VERSION 5.8 ;
BUSBITCHARS "[]" ;
DIVIDERCHAR "/" ;
UNITS
    DATABASE MICRONS 1000 ;
END UNITS

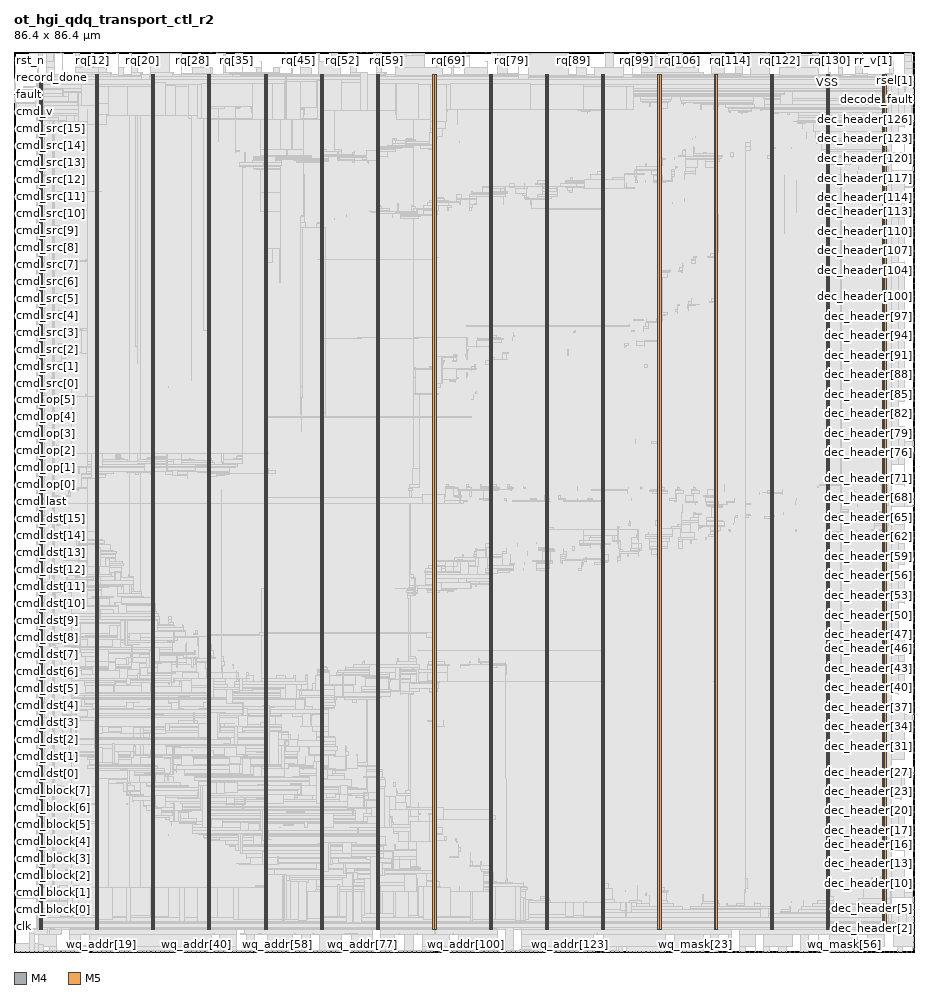
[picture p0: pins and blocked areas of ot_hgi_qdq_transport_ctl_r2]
MACRO ot_hgi_qdq_transport_ctl_r2
  FOREIGN ot_hgi_qdq_transport_ctl_r2 0 0 ;
  CLASS BLOCK ;
  SIZE 86.4 BY 86.4 ;
  PIN beat_done
    DIRECTION OUTPUT ;
    USE SIGNAL ;
    PORT
      LAYER M4 ;
        RECT  0 0.816 0.084 0.84 ;
    END
    PORT
      LAYER M4 ;
        RECT  0.06 0.816 0.181 0.84 ;
    END
  END beat_done
  PIN clk
    DIRECTION INPUT ;
    USE SIGNAL ;
    PORT
      LAYER M4 ;
        RECT  0 2.448 0.084 2.472 ;
    END
    PORT
      LAYER M4 ;
        RECT  0.06 2.448 0.227 2.472 ;
    END
  END clk
  PIN cmd_block[0]
    DIRECTION INPUT ;
    USE SIGNAL ;
    PORT
      LAYER M4 ;
        RECT  0 4.08 0.084 4.104 ;
    END
    PORT
      LAYER M4 ;
        RECT  0.06 4.08 0.097 4.104 ;
    END
  END cmd_block[0]
  PIN cmd_block[1]
    DIRECTION INPUT ;
    USE SIGNAL ;
    PORT
      LAYER M4 ;
        RECT  0 5.712 0.084 5.736 ;
    END
    PORT
      LAYER M4 ;
        RECT  0.06 5.712 0.277 5.736 ;
    END
  END cmd_block[1]
  PIN cmd_block[2]
    DIRECTION INPUT ;
    USE SIGNAL ;
    PORT
      LAYER M4 ;
        RECT  0 7.344 0.084 7.368 ;
    END
    PORT
      LAYER M4 ;
        RECT  0.06 7.344 2.408 7.368 ;
    END
  END cmd_block[2]
  PIN cmd_block[3]
    DIRECTION INPUT ;
    USE SIGNAL ;
    PORT
      LAYER M4 ;
        RECT  0 8.976 0.084 9 ;
    END
    PORT
      LAYER M4 ;
        RECT  0.06 8.976 2.408 9 ;
    END
  END cmd_block[3]
  PIN cmd_block[4]
    DIRECTION INPUT ;
    USE SIGNAL ;
    PORT
      LAYER M4 ;
        RECT  0 10.608 0.084 10.632 ;
    END
    PORT
      LAYER M4 ;
        RECT  0.06 10.608 2.408 10.632 ;
    END
  END cmd_block[4]
  PIN cmd_block[5]
    DIRECTION INPUT ;
    USE SIGNAL ;
    PORT
      LAYER M4 ;
        RECT  0 12.192 0.084 12.216 ;
    END
    PORT
      LAYER M4 ;
        RECT  0.06 12.192 2.408 12.216 ;
    END
  END cmd_block[5]
  PIN cmd_block[6]
    DIRECTION INPUT ;
    USE SIGNAL ;
    PORT
      LAYER M4 ;
        RECT  0 13.824 0.084 13.848 ;
    END
    PORT
      LAYER M4 ;
        RECT  0.06 13.824 2.408 13.848 ;
    END
  END cmd_block[6]
  PIN cmd_block[7]
    DIRECTION INPUT ;
    USE SIGNAL ;
    PORT
      LAYER M4 ;
        RECT  0 15.456 0.084 15.48 ;
    END
    PORT
      LAYER M4 ;
        RECT  0.06 15.456 2.408 15.48 ;
    END
  END cmd_block[7]
  PIN cmd_dst[0]
    DIRECTION INPUT ;
    USE SIGNAL ;
    PORT
      LAYER M4 ;
        RECT  0 17.088 0.084 17.112 ;
    END
    PORT
      LAYER M4 ;
        RECT  0.06 17.088 2.408 17.112 ;
    END
  END cmd_dst[0]
  PIN cmd_dst[10]
    DIRECTION INPUT ;
    USE SIGNAL ;
    PORT
      LAYER M4 ;
        RECT  0 33.408 0.084 33.432 ;
    END
    PORT
      LAYER M4 ;
        RECT  0.06 33.408 2.408 33.432 ;
    END
  END cmd_dst[10]
  PIN cmd_dst[11]
    DIRECTION INPUT ;
    USE SIGNAL ;
    PORT
      LAYER M4 ;
        RECT  0 35.04 0.084 35.064 ;
    END
    PORT
      LAYER M4 ;
        RECT  0.06 35.04 2.408 35.064 ;
    END
  END cmd_dst[11]
  PIN cmd_dst[12]
    DIRECTION INPUT ;
    USE SIGNAL ;
    PORT
      LAYER M4 ;
        RECT  0 36.672 0.084 36.696 ;
    END
    PORT
      LAYER M4 ;
        RECT  0.06 36.672 2.408 36.696 ;
    END
  END cmd_dst[12]
  PIN cmd_dst[13]
    DIRECTION INPUT ;
    USE SIGNAL ;
    PORT
      LAYER M4 ;
        RECT  0 38.304 0.084 38.328 ;
    END
    PORT
      LAYER M4 ;
        RECT  0.06 38.304 0.097 38.328 ;
    END
  END cmd_dst[13]
  PIN cmd_dst[14]
    DIRECTION INPUT ;
    USE SIGNAL ;
    PORT
      LAYER M4 ;
        RECT  0 39.936 0.084 39.96 ;
    END
    PORT
      LAYER M4 ;
        RECT  0.06 39.936 0.137 39.96 ;
    END
  END cmd_dst[14]
  PIN cmd_dst[15]
    DIRECTION INPUT ;
    USE SIGNAL ;
    PORT
      LAYER M4 ;
        RECT  0 41.568 0.084 41.592 ;
    END
    PORT
      LAYER M4 ;
        RECT  0.06 41.568 2.408 41.592 ;
    END
  END cmd_dst[15]
  PIN cmd_dst[1]
    DIRECTION INPUT ;
    USE SIGNAL ;
    PORT
      LAYER M4 ;
        RECT  0 18.72 0.084 18.744 ;
    END
    PORT
      LAYER M4 ;
        RECT  0.06 18.72 2.408 18.744 ;
    END
  END cmd_dst[1]
  PIN cmd_dst[2]
    DIRECTION INPUT ;
    USE SIGNAL ;
    PORT
      LAYER M4 ;
        RECT  0 20.352 0.084 20.376 ;
    END
    PORT
      LAYER M4 ;
        RECT  0.06 20.352 2.408 20.376 ;
    END
  END cmd_dst[2]
  PIN cmd_dst[3]
    DIRECTION INPUT ;
    USE SIGNAL ;
    PORT
      LAYER M4 ;
        RECT  0 21.984 0.084 22.008 ;
    END
    PORT
      LAYER M4 ;
        RECT  0.06 21.984 2.408 22.008 ;
    END
  END cmd_dst[3]
  PIN cmd_dst[4]
    DIRECTION INPUT ;
    USE SIGNAL ;
    PORT
      LAYER M4 ;
        RECT  0 23.616 0.084 23.64 ;
    END
    PORT
      LAYER M4 ;
        RECT  0.06 23.616 2.408 23.64 ;
    END
  END cmd_dst[4]
  PIN cmd_dst[5]
    DIRECTION INPUT ;
    USE SIGNAL ;
    PORT
      LAYER M4 ;
        RECT  0 25.248 0.084 25.272 ;
    END
    PORT
      LAYER M4 ;
        RECT  0.06 25.248 2.408 25.272 ;
    END
  END cmd_dst[5]
  PIN cmd_dst[6]
    DIRECTION INPUT ;
    USE SIGNAL ;
    PORT
      LAYER M4 ;
        RECT  0 26.88 0.084 26.904 ;
    END
    PORT
      LAYER M4 ;
        RECT  0.06 26.88 2.408 26.904 ;
    END
  END cmd_dst[6]
  PIN cmd_dst[7]
    DIRECTION INPUT ;
    USE SIGNAL ;
    PORT
      LAYER M4 ;
        RECT  0 28.512 0.084 28.536 ;
    END
    PORT
      LAYER M4 ;
        RECT  0.06 28.512 2.408 28.536 ;
    END
  END cmd_dst[7]
  PIN cmd_dst[8]
    DIRECTION INPUT ;
    USE SIGNAL ;
    PORT
      LAYER M4 ;
        RECT  0 30.144 0.084 30.168 ;
    END
    PORT
      LAYER M4 ;
        RECT  0.06 30.144 2.408 30.168 ;
    END
  END cmd_dst[8]
  PIN cmd_dst[9]
    DIRECTION INPUT ;
    USE SIGNAL ;
    PORT
      LAYER M4 ;
        RECT  0 31.776 0.084 31.8 ;
    END
    PORT
      LAYER M4 ;
        RECT  0.06 31.776 2.408 31.8 ;
    END
  END cmd_dst[9]
  PIN cmd_last
    DIRECTION INPUT ;
    USE SIGNAL ;
    PORT
      LAYER M4 ;
        RECT  0 43.2 0.084 43.224 ;
    END
    PORT
      LAYER M4 ;
        RECT  0.06 43.2 0.181 43.224 ;
    END
  END cmd_last
  PIN cmd_op[0]
    DIRECTION INPUT ;
    USE SIGNAL ;
    PORT
      LAYER M4 ;
        RECT  0 44.832 0.084 44.856 ;
    END
    PORT
      LAYER M4 ;
        RECT  0.06 44.832 2.408 44.856 ;
    END
  END cmd_op[0]
  PIN cmd_op[1]
    DIRECTION INPUT ;
    USE SIGNAL ;
    PORT
      LAYER M4 ;
        RECT  0 46.464 0.084 46.488 ;
    END
    PORT
      LAYER M4 ;
        RECT  0.06 46.464 2.408 46.488 ;
    END
  END cmd_op[1]
  PIN cmd_op[2]
    DIRECTION INPUT ;
    USE SIGNAL ;
    PORT
      LAYER M4 ;
        RECT  0 48.096 0.084 48.12 ;
    END
    PORT
      LAYER M4 ;
        RECT  0.06 48.096 2.408 48.12 ;
    END
  END cmd_op[2]
  PIN cmd_op[3]
    DIRECTION INPUT ;
    USE SIGNAL ;
    PORT
      LAYER M4 ;
        RECT  0 49.728 0.084 49.752 ;
    END
    PORT
      LAYER M4 ;
        RECT  0.06 49.728 2.408 49.752 ;
    END
  END cmd_op[3]
  PIN cmd_op[4]
    DIRECTION INPUT ;
    USE SIGNAL ;
    PORT
      LAYER M4 ;
        RECT  0 51.36 0.084 51.384 ;
    END
    PORT
      LAYER M4 ;
        RECT  0.06 51.36 2.408 51.384 ;
    END
  END cmd_op[4]
  PIN cmd_op[5]
    DIRECTION INPUT ;
    USE SIGNAL ;
    PORT
      LAYER M4 ;
        RECT  0 52.992 0.084 53.016 ;
    END
    PORT
      LAYER M4 ;
        RECT  0.06 52.992 2.408 53.016 ;
    END
  END cmd_op[5]
  PIN cmd_src[0]
    DIRECTION INPUT ;
    USE SIGNAL ;
    PORT
      LAYER M4 ;
        RECT  0 54.576 0.084 54.6 ;
    END
    PORT
      LAYER M4 ;
        RECT  0.06 54.576 2.408 54.6 ;
    END
  END cmd_src[0]
  PIN cmd_src[10]
    DIRECTION INPUT ;
    USE SIGNAL ;
    PORT
      LAYER M4 ;
        RECT  0 70.896 0.084 70.92 ;
    END
    PORT
      LAYER M4 ;
        RECT  0.06 70.896 2.408 70.92 ;
    END
  END cmd_src[10]
  PIN cmd_src[11]
    DIRECTION INPUT ;
    USE SIGNAL ;
    PORT
      LAYER M4 ;
        RECT  0 72.528 0.084 72.552 ;
    END
    PORT
      LAYER M4 ;
        RECT  0.06 72.528 2.408 72.552 ;
    END
  END cmd_src[11]
  PIN cmd_src[12]
    DIRECTION INPUT ;
    USE SIGNAL ;
    PORT
      LAYER M4 ;
        RECT  0 74.16 0.084 74.184 ;
    END
    PORT
      LAYER M4 ;
        RECT  0.06 74.16 2.408 74.184 ;
    END
  END cmd_src[12]
  PIN cmd_src[13]
    DIRECTION INPUT ;
    USE SIGNAL ;
    PORT
      LAYER M4 ;
        RECT  0 75.792 0.084 75.816 ;
    END
    PORT
      LAYER M4 ;
        RECT  0.06 75.792 2.408 75.816 ;
    END
  END cmd_src[13]
  PIN cmd_src[14]
    DIRECTION INPUT ;
    USE SIGNAL ;
    PORT
      LAYER M4 ;
        RECT  0 77.424 0.084 77.448 ;
    END
    PORT
      LAYER M4 ;
        RECT  0.06 77.424 2.408 77.448 ;
    END
  END cmd_src[14]
  PIN cmd_src[15]
    DIRECTION INPUT ;
    USE SIGNAL ;
    PORT
      LAYER M4 ;
        RECT  0 79.056 0.084 79.08 ;
    END
    PORT
      LAYER M4 ;
        RECT  0.06 79.056 2.408 79.08 ;
    END
  END cmd_src[15]
  PIN cmd_src[1]
    DIRECTION INPUT ;
    USE SIGNAL ;
    PORT
      LAYER M4 ;
        RECT  0 56.208 0.084 56.232 ;
    END
    PORT
      LAYER M4 ;
        RECT  0.06 56.208 2.408 56.232 ;
    END
  END cmd_src[1]
  PIN cmd_src[2]
    DIRECTION INPUT ;
    USE SIGNAL ;
    PORT
      LAYER M4 ;
        RECT  0 57.84 0.084 57.864 ;
    END
    PORT
      LAYER M4 ;
        RECT  0.06 57.84 2.408 57.864 ;
    END
  END cmd_src[2]
  PIN cmd_src[3]
    DIRECTION INPUT ;
    USE SIGNAL ;
    PORT
      LAYER M4 ;
        RECT  0 59.472 0.084 59.496 ;
    END
    PORT
      LAYER M4 ;
        RECT  0.06 59.472 2.408 59.496 ;
    END
  END cmd_src[3]
  PIN cmd_src[4]
    DIRECTION INPUT ;
    USE SIGNAL ;
    PORT
      LAYER M4 ;
        RECT  0 61.104 0.084 61.128 ;
    END
    PORT
      LAYER M4 ;
        RECT  0.06 61.104 2.408 61.128 ;
    END
  END cmd_src[4]
  PIN cmd_src[5]
    DIRECTION INPUT ;
    USE SIGNAL ;
    PORT
      LAYER M4 ;
        RECT  0 62.736 0.084 62.76 ;
    END
    PORT
      LAYER M4 ;
        RECT  0.06 62.736 2.408 62.76 ;
    END
  END cmd_src[5]
  PIN cmd_src[6]
    DIRECTION INPUT ;
    USE SIGNAL ;
    PORT
      LAYER M4 ;
        RECT  0 64.368 0.084 64.392 ;
    END
    PORT
      LAYER M4 ;
        RECT  0.06 64.368 2.408 64.392 ;
    END
  END cmd_src[6]
  PIN cmd_src[7]
    DIRECTION INPUT ;
    USE SIGNAL ;
    PORT
      LAYER M4 ;
        RECT  0 66 0.084 66.024 ;
    END
    PORT
      LAYER M4 ;
        RECT  0.06 66 2.408 66.024 ;
    END
  END cmd_src[7]
  PIN cmd_src[8]
    DIRECTION INPUT ;
    USE SIGNAL ;
    PORT
      LAYER M4 ;
        RECT  0 67.632 0.084 67.656 ;
    END
    PORT
      LAYER M4 ;
        RECT  0.06 67.632 2.408 67.656 ;
    END
  END cmd_src[8]
  PIN cmd_src[9]
    DIRECTION INPUT ;
    USE SIGNAL ;
    PORT
      LAYER M4 ;
        RECT  0 69.264 0.084 69.288 ;
    END
    PORT
      LAYER M4 ;
        RECT  0.06 69.264 2.408 69.288 ;
    END
  END cmd_src[9]
  PIN cmd_v
    DIRECTION INPUT ;
    USE SIGNAL ;
    PORT
      LAYER M4 ;
        RECT  0 80.688 0.084 80.712 ;
    END
    PORT
      LAYER M4 ;
        RECT  0.06 80.688 0.277 80.712 ;
    END
  END cmd_v
  PIN dec_header[0]
    DIRECTION OUTPUT ;
    USE SIGNAL ;
    PORT
      LAYER M4 ;
        RECT  86.316 0.288 86.4 0.312 ;
    END
  END dec_header[0]
  PIN dec_header[100]
    DIRECTION OUTPUT ;
    USE SIGNAL ;
    PORT
      LAYER M4 ;
        RECT  86.316 62.928 86.4 62.952 ;
    END
  END dec_header[100]
  PIN dec_header[101]
    DIRECTION OUTPUT ;
    USE SIGNAL ;
    PORT
      LAYER M4 ;
        RECT  86.316 63.552 86.4 63.576 ;
    END
  END dec_header[101]
  PIN dec_header[102]
    DIRECTION OUTPUT ;
    USE SIGNAL ;
    PORT
      LAYER M4 ;
        RECT  86.316 64.176 86.4 64.2 ;
    END
  END dec_header[102]
  PIN dec_header[103]
    DIRECTION OUTPUT ;
    USE SIGNAL ;
    PORT
      LAYER M4 ;
        RECT  86.316 64.8 86.4 64.824 ;
    END
  END dec_header[103]
  PIN dec_header[104]
    DIRECTION OUTPUT ;
    USE SIGNAL ;
    PORT
      LAYER M4 ;
        RECT  86.316 65.424 86.4 65.448 ;
    END
  END dec_header[104]
  PIN dec_header[105]
    DIRECTION OUTPUT ;
    USE SIGNAL ;
    PORT
      LAYER M4 ;
        RECT  86.316 66.048 86.4 66.072 ;
    END
  END dec_header[105]
  PIN dec_header[106]
    DIRECTION OUTPUT ;
    USE SIGNAL ;
    PORT
      LAYER M4 ;
        RECT  86.316 66.672 86.4 66.696 ;
    END
  END dec_header[106]
  PIN dec_header[107]
    DIRECTION OUTPUT ;
    USE SIGNAL ;
    PORT
      LAYER M4 ;
        RECT  86.316 67.296 86.4 67.32 ;
    END
  END dec_header[107]
  PIN dec_header[108]
    DIRECTION OUTPUT ;
    USE SIGNAL ;
    PORT
      LAYER M4 ;
        RECT  86.316 67.92 86.4 67.944 ;
    END
  END dec_header[108]
  PIN dec_header[109]
    DIRECTION OUTPUT ;
    USE SIGNAL ;
    PORT
      LAYER M4 ;
        RECT  86.316 68.544 86.4 68.568 ;
    END
  END dec_header[109]
  PIN dec_header[10]
    DIRECTION OUTPUT ;
    USE SIGNAL ;
    PORT
      LAYER M4 ;
        RECT  86.316 6.576 86.4 6.6 ;
    END
  END dec_header[10]
  PIN dec_header[110]
    DIRECTION OUTPUT ;
    USE SIGNAL ;
    PORT
      LAYER M4 ;
        RECT  86.316 69.168 86.4 69.192 ;
    END
  END dec_header[110]
  PIN dec_header[111]
    DIRECTION OUTPUT ;
    USE SIGNAL ;
    PORT
      LAYER M4 ;
        RECT  86.316 69.792 86.4 69.816 ;
    END
  END dec_header[111]
  PIN dec_header[112]
    DIRECTION OUTPUT ;
    USE SIGNAL ;
    PORT
      LAYER M4 ;
        RECT  86.316 70.416 86.4 70.44 ;
    END
  END dec_header[112]
  PIN dec_header[113]
    DIRECTION OUTPUT ;
    USE SIGNAL ;
    PORT
      LAYER M4 ;
        RECT  86.316 71.04 86.4 71.064 ;
    END
  END dec_header[113]
  PIN dec_header[114]
    DIRECTION OUTPUT ;
    USE SIGNAL ;
    PORT
      LAYER M4 ;
        RECT  86.316 71.664 86.4 71.688 ;
    END
  END dec_header[114]
  PIN dec_header[115]
    DIRECTION OUTPUT ;
    USE SIGNAL ;
    PORT
      LAYER M4 ;
        RECT  86.316 72.288 86.4 72.312 ;
    END
  END dec_header[115]
  PIN dec_header[116]
    DIRECTION OUTPUT ;
    USE SIGNAL ;
    PORT
      LAYER M4 ;
        RECT  86.316 72.912 86.4 72.936 ;
    END
  END dec_header[116]
  PIN dec_header[117]
    DIRECTION OUTPUT ;
    USE SIGNAL ;
    PORT
      LAYER M4 ;
        RECT  86.316 73.536 86.4 73.56 ;
    END
  END dec_header[117]
  PIN dec_header[118]
    DIRECTION OUTPUT ;
    USE SIGNAL ;
    PORT
      LAYER M4 ;
        RECT  86.316 74.16 86.4 74.184 ;
    END
  END dec_header[118]
  PIN dec_header[119]
    DIRECTION OUTPUT ;
    USE SIGNAL ;
    PORT
      LAYER M4 ;
        RECT  86.316 74.784 86.4 74.808 ;
    END
  END dec_header[119]
  PIN dec_header[11]
    DIRECTION OUTPUT ;
    USE SIGNAL ;
    PORT
      LAYER M4 ;
        RECT  86.316 7.2 86.4 7.224 ;
    END
  END dec_header[11]
  PIN dec_header[120]
    DIRECTION OUTPUT ;
    USE SIGNAL ;
    PORT
      LAYER M4 ;
        RECT  86.316 75.408 86.4 75.432 ;
    END
  END dec_header[120]
  PIN dec_header[121]
    DIRECTION OUTPUT ;
    USE SIGNAL ;
    PORT
      LAYER M4 ;
        RECT  86.316 76.08 86.4 76.104 ;
    END
  END dec_header[121]
  PIN dec_header[122]
    DIRECTION OUTPUT ;
    USE SIGNAL ;
    PORT
      LAYER M4 ;
        RECT  86.316 76.704 86.4 76.728 ;
    END
  END dec_header[122]
  PIN dec_header[123]
    DIRECTION OUTPUT ;
    USE SIGNAL ;
    PORT
      LAYER M4 ;
        RECT  86.316 77.328 86.4 77.352 ;
    END
  END dec_header[123]
  PIN dec_header[124]
    DIRECTION OUTPUT ;
    USE SIGNAL ;
    PORT
      LAYER M4 ;
        RECT  86.316 77.952 86.4 77.976 ;
    END
  END dec_header[124]
  PIN dec_header[125]
    DIRECTION OUTPUT ;
    USE SIGNAL ;
    PORT
      LAYER M4 ;
        RECT  86.316 78.576 86.4 78.6 ;
    END
  END dec_header[125]
  PIN dec_header[126]
    DIRECTION OUTPUT ;
    USE SIGNAL ;
    PORT
      LAYER M4 ;
        RECT  86.316 79.2 86.4 79.224 ;
    END
  END dec_header[126]
  PIN dec_header[127]
    DIRECTION OUTPUT ;
    USE SIGNAL ;
    PORT
      LAYER M4 ;
        RECT  86.316 79.824 86.4 79.848 ;
    END
  END dec_header[127]
  PIN dec_header[12]
    DIRECTION OUTPUT ;
    USE SIGNAL ;
    PORT
      LAYER M4 ;
        RECT  86.316 7.824 86.4 7.848 ;
    END
  END dec_header[12]
  PIN dec_header[13]
    DIRECTION OUTPUT ;
    USE SIGNAL ;
    PORT
      LAYER M4 ;
        RECT  86.316 8.448 86.4 8.472 ;
    END
  END dec_header[13]
  PIN dec_header[14]
    DIRECTION OUTPUT ;
    USE SIGNAL ;
    PORT
      LAYER M4 ;
        RECT  86.316 9.072 86.4 9.096 ;
    END
  END dec_header[14]
  PIN dec_header[15]
    DIRECTION OUTPUT ;
    USE SIGNAL ;
    PORT
      LAYER M4 ;
        RECT  86.316 9.696 86.4 9.72 ;
    END
  END dec_header[15]
  PIN dec_header[16]
    DIRECTION OUTPUT ;
    USE SIGNAL ;
    PORT
      LAYER M4 ;
        RECT  86.316 10.32 86.4 10.344 ;
    END
  END dec_header[16]
  PIN dec_header[17]
    DIRECTION OUTPUT ;
    USE SIGNAL ;
    PORT
      LAYER M4 ;
        RECT  86.316 10.944 86.4 10.968 ;
    END
  END dec_header[17]
  PIN dec_header[18]
    DIRECTION OUTPUT ;
    USE SIGNAL ;
    PORT
      LAYER M4 ;
        RECT  86.316 11.568 86.4 11.592 ;
    END
  END dec_header[18]
  PIN dec_header[19]
    DIRECTION OUTPUT ;
    USE SIGNAL ;
    PORT
      LAYER M4 ;
        RECT  86.316 12.192 86.4 12.216 ;
    END
  END dec_header[19]
  PIN dec_header[1]
    DIRECTION OUTPUT ;
    USE SIGNAL ;
    PORT
      LAYER M4 ;
        RECT  86.316 0.912 86.4 0.936 ;
    END
  END dec_header[1]
  PIN dec_header[20]
    DIRECTION OUTPUT ;
    USE SIGNAL ;
    PORT
      LAYER M4 ;
        RECT  86.316 12.816 86.4 12.84 ;
    END
  END dec_header[20]
  PIN dec_header[21]
    DIRECTION OUTPUT ;
    USE SIGNAL ;
    PORT
      LAYER M4 ;
        RECT  86.316 13.44 86.4 13.464 ;
    END
  END dec_header[21]
  PIN dec_header[22]
    DIRECTION OUTPUT ;
    USE SIGNAL ;
    PORT
      LAYER M4 ;
        RECT  86.316 14.064 86.4 14.088 ;
    END
  END dec_header[22]
  PIN dec_header[23]
    DIRECTION OUTPUT ;
    USE SIGNAL ;
    PORT
      LAYER M4 ;
        RECT  86.316 14.688 86.4 14.712 ;
    END
  END dec_header[23]
  PIN dec_header[24]
    DIRECTION OUTPUT ;
    USE SIGNAL ;
    PORT
      LAYER M4 ;
        RECT  86.316 15.312 86.4 15.336 ;
    END
  END dec_header[24]
  PIN dec_header[25]
    DIRECTION OUTPUT ;
    USE SIGNAL ;
    PORT
      LAYER M4 ;
        RECT  86.316 15.936 86.4 15.96 ;
    END
  END dec_header[25]
  PIN dec_header[26]
    DIRECTION OUTPUT ;
    USE SIGNAL ;
    PORT
      LAYER M4 ;
        RECT  86.316 16.56 86.4 16.584 ;
    END
  END dec_header[26]
  PIN dec_header[27]
    DIRECTION OUTPUT ;
    USE SIGNAL ;
    PORT
      LAYER M4 ;
        RECT  86.316 17.184 86.4 17.208 ;
    END
  END dec_header[27]
  PIN dec_header[28]
    DIRECTION OUTPUT ;
    USE SIGNAL ;
    PORT
      LAYER M4 ;
        RECT  86.316 17.808 86.4 17.832 ;
    END
  END dec_header[28]
  PIN dec_header[29]
    DIRECTION OUTPUT ;
    USE SIGNAL ;
    PORT
      LAYER M4 ;
        RECT  86.316 18.48 86.4 18.504 ;
    END
  END dec_header[29]
  PIN dec_header[2]
    DIRECTION OUTPUT ;
    USE SIGNAL ;
    PORT
      LAYER M4 ;
        RECT  86.316 1.536 86.4 1.56 ;
    END
  END dec_header[2]
  PIN dec_header[30]
    DIRECTION OUTPUT ;
    USE SIGNAL ;
    PORT
      LAYER M4 ;
        RECT  86.316 19.104 86.4 19.128 ;
    END
  END dec_header[30]
  PIN dec_header[31]
    DIRECTION OUTPUT ;
    USE SIGNAL ;
    PORT
      LAYER M4 ;
        RECT  86.316 19.728 86.4 19.752 ;
    END
  END dec_header[31]
  PIN dec_header[32]
    DIRECTION OUTPUT ;
    USE SIGNAL ;
    PORT
      LAYER M4 ;
        RECT  86.316 20.352 86.4 20.376 ;
    END
  END dec_header[32]
  PIN dec_header[33]
    DIRECTION OUTPUT ;
    USE SIGNAL ;
    PORT
      LAYER M4 ;
        RECT  86.316 20.976 86.4 21 ;
    END
  END dec_header[33]
  PIN dec_header[34]
    DIRECTION OUTPUT ;
    USE SIGNAL ;
    PORT
      LAYER M4 ;
        RECT  86.316 21.6 86.4 21.624 ;
    END
  END dec_header[34]
  PIN dec_header[35]
    DIRECTION OUTPUT ;
    USE SIGNAL ;
    PORT
      LAYER M4 ;
        RECT  86.316 22.224 86.4 22.248 ;
    END
  END dec_header[35]
  PIN dec_header[36]
    DIRECTION OUTPUT ;
    USE SIGNAL ;
    PORT
      LAYER M4 ;
        RECT  86.316 22.848 86.4 22.872 ;
    END
  END dec_header[36]
  PIN dec_header[37]
    DIRECTION OUTPUT ;
    USE SIGNAL ;
    PORT
      LAYER M4 ;
        RECT  86.316 23.472 86.4 23.496 ;
    END
  END dec_header[37]
  PIN dec_header[38]
    DIRECTION OUTPUT ;
    USE SIGNAL ;
    PORT
      LAYER M4 ;
        RECT  86.316 24.096 86.4 24.12 ;
    END
  END dec_header[38]
  PIN dec_header[39]
    DIRECTION OUTPUT ;
    USE SIGNAL ;
    PORT
      LAYER M4 ;
        RECT  86.316 24.72 86.4 24.744 ;
    END
  END dec_header[39]
  PIN dec_header[3]
    DIRECTION OUTPUT ;
    USE SIGNAL ;
    PORT
      LAYER M4 ;
        RECT  86.316 2.16 86.4 2.184 ;
    END
  END dec_header[3]
  PIN dec_header[40]
    DIRECTION OUTPUT ;
    USE SIGNAL ;
    PORT
      LAYER M4 ;
        RECT  86.316 25.344 86.4 25.368 ;
    END
  END dec_header[40]
  PIN dec_header[41]
    DIRECTION OUTPUT ;
    USE SIGNAL ;
    PORT
      LAYER M4 ;
        RECT  86.316 25.968 86.4 25.992 ;
    END
  END dec_header[41]
  PIN dec_header[42]
    DIRECTION OUTPUT ;
    USE SIGNAL ;
    PORT
      LAYER M4 ;
        RECT  86.316 26.592 86.4 26.616 ;
    END
  END dec_header[42]
  PIN dec_header[43]
    DIRECTION OUTPUT ;
    USE SIGNAL ;
    PORT
      LAYER M4 ;
        RECT  86.316 27.216 86.4 27.24 ;
    END
  END dec_header[43]
  PIN dec_header[44]
    DIRECTION OUTPUT ;
    USE SIGNAL ;
    PORT
      LAYER M4 ;
        RECT  86.316 27.84 86.4 27.864 ;
    END
  END dec_header[44]
  PIN dec_header[45]
    DIRECTION OUTPUT ;
    USE SIGNAL ;
    PORT
      LAYER M4 ;
        RECT  86.316 28.464 86.4 28.488 ;
    END
  END dec_header[45]
  PIN dec_header[46]
    DIRECTION OUTPUT ;
    USE SIGNAL ;
    PORT
      LAYER M4 ;
        RECT  86.316 29.088 86.4 29.112 ;
    END
  END dec_header[46]
  PIN dec_header[47]
    DIRECTION OUTPUT ;
    USE SIGNAL ;
    PORT
      LAYER M4 ;
        RECT  86.316 29.712 86.4 29.736 ;
    END
  END dec_header[47]
  PIN dec_header[48]
    DIRECTION OUTPUT ;
    USE SIGNAL ;
    PORT
      LAYER M4 ;
        RECT  86.316 30.336 86.4 30.36 ;
    END
  END dec_header[48]
  PIN dec_header[49]
    DIRECTION OUTPUT ;
    USE SIGNAL ;
    PORT
      LAYER M4 ;
        RECT  86.316 30.96 86.4 30.984 ;
    END
  END dec_header[49]
  PIN dec_header[4]
    DIRECTION OUTPUT ;
    USE SIGNAL ;
    PORT
      LAYER M4 ;
        RECT  86.316 2.784 86.4 2.808 ;
    END
  END dec_header[4]
  PIN dec_header[50]
    DIRECTION OUTPUT ;
    USE SIGNAL ;
    PORT
      LAYER M4 ;
        RECT  86.316 31.584 86.4 31.608 ;
    END
  END dec_header[50]
  PIN dec_header[51]
    DIRECTION OUTPUT ;
    USE SIGNAL ;
    PORT
      LAYER M4 ;
        RECT  86.316 32.208 86.4 32.232 ;
    END
  END dec_header[51]
  PIN dec_header[52]
    DIRECTION OUTPUT ;
    USE SIGNAL ;
    PORT
      LAYER M4 ;
        RECT  86.316 32.88 86.4 32.904 ;
    END
  END dec_header[52]
  PIN dec_header[53]
    DIRECTION OUTPUT ;
    USE SIGNAL ;
    PORT
      LAYER M4 ;
        RECT  86.316 33.504 86.4 33.528 ;
    END
  END dec_header[53]
  PIN dec_header[54]
    DIRECTION OUTPUT ;
    USE SIGNAL ;
    PORT
      LAYER M4 ;
        RECT  86.316 34.128 86.4 34.152 ;
    END
  END dec_header[54]
  PIN dec_header[55]
    DIRECTION OUTPUT ;
    USE SIGNAL ;
    PORT
      LAYER M4 ;
        RECT  86.316 34.752 86.4 34.776 ;
    END
  END dec_header[55]
  PIN dec_header[56]
    DIRECTION OUTPUT ;
    USE SIGNAL ;
    PORT
      LAYER M4 ;
        RECT  86.316 35.376 86.4 35.4 ;
    END
  END dec_header[56]
  PIN dec_header[57]
    DIRECTION OUTPUT ;
    USE SIGNAL ;
    PORT
      LAYER M4 ;
        RECT  86.316 36 86.4 36.024 ;
    END
  END dec_header[57]
  PIN dec_header[58]
    DIRECTION OUTPUT ;
    USE SIGNAL ;
    PORT
      LAYER M4 ;
        RECT  86.316 36.624 86.4 36.648 ;
    END
  END dec_header[58]
  PIN dec_header[59]
    DIRECTION OUTPUT ;
    USE SIGNAL ;
    PORT
      LAYER M4 ;
        RECT  86.316 37.248 86.4 37.272 ;
    END
  END dec_header[59]
  PIN dec_header[5]
    DIRECTION OUTPUT ;
    USE SIGNAL ;
    PORT
      LAYER M4 ;
        RECT  86.316 3.408 86.4 3.432 ;
    END
  END dec_header[5]
  PIN dec_header[60]
    DIRECTION OUTPUT ;
    USE SIGNAL ;
    PORT
      LAYER M4 ;
        RECT  86.316 37.872 86.4 37.896 ;
    END
  END dec_header[60]
  PIN dec_header[61]
    DIRECTION OUTPUT ;
    USE SIGNAL ;
    PORT
      LAYER M4 ;
        RECT  86.316 38.496 86.4 38.52 ;
    END
  END dec_header[61]
  PIN dec_header[62]
    DIRECTION OUTPUT ;
    USE SIGNAL ;
    PORT
      LAYER M4 ;
        RECT  86.316 39.12 86.4 39.144 ;
    END
  END dec_header[62]
  PIN dec_header[63]
    DIRECTION OUTPUT ;
    USE SIGNAL ;
    PORT
      LAYER M4 ;
        RECT  86.316 39.744 86.4 39.768 ;
    END
  END dec_header[63]
  PIN dec_header[64]
    DIRECTION OUTPUT ;
    USE SIGNAL ;
    PORT
      LAYER M4 ;
        RECT  86.316 40.368 86.4 40.392 ;
    END
  END dec_header[64]
  PIN dec_header[65]
    DIRECTION OUTPUT ;
    USE SIGNAL ;
    PORT
      LAYER M4 ;
        RECT  86.316 40.992 86.4 41.016 ;
    END
  END dec_header[65]
  PIN dec_header[66]
    DIRECTION OUTPUT ;
    USE SIGNAL ;
    PORT
      LAYER M4 ;
        RECT  86.316 41.616 86.4 41.64 ;
    END
  END dec_header[66]
  PIN dec_header[67]
    DIRECTION OUTPUT ;
    USE SIGNAL ;
    PORT
      LAYER M4 ;
        RECT  86.316 42.24 86.4 42.264 ;
    END
  END dec_header[67]
  PIN dec_header[68]
    DIRECTION OUTPUT ;
    USE SIGNAL ;
    PORT
      LAYER M4 ;
        RECT  86.316 42.864 86.4 42.888 ;
    END
  END dec_header[68]
  PIN dec_header[69]
    DIRECTION OUTPUT ;
    USE SIGNAL ;
    PORT
      LAYER M4 ;
        RECT  86.316 43.488 86.4 43.512 ;
    END
  END dec_header[69]
  PIN dec_header[6]
    DIRECTION OUTPUT ;
    USE SIGNAL ;
    PORT
      LAYER M4 ;
        RECT  86.316 4.08 86.4 4.104 ;
    END
  END dec_header[6]
  PIN dec_header[70]
    DIRECTION OUTPUT ;
    USE SIGNAL ;
    PORT
      LAYER M4 ;
        RECT  86.316 44.112 86.4 44.136 ;
    END
  END dec_header[70]
  PIN dec_header[71]
    DIRECTION OUTPUT ;
    USE SIGNAL ;
    PORT
      LAYER M4 ;
        RECT  86.316 44.736 86.4 44.76 ;
    END
  END dec_header[71]
  PIN dec_header[72]
    DIRECTION OUTPUT ;
    USE SIGNAL ;
    PORT
      LAYER M4 ;
        RECT  86.316 45.36 86.4 45.384 ;
    END
  END dec_header[72]
  PIN dec_header[73]
    DIRECTION OUTPUT ;
    USE SIGNAL ;
    PORT
      LAYER M4 ;
        RECT  86.316 45.984 86.4 46.008 ;
    END
  END dec_header[73]
  PIN dec_header[74]
    DIRECTION OUTPUT ;
    USE SIGNAL ;
    PORT
      LAYER M4 ;
        RECT  86.316 46.608 86.4 46.632 ;
    END
  END dec_header[74]
  PIN dec_header[75]
    DIRECTION OUTPUT ;
    USE SIGNAL ;
    PORT
      LAYER M4 ;
        RECT  86.316 47.28 86.4 47.304 ;
    END
  END dec_header[75]
  PIN dec_header[76]
    DIRECTION OUTPUT ;
    USE SIGNAL ;
    PORT
      LAYER M4 ;
        RECT  86.316 47.904 86.4 47.928 ;
    END
  END dec_header[76]
  PIN dec_header[77]
    DIRECTION OUTPUT ;
    USE SIGNAL ;
    PORT
      LAYER M4 ;
        RECT  86.316 48.528 86.4 48.552 ;
    END
  END dec_header[77]
  PIN dec_header[78]
    DIRECTION OUTPUT ;
    USE SIGNAL ;
    PORT
      LAYER M4 ;
        RECT  86.316 49.152 86.4 49.176 ;
    END
  END dec_header[78]
  PIN dec_header[79]
    DIRECTION OUTPUT ;
    USE SIGNAL ;
    PORT
      LAYER M4 ;
        RECT  86.316 49.776 86.4 49.8 ;
    END
  END dec_header[79]
  PIN dec_header[7]
    DIRECTION OUTPUT ;
    USE SIGNAL ;
    PORT
      LAYER M4 ;
        RECT  86.316 4.704 86.4 4.728 ;
    END
  END dec_header[7]
  PIN dec_header[80]
    DIRECTION OUTPUT ;
    USE SIGNAL ;
    PORT
      LAYER M4 ;
        RECT  86.316 50.4 86.4 50.424 ;
    END
  END dec_header[80]
  PIN dec_header[81]
    DIRECTION OUTPUT ;
    USE SIGNAL ;
    PORT
      LAYER M4 ;
        RECT  86.316 51.024 86.4 51.048 ;
    END
  END dec_header[81]
  PIN dec_header[82]
    DIRECTION OUTPUT ;
    USE SIGNAL ;
    PORT
      LAYER M4 ;
        RECT  86.316 51.648 86.4 51.672 ;
    END
  END dec_header[82]
  PIN dec_header[83]
    DIRECTION OUTPUT ;
    USE SIGNAL ;
    PORT
      LAYER M4 ;
        RECT  86.316 52.272 86.4 52.296 ;
    END
  END dec_header[83]
  PIN dec_header[84]
    DIRECTION OUTPUT ;
    USE SIGNAL ;
    PORT
      LAYER M4 ;
        RECT  86.316 52.896 86.4 52.92 ;
    END
  END dec_header[84]
  PIN dec_header[85]
    DIRECTION OUTPUT ;
    USE SIGNAL ;
    PORT
      LAYER M4 ;
        RECT  86.316 53.52 86.4 53.544 ;
    END
  END dec_header[85]
  PIN dec_header[86]
    DIRECTION OUTPUT ;
    USE SIGNAL ;
    PORT
      LAYER M4 ;
        RECT  86.316 54.144 86.4 54.168 ;
    END
  END dec_header[86]
  PIN dec_header[87]
    DIRECTION OUTPUT ;
    USE SIGNAL ;
    PORT
      LAYER M4 ;
        RECT  86.316 54.768 86.4 54.792 ;
    END
  END dec_header[87]
  PIN dec_header[88]
    DIRECTION OUTPUT ;
    USE SIGNAL ;
    PORT
      LAYER M4 ;
        RECT  86.316 55.392 86.4 55.416 ;
    END
  END dec_header[88]
  PIN dec_header[89]
    DIRECTION OUTPUT ;
    USE SIGNAL ;
    PORT
      LAYER M4 ;
        RECT  86.316 56.016 86.4 56.04 ;
    END
  END dec_header[89]
  PIN dec_header[8]
    DIRECTION OUTPUT ;
    USE SIGNAL ;
    PORT
      LAYER M4 ;
        RECT  86.316 5.328 86.4 5.352 ;
    END
  END dec_header[8]
  PIN dec_header[90]
    DIRECTION OUTPUT ;
    USE SIGNAL ;
    PORT
      LAYER M4 ;
        RECT  86.316 56.64 86.4 56.664 ;
    END
  END dec_header[90]
  PIN dec_header[91]
    DIRECTION OUTPUT ;
    USE SIGNAL ;
    PORT
      LAYER M4 ;
        RECT  86.316 57.264 86.4 57.288 ;
    END
  END dec_header[91]
  PIN dec_header[92]
    DIRECTION OUTPUT ;
    USE SIGNAL ;
    PORT
      LAYER M4 ;
        RECT  86.316 57.888 86.4 57.912 ;
    END
  END dec_header[92]
  PIN dec_header[93]
    DIRECTION OUTPUT ;
    USE SIGNAL ;
    PORT
      LAYER M4 ;
        RECT  86.316 58.512 86.4 58.536 ;
    END
  END dec_header[93]
  PIN dec_header[94]
    DIRECTION OUTPUT ;
    USE SIGNAL ;
    PORT
      LAYER M4 ;
        RECT  86.316 59.136 86.4 59.16 ;
    END
  END dec_header[94]
  PIN dec_header[95]
    DIRECTION OUTPUT ;
    USE SIGNAL ;
    PORT
      LAYER M4 ;
        RECT  86.316 59.76 86.4 59.784 ;
    END
  END dec_header[95]
  PIN dec_header[96]
    DIRECTION OUTPUT ;
    USE SIGNAL ;
    PORT
      LAYER M4 ;
        RECT  86.316 60.384 86.4 60.408 ;
    END
  END dec_header[96]
  PIN dec_header[97]
    DIRECTION OUTPUT ;
    USE SIGNAL ;
    PORT
      LAYER M4 ;
        RECT  86.316 61.008 86.4 61.032 ;
    END
  END dec_header[97]
  PIN dec_header[98]
    DIRECTION OUTPUT ;
    USE SIGNAL ;
    PORT
      LAYER M4 ;
        RECT  86.316 61.68 86.4 61.704 ;
    END
  END dec_header[98]
  PIN dec_header[99]
    DIRECTION OUTPUT ;
    USE SIGNAL ;
    PORT
      LAYER M4 ;
        RECT  86.316 62.304 86.4 62.328 ;
    END
  END dec_header[99]
  PIN dec_header[9]
    DIRECTION OUTPUT ;
    USE SIGNAL ;
    PORT
      LAYER M4 ;
        RECT  86.316 5.952 86.4 5.976 ;
    END
  END dec_header[9]
  PIN dec_v
    DIRECTION OUTPUT ;
    USE SIGNAL ;
    PORT
      LAYER M4 ;
        RECT  86.316 80.448 86.4 80.472 ;
    END
  END dec_v
  PIN decode_fault
    DIRECTION INPUT ;
    USE SIGNAL ;
    PORT
      LAYER M4 ;
        RECT  86.316 81.072 86.4 81.096 ;
    END
  END decode_fault
  PIN fault
    DIRECTION OUTPUT ;
    USE SIGNAL ;
    PORT
      LAYER M4 ;
        RECT  0 82.32 0.084 82.344 ;
    END
    PORT
      LAYER M4 ;
        RECT  0.06 82.32 0.137 82.344 ;
    END
  END fault
  PIN qfault
    DIRECTION INPUT ;
    USE SIGNAL ;
    PORT
      LAYER M4 ;
        RECT  86.316 81.696 86.4 81.72 ;
    END
  END qfault
  PIN record_done
    DIRECTION OUTPUT ;
    USE SIGNAL ;
    PORT
      LAYER M4 ;
        RECT  0 83.952 0.084 83.976 ;
    END
    PORT
      LAYER M4 ;
        RECT  0.06 83.952 0.061 83.976 ;
    END
    PORT
      LAYER M4 ;
        RECT  0.061 83.856 0.173 83.976 ;
    END
  END record_done
  PIN rq[0]
    DIRECTION OUTPUT ;
    USE SIGNAL ;
    PORT
      LAYER M5 ;
        RECT  0.288 86.316 0.312 86.4 ;
    END
  END rq[0]
  PIN rq[100]
    DIRECTION OUTPUT ;
    USE SIGNAL ;
    PORT
      LAYER M5 ;
        RECT  60.288 86.316 60.312 86.4 ;
    END
  END rq[100]
  PIN rq[101]
    DIRECTION OUTPUT ;
    USE SIGNAL ;
    PORT
      LAYER M5 ;
        RECT  60.912 86.316 60.936 86.4 ;
    END
  END rq[101]
  PIN rq[102]
    DIRECTION OUTPUT ;
    USE SIGNAL ;
    PORT
      LAYER M5 ;
        RECT  61.488 86.316 61.512 86.4 ;
    END
  END rq[102]
  PIN rq[103]
    DIRECTION OUTPUT ;
    USE SIGNAL ;
    PORT
      LAYER M5 ;
        RECT  62.112 86.316 62.136 86.4 ;
    END
  END rq[103]
  PIN rq[104]
    DIRECTION OUTPUT ;
    USE SIGNAL ;
    PORT
      LAYER M5 ;
        RECT  62.688 86.316 62.712 86.4 ;
    END
  END rq[104]
  PIN rq[105]
    DIRECTION OUTPUT ;
    USE SIGNAL ;
    PORT
      LAYER M5 ;
        RECT  63.312 86.316 63.336 86.4 ;
    END
  END rq[105]
  PIN rq[106]
    DIRECTION OUTPUT ;
    USE SIGNAL ;
    PORT
      LAYER M5 ;
        RECT  63.888 86.316 63.912 86.4 ;
    END
  END rq[106]
  PIN rq[107]
    DIRECTION OUTPUT ;
    USE SIGNAL ;
    PORT
      LAYER M5 ;
        RECT  64.512 86.316 64.536 86.4 ;
    END
  END rq[107]
  PIN rq[108]
    DIRECTION OUTPUT ;
    USE SIGNAL ;
    PORT
      LAYER M5 ;
        RECT  65.088 86.316 65.112 86.4 ;
    END
  END rq[108]
  PIN rq[109]
    DIRECTION OUTPUT ;
    USE SIGNAL ;
    PORT
      LAYER M5 ;
        RECT  65.712 86.316 65.736 86.4 ;
    END
  END rq[109]
  PIN rq[10]
    DIRECTION OUTPUT ;
    USE SIGNAL ;
    PORT
      LAYER M5 ;
        RECT  6.288 86.316 6.312 86.4 ;
    END
  END rq[10]
  PIN rq[110]
    DIRECTION OUTPUT ;
    USE SIGNAL ;
    PORT
      LAYER M5 ;
        RECT  66.288 86.316 66.312 86.4 ;
    END
  END rq[110]
  PIN rq[111]
    DIRECTION OUTPUT ;
    USE SIGNAL ;
    PORT
      LAYER M5 ;
        RECT  66.912 86.316 66.936 86.4 ;
    END
  END rq[111]
  PIN rq[112]
    DIRECTION OUTPUT ;
    USE SIGNAL ;
    PORT
      LAYER M5 ;
        RECT  67.488 86.316 67.512 86.4 ;
    END
  END rq[112]
  PIN rq[113]
    DIRECTION OUTPUT ;
    USE SIGNAL ;
    PORT
      LAYER M5 ;
        RECT  68.112 86.316 68.136 86.4 ;
    END
  END rq[113]
  PIN rq[114]
    DIRECTION OUTPUT ;
    USE SIGNAL ;
    PORT
      LAYER M5 ;
        RECT  68.688 86.316 68.712 86.4 ;
    END
  END rq[114]
  PIN rq[115]
    DIRECTION OUTPUT ;
    USE SIGNAL ;
    PORT
      LAYER M5 ;
        RECT  69.312 86.316 69.336 86.4 ;
    END
  END rq[115]
  PIN rq[116]
    DIRECTION OUTPUT ;
    USE SIGNAL ;
    PORT
      LAYER M5 ;
        RECT  69.888 86.316 69.912 86.4 ;
    END
  END rq[116]
  PIN rq[117]
    DIRECTION OUTPUT ;
    USE SIGNAL ;
    PORT
      LAYER M5 ;
        RECT  70.512 86.316 70.536 86.4 ;
    END
  END rq[117]
  PIN rq[118]
    DIRECTION OUTPUT ;
    USE SIGNAL ;
    PORT
      LAYER M5 ;
        RECT  71.088 86.316 71.112 86.4 ;
    END
  END rq[118]
  PIN rq[119]
    DIRECTION OUTPUT ;
    USE SIGNAL ;
    PORT
      LAYER M5 ;
        RECT  71.712 86.316 71.736 86.4 ;
    END
  END rq[119]
  PIN rq[11]
    DIRECTION OUTPUT ;
    USE SIGNAL ;
    PORT
      LAYER M5 ;
        RECT  6.912 86.316 6.936 86.4 ;
    END
  END rq[11]
  PIN rq[120]
    DIRECTION OUTPUT ;
    USE SIGNAL ;
    PORT
      LAYER M5 ;
        RECT  72.288 86.316 72.312 86.4 ;
    END
  END rq[120]
  PIN rq[121]
    DIRECTION OUTPUT ;
    USE SIGNAL ;
    PORT
      LAYER M5 ;
        RECT  72.912 86.316 72.936 86.4 ;
    END
  END rq[121]
  PIN rq[122]
    DIRECTION OUTPUT ;
    USE SIGNAL ;
    PORT
      LAYER M5 ;
        RECT  73.488 86.316 73.512 86.4 ;
    END
  END rq[122]
  PIN rq[123]
    DIRECTION OUTPUT ;
    USE SIGNAL ;
    PORT
      LAYER M5 ;
        RECT  74.112 86.316 74.136 86.4 ;
    END
  END rq[123]
  PIN rq[124]
    DIRECTION OUTPUT ;
    USE SIGNAL ;
    PORT
      LAYER M5 ;
        RECT  74.688 86.316 74.712 86.4 ;
    END
  END rq[124]
  PIN rq[125]
    DIRECTION OUTPUT ;
    USE SIGNAL ;
    PORT
      LAYER M5 ;
        RECT  75.312 86.316 75.336 86.4 ;
    END
  END rq[125]
  PIN rq[126]
    DIRECTION OUTPUT ;
    USE SIGNAL ;
    PORT
      LAYER M5 ;
        RECT  75.888 86.316 75.912 86.4 ;
    END
  END rq[126]
  PIN rq[127]
    DIRECTION OUTPUT ;
    USE SIGNAL ;
    PORT
      LAYER M5 ;
        RECT  76.512 86.316 76.536 86.4 ;
    END
  END rq[127]
  PIN rq[128]
    DIRECTION OUTPUT ;
    USE SIGNAL ;
    PORT
      LAYER M5 ;
        RECT  77.088 86.316 77.112 86.4 ;
    END
  END rq[128]
  PIN rq[129]
    DIRECTION OUTPUT ;
    USE SIGNAL ;
    PORT
      LAYER M5 ;
        RECT  77.712 86.316 77.736 86.4 ;
    END
  END rq[129]
  PIN rq[12]
    DIRECTION OUTPUT ;
    USE SIGNAL ;
    PORT
      LAYER M5 ;
        RECT  7.488 86.316 7.512 86.4 ;
    END
  END rq[12]
  PIN rq[130]
    DIRECTION OUTPUT ;
    USE SIGNAL ;
    PORT
      LAYER M5 ;
        RECT  78.288 86.316 78.312 86.4 ;
    END
  END rq[130]
  PIN rq[131]
    DIRECTION OUTPUT ;
    USE SIGNAL ;
    PORT
      LAYER M5 ;
        RECT  78.912 86.316 78.936 86.4 ;
    END
  END rq[131]
  PIN rq[132]
    DIRECTION OUTPUT ;
    USE SIGNAL ;
    PORT
      LAYER M5 ;
        RECT  79.488 86.316 79.512 86.4 ;
    END
  END rq[132]
  PIN rq[133]
    DIRECTION OUTPUT ;
    USE SIGNAL ;
    PORT
      LAYER M5 ;
        RECT  80.112 86.316 80.136 86.4 ;
    END
  END rq[133]
  PIN rq[134]
    DIRECTION OUTPUT ;
    USE SIGNAL ;
    PORT
      LAYER M5 ;
        RECT  80.688 86.316 80.712 86.4 ;
    END
  END rq[134]
  PIN rq[135]
    DIRECTION OUTPUT ;
    USE SIGNAL ;
    PORT
      LAYER M5 ;
        RECT  81.312 86.316 81.336 86.4 ;
    END
  END rq[135]
  PIN rq[13]
    DIRECTION OUTPUT ;
    USE SIGNAL ;
    PORT
      LAYER M5 ;
        RECT  8.112 86.316 8.136 86.4 ;
    END
  END rq[13]
  PIN rq[14]
    DIRECTION OUTPUT ;
    USE SIGNAL ;
    PORT
      LAYER M5 ;
        RECT  8.688 86.316 8.712 86.4 ;
    END
  END rq[14]
  PIN rq[15]
    DIRECTION OUTPUT ;
    USE SIGNAL ;
    PORT
      LAYER M5 ;
        RECT  9.312 86.316 9.336 86.4 ;
    END
  END rq[15]
  PIN rq[16]
    DIRECTION OUTPUT ;
    USE SIGNAL ;
    PORT
      LAYER M5 ;
        RECT  9.888 86.316 9.912 86.4 ;
    END
  END rq[16]
  PIN rq[17]
    DIRECTION OUTPUT ;
    USE SIGNAL ;
    PORT
      LAYER M5 ;
        RECT  10.512 86.316 10.536 86.4 ;
    END
  END rq[17]
  PIN rq[18]
    DIRECTION OUTPUT ;
    USE SIGNAL ;
    PORT
      LAYER M5 ;
        RECT  11.088 86.316 11.112 86.4 ;
    END
  END rq[18]
  PIN rq[19]
    DIRECTION OUTPUT ;
    USE SIGNAL ;
    PORT
      LAYER M5 ;
        RECT  11.712 86.316 11.736 86.4 ;
    END
  END rq[19]
  PIN rq[1]
    DIRECTION OUTPUT ;
    USE SIGNAL ;
    PORT
      LAYER M5 ;
        RECT  0.912 86.316 0.936 86.4 ;
    END
  END rq[1]
  PIN rq[20]
    DIRECTION OUTPUT ;
    USE SIGNAL ;
    PORT
      LAYER M5 ;
        RECT  12.288 86.316 12.312 86.4 ;
    END
  END rq[20]
  PIN rq[21]
    DIRECTION OUTPUT ;
    USE SIGNAL ;
    PORT
      LAYER M5 ;
        RECT  12.912 86.316 12.936 86.4 ;
    END
  END rq[21]
  PIN rq[22]
    DIRECTION OUTPUT ;
    USE SIGNAL ;
    PORT
      LAYER M5 ;
        RECT  13.488 86.316 13.512 86.4 ;
    END
  END rq[22]
  PIN rq[23]
    DIRECTION OUTPUT ;
    USE SIGNAL ;
    PORT
      LAYER M5 ;
        RECT  14.112 86.316 14.136 86.4 ;
    END
  END rq[23]
  PIN rq[24]
    DIRECTION OUTPUT ;
    USE SIGNAL ;
    PORT
      LAYER M5 ;
        RECT  14.688 86.316 14.712 86.4 ;
    END
  END rq[24]
  PIN rq[25]
    DIRECTION OUTPUT ;
    USE SIGNAL ;
    PORT
      LAYER M5 ;
        RECT  15.312 86.316 15.336 86.4 ;
    END
  END rq[25]
  PIN rq[26]
    DIRECTION OUTPUT ;
    USE SIGNAL ;
    PORT
      LAYER M5 ;
        RECT  15.888 86.316 15.912 86.4 ;
    END
  END rq[26]
  PIN rq[27]
    DIRECTION OUTPUT ;
    USE SIGNAL ;
    PORT
      LAYER M5 ;
        RECT  16.512 86.316 16.536 86.4 ;
    END
  END rq[27]
  PIN rq[28]
    DIRECTION OUTPUT ;
    USE SIGNAL ;
    PORT
      LAYER M5 ;
        RECT  17.088 86.316 17.112 86.4 ;
    END
  END rq[28]
  PIN rq[29]
    DIRECTION OUTPUT ;
    USE SIGNAL ;
    PORT
      LAYER M5 ;
        RECT  17.712 86.316 17.736 86.4 ;
    END
  END rq[29]
  PIN rq[2]
    DIRECTION OUTPUT ;
    USE SIGNAL ;
    PORT
      LAYER M5 ;
        RECT  1.488 86.316 1.512 86.4 ;
    END
  END rq[2]
  PIN rq[30]
    DIRECTION OUTPUT ;
    USE SIGNAL ;
    PORT
      LAYER M5 ;
        RECT  18.288 86.316 18.312 86.4 ;
    END
  END rq[30]
  PIN rq[31]
    DIRECTION OUTPUT ;
    USE SIGNAL ;
    PORT
      LAYER M5 ;
        RECT  18.912 86.316 18.936 86.4 ;
    END
  END rq[31]
  PIN rq[32]
    DIRECTION OUTPUT ;
    USE SIGNAL ;
    PORT
      LAYER M5 ;
        RECT  19.488 86.316 19.512 86.4 ;
    END
  END rq[32]
  PIN rq[33]
    DIRECTION OUTPUT ;
    USE SIGNAL ;
    PORT
      LAYER M5 ;
        RECT  20.112 86.316 20.136 86.4 ;
    END
  END rq[33]
  PIN rq[34]
    DIRECTION OUTPUT ;
    USE SIGNAL ;
    PORT
      LAYER M5 ;
        RECT  20.688 86.316 20.712 86.4 ;
    END
  END rq[34]
  PIN rq[35]
    DIRECTION OUTPUT ;
    USE SIGNAL ;
    PORT
      LAYER M5 ;
        RECT  21.312 86.316 21.336 86.4 ;
    END
  END rq[35]
  PIN rq[36]
    DIRECTION OUTPUT ;
    USE SIGNAL ;
    PORT
      LAYER M5 ;
        RECT  21.888 86.316 21.912 86.4 ;
    END
  END rq[36]
  PIN rq[37]
    DIRECTION OUTPUT ;
    USE SIGNAL ;
    PORT
      LAYER M5 ;
        RECT  22.512 86.316 22.536 86.4 ;
    END
  END rq[37]
  PIN rq[38]
    DIRECTION OUTPUT ;
    USE SIGNAL ;
    PORT
      LAYER M5 ;
        RECT  23.088 86.316 23.112 86.4 ;
    END
  END rq[38]
  PIN rq[39]
    DIRECTION OUTPUT ;
    USE SIGNAL ;
    PORT
      LAYER M5 ;
        RECT  23.712 86.316 23.736 86.4 ;
    END
  END rq[39]
  PIN rq[3]
    DIRECTION OUTPUT ;
    USE SIGNAL ;
    PORT
      LAYER M5 ;
        RECT  2.112 86.316 2.136 86.4 ;
    END
  END rq[3]
  PIN rq[40]
    DIRECTION OUTPUT ;
    USE SIGNAL ;
    PORT
      LAYER M5 ;
        RECT  24.288 86.316 24.312 86.4 ;
    END
  END rq[40]
  PIN rq[41]
    DIRECTION OUTPUT ;
    USE SIGNAL ;
    PORT
      LAYER M5 ;
        RECT  24.912 86.316 24.936 86.4 ;
    END
  END rq[41]
  PIN rq[42]
    DIRECTION OUTPUT ;
    USE SIGNAL ;
    PORT
      LAYER M5 ;
        RECT  25.488 86.316 25.512 86.4 ;
    END
  END rq[42]
  PIN rq[43]
    DIRECTION OUTPUT ;
    USE SIGNAL ;
    PORT
      LAYER M5 ;
        RECT  26.112 86.316 26.136 86.4 ;
    END
  END rq[43]
  PIN rq[44]
    DIRECTION OUTPUT ;
    USE SIGNAL ;
    PORT
      LAYER M5 ;
        RECT  26.688 86.316 26.712 86.4 ;
    END
  END rq[44]
  PIN rq[45]
    DIRECTION OUTPUT ;
    USE SIGNAL ;
    PORT
      LAYER M5 ;
        RECT  27.312 86.316 27.336 86.4 ;
    END
  END rq[45]
  PIN rq[46]
    DIRECTION OUTPUT ;
    USE SIGNAL ;
    PORT
      LAYER M5 ;
        RECT  27.888 86.316 27.912 86.4 ;
    END
  END rq[46]
  PIN rq[47]
    DIRECTION OUTPUT ;
    USE SIGNAL ;
    PORT
      LAYER M5 ;
        RECT  28.512 86.316 28.536 86.4 ;
    END
  END rq[47]
  PIN rq[48]
    DIRECTION OUTPUT ;
    USE SIGNAL ;
    PORT
      LAYER M5 ;
        RECT  29.088 86.316 29.112 86.4 ;
    END
  END rq[48]
  PIN rq[49]
    DIRECTION OUTPUT ;
    USE SIGNAL ;
    PORT
      LAYER M5 ;
        RECT  29.712 86.316 29.736 86.4 ;
    END
  END rq[49]
  PIN rq[4]
    DIRECTION OUTPUT ;
    USE SIGNAL ;
    PORT
      LAYER M5 ;
        RECT  2.688 86.316 2.712 86.4 ;
    END
  END rq[4]
  PIN rq[50]
    DIRECTION OUTPUT ;
    USE SIGNAL ;
    PORT
      LAYER M5 ;
        RECT  30.288 86.316 30.312 86.4 ;
    END
  END rq[50]
  PIN rq[51]
    DIRECTION OUTPUT ;
    USE SIGNAL ;
    PORT
      LAYER M5 ;
        RECT  30.912 86.316 30.936 86.4 ;
    END
  END rq[51]
  PIN rq[52]
    DIRECTION OUTPUT ;
    USE SIGNAL ;
    PORT
      LAYER M5 ;
        RECT  31.488 86.316 31.512 86.4 ;
    END
  END rq[52]
  PIN rq[53]
    DIRECTION OUTPUT ;
    USE SIGNAL ;
    PORT
      LAYER M5 ;
        RECT  32.112 86.316 32.136 86.4 ;
    END
  END rq[53]
  PIN rq[54]
    DIRECTION OUTPUT ;
    USE SIGNAL ;
    PORT
      LAYER M5 ;
        RECT  32.688 86.316 32.712 86.4 ;
    END
  END rq[54]
  PIN rq[55]
    DIRECTION OUTPUT ;
    USE SIGNAL ;
    PORT
      LAYER M5 ;
        RECT  33.312 86.316 33.336 86.4 ;
    END
  END rq[55]
  PIN rq[56]
    DIRECTION OUTPUT ;
    USE SIGNAL ;
    PORT
      LAYER M5 ;
        RECT  33.888 86.316 33.912 86.4 ;
    END
  END rq[56]
  PIN rq[57]
    DIRECTION OUTPUT ;
    USE SIGNAL ;
    PORT
      LAYER M5 ;
        RECT  34.512 86.316 34.536 86.4 ;
    END
  END rq[57]
  PIN rq[58]
    DIRECTION OUTPUT ;
    USE SIGNAL ;
    PORT
      LAYER M5 ;
        RECT  35.088 86.316 35.112 86.4 ;
    END
  END rq[58]
  PIN rq[59]
    DIRECTION OUTPUT ;
    USE SIGNAL ;
    PORT
      LAYER M5 ;
        RECT  35.712 86.316 35.736 86.4 ;
    END
  END rq[59]
  PIN rq[5]
    DIRECTION OUTPUT ;
    USE SIGNAL ;
    PORT
      LAYER M5 ;
        RECT  3.312 86.316 3.336 86.4 ;
    END
  END rq[5]
  PIN rq[60]
    DIRECTION OUTPUT ;
    USE SIGNAL ;
    PORT
      LAYER M5 ;
        RECT  36.288 86.316 36.312 86.4 ;
    END
  END rq[60]
  PIN rq[61]
    DIRECTION OUTPUT ;
    USE SIGNAL ;
    PORT
      LAYER M5 ;
        RECT  36.912 86.316 36.936 86.4 ;
    END
  END rq[61]
  PIN rq[62]
    DIRECTION OUTPUT ;
    USE SIGNAL ;
    PORT
      LAYER M5 ;
        RECT  37.488 86.316 37.512 86.4 ;
    END
  END rq[62]
  PIN rq[63]
    DIRECTION OUTPUT ;
    USE SIGNAL ;
    PORT
      LAYER M5 ;
        RECT  38.112 86.316 38.136 86.4 ;
    END
  END rq[63]
  PIN rq[64]
    DIRECTION OUTPUT ;
    USE SIGNAL ;
    PORT
      LAYER M5 ;
        RECT  38.688 86.316 38.712 86.4 ;
    END
  END rq[64]
  PIN rq[65]
    DIRECTION OUTPUT ;
    USE SIGNAL ;
    PORT
      LAYER M5 ;
        RECT  39.312 86.316 39.336 86.4 ;
    END
  END rq[65]
  PIN rq[66]
    DIRECTION OUTPUT ;
    USE SIGNAL ;
    PORT
      LAYER M5 ;
        RECT  39.888 86.316 39.912 86.4 ;
    END
  END rq[66]
  PIN rq[67]
    DIRECTION OUTPUT ;
    USE SIGNAL ;
    PORT
      LAYER M5 ;
        RECT  40.512 86.316 40.536 86.4 ;
    END
  END rq[67]
  PIN rq[68]
    DIRECTION OUTPUT ;
    USE SIGNAL ;
    PORT
      LAYER M5 ;
        RECT  41.088 86.316 41.112 86.4 ;
    END
  END rq[68]
  PIN rq[69]
    DIRECTION OUTPUT ;
    USE SIGNAL ;
    PORT
      LAYER M5 ;
        RECT  41.712 86.316 41.736 86.4 ;
    END
  END rq[69]
  PIN rq[6]
    DIRECTION OUTPUT ;
    USE SIGNAL ;
    PORT
      LAYER M5 ;
        RECT  3.888 86.316 3.912 86.4 ;
    END
  END rq[6]
  PIN rq[70]
    DIRECTION OUTPUT ;
    USE SIGNAL ;
    PORT
      LAYER M5 ;
        RECT  42.288 86.316 42.312 86.4 ;
    END
  END rq[70]
  PIN rq[71]
    DIRECTION OUTPUT ;
    USE SIGNAL ;
    PORT
      LAYER M5 ;
        RECT  42.912 86.316 42.936 86.4 ;
    END
  END rq[71]
  PIN rq[72]
    DIRECTION OUTPUT ;
    USE SIGNAL ;
    PORT
      LAYER M5 ;
        RECT  43.488 86.316 43.512 86.4 ;
    END
  END rq[72]
  PIN rq[73]
    DIRECTION OUTPUT ;
    USE SIGNAL ;
    PORT
      LAYER M5 ;
        RECT  44.112 86.316 44.136 86.4 ;
    END
  END rq[73]
  PIN rq[74]
    DIRECTION OUTPUT ;
    USE SIGNAL ;
    PORT
      LAYER M5 ;
        RECT  44.688 86.316 44.712 86.4 ;
    END
  END rq[74]
  PIN rq[75]
    DIRECTION OUTPUT ;
    USE SIGNAL ;
    PORT
      LAYER M5 ;
        RECT  45.312 86.316 45.336 86.4 ;
    END
  END rq[75]
  PIN rq[76]
    DIRECTION OUTPUT ;
    USE SIGNAL ;
    PORT
      LAYER M5 ;
        RECT  45.888 86.316 45.912 86.4 ;
    END
  END rq[76]
  PIN rq[77]
    DIRECTION OUTPUT ;
    USE SIGNAL ;
    PORT
      LAYER M5 ;
        RECT  46.512 86.316 46.536 86.4 ;
    END
  END rq[77]
  PIN rq[78]
    DIRECTION OUTPUT ;
    USE SIGNAL ;
    PORT
      LAYER M5 ;
        RECT  47.088 86.316 47.112 86.4 ;
    END
  END rq[78]
  PIN rq[79]
    DIRECTION OUTPUT ;
    USE SIGNAL ;
    PORT
      LAYER M5 ;
        RECT  47.712 86.316 47.736 86.4 ;
    END
  END rq[79]
  PIN rq[7]
    DIRECTION OUTPUT ;
    USE SIGNAL ;
    PORT
      LAYER M5 ;
        RECT  4.512 86.316 4.536 86.4 ;
    END
  END rq[7]
  PIN rq[80]
    DIRECTION OUTPUT ;
    USE SIGNAL ;
    PORT
      LAYER M5 ;
        RECT  48.288 86.316 48.312 86.4 ;
    END
  END rq[80]
  PIN rq[81]
    DIRECTION OUTPUT ;
    USE SIGNAL ;
    PORT
      LAYER M5 ;
        RECT  48.912 86.316 48.936 86.4 ;
    END
  END rq[81]
  PIN rq[82]
    DIRECTION OUTPUT ;
    USE SIGNAL ;
    PORT
      LAYER M5 ;
        RECT  49.488 86.316 49.512 86.4 ;
    END
  END rq[82]
  PIN rq[83]
    DIRECTION OUTPUT ;
    USE SIGNAL ;
    PORT
      LAYER M5 ;
        RECT  50.112 86.316 50.136 86.4 ;
    END
  END rq[83]
  PIN rq[84]
    DIRECTION OUTPUT ;
    USE SIGNAL ;
    PORT
      LAYER M5 ;
        RECT  50.688 86.316 50.712 86.4 ;
    END
  END rq[84]
  PIN rq[85]
    DIRECTION OUTPUT ;
    USE SIGNAL ;
    PORT
      LAYER M5 ;
        RECT  51.312 86.316 51.336 86.4 ;
    END
  END rq[85]
  PIN rq[86]
    DIRECTION OUTPUT ;
    USE SIGNAL ;
    PORT
      LAYER M5 ;
        RECT  51.888 86.316 51.912 86.4 ;
    END
  END rq[86]
  PIN rq[87]
    DIRECTION OUTPUT ;
    USE SIGNAL ;
    PORT
      LAYER M5 ;
        RECT  52.512 86.316 52.536 86.4 ;
    END
  END rq[87]
  PIN rq[88]
    DIRECTION OUTPUT ;
    USE SIGNAL ;
    PORT
      LAYER M5 ;
        RECT  53.088 86.316 53.112 86.4 ;
    END
  END rq[88]
  PIN rq[89]
    DIRECTION OUTPUT ;
    USE SIGNAL ;
    PORT
      LAYER M5 ;
        RECT  53.712 86.316 53.736 86.4 ;
    END
  END rq[89]
  PIN rq[8]
    DIRECTION OUTPUT ;
    USE SIGNAL ;
    PORT
      LAYER M5 ;
        RECT  5.088 86.316 5.112 86.4 ;
    END
  END rq[8]
  PIN rq[90]
    DIRECTION OUTPUT ;
    USE SIGNAL ;
    PORT
      LAYER M5 ;
        RECT  54.288 86.316 54.312 86.4 ;
    END
  END rq[90]
  PIN rq[91]
    DIRECTION OUTPUT ;
    USE SIGNAL ;
    PORT
      LAYER M5 ;
        RECT  54.912 86.316 54.936 86.4 ;
    END
  END rq[91]
  PIN rq[92]
    DIRECTION OUTPUT ;
    USE SIGNAL ;
    PORT
      LAYER M5 ;
        RECT  55.488 86.316 55.512 86.4 ;
    END
  END rq[92]
  PIN rq[93]
    DIRECTION OUTPUT ;
    USE SIGNAL ;
    PORT
      LAYER M5 ;
        RECT  56.112 86.316 56.136 86.4 ;
    END
  END rq[93]
  PIN rq[94]
    DIRECTION OUTPUT ;
    USE SIGNAL ;
    PORT
      LAYER M5 ;
        RECT  56.688 86.316 56.712 86.4 ;
    END
  END rq[94]
  PIN rq[95]
    DIRECTION OUTPUT ;
    USE SIGNAL ;
    PORT
      LAYER M5 ;
        RECT  57.312 86.316 57.336 86.4 ;
    END
  END rq[95]
  PIN rq[96]
    DIRECTION OUTPUT ;
    USE SIGNAL ;
    PORT
      LAYER M5 ;
        RECT  57.888 86.316 57.912 86.4 ;
    END
  END rq[96]
  PIN rq[97]
    DIRECTION OUTPUT ;
    USE SIGNAL ;
    PORT
      LAYER M5 ;
        RECT  58.512 86.316 58.536 86.4 ;
    END
  END rq[97]
  PIN rq[98]
    DIRECTION OUTPUT ;
    USE SIGNAL ;
    PORT
      LAYER M5 ;
        RECT  59.088 86.316 59.112 86.4 ;
    END
  END rq[98]
  PIN rq[99]
    DIRECTION OUTPUT ;
    USE SIGNAL ;
    PORT
      LAYER M5 ;
        RECT  59.712 86.316 59.736 86.4 ;
    END
  END rq[99]
  PIN rq[9]
    DIRECTION OUTPUT ;
    USE SIGNAL ;
    PORT
      LAYER M5 ;
        RECT  5.712 86.316 5.736 86.4 ;
    END
  END rq[9]
  PIN rr_v[0]
    DIRECTION INPUT ;
    USE SIGNAL ;
    PORT
      LAYER M5 ;
        RECT  81.888 86.316 81.912 86.4 ;
    END
  END rr_v[0]
  PIN rr_v[1]
    DIRECTION INPUT ;
    USE SIGNAL ;
    PORT
      LAYER M5 ;
        RECT  82.512 86.316 82.536 86.4 ;
    END
  END rr_v[1]
  PIN rr_v[2]
    DIRECTION INPUT ;
    USE SIGNAL ;
    PORT
      LAYER M5 ;
        RECT  83.088 86.316 83.112 86.4 ;
    END
  END rr_v[2]
  PIN rr_v[3]
    DIRECTION INPUT ;
    USE SIGNAL ;
    PORT
      LAYER M5 ;
        RECT  83.712 86.316 83.736 86.4 ;
    END
  END rr_v[3]
  PIN rr_v[4]
    DIRECTION INPUT ;
    USE SIGNAL ;
    PORT
      LAYER M5 ;
        RECT  84.288 86.316 84.312 86.4 ;
    END
  END rr_v[4]
  PIN rr_v[5]
    DIRECTION INPUT ;
    USE SIGNAL ;
    PORT
      LAYER M5 ;
        RECT  84.912 86.316 84.936 86.4 ;
    END
  END rr_v[5]
  PIN rr_v[6]
    DIRECTION INPUT ;
    USE SIGNAL ;
    PORT
      LAYER M5 ;
        RECT  85.488 86.316 85.512 86.4 ;
    END
  END rr_v[6]
  PIN rr_v[7]
    DIRECTION INPUT ;
    USE SIGNAL ;
    PORT
      LAYER M5 ;
        RECT  86.112 86.316 86.136 86.4 ;
    END
  END rr_v[7]
  PIN rsel[0]
    DIRECTION OUTPUT ;
    USE SIGNAL ;
    PORT
      LAYER M4 ;
        RECT  86.316 82.32 86.4 82.344 ;
    END
  END rsel[0]
  PIN rsel[1]
    DIRECTION OUTPUT ;
    USE SIGNAL ;
    PORT
      LAYER M4 ;
        RECT  86.316 82.944 86.4 82.968 ;
    END
  END rsel[1]
  PIN rsel[2]
    DIRECTION OUTPUT ;
    USE SIGNAL ;
    PORT
      LAYER M4 ;
        RECT  86.316 83.568 86.4 83.592 ;
    END
  END rsel[2]
  PIN rst_n
    DIRECTION INPUT ;
    USE SIGNAL ;
    PORT
      LAYER M4 ;
        RECT  0 85.584 0.084 85.608 ;
    END
    PORT
      LAYER M4 ;
        RECT  0.06 85.584 0.137 85.608 ;
    END
  END rst_n
  PIN vo
    DIRECTION INPUT ;
    USE SIGNAL ;
    PORT
      LAYER M4 ;
        RECT  86.316 84.192 86.4 84.216 ;
    END
  END vo
  PIN wq_addr[0]
    DIRECTION OUTPUT ;
    USE SIGNAL ;
    PORT
      LAYER M5 ;
        RECT  0.192 0 0.216 0.084 ;
    END
  END wq_addr[0]
  PIN wq_addr[100]
    DIRECTION OUTPUT ;
    USE SIGNAL ;
    PORT
      LAYER M5 ;
        RECT  43.392 0 43.416 0.084 ;
    END
  END wq_addr[100]
  PIN wq_addr[101]
    DIRECTION OUTPUT ;
    USE SIGNAL ;
    PORT
      LAYER M5 ;
        RECT  43.824 0 43.848 0.084 ;
    END
  END wq_addr[101]
  PIN wq_addr[102]
    DIRECTION OUTPUT ;
    USE SIGNAL ;
    PORT
      LAYER M5 ;
        RECT  44.256 0 44.28 0.084 ;
    END
  END wq_addr[102]
  PIN wq_addr[103]
    DIRECTION OUTPUT ;
    USE SIGNAL ;
    PORT
      LAYER M5 ;
        RECT  44.688 0 44.712 0.084 ;
    END
  END wq_addr[103]
  PIN wq_addr[104]
    DIRECTION OUTPUT ;
    USE SIGNAL ;
    PORT
      LAYER M5 ;
        RECT  45.12 0 45.144 0.084 ;
    END
  END wq_addr[104]
  PIN wq_addr[105]
    DIRECTION OUTPUT ;
    USE SIGNAL ;
    PORT
      LAYER M5 ;
        RECT  45.552 0 45.576 0.084 ;
    END
  END wq_addr[105]
  PIN wq_addr[106]
    DIRECTION OUTPUT ;
    USE SIGNAL ;
    PORT
      LAYER M5 ;
        RECT  45.984 0 46.008 0.084 ;
    END
  END wq_addr[106]
  PIN wq_addr[107]
    DIRECTION OUTPUT ;
    USE SIGNAL ;
    PORT
      LAYER M5 ;
        RECT  46.416 0 46.44 0.084 ;
    END
  END wq_addr[107]
  PIN wq_addr[108]
    DIRECTION OUTPUT ;
    USE SIGNAL ;
    PORT
      LAYER M5 ;
        RECT  46.848 0 46.872 0.084 ;
    END
  END wq_addr[108]
  PIN wq_addr[109]
    DIRECTION OUTPUT ;
    USE SIGNAL ;
    PORT
      LAYER M5 ;
        RECT  47.28 0 47.304 0.084 ;
    END
  END wq_addr[109]
  PIN wq_addr[10]
    DIRECTION OUTPUT ;
    USE SIGNAL ;
    PORT
      LAYER M5 ;
        RECT  4.512 0 4.536 0.084 ;
    END
  END wq_addr[10]
  PIN wq_addr[110]
    DIRECTION OUTPUT ;
    USE SIGNAL ;
    PORT
      LAYER M5 ;
        RECT  47.712 0 47.736 0.084 ;
    END
  END wq_addr[110]
  PIN wq_addr[111]
    DIRECTION OUTPUT ;
    USE SIGNAL ;
    PORT
      LAYER M5 ;
        RECT  48.144 0 48.168 0.084 ;
    END
  END wq_addr[111]
  PIN wq_addr[112]
    DIRECTION OUTPUT ;
    USE SIGNAL ;
    PORT
      LAYER M5 ;
        RECT  48.576 0 48.6 0.084 ;
    END
  END wq_addr[112]
  PIN wq_addr[113]
    DIRECTION OUTPUT ;
    USE SIGNAL ;
    PORT
      LAYER M5 ;
        RECT  49.008 0 49.032 0.084 ;
    END
  END wq_addr[113]
  PIN wq_addr[114]
    DIRECTION OUTPUT ;
    USE SIGNAL ;
    PORT
      LAYER M5 ;
        RECT  49.44 0 49.464 0.084 ;
    END
  END wq_addr[114]
  PIN wq_addr[115]
    DIRECTION OUTPUT ;
    USE SIGNAL ;
    PORT
      LAYER M5 ;
        RECT  49.872 0 49.896 0.084 ;
    END
  END wq_addr[115]
  PIN wq_addr[116]
    DIRECTION OUTPUT ;
    USE SIGNAL ;
    PORT
      LAYER M5 ;
        RECT  50.304 0 50.328 0.084 ;
    END
  END wq_addr[116]
  PIN wq_addr[117]
    DIRECTION OUTPUT ;
    USE SIGNAL ;
    PORT
      LAYER M5 ;
        RECT  50.736 0 50.76 0.084 ;
    END
  END wq_addr[117]
  PIN wq_addr[118]
    DIRECTION OUTPUT ;
    USE SIGNAL ;
    PORT
      LAYER M5 ;
        RECT  51.168 0 51.192 0.084 ;
    END
  END wq_addr[118]
  PIN wq_addr[119]
    DIRECTION OUTPUT ;
    USE SIGNAL ;
    PORT
      LAYER M5 ;
        RECT  51.6 0 51.624 0.084 ;
    END
  END wq_addr[119]
  PIN wq_addr[11]
    DIRECTION OUTPUT ;
    USE SIGNAL ;
    PORT
      LAYER M5 ;
        RECT  4.944 0 4.968 0.084 ;
    END
  END wq_addr[11]
  PIN wq_addr[120]
    DIRECTION OUTPUT ;
    USE SIGNAL ;
    PORT
      LAYER M5 ;
        RECT  52.032 0 52.056 0.084 ;
    END
  END wq_addr[120]
  PIN wq_addr[121]
    DIRECTION OUTPUT ;
    USE SIGNAL ;
    PORT
      LAYER M5 ;
        RECT  52.464 0 52.488 0.084 ;
    END
  END wq_addr[121]
  PIN wq_addr[122]
    DIRECTION OUTPUT ;
    USE SIGNAL ;
    PORT
      LAYER M5 ;
        RECT  52.896 0 52.92 0.084 ;
    END
  END wq_addr[122]
  PIN wq_addr[123]
    DIRECTION OUTPUT ;
    USE SIGNAL ;
    PORT
      LAYER M5 ;
        RECT  53.328 0 53.352 0.084 ;
    END
  END wq_addr[123]
  PIN wq_addr[124]
    DIRECTION OUTPUT ;
    USE SIGNAL ;
    PORT
      LAYER M5 ;
        RECT  53.76 0 53.784 0.084 ;
    END
  END wq_addr[124]
  PIN wq_addr[125]
    DIRECTION OUTPUT ;
    USE SIGNAL ;
    PORT
      LAYER M5 ;
        RECT  54.192 0 54.216 0.084 ;
    END
  END wq_addr[125]
  PIN wq_addr[126]
    DIRECTION OUTPUT ;
    USE SIGNAL ;
    PORT
      LAYER M5 ;
        RECT  54.624 0 54.648 0.084 ;
    END
  END wq_addr[126]
  PIN wq_addr[127]
    DIRECTION OUTPUT ;
    USE SIGNAL ;
    PORT
      LAYER M5 ;
        RECT  55.056 0 55.08 0.084 ;
    END
  END wq_addr[127]
  PIN wq_addr[12]
    DIRECTION OUTPUT ;
    USE SIGNAL ;
    PORT
      LAYER M5 ;
        RECT  5.376 0 5.4 0.084 ;
    END
  END wq_addr[12]
  PIN wq_addr[13]
    DIRECTION OUTPUT ;
    USE SIGNAL ;
    PORT
      LAYER M5 ;
        RECT  5.808 0 5.832 0.084 ;
    END
  END wq_addr[13]
  PIN wq_addr[14]
    DIRECTION OUTPUT ;
    USE SIGNAL ;
    PORT
      LAYER M5 ;
        RECT  6.24 0 6.264 0.084 ;
    END
  END wq_addr[14]
  PIN wq_addr[15]
    DIRECTION OUTPUT ;
    USE SIGNAL ;
    PORT
      LAYER M5 ;
        RECT  6.672 0 6.696 0.084 ;
    END
  END wq_addr[15]
  PIN wq_addr[16]
    DIRECTION OUTPUT ;
    USE SIGNAL ;
    PORT
      LAYER M5 ;
        RECT  7.104 0 7.128 0.084 ;
    END
  END wq_addr[16]
  PIN wq_addr[17]
    DIRECTION OUTPUT ;
    USE SIGNAL ;
    PORT
      LAYER M5 ;
        RECT  7.536 0 7.56 0.084 ;
    END
  END wq_addr[17]
  PIN wq_addr[18]
    DIRECTION OUTPUT ;
    USE SIGNAL ;
    PORT
      LAYER M5 ;
        RECT  7.968 0 7.992 0.084 ;
    END
  END wq_addr[18]
  PIN wq_addr[19]
    DIRECTION OUTPUT ;
    USE SIGNAL ;
    PORT
      LAYER M5 ;
        RECT  8.4 0 8.424 0.084 ;
    END
  END wq_addr[19]
  PIN wq_addr[1]
    DIRECTION OUTPUT ;
    USE SIGNAL ;
    PORT
      LAYER M5 ;
        RECT  0.624 0 0.648 0.084 ;
    END
  END wq_addr[1]
  PIN wq_addr[20]
    DIRECTION OUTPUT ;
    USE SIGNAL ;
    PORT
      LAYER M5 ;
        RECT  8.832 0 8.856 0.084 ;
    END
  END wq_addr[20]
  PIN wq_addr[21]
    DIRECTION OUTPUT ;
    USE SIGNAL ;
    PORT
      LAYER M5 ;
        RECT  9.264 0 9.288 0.084 ;
    END
  END wq_addr[21]
  PIN wq_addr[22]
    DIRECTION OUTPUT ;
    USE SIGNAL ;
    PORT
      LAYER M5 ;
        RECT  9.696 0 9.72 0.084 ;
    END
  END wq_addr[22]
  PIN wq_addr[23]
    DIRECTION OUTPUT ;
    USE SIGNAL ;
    PORT
      LAYER M5 ;
        RECT  10.128 0 10.152 0.084 ;
    END
  END wq_addr[23]
  PIN wq_addr[24]
    DIRECTION OUTPUT ;
    USE SIGNAL ;
    PORT
      LAYER M5 ;
        RECT  10.56 0 10.584 0.084 ;
    END
  END wq_addr[24]
  PIN wq_addr[25]
    DIRECTION OUTPUT ;
    USE SIGNAL ;
    PORT
      LAYER M5 ;
        RECT  10.992 0 11.016 0.084 ;
    END
  END wq_addr[25]
  PIN wq_addr[26]
    DIRECTION OUTPUT ;
    USE SIGNAL ;
    PORT
      LAYER M5 ;
        RECT  11.424 0 11.448 0.084 ;
    END
  END wq_addr[26]
  PIN wq_addr[27]
    DIRECTION OUTPUT ;
    USE SIGNAL ;
    PORT
      LAYER M5 ;
        RECT  11.856 0 11.88 0.084 ;
    END
  END wq_addr[27]
  PIN wq_addr[28]
    DIRECTION OUTPUT ;
    USE SIGNAL ;
    PORT
      LAYER M5 ;
        RECT  12.288 0 12.312 0.084 ;
    END
  END wq_addr[28]
  PIN wq_addr[29]
    DIRECTION OUTPUT ;
    USE SIGNAL ;
    PORT
      LAYER M5 ;
        RECT  12.72 0 12.744 0.084 ;
    END
  END wq_addr[29]
  PIN wq_addr[2]
    DIRECTION OUTPUT ;
    USE SIGNAL ;
    PORT
      LAYER M5 ;
        RECT  1.056 0 1.08 0.084 ;
    END
  END wq_addr[2]
  PIN wq_addr[30]
    DIRECTION OUTPUT ;
    USE SIGNAL ;
    PORT
      LAYER M5 ;
        RECT  13.152 0 13.176 0.084 ;
    END
  END wq_addr[30]
  PIN wq_addr[31]
    DIRECTION OUTPUT ;
    USE SIGNAL ;
    PORT
      LAYER M5 ;
        RECT  13.584 0 13.608 0.084 ;
    END
  END wq_addr[31]
  PIN wq_addr[32]
    DIRECTION OUTPUT ;
    USE SIGNAL ;
    PORT
      LAYER M5 ;
        RECT  14.016 0 14.04 0.084 ;
    END
  END wq_addr[32]
  PIN wq_addr[33]
    DIRECTION OUTPUT ;
    USE SIGNAL ;
    PORT
      LAYER M5 ;
        RECT  14.448 0 14.472 0.084 ;
    END
  END wq_addr[33]
  PIN wq_addr[34]
    DIRECTION OUTPUT ;
    USE SIGNAL ;
    PORT
      LAYER M5 ;
        RECT  14.88 0 14.904 0.084 ;
    END
  END wq_addr[34]
  PIN wq_addr[35]
    DIRECTION OUTPUT ;
    USE SIGNAL ;
    PORT
      LAYER M5 ;
        RECT  15.312 0 15.336 0.084 ;
    END
  END wq_addr[35]
  PIN wq_addr[36]
    DIRECTION OUTPUT ;
    USE SIGNAL ;
    PORT
      LAYER M5 ;
        RECT  15.744 0 15.768 0.084 ;
    END
  END wq_addr[36]
  PIN wq_addr[37]
    DIRECTION OUTPUT ;
    USE SIGNAL ;
    PORT
      LAYER M5 ;
        RECT  16.176 0 16.2 0.084 ;
    END
  END wq_addr[37]
  PIN wq_addr[38]
    DIRECTION OUTPUT ;
    USE SIGNAL ;
    PORT
      LAYER M5 ;
        RECT  16.608 0 16.632 0.084 ;
    END
  END wq_addr[38]
  PIN wq_addr[39]
    DIRECTION OUTPUT ;
    USE SIGNAL ;
    PORT
      LAYER M5 ;
        RECT  17.04 0 17.064 0.084 ;
    END
  END wq_addr[39]
  PIN wq_addr[3]
    DIRECTION OUTPUT ;
    USE SIGNAL ;
    PORT
      LAYER M5 ;
        RECT  1.488 0 1.512 0.084 ;
    END
  END wq_addr[3]
  PIN wq_addr[40]
    DIRECTION OUTPUT ;
    USE SIGNAL ;
    PORT
      LAYER M5 ;
        RECT  17.472 0 17.496 0.084 ;
    END
  END wq_addr[40]
  PIN wq_addr[41]
    DIRECTION OUTPUT ;
    USE SIGNAL ;
    PORT
      LAYER M5 ;
        RECT  17.904 0 17.928 0.084 ;
    END
  END wq_addr[41]
  PIN wq_addr[42]
    DIRECTION OUTPUT ;
    USE SIGNAL ;
    PORT
      LAYER M5 ;
        RECT  18.336 0 18.36 0.084 ;
    END
  END wq_addr[42]
  PIN wq_addr[43]
    DIRECTION OUTPUT ;
    USE SIGNAL ;
    PORT
      LAYER M5 ;
        RECT  18.768 0 18.792 0.084 ;
    END
  END wq_addr[43]
  PIN wq_addr[44]
    DIRECTION OUTPUT ;
    USE SIGNAL ;
    PORT
      LAYER M5 ;
        RECT  19.2 0 19.224 0.084 ;
    END
  END wq_addr[44]
  PIN wq_addr[45]
    DIRECTION OUTPUT ;
    USE SIGNAL ;
    PORT
      LAYER M5 ;
        RECT  19.632 0 19.656 0.084 ;
    END
  END wq_addr[45]
  PIN wq_addr[46]
    DIRECTION OUTPUT ;
    USE SIGNAL ;
    PORT
      LAYER M5 ;
        RECT  20.064 0 20.088 0.084 ;
    END
  END wq_addr[46]
  PIN wq_addr[47]
    DIRECTION OUTPUT ;
    USE SIGNAL ;
    PORT
      LAYER M5 ;
        RECT  20.496 0 20.52 0.084 ;
    END
  END wq_addr[47]
  PIN wq_addr[48]
    DIRECTION OUTPUT ;
    USE SIGNAL ;
    PORT
      LAYER M5 ;
        RECT  20.928 0 20.952 0.084 ;
    END
  END wq_addr[48]
  PIN wq_addr[49]
    DIRECTION OUTPUT ;
    USE SIGNAL ;
    PORT
      LAYER M5 ;
        RECT  21.36 0 21.384 0.084 ;
    END
  END wq_addr[49]
  PIN wq_addr[4]
    DIRECTION OUTPUT ;
    USE SIGNAL ;
    PORT
      LAYER M5 ;
        RECT  1.92 0 1.944 0.084 ;
    END
  END wq_addr[4]
  PIN wq_addr[50]
    DIRECTION OUTPUT ;
    USE SIGNAL ;
    PORT
      LAYER M5 ;
        RECT  21.792 0 21.816 0.084 ;
    END
  END wq_addr[50]
  PIN wq_addr[51]
    DIRECTION OUTPUT ;
    USE SIGNAL ;
    PORT
      LAYER M5 ;
        RECT  22.224 0 22.248 0.084 ;
    END
  END wq_addr[51]
  PIN wq_addr[52]
    DIRECTION OUTPUT ;
    USE SIGNAL ;
    PORT
      LAYER M5 ;
        RECT  22.656 0 22.68 0.084 ;
    END
  END wq_addr[52]
  PIN wq_addr[53]
    DIRECTION OUTPUT ;
    USE SIGNAL ;
    PORT
      LAYER M5 ;
        RECT  23.088 0 23.112 0.084 ;
    END
  END wq_addr[53]
  PIN wq_addr[54]
    DIRECTION OUTPUT ;
    USE SIGNAL ;
    PORT
      LAYER M5 ;
        RECT  23.52 0 23.544 0.084 ;
    END
  END wq_addr[54]
  PIN wq_addr[55]
    DIRECTION OUTPUT ;
    USE SIGNAL ;
    PORT
      LAYER M5 ;
        RECT  23.952 0 23.976 0.084 ;
    END
  END wq_addr[55]
  PIN wq_addr[56]
    DIRECTION OUTPUT ;
    USE SIGNAL ;
    PORT
      LAYER M5 ;
        RECT  24.384 0 24.408 0.084 ;
    END
  END wq_addr[56]
  PIN wq_addr[57]
    DIRECTION OUTPUT ;
    USE SIGNAL ;
    PORT
      LAYER M5 ;
        RECT  24.816 0 24.84 0.084 ;
    END
  END wq_addr[57]
  PIN wq_addr[58]
    DIRECTION OUTPUT ;
    USE SIGNAL ;
    PORT
      LAYER M5 ;
        RECT  25.248 0 25.272 0.084 ;
    END
  END wq_addr[58]
  PIN wq_addr[59]
    DIRECTION OUTPUT ;
    USE SIGNAL ;
    PORT
      LAYER M5 ;
        RECT  25.68 0 25.704 0.084 ;
    END
  END wq_addr[59]
  PIN wq_addr[5]
    DIRECTION OUTPUT ;
    USE SIGNAL ;
    PORT
      LAYER M5 ;
        RECT  2.352 0 2.376 0.084 ;
    END
  END wq_addr[5]
  PIN wq_addr[60]
    DIRECTION OUTPUT ;
    USE SIGNAL ;
    PORT
      LAYER M5 ;
        RECT  26.112 0 26.136 0.084 ;
    END
  END wq_addr[60]
  PIN wq_addr[61]
    DIRECTION OUTPUT ;
    USE SIGNAL ;
    PORT
      LAYER M5 ;
        RECT  26.544 0 26.568 0.084 ;
    END
  END wq_addr[61]
  PIN wq_addr[62]
    DIRECTION OUTPUT ;
    USE SIGNAL ;
    PORT
      LAYER M5 ;
        RECT  26.976 0 27 0.084 ;
    END
  END wq_addr[62]
  PIN wq_addr[63]
    DIRECTION OUTPUT ;
    USE SIGNAL ;
    PORT
      LAYER M5 ;
        RECT  27.408 0 27.432 0.084 ;
    END
  END wq_addr[63]
  PIN wq_addr[64]
    DIRECTION OUTPUT ;
    USE SIGNAL ;
    PORT
      LAYER M5 ;
        RECT  27.84 0 27.864 0.084 ;
    END
  END wq_addr[64]
  PIN wq_addr[65]
    DIRECTION OUTPUT ;
    USE SIGNAL ;
    PORT
      LAYER M5 ;
        RECT  28.272 0 28.296 0.084 ;
    END
  END wq_addr[65]
  PIN wq_addr[66]
    DIRECTION OUTPUT ;
    USE SIGNAL ;
    PORT
      LAYER M5 ;
        RECT  28.704 0 28.728 0.084 ;
    END
  END wq_addr[66]
  PIN wq_addr[67]
    DIRECTION OUTPUT ;
    USE SIGNAL ;
    PORT
      LAYER M5 ;
        RECT  29.136 0 29.16 0.084 ;
    END
  END wq_addr[67]
  PIN wq_addr[68]
    DIRECTION OUTPUT ;
    USE SIGNAL ;
    PORT
      LAYER M5 ;
        RECT  29.568 0 29.592 0.084 ;
    END
  END wq_addr[68]
  PIN wq_addr[69]
    DIRECTION OUTPUT ;
    USE SIGNAL ;
    PORT
      LAYER M5 ;
        RECT  30 0 30.024 0.084 ;
    END
  END wq_addr[69]
  PIN wq_addr[6]
    DIRECTION OUTPUT ;
    USE SIGNAL ;
    PORT
      LAYER M5 ;
        RECT  2.784 0 2.808 0.084 ;
    END
  END wq_addr[6]
  PIN wq_addr[70]
    DIRECTION OUTPUT ;
    USE SIGNAL ;
    PORT
      LAYER M5 ;
        RECT  30.432 0 30.456 0.084 ;
    END
  END wq_addr[70]
  PIN wq_addr[71]
    DIRECTION OUTPUT ;
    USE SIGNAL ;
    PORT
      LAYER M5 ;
        RECT  30.864 0 30.888 0.084 ;
    END
  END wq_addr[71]
  PIN wq_addr[72]
    DIRECTION OUTPUT ;
    USE SIGNAL ;
    PORT
      LAYER M5 ;
        RECT  31.296 0 31.32 0.084 ;
    END
  END wq_addr[72]
  PIN wq_addr[73]
    DIRECTION OUTPUT ;
    USE SIGNAL ;
    PORT
      LAYER M5 ;
        RECT  31.728 0 31.752 0.084 ;
    END
  END wq_addr[73]
  PIN wq_addr[74]
    DIRECTION OUTPUT ;
    USE SIGNAL ;
    PORT
      LAYER M5 ;
        RECT  32.16 0 32.184 0.084 ;
    END
  END wq_addr[74]
  PIN wq_addr[75]
    DIRECTION OUTPUT ;
    USE SIGNAL ;
    PORT
      LAYER M5 ;
        RECT  32.592 0 32.616 0.084 ;
    END
  END wq_addr[75]
  PIN wq_addr[76]
    DIRECTION OUTPUT ;
    USE SIGNAL ;
    PORT
      LAYER M5 ;
        RECT  33.024 0 33.048 0.084 ;
    END
  END wq_addr[76]
  PIN wq_addr[77]
    DIRECTION OUTPUT ;
    USE SIGNAL ;
    PORT
      LAYER M5 ;
        RECT  33.456 0 33.48 0.084 ;
    END
  END wq_addr[77]
  PIN wq_addr[78]
    DIRECTION OUTPUT ;
    USE SIGNAL ;
    PORT
      LAYER M5 ;
        RECT  33.888 0 33.912 0.084 ;
    END
  END wq_addr[78]
  PIN wq_addr[79]
    DIRECTION OUTPUT ;
    USE SIGNAL ;
    PORT
      LAYER M5 ;
        RECT  34.32 0 34.344 0.084 ;
    END
  END wq_addr[79]
  PIN wq_addr[7]
    DIRECTION OUTPUT ;
    USE SIGNAL ;
    PORT
      LAYER M5 ;
        RECT  3.216 0 3.24 0.084 ;
    END
  END wq_addr[7]
  PIN wq_addr[80]
    DIRECTION OUTPUT ;
    USE SIGNAL ;
    PORT
      LAYER M5 ;
        RECT  34.752 0 34.776 0.084 ;
    END
  END wq_addr[80]
  PIN wq_addr[81]
    DIRECTION OUTPUT ;
    USE SIGNAL ;
    PORT
      LAYER M5 ;
        RECT  35.184 0 35.208 0.084 ;
    END
  END wq_addr[81]
  PIN wq_addr[82]
    DIRECTION OUTPUT ;
    USE SIGNAL ;
    PORT
      LAYER M5 ;
        RECT  35.616 0 35.64 0.084 ;
    END
  END wq_addr[82]
  PIN wq_addr[83]
    DIRECTION OUTPUT ;
    USE SIGNAL ;
    PORT
      LAYER M5 ;
        RECT  36.048 0 36.072 0.084 ;
    END
  END wq_addr[83]
  PIN wq_addr[84]
    DIRECTION OUTPUT ;
    USE SIGNAL ;
    PORT
      LAYER M5 ;
        RECT  36.48 0 36.504 0.084 ;
    END
  END wq_addr[84]
  PIN wq_addr[85]
    DIRECTION OUTPUT ;
    USE SIGNAL ;
    PORT
      LAYER M5 ;
        RECT  36.912 0 36.936 0.084 ;
    END
  END wq_addr[85]
  PIN wq_addr[86]
    DIRECTION OUTPUT ;
    USE SIGNAL ;
    PORT
      LAYER M5 ;
        RECT  37.344 0 37.368 0.084 ;
    END
  END wq_addr[86]
  PIN wq_addr[87]
    DIRECTION OUTPUT ;
    USE SIGNAL ;
    PORT
      LAYER M5 ;
        RECT  37.776 0 37.8 0.084 ;
    END
  END wq_addr[87]
  PIN wq_addr[88]
    DIRECTION OUTPUT ;
    USE SIGNAL ;
    PORT
      LAYER M5 ;
        RECT  38.208 0 38.232 0.084 ;
    END
  END wq_addr[88]
  PIN wq_addr[89]
    DIRECTION OUTPUT ;
    USE SIGNAL ;
    PORT
      LAYER M5 ;
        RECT  38.64 0 38.664 0.084 ;
    END
  END wq_addr[89]
  PIN wq_addr[8]
    DIRECTION OUTPUT ;
    USE SIGNAL ;
    PORT
      LAYER M5 ;
        RECT  3.648 0 3.672 0.084 ;
    END
  END wq_addr[8]
  PIN wq_addr[90]
    DIRECTION OUTPUT ;
    USE SIGNAL ;
    PORT
      LAYER M5 ;
        RECT  39.072 0 39.096 0.084 ;
    END
  END wq_addr[90]
  PIN wq_addr[91]
    DIRECTION OUTPUT ;
    USE SIGNAL ;
    PORT
      LAYER M5 ;
        RECT  39.504 0 39.528 0.084 ;
    END
  END wq_addr[91]
  PIN wq_addr[92]
    DIRECTION OUTPUT ;
    USE SIGNAL ;
    PORT
      LAYER M5 ;
        RECT  39.936 0 39.96 0.084 ;
    END
  END wq_addr[92]
  PIN wq_addr[93]
    DIRECTION OUTPUT ;
    USE SIGNAL ;
    PORT
      LAYER M5 ;
        RECT  40.368 0 40.392 0.084 ;
    END
  END wq_addr[93]
  PIN wq_addr[94]
    DIRECTION OUTPUT ;
    USE SIGNAL ;
    PORT
      LAYER M5 ;
        RECT  40.8 0 40.824 0.084 ;
    END
  END wq_addr[94]
  PIN wq_addr[95]
    DIRECTION OUTPUT ;
    USE SIGNAL ;
    PORT
      LAYER M5 ;
        RECT  41.232 0 41.256 0.084 ;
    END
  END wq_addr[95]
  PIN wq_addr[96]
    DIRECTION OUTPUT ;
    USE SIGNAL ;
    PORT
      LAYER M5 ;
        RECT  41.664 0 41.688 0.084 ;
    END
  END wq_addr[96]
  PIN wq_addr[97]
    DIRECTION OUTPUT ;
    USE SIGNAL ;
    PORT
      LAYER M5 ;
        RECT  42.096 0 42.12 0.084 ;
    END
  END wq_addr[97]
  PIN wq_addr[98]
    DIRECTION OUTPUT ;
    USE SIGNAL ;
    PORT
      LAYER M5 ;
        RECT  42.528 0 42.552 0.084 ;
    END
  END wq_addr[98]
  PIN wq_addr[99]
    DIRECTION OUTPUT ;
    USE SIGNAL ;
    PORT
      LAYER M5 ;
        RECT  42.96 0 42.984 0.084 ;
    END
  END wq_addr[99]
  PIN wq_addr[9]
    DIRECTION OUTPUT ;
    USE SIGNAL ;
    PORT
      LAYER M5 ;
        RECT  4.08 0 4.104 0.084 ;
    END
  END wq_addr[9]
  PIN wq_mask[0]
    DIRECTION OUTPUT ;
    USE SIGNAL ;
    PORT
      LAYER M5 ;
        RECT  55.488 0 55.512 0.084 ;
    END
  END wq_mask[0]
  PIN wq_mask[10]
    DIRECTION OUTPUT ;
    USE SIGNAL ;
    PORT
      LAYER M5 ;
        RECT  59.808 0 59.832 0.084 ;
    END
  END wq_mask[10]
  PIN wq_mask[11]
    DIRECTION OUTPUT ;
    USE SIGNAL ;
    PORT
      LAYER M5 ;
        RECT  60.24 0 60.264 0.084 ;
    END
  END wq_mask[11]
  PIN wq_mask[12]
    DIRECTION OUTPUT ;
    USE SIGNAL ;
    PORT
      LAYER M5 ;
        RECT  60.672 0 60.696 0.084 ;
    END
  END wq_mask[12]
  PIN wq_mask[13]
    DIRECTION OUTPUT ;
    USE SIGNAL ;
    PORT
      LAYER M5 ;
        RECT  61.104 0 61.128 0.084 ;
    END
  END wq_mask[13]
  PIN wq_mask[14]
    DIRECTION OUTPUT ;
    USE SIGNAL ;
    PORT
      LAYER M5 ;
        RECT  61.536 0 61.56 0.084 ;
    END
  END wq_mask[14]
  PIN wq_mask[15]
    DIRECTION OUTPUT ;
    USE SIGNAL ;
    PORT
      LAYER M5 ;
        RECT  61.968 0 61.992 0.084 ;
    END
  END wq_mask[15]
  PIN wq_mask[16]
    DIRECTION OUTPUT ;
    USE SIGNAL ;
    PORT
      LAYER M5 ;
        RECT  62.4 0 62.424 0.084 ;
    END
  END wq_mask[16]
  PIN wq_mask[17]
    DIRECTION OUTPUT ;
    USE SIGNAL ;
    PORT
      LAYER M5 ;
        RECT  62.832 0 62.856 0.084 ;
    END
  END wq_mask[17]
  PIN wq_mask[18]
    DIRECTION OUTPUT ;
    USE SIGNAL ;
    PORT
      LAYER M5 ;
        RECT  63.264 0 63.288 0.084 ;
    END
  END wq_mask[18]
  PIN wq_mask[19]
    DIRECTION OUTPUT ;
    USE SIGNAL ;
    PORT
      LAYER M5 ;
        RECT  63.696 0 63.72 0.084 ;
    END
  END wq_mask[19]
  PIN wq_mask[1]
    DIRECTION OUTPUT ;
    USE SIGNAL ;
    PORT
      LAYER M5 ;
        RECT  55.92 0 55.944 0.084 ;
    END
  END wq_mask[1]
  PIN wq_mask[20]
    DIRECTION OUTPUT ;
    USE SIGNAL ;
    PORT
      LAYER M5 ;
        RECT  64.128 0 64.152 0.084 ;
    END
  END wq_mask[20]
  PIN wq_mask[21]
    DIRECTION OUTPUT ;
    USE SIGNAL ;
    PORT
      LAYER M5 ;
        RECT  64.56 0 64.584 0.084 ;
    END
  END wq_mask[21]
  PIN wq_mask[22]
    DIRECTION OUTPUT ;
    USE SIGNAL ;
    PORT
      LAYER M5 ;
        RECT  64.992 0 65.016 0.084 ;
    END
  END wq_mask[22]
  PIN wq_mask[23]
    DIRECTION OUTPUT ;
    USE SIGNAL ;
    PORT
      LAYER M5 ;
        RECT  65.424 0 65.448 0.084 ;
    END
  END wq_mask[23]
  PIN wq_mask[24]
    DIRECTION OUTPUT ;
    USE SIGNAL ;
    PORT
      LAYER M5 ;
        RECT  65.856 0 65.88 0.084 ;
    END
  END wq_mask[24]
  PIN wq_mask[25]
    DIRECTION OUTPUT ;
    USE SIGNAL ;
    PORT
      LAYER M5 ;
        RECT  66.288 0 66.312 0.084 ;
    END
  END wq_mask[25]
  PIN wq_mask[26]
    DIRECTION OUTPUT ;
    USE SIGNAL ;
    PORT
      LAYER M5 ;
        RECT  66.72 0 66.744 0.084 ;
    END
  END wq_mask[26]
  PIN wq_mask[27]
    DIRECTION OUTPUT ;
    USE SIGNAL ;
    PORT
      LAYER M5 ;
        RECT  67.152 0 67.176 0.084 ;
    END
  END wq_mask[27]
  PIN wq_mask[28]
    DIRECTION OUTPUT ;
    USE SIGNAL ;
    PORT
      LAYER M5 ;
        RECT  67.584 0 67.608 0.084 ;
    END
  END wq_mask[28]
  PIN wq_mask[29]
    DIRECTION OUTPUT ;
    USE SIGNAL ;
    PORT
      LAYER M5 ;
        RECT  68.016 0 68.04 0.084 ;
    END
  END wq_mask[29]
  PIN wq_mask[2]
    DIRECTION OUTPUT ;
    USE SIGNAL ;
    PORT
      LAYER M5 ;
        RECT  56.352 0 56.376 0.084 ;
    END
  END wq_mask[2]
  PIN wq_mask[30]
    DIRECTION OUTPUT ;
    USE SIGNAL ;
    PORT
      LAYER M5 ;
        RECT  68.448 0 68.472 0.084 ;
    END
  END wq_mask[30]
  PIN wq_mask[31]
    DIRECTION OUTPUT ;
    USE SIGNAL ;
    PORT
      LAYER M5 ;
        RECT  68.88 0 68.904 0.084 ;
    END
  END wq_mask[31]
  PIN wq_mask[32]
    DIRECTION OUTPUT ;
    USE SIGNAL ;
    PORT
      LAYER M5 ;
        RECT  69.312 0 69.336 0.084 ;
    END
  END wq_mask[32]
  PIN wq_mask[33]
    DIRECTION OUTPUT ;
    USE SIGNAL ;
    PORT
      LAYER M5 ;
        RECT  69.744 0 69.768 0.084 ;
    END
  END wq_mask[33]
  PIN wq_mask[34]
    DIRECTION OUTPUT ;
    USE SIGNAL ;
    PORT
      LAYER M5 ;
        RECT  70.176 0 70.2 0.084 ;
    END
  END wq_mask[34]
  PIN wq_mask[35]
    DIRECTION OUTPUT ;
    USE SIGNAL ;
    PORT
      LAYER M5 ;
        RECT  70.608 0 70.632 0.084 ;
    END
  END wq_mask[35]
  PIN wq_mask[36]
    DIRECTION OUTPUT ;
    USE SIGNAL ;
    PORT
      LAYER M5 ;
        RECT  71.04 0 71.064 0.084 ;
    END
  END wq_mask[36]
  PIN wq_mask[37]
    DIRECTION OUTPUT ;
    USE SIGNAL ;
    PORT
      LAYER M5 ;
        RECT  71.472 0 71.496 0.084 ;
    END
  END wq_mask[37]
  PIN wq_mask[38]
    DIRECTION OUTPUT ;
    USE SIGNAL ;
    PORT
      LAYER M5 ;
        RECT  71.904 0 71.928 0.084 ;
    END
  END wq_mask[38]
  PIN wq_mask[39]
    DIRECTION OUTPUT ;
    USE SIGNAL ;
    PORT
      LAYER M5 ;
        RECT  72.336 0 72.36 0.084 ;
    END
  END wq_mask[39]
  PIN wq_mask[3]
    DIRECTION OUTPUT ;
    USE SIGNAL ;
    PORT
      LAYER M5 ;
        RECT  56.784 0 56.808 0.084 ;
    END
  END wq_mask[3]
  PIN wq_mask[40]
    DIRECTION OUTPUT ;
    USE SIGNAL ;
    PORT
      LAYER M5 ;
        RECT  72.768 0 72.792 0.084 ;
    END
  END wq_mask[40]
  PIN wq_mask[41]
    DIRECTION OUTPUT ;
    USE SIGNAL ;
    PORT
      LAYER M5 ;
        RECT  73.2 0 73.224 0.084 ;
    END
  END wq_mask[41]
  PIN wq_mask[42]
    DIRECTION OUTPUT ;
    USE SIGNAL ;
    PORT
      LAYER M5 ;
        RECT  73.632 0 73.656 0.084 ;
    END
  END wq_mask[42]
  PIN wq_mask[43]
    DIRECTION OUTPUT ;
    USE SIGNAL ;
    PORT
      LAYER M5 ;
        RECT  74.064 0 74.088 0.084 ;
    END
  END wq_mask[43]
  PIN wq_mask[44]
    DIRECTION OUTPUT ;
    USE SIGNAL ;
    PORT
      LAYER M5 ;
        RECT  74.496 0 74.52 0.084 ;
    END
  END wq_mask[44]
  PIN wq_mask[45]
    DIRECTION OUTPUT ;
    USE SIGNAL ;
    PORT
      LAYER M5 ;
        RECT  74.928 0 74.952 0.084 ;
    END
  END wq_mask[45]
  PIN wq_mask[46]
    DIRECTION OUTPUT ;
    USE SIGNAL ;
    PORT
      LAYER M5 ;
        RECT  75.36 0 75.384 0.084 ;
    END
  END wq_mask[46]
  PIN wq_mask[47]
    DIRECTION OUTPUT ;
    USE SIGNAL ;
    PORT
      LAYER M5 ;
        RECT  75.792 0 75.816 0.084 ;
    END
  END wq_mask[47]
  PIN wq_mask[48]
    DIRECTION OUTPUT ;
    USE SIGNAL ;
    PORT
      LAYER M5 ;
        RECT  76.224 0 76.248 0.084 ;
    END
  END wq_mask[48]
  PIN wq_mask[49]
    DIRECTION OUTPUT ;
    USE SIGNAL ;
    PORT
      LAYER M5 ;
        RECT  76.656 0 76.68 0.084 ;
    END
  END wq_mask[49]
  PIN wq_mask[4]
    DIRECTION OUTPUT ;
    USE SIGNAL ;
    PORT
      LAYER M5 ;
        RECT  57.216 0 57.24 0.084 ;
    END
  END wq_mask[4]
  PIN wq_mask[50]
    DIRECTION OUTPUT ;
    USE SIGNAL ;
    PORT
      LAYER M5 ;
        RECT  77.088 0 77.112 0.084 ;
    END
  END wq_mask[50]
  PIN wq_mask[51]
    DIRECTION OUTPUT ;
    USE SIGNAL ;
    PORT
      LAYER M5 ;
        RECT  77.52 0 77.544 0.084 ;
    END
  END wq_mask[51]
  PIN wq_mask[52]
    DIRECTION OUTPUT ;
    USE SIGNAL ;
    PORT
      LAYER M5 ;
        RECT  77.952 0 77.976 0.084 ;
    END
  END wq_mask[52]
  PIN wq_mask[53]
    DIRECTION OUTPUT ;
    USE SIGNAL ;
    PORT
      LAYER M5 ;
        RECT  78.384 0 78.408 0.084 ;
    END
  END wq_mask[53]
  PIN wq_mask[54]
    DIRECTION OUTPUT ;
    USE SIGNAL ;
    PORT
      LAYER M5 ;
        RECT  78.816 0 78.84 0.084 ;
    END
  END wq_mask[54]
  PIN wq_mask[55]
    DIRECTION OUTPUT ;
    USE SIGNAL ;
    PORT
      LAYER M5 ;
        RECT  79.248 0 79.272 0.084 ;
    END
  END wq_mask[55]
  PIN wq_mask[56]
    DIRECTION OUTPUT ;
    USE SIGNAL ;
    PORT
      LAYER M5 ;
        RECT  79.68 0 79.704 0.084 ;
    END
  END wq_mask[56]
  PIN wq_mask[57]
    DIRECTION OUTPUT ;
    USE SIGNAL ;
    PORT
      LAYER M5 ;
        RECT  80.112 0 80.136 0.084 ;
    END
  END wq_mask[57]
  PIN wq_mask[58]
    DIRECTION OUTPUT ;
    USE SIGNAL ;
    PORT
      LAYER M5 ;
        RECT  80.544 0 80.568 0.084 ;
    END
  END wq_mask[58]
  PIN wq_mask[59]
    DIRECTION OUTPUT ;
    USE SIGNAL ;
    PORT
      LAYER M5 ;
        RECT  80.976 0 81 0.084 ;
    END
  END wq_mask[59]
  PIN wq_mask[5]
    DIRECTION OUTPUT ;
    USE SIGNAL ;
    PORT
      LAYER M5 ;
        RECT  57.648 0 57.672 0.084 ;
    END
  END wq_mask[5]
  PIN wq_mask[60]
    DIRECTION OUTPUT ;
    USE SIGNAL ;
    PORT
      LAYER M5 ;
        RECT  81.408 0 81.432 0.084 ;
    END
  END wq_mask[60]
  PIN wq_mask[61]
    DIRECTION OUTPUT ;
    USE SIGNAL ;
    PORT
      LAYER M5 ;
        RECT  81.84 0 81.864 0.084 ;
    END
  END wq_mask[61]
  PIN wq_mask[62]
    DIRECTION OUTPUT ;
    USE SIGNAL ;
    PORT
      LAYER M5 ;
        RECT  82.272 0 82.296 0.084 ;
    END
  END wq_mask[62]
  PIN wq_mask[63]
    DIRECTION OUTPUT ;
    USE SIGNAL ;
    PORT
      LAYER M5 ;
        RECT  82.704 0 82.728 0.084 ;
    END
  END wq_mask[63]
  PIN wq_mask[6]
    DIRECTION OUTPUT ;
    USE SIGNAL ;
    PORT
      LAYER M5 ;
        RECT  58.08 0 58.104 0.084 ;
    END
  END wq_mask[6]
  PIN wq_mask[7]
    DIRECTION OUTPUT ;
    USE SIGNAL ;
    PORT
      LAYER M5 ;
        RECT  58.512 0 58.536 0.084 ;
    END
  END wq_mask[7]
  PIN wq_mask[8]
    DIRECTION OUTPUT ;
    USE SIGNAL ;
    PORT
      LAYER M5 ;
        RECT  58.944 0 58.968 0.084 ;
    END
  END wq_mask[8]
  PIN wq_mask[9]
    DIRECTION OUTPUT ;
    USE SIGNAL ;
    PORT
      LAYER M5 ;
        RECT  59.376 0 59.4 0.084 ;
    END
  END wq_mask[9]
  PIN wq_v[0]
    DIRECTION OUTPUT ;
    USE SIGNAL ;
    PORT
      LAYER M5 ;
        RECT  83.136 0 83.16 0.084 ;
    END
  END wq_v[0]
  PIN wq_v[1]
    DIRECTION OUTPUT ;
    USE SIGNAL ;
    PORT
      LAYER M5 ;
        RECT  83.568 0 83.592 0.084 ;
    END
  END wq_v[1]
  PIN wq_v[2]
    DIRECTION OUTPUT ;
    USE SIGNAL ;
    PORT
      LAYER M5 ;
        RECT  84 0 84.024 0.084 ;
    END
  END wq_v[2]
  PIN wq_v[3]
    DIRECTION OUTPUT ;
    USE SIGNAL ;
    PORT
      LAYER M5 ;
        RECT  84.432 0 84.456 0.084 ;
    END
  END wq_v[3]
  PIN wq_v[4]
    DIRECTION OUTPUT ;
    USE SIGNAL ;
    PORT
      LAYER M5 ;
        RECT  84.864 0 84.888 0.084 ;
    END
  END wq_v[4]
  PIN wq_v[5]
    DIRECTION OUTPUT ;
    USE SIGNAL ;
    PORT
      LAYER M5 ;
        RECT  85.296 0 85.32 0.084 ;
    END
  END wq_v[5]
  PIN wq_v[6]
    DIRECTION OUTPUT ;
    USE SIGNAL ;
    PORT
      LAYER M5 ;
        RECT  85.728 0 85.752 0.084 ;
    END
  END wq_v[6]
  PIN wq_v[7]
    DIRECTION OUTPUT ;
    USE SIGNAL ;
    PORT
      LAYER M5 ;
        RECT  86.16 0 86.184 0.084 ;
    END
  END wq_v[7]
  PIN wsel[0]
    DIRECTION OUTPUT ;
    USE SIGNAL ;
    PORT
      LAYER M4 ;
        RECT  86.316 84.816 86.4 84.84 ;
    END
  END wsel[0]
  PIN wsel[1]
    DIRECTION OUTPUT ;
    USE SIGNAL ;
    PORT
      LAYER M4 ;
        RECT  86.316 85.44 86.4 85.464 ;
    END
  END wsel[1]
  PIN wsel[2]
    DIRECTION OUTPUT ;
    USE SIGNAL ;
    PORT
      LAYER M4 ;
        RECT  86.316 86.064 86.4 86.088 ;
    END
  END wsel[2]
  PIN VDD
    DIRECTION INOUT ;
    USE POWER ;
    PORT
      LAYER M5 ;
        RECT  83.592 2.151 83.712 84.249 ;
        RECT  78.192 2.151 78.312 84.249 ;
        RECT  72.792 2.151 72.912 84.249 ;
        RECT  67.392 2.151 67.512 84.249 ;
        RECT  61.992 2.151 62.112 84.249 ;
        RECT  56.592 2.151 56.712 84.249 ;
        RECT  51.192 2.151 51.312 84.249 ;
        RECT  45.792 2.151 45.912 84.249 ;
        RECT  40.392 2.151 40.512 84.249 ;
        RECT  34.992 2.151 35.112 84.249 ;
        RECT  29.592 2.151 29.712 84.249 ;
        RECT  24.192 2.151 24.312 84.249 ;
        RECT  18.792 2.151 18.912 84.249 ;
        RECT  13.392 2.151 13.512 84.249 ;
        RECT  7.992 2.151 8.112 84.249 ;
        RECT  2.592 2.151 2.712 84.249 ;
    END
  END VDD
  PIN VSS
    DIRECTION INOUT ;
    USE GROUND ;
    PORT
      LAYER M5 ;
        RECT  83.4 2.137 83.52 84.263 ;
        RECT  78 2.137 78.12 84.263 ;
        RECT  72.6 2.137 72.72 84.263 ;
        RECT  67.2 2.137 67.32 84.263 ;
        RECT  61.8 2.137 61.92 84.263 ;
        RECT  56.4 2.137 56.52 84.263 ;
        RECT  51 2.137 51.12 84.263 ;
        RECT  45.6 2.137 45.72 84.263 ;
        RECT  40.2 2.137 40.32 84.263 ;
        RECT  34.8 2.137 34.92 84.263 ;
        RECT  29.4 2.137 29.52 84.263 ;
        RECT  24 2.137 24.12 84.263 ;
        RECT  18.6 2.137 18.72 84.263 ;
        RECT  13.2 2.137 13.32 84.263 ;
        RECT  7.8 2.137 7.92 84.263 ;
        RECT  2.4 2.137 2.52 84.263 ;
    END
  END VSS
  # OT_OBS_CLOSED layer=M5 d_um=1.536 added=234
  OBS
    LAYER RVTN ;
     RECT  2.16 2.16 84.24 2.295 ;
     RECT  2.16 2.565 84.24 2.835 ;
     RECT  2.16 3.105 84.24 3.375 ;
     RECT  2.16 3.645 84.24 3.915 ;
     RECT  2.16 4.185 84.24 4.455 ;
     RECT  2.16 4.725 84.24 4.995 ;
     RECT  2.16 5.265 84.24 5.535 ;
     RECT  2.16 5.805 84.24 6.075 ;
     RECT  2.16 6.345 84.24 6.615 ;
     RECT  2.16 6.885 84.24 7.155 ;
     RECT  2.16 7.425 84.24 7.695 ;
     RECT  2.16 7.965 84.24 8.235 ;
     RECT  2.16 8.505 84.24 8.775 ;
     RECT  2.16 9.045 84.24 9.315 ;
     RECT  2.16 9.585 84.24 9.855 ;
     RECT  2.16 10.125 84.24 10.395 ;
     RECT  2.16 10.665 84.24 10.935 ;
     RECT  2.16 11.205 84.24 11.475 ;
     RECT  2.16 11.745 84.24 12.015 ;
     RECT  2.16 12.285 84.24 12.555 ;
     RECT  2.16 12.825 84.24 13.095 ;
     RECT  2.16 13.365 84.24 13.635 ;
     RECT  2.16 13.905 84.24 14.175 ;
     RECT  2.16 14.445 84.24 14.715 ;
     RECT  2.16 14.985 84.24 15.255 ;
     RECT  2.16 15.525 84.24 15.795 ;
     RECT  2.16 16.065 84.24 16.335 ;
     RECT  2.16 16.605 84.24 16.875 ;
     RECT  2.16 17.145 84.24 17.415 ;
     RECT  2.16 17.685 84.24 17.955 ;
     RECT  2.16 18.225 84.24 18.495 ;
     RECT  2.16 18.765 84.24 19.035 ;
     RECT  2.16 19.305 84.24 19.575 ;
     RECT  2.16 19.845 84.24 20.115 ;
     RECT  2.16 20.385 84.24 20.655 ;
     RECT  2.16 20.925 84.24 21.195 ;
     RECT  2.16 21.465 84.24 21.735 ;
     RECT  2.16 22.005 84.24 22.275 ;
     RECT  2.16 22.545 84.24 22.815 ;
     RECT  2.16 23.085 84.24 23.355 ;
     RECT  2.16 23.625 84.24 23.895 ;
     RECT  2.16 24.165 84.24 24.435 ;
     RECT  2.16 24.705 84.24 24.975 ;
     RECT  2.16 25.245 84.24 25.515 ;
     RECT  2.16 25.785 84.24 26.055 ;
     RECT  2.16 26.325 84.24 26.595 ;
     RECT  2.16 26.865 84.24 27.135 ;
     RECT  2.16 27.405 84.24 27.675 ;
     RECT  2.16 27.945 84.24 28.215 ;
     RECT  2.16 28.485 84.24 28.755 ;
     RECT  2.16 29.025 84.24 29.295 ;
     RECT  2.16 29.565 84.24 29.835 ;
     RECT  2.16 30.105 84.24 30.375 ;
     RECT  2.16 30.645 84.24 30.915 ;
     RECT  2.16 31.185 84.24 31.455 ;
     RECT  2.16 31.725 84.24 31.995 ;
     RECT  2.16 32.265 84.24 32.535 ;
     RECT  2.16 32.805 84.24 33.075 ;
     RECT  2.16 33.345 84.24 33.615 ;
     RECT  2.16 33.885 84.24 34.155 ;
     RECT  2.16 34.425 84.24 34.695 ;
     RECT  2.16 34.965 84.24 35.235 ;
     RECT  2.16 35.505 84.24 35.775 ;
     RECT  2.16 36.045 84.24 36.315 ;
     RECT  2.16 36.585 84.24 36.855 ;
     RECT  2.16 37.125 84.24 37.395 ;
     RECT  2.16 37.665 84.24 37.935 ;
     RECT  2.16 38.205 84.24 38.475 ;
     RECT  2.16 38.745 84.24 39.015 ;
     RECT  2.16 39.285 84.24 39.555 ;
     RECT  2.16 39.825 84.24 40.095 ;
     RECT  2.16 40.365 84.24 40.635 ;
     RECT  2.16 40.905 84.24 41.175 ;
     RECT  2.16 41.445 84.24 41.715 ;
     RECT  2.16 41.985 84.24 42.255 ;
     RECT  2.16 42.525 84.24 42.795 ;
     RECT  2.16 43.065 84.24 43.335 ;
     RECT  2.16 43.605 84.24 43.875 ;
     RECT  2.16 44.145 84.24 44.415 ;
     RECT  2.16 44.685 84.24 44.955 ;
     RECT  2.16 45.225 84.24 45.495 ;
     RECT  2.16 45.765 84.24 46.035 ;
     RECT  2.16 46.305 84.24 46.575 ;
     RECT  2.16 46.845 84.24 47.115 ;
     RECT  2.16 47.385 84.24 47.655 ;
     RECT  2.16 47.925 84.24 48.195 ;
     RECT  2.16 48.465 84.24 48.735 ;
     RECT  2.16 49.005 84.24 49.275 ;
     RECT  2.16 49.545 84.24 49.815 ;
     RECT  2.16 50.085 84.24 50.355 ;
     RECT  2.16 50.625 84.24 50.895 ;
     RECT  2.16 51.165 84.24 51.435 ;
     RECT  2.16 51.705 84.24 51.975 ;
     RECT  2.16 52.245 84.24 52.515 ;
     RECT  2.16 52.785 84.24 53.055 ;
     RECT  2.16 53.325 84.24 53.595 ;
     RECT  2.16 53.865 84.24 54.135 ;
     RECT  2.16 54.405 84.24 54.675 ;
     RECT  2.16 54.945 84.24 55.215 ;
     RECT  2.16 55.485 84.24 55.755 ;
     RECT  2.16 56.025 84.24 56.295 ;
     RECT  2.16 56.565 84.24 56.835 ;
     RECT  2.16 57.105 84.24 57.375 ;
     RECT  2.16 57.645 84.24 57.915 ;
     RECT  2.16 58.185 84.24 58.455 ;
     RECT  2.16 58.725 84.24 58.995 ;
     RECT  2.16 59.265 84.24 59.535 ;
     RECT  2.16 59.805 84.24 60.075 ;
     RECT  2.16 60.345 84.24 60.615 ;
     RECT  2.16 60.885 84.24 61.155 ;
     RECT  2.16 61.425 84.24 61.695 ;
     RECT  2.16 61.965 84.24 62.235 ;
     RECT  2.16 62.505 84.24 62.775 ;
     RECT  2.16 63.045 84.24 63.315 ;
     RECT  2.16 63.585 84.24 63.855 ;
     RECT  2.16 64.125 84.24 64.395 ;
     RECT  2.16 64.665 84.24 64.935 ;
     RECT  2.16 65.205 84.24 65.475 ;
     RECT  2.16 65.745 84.24 66.015 ;
     RECT  2.16 66.285 84.24 66.555 ;
     RECT  2.16 66.825 84.24 67.095 ;
     RECT  2.16 67.365 84.24 67.635 ;
     RECT  2.16 67.905 84.24 68.175 ;
     RECT  2.16 68.445 84.24 68.715 ;
     RECT  2.16 68.985 84.24 69.255 ;
     RECT  2.16 69.525 84.24 69.795 ;
     RECT  2.16 70.065 84.24 70.335 ;
     RECT  2.16 70.605 84.24 70.875 ;
     RECT  2.16 71.145 84.24 71.415 ;
     RECT  2.16 71.685 84.24 71.955 ;
     RECT  2.16 72.225 84.24 72.495 ;
     RECT  2.16 72.765 84.24 73.035 ;
     RECT  2.16 73.305 84.24 73.575 ;
     RECT  2.16 73.845 84.24 74.115 ;
     RECT  2.16 74.385 84.24 74.655 ;
     RECT  2.16 74.925 84.24 75.195 ;
     RECT  2.16 75.465 84.24 75.735 ;
     RECT  2.16 76.005 84.24 76.275 ;
     RECT  2.16 76.545 84.24 76.815 ;
     RECT  2.16 77.085 84.24 77.355 ;
     RECT  2.16 77.625 84.24 77.895 ;
     RECT  2.16 78.165 84.24 78.435 ;
     RECT  2.16 78.705 84.24 78.975 ;
     RECT  2.16 79.245 84.24 79.515 ;
     RECT  2.16 79.785 84.24 80.055 ;
     RECT  2.16 80.325 84.24 80.595 ;
     RECT  2.16 80.865 84.24 81.135 ;
     RECT  2.16 81.405 84.24 81.675 ;
     RECT  2.16 81.945 84.24 82.215 ;
     RECT  2.16 82.485 84.24 82.755 ;
     RECT  2.16 83.025 84.24 83.295 ;
     RECT  2.16 83.565 84.24 83.835 ;
     RECT  2.16 84.105 84.24 84.24 ;
    LAYER RVTP ;
     RECT  2.16 2.295 84.24 2.565 ;
     RECT  2.16 2.835 84.24 3.105 ;
     RECT  2.16 3.375 84.24 3.645 ;
     RECT  2.16 3.915 84.24 4.185 ;
     RECT  2.16 4.455 84.24 4.725 ;
     RECT  2.16 4.995 84.24 5.265 ;
     RECT  2.16 5.535 84.24 5.805 ;
     RECT  2.16 6.075 84.24 6.345 ;
     RECT  2.16 6.615 84.24 6.885 ;
     RECT  2.16 7.155 84.24 7.425 ;
     RECT  2.16 7.695 84.24 7.965 ;
     RECT  2.16 8.235 84.24 8.505 ;
     RECT  2.16 8.775 84.24 9.045 ;
     RECT  2.16 9.315 84.24 9.585 ;
     RECT  2.16 9.855 84.24 10.125 ;
     RECT  2.16 10.395 84.24 10.665 ;
     RECT  2.16 10.935 84.24 11.205 ;
     RECT  2.16 11.475 84.24 11.745 ;
     RECT  2.16 12.015 84.24 12.285 ;
     RECT  2.16 12.555 84.24 12.825 ;
     RECT  2.16 13.095 84.24 13.365 ;
     RECT  2.16 13.635 84.24 13.905 ;
     RECT  2.16 14.175 84.24 14.445 ;
     RECT  2.16 14.715 84.24 14.985 ;
     RECT  2.16 15.255 84.24 15.525 ;
     RECT  2.16 15.795 84.24 16.065 ;
     RECT  2.16 16.335 84.24 16.605 ;
     RECT  2.16 16.875 84.24 17.145 ;
     RECT  2.16 17.415 84.24 17.685 ;
     RECT  2.16 17.955 84.24 18.225 ;
     RECT  2.16 18.495 84.24 18.765 ;
     RECT  2.16 19.035 84.24 19.305 ;
     RECT  2.16 19.575 84.24 19.845 ;
     RECT  2.16 20.115 84.24 20.385 ;
     RECT  2.16 20.655 84.24 20.925 ;
     RECT  2.16 21.195 84.24 21.465 ;
     RECT  2.16 21.735 84.24 22.005 ;
     RECT  2.16 22.275 84.24 22.545 ;
     RECT  2.16 22.815 84.24 23.085 ;
     RECT  2.16 23.355 84.24 23.625 ;
     RECT  2.16 23.895 84.24 24.165 ;
     RECT  2.16 24.435 84.24 24.705 ;
     RECT  2.16 24.975 84.24 25.245 ;
     RECT  2.16 25.515 84.24 25.785 ;
     RECT  2.16 26.055 84.24 26.325 ;
     RECT  2.16 26.595 84.24 26.865 ;
     RECT  2.16 27.135 84.24 27.405 ;
     RECT  2.16 27.675 84.24 27.945 ;
     RECT  2.16 28.215 84.24 28.485 ;
     RECT  2.16 28.755 84.24 29.025 ;
     RECT  2.16 29.295 84.24 29.565 ;
     RECT  2.16 29.835 84.24 30.105 ;
     RECT  2.16 30.375 84.24 30.645 ;
     RECT  2.16 30.915 84.24 31.185 ;
     RECT  2.16 31.455 84.24 31.725 ;
     RECT  2.16 31.995 84.24 32.265 ;
     RECT  2.16 32.535 84.24 32.805 ;
     RECT  2.16 33.075 84.24 33.345 ;
     RECT  2.16 33.615 84.24 33.885 ;
     RECT  2.16 34.155 84.24 34.425 ;
     RECT  2.16 34.695 84.24 34.965 ;
     RECT  2.16 35.235 84.24 35.505 ;
     RECT  2.16 35.775 84.24 36.045 ;
     RECT  2.16 36.315 84.24 36.585 ;
     RECT  2.16 36.855 84.24 37.125 ;
     RECT  2.16 37.395 84.24 37.665 ;
     RECT  2.16 37.935 84.24 38.205 ;
     RECT  2.16 38.475 84.24 38.745 ;
     RECT  2.16 39.015 84.24 39.285 ;
     RECT  2.16 39.555 84.24 39.825 ;
     RECT  2.16 40.095 84.24 40.365 ;
     RECT  2.16 40.635 84.24 40.905 ;
     RECT  2.16 41.175 84.24 41.445 ;
     RECT  2.16 41.715 84.24 41.985 ;
     RECT  2.16 42.255 84.24 42.525 ;
     RECT  2.16 42.795 84.24 43.065 ;
     RECT  2.16 43.335 84.24 43.605 ;
     RECT  2.16 43.875 84.24 44.145 ;
     RECT  2.16 44.415 84.24 44.685 ;
     RECT  2.16 44.955 84.24 45.225 ;
     RECT  2.16 45.495 84.24 45.765 ;
     RECT  2.16 46.035 84.24 46.305 ;
     RECT  2.16 46.575 84.24 46.845 ;
     RECT  2.16 47.115 84.24 47.385 ;
     RECT  2.16 47.655 84.24 47.925 ;
     RECT  2.16 48.195 84.24 48.465 ;
     RECT  2.16 48.735 84.24 49.005 ;
     RECT  2.16 49.275 84.24 49.545 ;
     RECT  2.16 49.815 84.24 50.085 ;
     RECT  2.16 50.355 84.24 50.625 ;
     RECT  2.16 50.895 84.24 51.165 ;
     RECT  2.16 51.435 84.24 51.705 ;
     RECT  2.16 51.975 84.24 52.245 ;
     RECT  2.16 52.515 84.24 52.785 ;
     RECT  2.16 53.055 84.24 53.325 ;
     RECT  2.16 53.595 84.24 53.865 ;
     RECT  2.16 54.135 84.24 54.405 ;
     RECT  2.16 54.675 84.24 54.945 ;
     RECT  2.16 55.215 84.24 55.485 ;
     RECT  2.16 55.755 84.24 56.025 ;
     RECT  2.16 56.295 84.24 56.565 ;
     RECT  2.16 56.835 84.24 57.105 ;
     RECT  2.16 57.375 84.24 57.645 ;
     RECT  2.16 57.915 84.24 58.185 ;
     RECT  2.16 58.455 84.24 58.725 ;
     RECT  2.16 58.995 84.24 59.265 ;
     RECT  2.16 59.535 84.24 59.805 ;
     RECT  2.16 60.075 84.24 60.345 ;
     RECT  2.16 60.615 84.24 60.885 ;
     RECT  2.16 61.155 84.24 61.425 ;
     RECT  2.16 61.695 84.24 61.965 ;
     RECT  2.16 62.235 84.24 62.505 ;
     RECT  2.16 62.775 84.24 63.045 ;
     RECT  2.16 63.315 84.24 63.585 ;
     RECT  2.16 63.855 84.24 64.125 ;
     RECT  2.16 64.395 84.24 64.665 ;
     RECT  2.16 64.935 84.24 65.205 ;
     RECT  2.16 65.475 84.24 65.745 ;
     RECT  2.16 66.015 84.24 66.285 ;
     RECT  2.16 66.555 84.24 66.825 ;
     RECT  2.16 67.095 84.24 67.365 ;
     RECT  2.16 67.635 84.24 67.905 ;
     RECT  2.16 68.175 84.24 68.445 ;
     RECT  2.16 68.715 84.24 68.985 ;
     RECT  2.16 69.255 84.24 69.525 ;
     RECT  2.16 69.795 84.24 70.065 ;
     RECT  2.16 70.335 84.24 70.605 ;
     RECT  2.16 70.875 84.24 71.145 ;
     RECT  2.16 71.415 84.24 71.685 ;
     RECT  2.16 71.955 84.24 72.225 ;
     RECT  2.16 72.495 84.24 72.765 ;
     RECT  2.16 73.035 84.24 73.305 ;
     RECT  2.16 73.575 84.24 73.845 ;
     RECT  2.16 74.115 84.24 74.385 ;
     RECT  2.16 74.655 84.24 74.925 ;
     RECT  2.16 75.195 84.24 75.465 ;
     RECT  2.16 75.735 84.24 76.005 ;
     RECT  2.16 76.275 84.24 76.545 ;
     RECT  2.16 76.815 84.24 77.085 ;
     RECT  2.16 77.355 84.24 77.625 ;
     RECT  2.16 77.895 84.24 78.165 ;
     RECT  2.16 78.435 84.24 78.705 ;
     RECT  2.16 78.975 84.24 79.245 ;
     RECT  2.16 79.515 84.24 79.785 ;
     RECT  2.16 80.055 84.24 80.325 ;
     RECT  2.16 80.595 84.24 80.865 ;
     RECT  2.16 81.135 84.24 81.405 ;
     RECT  2.16 81.675 84.24 81.945 ;
     RECT  2.16 82.215 84.24 82.485 ;
     RECT  2.16 82.755 84.24 83.025 ;
     RECT  2.16 83.295 84.24 83.565 ;
     RECT  2.16 83.835 84.24 84.105 ;
    LAYER M1 ;
     RECT  2.16 2.151 84.24 84.249 ;
    LAYER M2 ;
     RECT  0.067 81.576 0.103 81.594 ;
     RECT  1.507 2.196 1.939 2.214 ;
     RECT  1.939 2.106 2.16 2.214 ;
     RECT  0.103 39.87 2.16 39.888 ;
     RECT  0.103 80.874 2.16 81.594 ;
     RECT  0.103 82.8 2.16 82.818 ;
     RECT  2.16 2.106 2.299 84.249 ;
     RECT  2.299 2.106 2.399 84.906 ;
     RECT  2.399 2.106 2.975 84.249 ;
     RECT  2.975 2.151 3.739 84.249 ;
     RECT  3.739 2.151 3.811 84.834 ;
     RECT  3.811 2.151 3.911 84.906 ;
     RECT  3.911 2.151 11.047 84.249 ;
     RECT  11.047 2.106 12.155 84.249 ;
     RECT  22.855 1.152 22.955 1.17 ;
     RECT  24.619 1.152 24.719 1.17 ;
     RECT  58.747 1.152 58.847 1.17 ;
     RECT  12.155 2.151 84.24 84.249 ;
     RECT  84.24 2.304 84.875 3.834 ;
     RECT  84.24 24.786 84.911 28.44 ;
     RECT  84.24 36.666 84.911 37.62 ;
     RECT  84.24 46.782 84.911 65.394 ;
     RECT  84.24 12.222 84.947 14.004 ;
     RECT  84.911 25.326 84.947 28.44 ;
     RECT  84.24 29.196 84.947 35.838 ;
     RECT  84.24 38.484 84.947 39.618 ;
     RECT  84.911 46.782 84.947 51.66 ;
     RECT  84.24 66.222 84.947 70.56 ;
     RECT  84.24 77.796 84.947 83.79 ;
     RECT  84.24 14.76 85.163 17.676 ;
     RECT  84.24 5.202 85.487 9 ;
     RECT  84.24 9.756 85.487 11.394 ;
     RECT  84.947 12.222 85.487 13.464 ;
     RECT  85.163 15.462 85.487 17.676 ;
     RECT  84.24 18.468 85.487 23.814 ;
     RECT  84.947 25.326 85.487 26.658 ;
     RECT  84.947 27.882 85.487 28.44 ;
     RECT  84.947 29.196 85.487 30.978 ;
     RECT  84.947 32.202 85.487 32.22 ;
     RECT  84.947 33.516 85.487 35.838 ;
     RECT  84.911 37.206 85.487 37.62 ;
     RECT  84.947 38.484 85.487 39.24 ;
     RECT  84.24 40.374 85.487 41.004 ;
     RECT  84.24 41.796 85.487 41.904 ;
     RECT  84.24 42.732 85.487 43.524 ;
     RECT  84.24 44.856 85.487 45.954 ;
     RECT  84.947 46.782 85.487 50.418 ;
     RECT  84.947 51.642 85.487 51.66 ;
     RECT  84.911 52.866 85.487 65.394 ;
     RECT  84.947 66.222 85.487 66.24 ;
     RECT  84.947 67.302 85.487 70.56 ;
     RECT  84.24 71.316 85.487 74.034 ;
     RECT  84.24 76.086 85.487 76.734 ;
     RECT  84.947 77.796 85.487 78.12 ;
     RECT  84.947 79.218 85.487 83.79 ;
     RECT  85.487 11.376 85.523 11.394 ;
     RECT  85.487 22.212 85.523 23.814 ;
     RECT  85.487 35.82 85.523 35.838 ;
     RECT  85.487 41.796 85.523 41.814 ;
     RECT  85.487 54.108 85.523 54.702 ;
     RECT  85.487 73.386 85.523 74.034 ;
     RECT  84.875 2.502 85.739 3.834 ;
     RECT  85.487 79.722 86.135 83.79 ;
     RECT  86.135 79.722 86.207 83.664 ;
     RECT  85.739 2.502 86.243 3.6 ;
     RECT  86.243 2.502 86.279 2.52 ;
     RECT  85.487 5.202 86.279 5.76 ;
     RECT  85.523 73.386 86.279 73.53 ;
     RECT  86.207 79.722 86.279 83.214 ;
     RECT  86.243 3.582 86.315 3.6 ;
     RECT  86.279 5.202 86.315 5.22 ;
     RECT  85.487 17.082 86.315 17.676 ;
     RECT  85.523 22.212 86.315 22.806 ;
     RECT  85.487 29.61 86.315 29.628 ;
     RECT  85.487 37.602 86.315 37.62 ;
     RECT  85.487 42.732 86.315 43.326 ;
     RECT  85.487 47.862 86.315 48.996 ;
     RECT  85.523 54.108 86.315 54.126 ;
     RECT  85.487 60.966 86.315 60.984 ;
     RECT  86.279 73.386 86.315 73.404 ;
     RECT  84.24 75.006 86.315 75.024 ;
     RECT  86.279 79.722 86.315 80.352 ;
     RECT  86.279 81.612 86.315 82.476 ;
    LAYER M3 ;
     RECT  5.328 0.091 5.346 0.139 ;
     RECT  6.336 0.091 6.354 0.139 ;
     RECT  42.696 0.091 45.954 0.139 ;
     RECT  47.232 0.091 47.754 0.139 ;
     RECT  48.744 0.091 49.374 0.139 ;
     RECT  50.256 0.091 50.274 0.139 ;
     RECT  51.156 0.091 51.174 0.139 ;
     RECT  51.912 0.091 51.93 0.139 ;
     RECT  52.668 0.091 54.594 0.139 ;
     RECT  55.368 0.091 55.674 0.139 ;
     RECT  48.744 0.139 50.274 0.235 ;
     RECT  51.156 0.139 51.93 0.235 ;
     RECT  8.424 0.091 17.514 0.523 ;
     RECT  18.504 0.091 18.954 0.523 ;
     RECT  19.692 0.091 20.142 0.523 ;
     RECT  20.952 0.091 21.366 0.523 ;
     RECT  22.32 0.091 22.878 0.523 ;
     RECT  35.244 0.091 36.522 0.523 ;
     RECT  39.24 0.091 40.122 0.523 ;
     RECT  41.4 0.091 41.85 0.523 ;
     RECT  42.696 0.139 46.17 0.523 ;
     RECT  48.744 0.235 51.93 0.523 ;
     RECT  52.668 0.139 55.674 0.523 ;
     RECT  56.844 0.091 57.834 0.523 ;
     RECT  58.752 0.091 62.586 0.523 ;
     RECT  69.66 0.091 70.218 0.523 ;
     RECT  71.208 0.091 71.226 0.523 ;
     RECT  71.964 0.091 72.522 0.523 ;
     RECT  73.368 0.091 74.142 0.523 ;
     RECT  78.444 0.091 81.018 0.523 ;
     RECT  81.9 0.091 81.918 0.523 ;
     RECT  82.8 0.091 83.322 0.523 ;
     RECT  84.852 0.091 85.302 0.523 ;
     RECT  86.292 0.283 86.31 0.523 ;
     RECT  2.376 0.139 2.394 0.571 ;
     RECT  3.384 0.091 4.122 0.571 ;
     RECT  7.56 0.091 7.578 0.571 ;
     RECT  8.424 0.523 18.954 0.571 ;
     RECT  2.376 0.571 4.122 1.723 ;
     RECT  5.328 0.139 6.354 1.723 ;
     RECT  7.272 0.571 18.954 1.723 ;
     RECT  19.692 0.523 21.366 1.723 ;
     RECT  22.32 0.523 23.058 1.723 ;
     RECT  24.336 0.091 26.73 1.723 ;
     RECT  27.576 0.091 28.422 1.723 ;
     RECT  29.304 0.091 31.482 1.723 ;
     RECT  32.436 0.091 34.434 1.723 ;
     RECT  35.172 0.523 36.522 1.723 ;
     RECT  37.512 0.091 38.358 1.723 ;
     RECT  39.24 0.523 41.85 1.723 ;
     RECT  42.696 0.523 46.422 1.723 ;
     RECT  48.744 0.523 55.674 1.723 ;
     RECT  56.556 0.523 62.586 1.723 ;
     RECT  63.432 0.091 66.15 1.723 ;
     RECT  66.888 0.091 67.662 1.723 ;
     RECT  68.616 0.091 68.922 1.723 ;
     RECT  69.66 0.523 71.226 1.723 ;
     RECT  71.964 0.523 74.718 1.723 ;
     RECT  75.456 0.091 76.302 1.723 ;
     RECT  77.22 0.091 77.238 1.723 ;
     RECT  78.336 0.523 81.018 1.723 ;
     RECT  81.9 0.523 83.574 1.723 ;
     RECT  1.512 1.723 4.554 2.129 ;
     RECT  22.176 1.723 34.434 2.143 ;
     RECT  35.172 1.723 46.422 2.143 ;
     RECT  5.328 1.723 21.366 2.191 ;
     RECT  48.744 1.723 68.922 2.191 ;
     RECT  69.66 1.723 83.574 2.191 ;
     RECT  84.42 0.523 86.31 2.191 ;
     RECT  1.512 2.129 1.53 2.219 ;
     RECT  5.328 2.191 21.438 2.227 ;
     RECT  22.176 2.143 46.422 2.227 ;
     RECT  2.304 2.129 4.554 2.371 ;
     RECT  5.328 2.227 46.422 2.371 ;
     RECT  47.232 0.139 47.934 2.371 ;
     RECT  48.744 2.191 86.31 2.371 ;
     RECT  2.304 2.371 86.31 2.759 ;
     RECT  2.304 2.759 84.942 2.813 ;
     RECT  2.304 2.813 84.438 2.939 ;
     RECT  2.304 2.939 83.97 3.299 ;
     RECT  72.396 3.299 83.97 3.713 ;
     RECT  2.304 3.299 71.658 3.839 ;
     RECT  73.62 3.713 83.97 3.839 ;
     RECT  85.716 2.759 86.31 3.839 ;
     RECT  73.62 3.839 74.574 3.875 ;
     RECT  6.552 3.839 6.966 4.109 ;
     RECT  9.792 3.839 71.658 4.109 ;
     RECT  73.656 3.875 74.574 4.109 ;
     RECT  75.312 3.839 83.97 4.109 ;
     RECT  64.98 4.109 71.658 4.202 ;
     RECT  72.396 3.713 72.897 4.202 ;
     RECT  0.108 4.075 0.126 4.205 ;
     RECT  9.792 4.109 53.334 4.253 ;
     RECT  79.704 4.109 83.97 4.261 ;
     RECT  2.34 3.839 5.778 4.289 ;
     RECT  9.792 4.253 51.93 4.301 ;
     RECT  7.704 3.839 8.658 4.379 ;
     RECT  9.792 4.301 15.138 4.379 ;
     RECT  15.912 4.301 51.93 4.379 ;
     RECT  54.072 4.109 64.206 4.379 ;
     RECT  64.98 4.202 72.897 4.379 ;
     RECT  58.608 4.379 63.27 4.397 ;
     RECT  64.044 4.379 64.062 4.397 ;
     RECT  65.196 4.379 65.214 4.402 ;
     RECT  15.912 4.379 51.714 4.415 ;
     RECT  52.956 4.253 53.334 4.415 ;
     RECT  54.072 4.379 55.278 4.415 ;
     RECT  74.448 4.109 74.574 4.415 ;
     RECT  75.564 4.109 78.894 4.415 ;
     RECT  2.34 4.289 5.634 4.451 ;
     RECT  15.912 4.415 51.642 4.451 ;
     RECT  6.732 4.109 6.93 4.487 ;
     RECT  52.956 4.415 53.226 4.487 ;
     RECT  54.9 4.415 55.278 4.493 ;
     RECT  68.436 4.379 70.146 4.493 ;
     RECT  6.804 4.487 6.93 4.523 ;
     RECT  15.912 4.451 20.178 4.523 ;
     RECT  7.704 4.379 8.097 4.541 ;
     RECT  9.792 4.379 15.03 4.541 ;
     RECT  54.072 4.415 54.09 4.559 ;
     RECT  79.704 4.261 84.114 4.559 ;
     RECT  9.972 4.541 15.03 4.649 ;
     RECT  21.096 4.451 51.642 4.649 ;
     RECT  56.415 4.379 57.834 4.649 ;
     RECT  58.608 4.397 61.002 4.649 ;
     RECT  61.815 4.397 63.27 4.649 ;
     RECT  65.988 4.379 67.698 4.649 ;
     RECT  68.436 4.493 68.454 4.649 ;
     RECT  69.372 4.493 70.146 4.649 ;
     RECT  76.644 4.415 78.894 4.649 ;
     RECT  80.352 4.559 84.114 4.649 ;
     RECT  9.972 4.649 14.094 4.685 ;
     RECT  15.912 4.523 20.07 4.685 ;
     RECT  21.096 4.649 51.498 4.685 ;
     RECT  52.956 4.487 53.19 4.685 ;
     RECT  54.9 4.493 55.026 4.685 ;
     RECT  59.04 4.649 61.002 4.685 ;
     RECT  69.372 4.649 69.39 4.685 ;
     RECT  71.1 4.379 71.694 4.685 ;
     RECT  77.184 4.649 78.822 4.685 ;
     RECT  86.292 3.839 86.31 4.699 ;
     RECT  15.912 4.685 19.278 4.721 ;
     RECT  18.036 4.721 19.278 4.757 ;
     RECT  71.1 4.685 71.118 4.757 ;
     RECT  2.34 4.451 5.562 4.801 ;
     RECT  52.956 4.685 52.974 4.829 ;
     RECT  54.9 4.685 54.918 4.829 ;
     RECT  66.132 4.649 67.626 4.829 ;
     RECT  74.664 4.729 74.682 4.829 ;
     RECT  75.744 4.415 75.834 4.877 ;
     RECT  9.972 4.685 13.497 4.919 ;
     RECT  15.912 4.721 17.226 4.919 ;
     RECT  21.096 4.685 51.462 4.919 ;
     RECT  59.04 4.685 60.21 4.919 ;
     RECT  61.815 4.649 62.73 4.919 ;
     RECT  67.215 4.829 67.626 4.919 ;
     RECT  77.184 4.685 78.678 4.919 ;
     RECT  9.972 4.919 11.07 4.955 ;
     RECT  16.704 4.919 16.902 4.955 ;
     RECT  21.096 4.919 44.226 4.955 ;
     RECT  59.04 4.919 59.058 4.955 ;
     RECT  77.184 4.919 77.202 4.955 ;
     RECT  14.868 4.649 14.994 4.991 ;
     RECT  18.036 4.757 18.897 4.991 ;
     RECT  21.096 4.955 42.786 4.991 ;
     RECT  45 4.919 51.426 4.991 ;
     RECT  59.832 4.919 60.21 4.991 ;
     RECT  75.816 4.877 75.834 4.991 ;
     RECT  6.804 4.523 6.822 5.027 ;
     RECT  14.868 4.991 14.922 5.027 ;
     RECT  56.415 4.649 57.69 5.027 ;
     RECT  16.704 4.955 16.722 5.063 ;
     RECT  21.816 4.991 42.786 5.063 ;
     RECT  45 4.991 49.734 5.063 ;
     RECT  45 5.063 49.374 5.069 ;
     RECT  14.904 5.027 14.922 5.099 ;
     RECT  18.144 4.991 18.897 5.099 ;
     RECT  50.508 4.991 51.426 5.099 ;
     RECT  81.108 4.649 84.114 5.099 ;
     RECT  2.304 4.801 5.562 5.189 ;
     RECT  10.8 4.955 11.07 5.189 ;
     RECT  11.844 4.919 13.497 5.189 ;
     RECT  43.74 4.955 44.154 5.213 ;
     RECT  22.212 5.063 42.786 5.225 ;
     RECT  86.256 4.699 86.31 5.225 ;
     RECT  12.564 5.189 13.497 5.261 ;
     RECT  9.972 4.955 10.026 5.333 ;
     RECT  15.912 4.919 15.93 5.369 ;
     RECT  50.508 5.099 51.297 5.369 ;
     RECT  78.015 4.919 78.678 5.369 ;
     RECT  22.212 5.225 40.878 5.459 ;
     RECT  60.984 4.685 61.002 5.459 ;
     RECT  66.132 4.829 66.15 5.495 ;
     RECT  10.836 5.189 11.07 5.531 ;
     RECT  41.688 5.225 42.786 5.531 ;
     RECT  22.212 5.459 38.682 5.603 ;
     RECT  60.66 5.467 60.75 5.603 ;
     RECT  20.052 4.685 20.07 5.639 ;
     RECT  27.864 5.603 38.682 5.639 ;
     RECT  7.815 4.541 8.097 5.707 ;
     RECT  27.864 5.639 34.074 5.729 ;
     RECT  34.815 5.639 38.682 5.729 ;
     RECT  60.732 5.603 60.75 5.729 ;
     RECT  61.815 4.919 62.622 5.737 ;
     RECT  70.128 4.649 70.146 5.737 ;
     RECT  22.212 5.603 26.838 5.765 ;
     RECT  86.256 5.225 86.274 5.765 ;
     RECT  45 5.069 49.086 5.789 ;
     RECT  10.008 5.333 10.026 5.801 ;
     RECT  61.815 5.737 62.73 5.809 ;
     RECT  2.304 5.189 4.626 5.873 ;
     RECT  10.836 5.531 10.854 5.909 ;
     RECT  22.716 5.765 26.838 5.909 ;
     RECT  43.74 5.213 43.758 5.909 ;
     RECT  58.716 5.809 58.734 5.909 ;
     RECT  61.815 5.809 62.802 5.909 ;
     RECT  7.128 5.707 8.097 5.999 ;
     RECT  28.908 5.729 34.074 5.999 ;
     RECT  41.688 5.531 41.706 5.999 ;
     RECT  70.128 5.737 70.218 5.999 ;
     RECT  2.34 5.873 4.626 6.035 ;
     RECT  39.564 5.459 40.878 6.043 ;
     RECT  45.108 5.789 49.086 6.043 ;
     RECT  70.2 5.999 70.218 6.079 ;
     RECT  81.576 5.099 84.114 6.139 ;
     RECT  56.415 5.027 57.438 6.143 ;
     RECT  2.376 6.035 4.626 6.151 ;
     RECT  78.015 5.369 78.39 6.173 ;
     RECT  23.184 5.909 26.838 6.179 ;
     RECT  45.108 6.043 49.302 6.179 ;
     RECT  61.815 5.909 62.478 6.179 ;
     RECT  2.376 6.151 4.734 6.269 ;
     RECT  23.184 6.179 25.686 6.269 ;
     RECT  39.564 6.043 40.986 6.269 ;
     RECT  42.768 5.531 42.786 6.269 ;
     RECT  45.108 6.179 49.23 6.269 ;
     RECT  81.144 6.139 84.114 6.269 ;
     RECT  4.212 6.269 4.41 6.305 ;
     RECT  29.016 5.999 34.074 6.305 ;
     RECT  39.564 6.269 40.878 6.305 ;
     RECT  82.368 6.269 83.79 6.305 ;
     RECT  23.184 6.269 25.506 6.341 ;
     RECT  59.832 4.991 59.85 6.341 ;
     RECT  4.392 6.305 4.41 6.365 ;
     RECT  23.292 6.341 25.182 6.413 ;
     RECT  32.544 6.305 34.074 6.421 ;
     RECT  34.815 5.729 37.53 6.421 ;
     RECT  26.496 6.179 26.838 6.523 ;
     RECT  27.864 5.729 28.098 6.523 ;
     RECT  56.415 6.143 57.042 6.539 ;
     RECT  24.015 6.413 25.182 6.575 ;
     RECT  45.108 6.269 48.906 6.575 ;
     RECT  45.108 6.575 47.862 6.647 ;
     RECT  48.888 6.575 48.906 6.647 ;
     RECT  82.368 6.305 83.754 6.647 ;
     RECT  32.544 6.421 37.53 6.653 ;
     RECT  83.124 6.647 83.754 6.683 ;
     RECT  26.496 6.523 28.098 6.691 ;
     RECT  39.564 6.305 40.842 6.809 ;
     RECT  45.108 6.647 46.35 6.809 ;
     RECT  39.564 6.809 40.698 6.845 ;
     RECT  47.16 6.647 47.358 6.845 ;
     RECT  26.496 6.691 28.242 6.961 ;
     RECT  29.016 6.305 31.518 6.961 ;
     RECT  38.664 5.729 38.682 7.003 ;
     RECT  47.268 6.845 47.358 7.079 ;
     RECT  70.2 6.079 70.398 7.079 ;
     RECT  83.196 6.683 83.754 7.079 ;
     RECT  82.368 6.647 82.386 7.151 ;
     RECT  26.496 6.961 31.518 7.159 ;
     RECT  83.196 7.079 83.697 7.223 ;
     RECT  47.268 7.079 47.322 7.259 ;
     RECT  25.02 6.575 25.074 7.321 ;
     RECT  26.496 7.159 31.914 7.321 ;
     RECT  45.108 6.809 46.026 7.321 ;
     RECT  32.688 6.653 37.53 7.465 ;
     RECT  38.628 7.003 38.682 7.465 ;
     RECT  32.688 7.465 38.682 7.501 ;
     RECT  39.564 6.845 40.497 7.501 ;
     RECT  45.072 7.321 46.026 7.501 ;
     RECT  5.544 5.189 5.562 7.579 ;
     RECT  45.036 7.501 46.026 7.619 ;
     RECT  5.544 7.579 6.21 7.655 ;
     RECT  45.036 7.619 45.954 7.655 ;
     RECT  45.036 7.655 45.897 7.771 ;
     RECT  32.652 7.501 40.497 7.799 ;
     RECT  5.544 7.655 5.562 7.861 ;
     RECT  6.336 7.771 6.354 7.889 ;
     RECT  32.652 7.799 39.006 7.889 ;
     RECT  3.564 7.771 3.582 7.925 ;
     RECT  24.015 6.575 24.297 7.933 ;
     RECT  25.02 7.321 31.914 7.933 ;
     RECT  44.856 7.771 45.897 7.933 ;
     RECT  4.932 7.861 5.562 7.961 ;
     RECT  32.652 7.889 36.45 7.997 ;
     RECT  37.764 7.889 39.006 7.997 ;
     RECT  24.015 7.933 31.914 8.041 ;
     RECT  32.652 7.997 36.234 8.041 ;
     RECT  44.784 7.933 45.897 8.069 ;
     RECT  38.052 7.997 39.006 8.159 ;
     RECT  38.052 8.159 38.79 8.195 ;
     RECT  43.704 8.251 43.722 8.303 ;
     RECT  44.784 8.069 44.874 8.311 ;
     RECT  21.78 8.395 21.798 8.443 ;
     RECT  21.636 8.443 21.798 8.491 ;
     RECT  24.015 8.041 36.234 8.509 ;
     RECT  21.456 8.491 21.798 8.537 ;
     RECT  23.868 8.509 36.234 8.581 ;
     RECT  43.776 8.311 43.974 8.699 ;
     RECT  44.748 8.311 44.874 8.699 ;
     RECT  44.748 8.699 44.766 8.735 ;
     RECT  36.972 8.815 36.99 8.851 ;
     RECT  38.052 8.195 38.682 8.851 ;
     RECT  23.724 8.581 36.234 8.941 ;
     RECT  2.415 6.269 2.697 8.968 ;
     RECT  2.304 8.968 2.697 9.005 ;
     RECT  23.112 8.941 36.234 9.005 ;
     RECT  22.284 8.941 22.302 9.067 ;
     RECT  23.112 9.005 35.478 9.067 ;
     RECT  2.415 9.005 2.697 9.121 ;
     RECT  36.972 8.851 38.682 9.163 ;
     RECT  2.415 9.121 3.222 9.239 ;
     RECT  4.428 9.163 4.446 9.391 ;
     RECT  3.564 9.391 3.582 9.481 ;
     RECT  4.428 9.391 4.59 9.481 ;
     RECT  22.284 9.067 35.478 9.499 ;
     RECT  3.564 9.481 4.59 9.509 ;
     RECT  43.776 8.699 43.794 9.509 ;
     RECT  3.564 9.509 4.086 9.545 ;
     RECT  4.068 9.545 4.086 9.581 ;
     RECT  42.624 9.115 42.642 9.661 ;
     RECT  36.396 9.163 38.682 9.725 ;
     RECT  21.888 9.499 35.478 9.739 ;
     RECT  36.54 9.725 38.682 9.815 ;
     RECT  42.624 9.661 42.894 10.049 ;
     RECT  21.276 9.739 35.478 10.165 ;
     RECT  20.7 10.165 35.478 10.201 ;
     RECT  20.7 10.201 35.802 10.315 ;
     RECT  20.34 10.315 35.802 10.319 ;
     RECT  42.624 10.049 42.642 10.319 ;
     RECT  20.34 10.319 35.694 10.355 ;
     RECT  36.54 9.815 36.666 10.355 ;
     RECT  5.544 7.961 5.562 10.555 ;
     RECT  37.908 9.815 38.682 10.589 ;
     RECT  42.516 10.471 42.534 10.589 ;
     RECT  2.415 9.239 2.697 10.597 ;
     RECT  37.908 10.589 38.07 10.597 ;
     RECT  2.34 10.597 2.697 10.637 ;
     RECT  37.728 10.597 38.07 10.637 ;
     RECT  20.34 10.355 23.022 10.705 ;
     RECT  5.472 10.555 5.562 10.741 ;
     RECT  41.328 10.696 41.346 10.741 ;
     RECT  42.48 10.669 42.498 10.741 ;
     RECT  3.708 10.741 3.726 10.831 ;
     RECT  5.112 10.741 5.562 10.859 ;
     RECT  42.372 10.741 42.498 10.859 ;
     RECT  18.615 5.099 18.897 10.867 ;
     RECT  3.708 10.831 3.906 10.895 ;
     RECT  42.372 10.859 42.39 10.895 ;
     RECT  3.888 10.895 3.906 10.931 ;
     RECT  18.252 10.867 18.897 10.975 ;
     RECT  19.728 10.705 23.022 10.975 ;
     RECT  85.464 5.323 85.482 10.976 ;
     RECT  18.252 10.975 23.022 11.011 ;
     RECT  6.984 10.741 7.002 11.129 ;
     RECT  23.796 10.355 35.694 11.129 ;
     RECT  41.328 10.741 41.49 11.129 ;
     RECT  18.18 11.011 23.022 11.173 ;
     RECT  23.796 11.129 35.097 11.173 ;
     RECT  18.18 11.173 35.097 11.245 ;
     RECT  40.215 7.799 40.497 11.281 ;
     RECT  14.832 11.209 14.85 11.309 ;
     RECT  36.936 10.603 36.954 11.371 ;
     RECT  17.748 11.245 35.097 11.407 ;
     RECT  40.215 11.281 41.094 11.419 ;
     RECT  36.468 11.371 36.954 11.551 ;
     RECT  37.872 10.637 38.07 11.551 ;
     RECT  85.5 11.371 85.518 11.597 ;
     RECT  17.136 11.407 35.097 11.705 ;
     RECT  17.136 11.705 21.726 11.939 ;
     RECT  39.924 11.419 41.094 11.939 ;
     RECT  36.468 11.551 38.07 11.941 ;
     RECT  39.924 11.939 40.986 11.975 ;
     RECT  17.136 11.939 19.062 11.981 ;
     RECT  36 11.941 38.07 11.981 ;
     RECT  5.544 10.859 5.562 11.995 ;
     RECT  2.415 10.637 2.697 12.187 ;
     RECT  17.136 11.981 18.954 12.209 ;
     RECT  36.288 11.981 38.07 12.209 ;
     RECT  2.304 12.187 2.697 12.245 ;
     RECT  36.288 12.209 37.098 12.245 ;
     RECT  18.288 12.209 18.954 12.281 ;
     RECT  22.5 11.705 35.097 12.317 ;
     RECT  2.415 12.245 2.697 12.361 ;
     RECT  7.815 5.999 8.097 12.361 ;
     RECT  15.084 12.181 15.102 12.361 ;
     RECT  15.876 12.325 16.362 12.361 ;
     RECT  17.136 12.209 17.55 12.361 ;
     RECT  7.092 12.361 8.097 12.413 ;
     RECT  5.544 11.995 5.67 12.427 ;
     RECT  19.98 11.939 21.726 12.451 ;
     RECT  22.5 12.317 33.894 12.451 ;
     RECT  2.415 12.361 2.898 12.479 ;
     RECT  15.876 12.361 17.55 12.479 ;
     RECT  36.288 12.245 36.414 12.479 ;
     RECT  15.084 12.361 15.138 12.487 ;
     RECT  19.98 12.451 33.894 12.515 ;
     RECT  37.908 12.209 38.07 12.523 ;
     RECT  39.924 11.975 40.497 12.523 ;
     RECT  5.292 12.427 5.67 12.557 ;
     RECT  14.94 12.487 15.138 12.631 ;
     RECT  14.94 12.631 15.246 12.721 ;
     RECT  18.615 12.281 18.954 12.721 ;
     RECT  19.98 12.515 32.814 12.721 ;
     RECT  5.292 12.557 5.562 12.749 ;
     RECT  45.615 8.069 45.897 12.757 ;
     RECT  3.96 12.631 3.978 12.785 ;
     RECT  15.984 12.479 17.55 12.785 ;
     RECT  18.615 12.721 32.814 12.785 ;
     RECT  34.815 12.317 35.097 12.859 ;
     RECT  13.215 5.261 13.497 12.865 ;
     RECT  14.508 12.721 15.246 12.865 ;
     RECT  34.815 12.859 35.154 12.901 ;
     RECT  36.288 12.479 36.342 12.901 ;
     RECT  34.815 12.901 36.342 13.019 ;
     RECT  37.908 12.523 38.79 13.019 ;
     RECT  33.552 12.515 33.894 13.051 ;
     RECT  34.815 13.019 36.09 13.051 ;
     RECT  33.552 13.051 36.09 13.055 ;
     RECT  18.615 12.785 32.778 13.063 ;
     RECT  45.615 12.757 46.206 13.091 ;
     RECT  39.888 12.523 40.497 13.171 ;
     RECT  18.144 13.063 32.778 13.289 ;
     RECT  33.552 13.055 35.946 13.289 ;
     RECT  38.808 13.171 39.006 13.289 ;
     RECT  39.78 13.171 40.497 13.325 ;
     RECT  13.215 12.865 15.246 13.405 ;
     RECT  15.984 12.785 16.758 13.405 ;
     RECT  13.215 13.405 16.758 13.469 ;
     RECT  85.464 12.187 85.482 13.469 ;
     RECT  16.128 13.469 16.758 13.531 ;
     RECT  18.144 13.289 32.742 13.559 ;
     RECT  13.215 13.469 15.282 13.567 ;
     RECT  16.128 13.531 17.082 13.567 ;
     RECT  18.144 13.559 32.67 13.595 ;
     RECT  16.128 13.567 17.226 13.711 ;
     RECT  18.144 13.595 32.418 13.711 ;
     RECT  2.415 12.479 2.697 13.819 ;
     RECT  16.128 13.711 32.418 13.829 ;
     RECT  33.876 13.289 35.946 13.829 ;
     RECT  2.34 13.819 2.697 13.865 ;
     RECT  12.888 13.567 15.282 13.865 ;
     RECT  16.128 13.829 32.058 13.865 ;
     RECT  33.876 13.829 35.406 13.865 ;
     RECT  12.888 13.865 13.77 13.937 ;
     RECT  16.128 13.865 31.986 13.973 ;
     RECT  12.888 13.937 13.59 13.981 ;
     RECT  37.908 13.019 38.07 13.981 ;
     RECT  84.924 13.981 84.942 14.093 ;
     RECT  3.564 13.981 3.582 14.135 ;
     RECT  7.815 12.413 8.097 14.203 ;
     RECT  16.128 13.973 20.43 14.215 ;
     RECT  7.272 14.203 8.097 14.243 ;
     RECT  10.836 14.143 10.854 14.243 ;
     RECT  38.808 13.289 38.826 14.369 ;
     RECT  21.204 13.973 31.986 14.405 ;
     RECT  14.508 13.865 15.282 14.449 ;
     RECT  16.02 14.215 20.43 14.449 ;
     RECT  11.412 14.485 11.43 14.521 ;
     RECT  12.42 13.981 13.59 14.521 ;
     RECT  33.876 13.865 35.097 14.521 ;
     RECT  31.968 14.405 31.986 14.639 ;
     RECT  21.204 14.405 31.23 14.675 ;
     RECT  33.588 14.521 35.097 14.675 ;
     RECT  85.14 14.683 85.158 14.783 ;
     RECT  14.508 14.449 20.43 14.791 ;
     RECT  21.204 14.675 27.234 14.791 ;
     RECT  11.412 14.521 13.59 14.945 ;
     RECT  36.576 14.875 36.594 14.945 ;
     RECT  11.412 14.945 12.474 15.025 ;
     RECT  13.215 14.945 13.59 15.025 ;
     RECT  14.508 14.791 27.234 15.025 ;
     RECT  32.04 14.755 32.058 15.061 ;
     RECT  32.832 14.827 32.85 15.061 ;
     RECT  33.588 14.675 34.038 15.061 ;
     RECT  37.62 13.981 38.07 15.061 ;
     RECT  11.16 15.025 12.474 15.089 ;
     RECT  28.656 14.675 31.23 15.179 ;
     RECT  32.04 15.061 34.038 15.179 ;
     RECT  36.684 15.061 38.07 15.215 ;
     RECT  11.16 15.089 12.114 15.403 ;
     RECT  36.684 15.215 36.846 15.449 ;
     RECT  2.415 13.865 2.697 15.451 ;
     RECT  10.512 15.403 12.114 15.485 ;
     RECT  13.215 15.025 27.234 15.485 ;
     RECT  37.62 15.215 38.07 15.485 ;
     RECT  32.04 15.179 33.894 15.565 ;
     RECT  18.576 15.485 27.234 15.601 ;
     RECT  28.656 15.179 31.122 15.601 ;
     RECT  34.815 14.675 35.097 15.601 ;
     RECT  34.776 15.601 35.097 15.643 ;
     RECT  32.004 15.565 33.894 15.719 ;
     RECT  36.684 15.449 36.702 15.719 ;
     RECT  2.304 15.451 2.697 15.755 ;
     RECT  13.215 15.485 17.73 15.755 ;
     RECT  28.548 15.601 31.122 15.755 ;
     RECT  32.004 15.719 32.958 15.755 ;
     RECT  6.84 15.763 6.858 15.863 ;
     RECT  13.215 15.755 16.758 15.871 ;
     RECT  34.776 15.643 35.55 15.871 ;
     RECT  34.776 15.871 35.694 15.899 ;
     RECT  29.088 15.755 31.122 15.931 ;
     RECT  32.004 15.755 32.418 15.931 ;
     RECT  18.576 15.601 27.81 15.979 ;
     RECT  3.924 15.871 4.59 15.989 ;
     RECT  3.924 15.989 4.194 16.025 ;
     RECT  10.512 15.485 11.61 16.025 ;
     RECT  12.744 15.871 16.758 16.025 ;
     RECT  4.176 16.025 4.194 16.061 ;
     RECT  9.072 6.151 9.09 16.141 ;
     RECT  10.512 16.025 11.214 16.141 ;
     RECT  9.072 16.141 11.214 16.169 ;
     RECT  12.744 16.025 16.002 16.259 ;
     RECT  36.468 15.871 36.63 16.259 ;
     RECT  12.744 16.259 13.698 16.261 ;
     RECT  12.024 16.261 13.698 16.295 ;
     RECT  14.472 16.259 16.002 16.295 ;
     RECT  36.468 16.259 36.486 16.295 ;
     RECT  17.712 15.755 17.73 16.411 ;
     RECT  18.576 15.979 28.35 16.411 ;
     RECT  17.712 16.411 28.35 16.501 ;
     RECT  29.088 15.931 32.418 16.529 ;
     RECT  34.815 15.899 35.694 16.529 ;
     RECT  47.268 7.259 47.286 16.529 ;
     RECT  29.088 16.529 32.274 16.565 ;
     RECT  9.072 16.169 10.926 16.601 ;
     RECT  85.464 15.307 85.482 16.601 ;
     RECT  7.815 14.243 8.097 16.645 ;
     RECT  9.072 16.601 10.854 16.645 ;
     RECT  33.876 15.719 33.894 16.795 ;
     RECT  34.815 16.529 35.586 16.795 ;
     RECT  17.28 16.501 28.35 16.799 ;
     RECT  33.876 16.795 35.586 16.799 ;
     RECT  14.472 16.295 15.282 16.835 ;
     RECT  17.28 16.799 25.974 16.835 ;
     RECT  26.748 16.799 28.35 16.835 ;
     RECT  17.28 16.835 23.022 16.915 ;
     RECT  12.024 16.295 13.554 16.951 ;
     RECT  27.432 16.835 28.35 16.951 ;
     RECT  29.088 16.565 31.698 16.951 ;
     RECT  11.592 16.951 13.554 17.041 ;
     RECT  16.38 16.915 23.022 17.069 ;
     RECT  2.415 15.755 2.697 17.077 ;
     RECT  16.38 17.069 21.906 17.105 ;
     RECT  27.432 16.951 31.698 17.105 ;
     RECT  2.415 17.077 2.97 17.117 ;
     RECT  14.472 16.835 14.526 17.117 ;
     RECT  11.592 17.041 13.734 17.221 ;
     RECT  14.472 17.117 14.49 17.221 ;
     RECT  33.876 16.799 35.406 17.339 ;
     RECT  4.176 17.077 4.194 17.375 ;
     RECT  7.815 16.645 10.854 17.455 ;
     RECT  11.592 17.221 14.49 17.455 ;
     RECT  33.876 17.339 35.37 17.483 ;
     RECT  5.544 12.749 5.562 17.491 ;
     RECT  15.588 17.185 15.606 17.491 ;
     RECT  16.38 17.105 20.682 17.491 ;
     RECT  7.815 17.455 14.49 17.581 ;
     RECT  27.432 17.105 30.834 17.609 ;
     RECT  23.796 16.835 25.974 17.611 ;
     RECT  4.572 17.455 4.59 17.645 ;
     RECT  7.488 17.581 14.49 17.645 ;
     RECT  27.432 17.609 30.582 17.645 ;
     RECT  27.432 17.645 30.15 17.725 ;
     RECT  22.68 17.069 23.022 17.761 ;
     RECT  23.796 17.611 26.334 17.761 ;
     RECT  27.36 17.725 30.15 17.761 ;
     RECT  32.976 17.608 32.994 17.761 ;
     RECT  33.876 17.483 35.097 17.761 ;
     RECT  86.292 17.077 86.31 17.837 ;
     RECT  7.488 17.645 13.734 17.851 ;
     RECT  7.272 17.851 13.734 17.879 ;
     RECT  22.68 17.761 30.15 17.879 ;
     RECT  7.272 17.879 13.59 17.915 ;
     RECT  15.588 17.491 20.682 17.915 ;
     RECT  32.976 17.761 35.097 17.951 ;
     RECT  7.272 17.915 13.497 17.987 ;
     RECT  22.68 17.879 28.026 17.987 ;
     RECT  21.672 17.105 21.906 17.995 ;
     RECT  15.588 17.915 16.074 18.031 ;
     RECT  17.208 17.915 20.682 18.031 ;
     RECT  21.636 17.995 21.906 18.031 ;
     RECT  32.976 17.951 33.894 18.149 ;
     RECT  5.508 17.491 5.562 18.427 ;
     RECT  7.272 17.987 11.25 18.463 ;
     RECT  15.012 18.031 16.074 18.535 ;
     RECT  17.208 18.031 21.906 18.571 ;
     RECT  22.68 17.987 27.234 18.571 ;
     RECT  7.056 18.463 11.25 18.661 ;
     RECT  12.168 17.987 13.497 18.697 ;
     RECT  14.436 18.535 16.074 18.697 ;
     RECT  17.208 18.571 27.234 18.697 ;
     RECT  2.415 17.117 2.697 18.715 ;
     RECT  17.136 18.697 27.234 18.725 ;
     RECT  28.008 17.987 28.026 18.725 ;
     RECT  5.508 18.427 6.102 18.769 ;
     RECT  7.02 18.661 11.25 18.769 ;
     RECT  21.204 18.725 27.234 18.797 ;
     RECT  5.508 18.769 11.25 18.811 ;
     RECT  5.292 18.811 11.25 18.841 ;
     RECT  12.168 18.697 16.074 18.841 ;
     RECT  17.136 18.725 20.25 18.841 ;
     RECT  28.8 17.879 30.15 18.841 ;
     RECT  31.86 17.467 31.878 18.841 ;
     RECT  32.976 18.149 32.994 18.841 ;
     RECT  28.296 18.841 30.15 18.859 ;
     RECT  5.292 18.841 20.25 18.959 ;
     RECT  21.312 18.797 27.234 18.959 ;
     RECT  28.296 18.859 30.834 18.959 ;
     RECT  32.868 18.841 32.994 18.959 ;
     RECT  2.415 18.715 2.754 18.995 ;
     RECT  5.292 18.959 14.634 18.995 ;
     RECT  22.14 18.959 27.234 18.995 ;
     RECT  29.088 18.959 30.834 18.995 ;
     RECT  32.868 18.959 32.886 18.995 ;
     RECT  5.292 18.995 11.682 19.111 ;
     RECT  22.248 18.995 27.234 19.201 ;
     RECT  22.248 19.201 27.414 19.229 ;
     RECT  31.86 18.841 32.13 19.229 ;
     RECT  4.572 19.111 11.682 19.265 ;
     RECT  22.248 19.229 26.118 19.265 ;
     RECT  26.928 19.229 27.414 19.265 ;
     RECT  29.415 18.995 30.834 19.381 ;
     RECT  31.86 19.229 31.914 19.381 ;
     RECT  22.248 19.265 26.082 19.499 ;
     RECT  28.296 18.959 28.35 19.615 ;
     RECT  15.372 18.959 20.25 19.651 ;
     RECT  21.312 18.959 21.33 19.651 ;
     RECT  29.415 19.381 31.05 19.769 ;
     RECT  31.788 19.381 31.914 19.769 ;
     RECT  22.248 19.499 25.11 19.805 ;
     RECT  31.788 19.769 31.806 19.805 ;
     RECT  15.372 19.651 21.33 19.849 ;
     RECT  22.248 19.805 24.318 19.849 ;
     RECT  27.36 19.265 27.414 19.885 ;
     RECT  5.292 19.265 11.682 19.921 ;
     RECT  12.456 18.995 14.634 19.921 ;
     RECT  15.372 19.849 24.318 19.921 ;
     RECT  28.188 19.615 28.35 19.963 ;
     RECT  29.415 19.769 30.906 19.963 ;
     RECT  27.36 19.885 27.45 20.039 ;
     RECT  27.36 20.039 27.414 20.155 ;
     RECT  25.956 19.499 26.082 20.191 ;
     RECT  28.188 19.963 30.906 20.237 ;
     RECT  27.288 20.155 27.414 20.279 ;
     RECT  25.956 20.191 26.514 20.281 ;
     RECT  27.252 20.279 27.414 20.281 ;
     RECT  25.092 19.805 25.11 20.309 ;
     RECT  25.956 20.281 27.414 20.309 ;
     RECT  28.188 20.237 28.206 20.309 ;
     RECT  25.956 20.309 27.306 20.381 ;
     RECT  25.956 20.381 26.514 20.389 ;
     RECT  5.292 19.921 24.318 20.425 ;
     RECT  25.344 20.389 26.514 20.429 ;
     RECT  4.896 20.425 24.318 20.461 ;
     RECT  4.536 20.461 24.318 20.579 ;
     RECT  4.536 20.579 11.502 20.615 ;
     RECT  29.052 20.237 30.906 20.615 ;
     RECT  29.052 20.615 30.762 20.687 ;
     RECT  25.632 20.429 26.514 20.849 ;
     RECT  27.288 20.381 27.306 20.849 ;
     RECT  12.384 20.579 24.318 21.115 ;
     RECT  29.052 20.687 30.15 21.127 ;
     RECT  25.632 20.849 26.37 21.149 ;
     RECT  12.384 21.115 24.57 21.235 ;
     RECT  12.384 21.235 24.822 21.271 ;
     RECT  25.632 21.149 25.722 21.271 ;
     RECT  3.78 21.271 3.87 21.505 ;
     RECT  3.636 21.505 3.87 21.541 ;
     RECT  4.644 20.615 11.502 21.541 ;
     RECT  12.384 21.271 25.722 21.541 ;
     RECT  2.415 18.995 2.697 21.631 ;
     RECT  3.636 21.541 25.722 21.631 ;
     RECT  28.656 21.127 30.15 21.631 ;
     RECT  27.684 21.631 27.702 21.643 ;
     RECT  2.415 21.631 25.722 21.659 ;
     RECT  28.512 21.631 30.15 21.659 ;
     RECT  85.464 18.463 85.482 21.659 ;
     RECT  5.508 21.659 25.722 21.677 ;
     RECT  28.512 21.659 28.674 21.677 ;
     RECT  6.336 21.677 25.722 21.682 ;
     RECT  2.415 21.659 4.77 21.695 ;
     RECT  27.468 21.643 27.702 21.695 ;
     RECT  22.392 21.682 25.722 21.803 ;
     RECT  28.512 21.677 28.53 21.811 ;
     RECT  4.608 21.695 4.77 21.929 ;
     RECT  2.415 21.695 3.798 21.937 ;
     RECT  4.608 21.929 4.626 21.965 ;
     RECT  2.304 21.937 3.798 22.013 ;
     RECT  40.215 13.325 40.497 22.171 ;
     RECT  2.415 22.013 3.798 22.199 ;
     RECT  41.22 21.643 41.238 22.199 ;
     RECT  39.672 22.171 40.497 22.208 ;
     RECT  2.415 22.199 3.726 22.235 ;
     RECT  2.415 22.235 3.078 22.469 ;
     RECT  2.415 22.469 2.97 22.505 ;
     RECT  6.336 21.682 21.582 22.505 ;
     RECT  27.648 21.695 27.702 22.585 ;
     RECT  5.508 21.677 5.562 22.621 ;
     RECT  6.336 22.505 7.074 22.621 ;
     RECT  22.392 21.803 25.11 22.621 ;
     RECT  26.712 22.585 26.73 22.621 ;
     RECT  27.576 22.585 27.702 22.621 ;
     RECT  28.44 21.811 28.53 22.711 ;
     RECT  7.815 22.505 21.582 22.747 ;
     RECT  22.392 22.621 25.686 22.747 ;
     RECT  26.712 22.621 27.702 22.855 ;
     RECT  86.292 22.207 86.31 22.877 ;
     RECT  7.815 22.747 25.686 22.891 ;
     RECT  26.568 22.855 27.702 22.891 ;
     RECT  28.44 22.711 28.674 22.891 ;
     RECT  29.415 21.659 30.15 22.891 ;
     RECT  4.68 22.747 4.698 23.161 ;
     RECT  5.508 22.621 7.074 23.161 ;
     RECT  7.815 22.891 30.15 23.279 ;
     RECT  7.815 23.279 28.674 23.315 ;
     RECT  4.68 23.161 7.074 23.323 ;
     RECT  7.815 23.315 27.018 23.323 ;
     RECT  29.415 23.279 30.15 23.395 ;
     RECT  29.415 23.395 30.726 23.431 ;
     RECT  4.68 23.323 27.018 23.549 ;
     RECT  27.864 23.315 28.674 23.549 ;
     RECT  5.544 23.549 27.018 23.585 ;
     RECT  27.864 23.549 28.602 23.585 ;
     RECT  2.415 22.505 2.697 23.701 ;
     RECT  4.68 23.549 4.734 23.701 ;
     RECT  29.415 23.431 30.798 23.701 ;
     RECT  2.415 23.701 3.618 23.819 ;
     RECT  2.415 23.819 3.474 23.855 ;
     RECT  3.456 23.855 3.474 23.933 ;
     RECT  32.832 23.935 32.85 23.971 ;
     RECT  4.392 23.701 4.734 24.125 ;
     RECT  85.5 23.323 85.518 24.125 ;
     RECT  32.544 23.971 32.85 24.205 ;
     RECT  33.876 18.149 33.894 24.205 ;
     RECT  34.815 17.951 35.097 24.205 ;
     RECT  6.48 23.585 27.018 24.241 ;
     RECT  27.864 23.585 27.954 24.241 ;
     RECT  29.415 23.701 30.87 24.241 ;
     RECT  31.896 24.205 32.85 24.241 ;
     RECT  33.876 24.205 35.097 24.241 ;
     RECT  5.544 23.585 5.706 24.367 ;
     RECT  6.48 24.241 27.954 24.367 ;
     RECT  29.415 24.241 30.942 24.395 ;
     RECT  29.415 24.395 30.798 24.403 ;
     RECT  5.544 24.367 27.954 24.475 ;
     RECT  28.692 24.403 30.798 24.475 ;
     RECT  31.716 24.241 35.097 24.475 ;
     RECT  31.536 24.475 35.262 24.511 ;
     RECT  5.544 24.475 30.798 24.629 ;
     RECT  37.908 15.485 38.07 24.709 ;
     RECT  5.544 24.629 26.766 24.773 ;
     RECT  37.116 24.745 37.134 24.781 ;
     RECT  37.908 24.709 38.322 24.781 ;
     RECT  84.888 24.715 84.906 24.809 ;
     RECT  40.215 22.208 40.497 24.871 ;
     RECT  6.876 24.773 26.766 24.935 ;
     RECT  31.536 24.511 36.162 24.935 ;
     RECT  33.336 24.935 36.162 25.051 ;
     RECT  37.116 24.781 38.322 25.051 ;
     RECT  39.888 24.871 40.497 25.051 ;
     RECT  5.544 24.773 6.102 25.169 ;
     RECT  33.336 25.051 36.27 25.169 ;
     RECT  4.716 24.125 4.734 25.205 ;
     RECT  27.576 24.629 30.798 25.205 ;
     RECT  33.336 25.169 36.054 25.205 ;
     RECT  2.415 23.855 2.697 25.24 ;
     RECT  2.304 25.24 2.697 25.277 ;
     RECT  39.852 25.051 40.626 25.285 ;
     RECT  5.544 25.169 5.85 25.321 ;
     RECT  37.044 25.051 38.934 25.321 ;
     RECT  39.744 25.285 40.626 25.321 ;
     RECT  17.064 24.935 26.766 25.349 ;
     RECT  4.896 25.321 5.85 25.439 ;
     RECT  3.996 25.321 4.014 25.475 ;
     RECT  13.068 24.935 16.11 25.475 ;
     RECT  33.336 25.205 35.097 25.475 ;
     RECT  6.876 24.935 12.222 25.579 ;
     RECT  28.98 25.205 30.798 25.591 ;
     RECT  31.536 24.935 32.562 25.591 ;
     RECT  21.204 25.349 26.766 25.675 ;
     RECT  27.576 25.205 28.17 25.675 ;
     RECT  17.064 25.349 20.466 25.709 ;
     RECT  28.98 25.591 32.562 25.709 ;
     RECT  30.528 25.709 32.562 25.717 ;
     RECT  28.98 25.709 29.79 25.745 ;
     RECT  30.528 25.717 32.814 25.745 ;
     RECT  37.044 25.321 40.77 25.745 ;
     RECT  30.564 25.745 32.814 25.757 ;
     RECT  6.804 25.579 12.222 25.825 ;
     RECT  6.804 25.825 12.294 25.861 ;
     RECT  13.068 25.475 15.102 25.861 ;
     RECT  38.808 25.745 40.77 25.861 ;
     RECT  38.808 25.861 40.842 25.901 ;
     RECT  38.844 25.901 40.842 25.951 ;
     RECT  45.615 13.091 45.897 25.951 ;
     RECT  56.415 6.539 56.697 25.951 ;
     RECT  67.215 4.919 67.497 25.951 ;
     RECT  78.015 6.173 78.297 25.951 ;
     RECT  15.84 25.475 16.11 25.979 ;
     RECT  21.204 25.675 28.17 25.979 ;
     RECT  38.844 25.951 41.022 25.979 ;
     RECT  35.928 25.205 36.054 25.987 ;
     RECT  39.708 25.979 41.022 25.997 ;
     RECT  45.504 25.951 45.897 25.997 ;
     RECT  56.304 25.951 56.697 25.997 ;
     RECT  67.104 25.951 67.497 25.997 ;
     RECT  77.904 25.951 78.297 25.997 ;
     RECT  80.1 25.951 80.118 25.997 ;
     RECT  17.064 25.709 20.322 26.015 ;
     RECT  21.204 25.979 22.95 26.015 ;
     RECT  38.844 25.979 38.862 26.015 ;
     RECT  5.544 25.439 5.85 26.023 ;
     RECT  6.804 25.861 15.102 26.023 ;
     RECT  39.708 25.997 40.842 26.051 ;
     RECT  16.128 26.095 16.146 26.131 ;
     RECT  17.064 26.015 17.694 26.131 ;
     RECT  35.928 25.987 36.126 26.131 ;
     RECT  37.044 25.745 38.07 26.131 ;
     RECT  16.128 26.131 17.694 26.141 ;
     RECT  33.732 25.475 35.097 26.221 ;
     RECT  35.928 26.131 38.07 26.221 ;
     RECT  80.316 26.131 80.334 26.237 ;
     RECT  18.504 26.015 20.322 26.249 ;
     RECT  23.796 25.979 27.018 26.249 ;
     RECT  27.936 25.979 28.17 26.249 ;
     RECT  33.732 26.221 38.07 26.249 ;
     RECT  5.544 26.023 15.102 26.251 ;
     RECT  5.22 26.251 15.102 26.285 ;
     RECT  18.504 26.249 20.178 26.285 ;
     RECT  27.936 26.249 28.134 26.285 ;
     RECT  5.22 26.285 10.17 26.291 ;
     RECT  33.732 26.249 36.018 26.365 ;
     RECT  33.624 26.365 36.018 26.401 ;
     RECT  22.32 26.015 22.95 26.519 ;
     RECT  25.164 26.249 26.082 26.519 ;
     RECT  26.856 26.249 27.018 26.519 ;
     RECT  28.008 26.285 28.134 26.519 ;
     RECT  10.908 26.285 15.102 26.555 ;
     RECT  22.32 26.519 22.878 26.555 ;
     RECT  25.164 26.519 25.182 26.555 ;
     RECT  25.92 26.519 25.938 26.555 ;
     RECT  26.856 26.519 26.874 26.555 ;
     RECT  28.98 25.745 29.697 26.555 ;
     RECT  30.564 25.757 32.634 26.573 ;
     RECT  29.088 26.555 29.697 26.599 ;
     RECT  36.756 26.249 38.07 26.635 ;
     RECT  28.116 26.519 28.134 26.663 ;
     RECT  85.464 25.321 85.482 26.663 ;
     RECT  30.996 26.573 32.634 26.671 ;
     RECT  33.372 26.401 36.018 26.671 ;
     RECT  47.16 16.645 47.178 26.671 ;
     RECT  47.16 26.671 47.322 26.699 ;
     RECT  12.816 26.555 15.102 26.761 ;
     RECT  36.756 26.635 38.79 26.761 ;
     RECT  12.816 26.761 15.462 26.789 ;
     RECT  16.2 26.141 17.694 26.789 ;
     RECT  21.348 26.015 21.546 26.789 ;
     RECT  22.32 26.555 22.482 26.789 ;
     RECT  29.088 26.599 30.258 26.789 ;
     RECT  30.996 26.671 36.018 26.789 ;
     RECT  47.196 26.699 47.322 26.789 ;
     RECT  21.348 26.789 21.366 26.813 ;
     RECT  16.2 26.789 17.622 26.825 ;
     RECT  18.504 26.285 19.998 26.825 ;
     RECT  22.32 26.789 22.338 26.825 ;
     RECT  2.415 25.277 2.697 26.875 ;
     RECT  15.156 26.789 15.462 26.905 ;
     RECT  16.2 26.825 17.514 26.905 ;
     RECT  36.756 26.761 38.934 26.905 ;
     RECT  39.708 26.051 40.497 26.905 ;
     RECT  29.124 26.789 30.258 26.933 ;
     RECT  5.508 26.291 10.17 27.031 ;
     RECT  21.312 26.905 21.33 27.059 ;
     RECT  29.16 26.933 30.258 27.059 ;
     RECT  31.032 26.789 36.018 27.059 ;
     RECT  36.756 26.905 40.497 27.059 ;
     RECT  31.716 27.059 36.018 27.067 ;
     RECT  36.756 27.059 38.934 27.067 ;
     RECT  2.304 26.875 2.697 27.095 ;
     RECT  10.908 26.555 12.078 27.095 ;
     RECT  29.16 27.059 30.078 27.095 ;
     RECT  31.716 27.067 38.934 27.095 ;
     RECT  11.988 27.095 12.078 27.131 ;
     RECT  18.504 26.825 18.897 27.175 ;
     RECT  5.256 27.031 10.17 27.211 ;
     RECT  10.908 27.095 11.25 27.211 ;
     RECT  84.924 27.175 84.942 27.245 ;
     RECT  12.024 27.131 12.078 27.301 ;
     RECT  12.816 26.789 13.734 27.301 ;
     RECT  45.615 25.997 45.897 27.301 ;
     RECT  29.415 27.095 30.078 27.329 ;
     RECT  31.788 27.095 38.934 27.329 ;
     RECT  5.256 27.211 11.25 27.355 ;
     RECT  4.572 27.355 11.25 27.365 ;
     RECT  29.415 27.329 29.97 27.365 ;
     RECT  31.788 27.329 31.806 27.365 ;
     RECT  19.872 26.825 19.998 27.481 ;
     RECT  21.096 27.211 21.114 27.481 ;
     RECT  39.708 27.059 40.497 27.481 ;
     RECT  41.616 26.827 41.634 27.481 ;
     RECT  42.84 27.301 42.858 27.481 ;
     RECT  45.615 27.301 46.35 27.481 ;
     RECT  47.196 26.789 47.25 27.481 ;
     RECT  44.748 27.571 44.766 27.595 ;
     RECT  20.988 27.481 21.114 27.599 ;
     RECT  32.58 27.329 38.934 27.599 ;
     RECT  39.708 27.481 41.778 27.599 ;
     RECT  42.84 27.481 43.722 27.599 ;
     RECT  33.048 27.599 35.694 27.629 ;
     RECT  43.632 27.599 43.722 27.629 ;
     RECT  15.156 26.905 17.514 27.635 ;
     RECT  20.988 27.599 21.006 27.635 ;
     RECT  33.48 27.629 35.694 27.635 ;
     RECT  39.708 27.599 41.562 27.635 ;
     RECT  42.84 27.599 42.858 27.635 ;
     RECT  45.615 27.481 47.25 27.635 ;
     RECT  45.615 27.635 47.214 27.671 ;
     RECT  12.024 27.301 13.734 27.715 ;
     RECT  12.024 27.715 14.202 27.751 ;
     RECT  15.156 27.635 16.578 27.751 ;
     RECT  17.424 27.635 17.514 27.751 ;
     RECT  18.36 27.175 18.897 27.751 ;
     RECT  43.704 27.629 43.722 27.751 ;
     RECT  44.748 27.595 44.874 27.751 ;
     RECT  45.615 27.671 45.897 27.751 ;
     RECT  47.196 27.671 47.214 27.779 ;
     RECT  6.84 27.365 11.25 27.869 ;
     RECT  19.872 27.481 20.25 27.869 ;
     RECT  33.48 27.635 33.678 27.869 ;
     RECT  39.78 27.635 41.31 27.869 ;
     RECT  43.704 27.751 43.794 27.869 ;
     RECT  44.568 27.751 45.897 27.869 ;
     RECT  6.84 27.869 11.142 27.905 ;
     RECT  17.424 27.751 18.897 27.905 ;
     RECT  36.684 27.599 38.682 27.905 ;
     RECT  39.78 27.869 41.202 27.905 ;
     RECT  43.704 27.869 43.722 27.905 ;
     RECT  44.568 27.869 44.766 27.905 ;
     RECT  33.66 27.869 33.678 27.941 ;
     RECT  17.424 27.905 17.55 28.139 ;
     RECT  36.864 27.905 36.954 28.139 ;
     RECT  37.908 27.905 38.682 28.139 ;
     RECT  44.568 27.905 44.73 28.139 ;
     RECT  36.864 28.139 36.882 28.175 ;
     RECT  44.568 28.139 44.586 28.175 ;
     RECT  4.572 27.365 5.562 28.255 ;
     RECT  18.615 27.905 18.897 28.255 ;
     RECT  18.615 28.255 18.954 28.291 ;
     RECT  6.84 27.905 8.097 28.381 ;
     RECT  17.424 28.139 17.442 28.409 ;
     RECT  19.872 27.869 20.106 28.409 ;
     RECT  37.908 28.139 38.574 28.409 ;
     RECT  3.924 28.255 5.562 28.445 ;
     RECT  19.872 28.409 19.962 28.445 ;
     RECT  2.415 27.095 2.697 28.507 ;
     RECT  12.024 27.751 16.578 28.561 ;
     RECT  9.072 27.905 11.142 28.651 ;
     RECT  12.024 28.561 17.406 28.651 ;
     RECT  2.304 28.507 2.697 28.715 ;
     RECT  9.072 28.651 17.406 28.715 ;
     RECT  2.415 28.715 2.697 28.789 ;
     RECT  3.924 28.445 4.806 28.789 ;
     RECT  6.516 28.381 8.097 28.789 ;
     RECT  16.452 28.715 16.578 28.949 ;
     RECT  17.316 28.715 17.406 28.949 ;
     RECT  18.615 28.291 19.134 28.949 ;
     RECT  2.415 28.789 4.806 28.985 ;
     RECT  17.388 28.949 17.406 28.985 ;
     RECT  74.124 28.939 74.142 28.985 ;
     RECT  5.544 28.445 5.562 29.029 ;
     RECT  6.3 28.789 8.097 29.029 ;
     RECT  9.072 28.715 15.174 29.029 ;
     RECT  74.916 29.029 74.934 29.069 ;
     RECT  5.544 29.029 15.174 29.219 ;
     RECT  18.615 28.949 18.99 29.219 ;
     RECT  85.464 27.835 85.482 29.219 ;
     RECT  3.492 28.985 4.158 29.255 ;
     RECT  10.188 29.219 15.174 29.255 ;
     RECT  5.544 29.219 9.45 29.363 ;
     RECT  5.544 29.363 7.074 29.371 ;
     RECT  3.492 29.255 3.978 29.399 ;
     RECT  16.452 28.949 16.542 29.489 ;
     RECT  18.615 29.219 18.954 29.489 ;
     RECT  17.712 29.419 17.73 29.641 ;
     RECT  18.615 29.489 18.897 29.641 ;
     RECT  86.292 29.605 86.31 29.741 ;
     RECT  10.224 29.255 15.174 29.755 ;
     RECT  16.524 29.489 16.542 29.759 ;
     RECT  10.224 29.755 15.39 29.911 ;
     RECT  10.224 29.911 15.714 29.939 ;
     RECT  7.815 29.363 9.45 29.992 ;
     RECT  10.224 29.939 11.07 29.992 ;
     RECT  4.896 29.371 7.074 30.029 ;
     RECT  17.712 29.641 18.897 30.029 ;
     RECT  2.415 28.985 2.697 30.136 ;
     RECT  2.34 30.136 2.697 30.173 ;
     RECT  3.492 29.399 3.51 30.181 ;
     RECT  5.544 30.029 7.074 30.181 ;
     RECT  7.815 29.992 11.07 30.181 ;
     RECT  12.168 29.939 15.714 30.235 ;
     RECT  3.42 30.181 3.654 30.299 ;
     RECT  17.712 30.029 17.73 30.299 ;
     RECT  5.544 30.181 11.07 30.317 ;
     RECT  3.42 30.299 3.438 30.335 ;
     RECT  4.5 30.181 4.734 30.335 ;
     RECT  23.796 26.249 24.297 30.541 ;
     RECT  4.644 30.335 4.734 30.569 ;
     RECT  4.644 30.569 4.662 30.605 ;
     RECT  17.244 30.451 17.622 30.605 ;
     RECT  6.372 30.317 11.07 30.611 ;
     RECT  23.58 30.541 24.297 30.653 ;
     RECT  12.168 30.235 16.47 30.721 ;
     RECT  11.376 30.721 16.47 30.839 ;
     RECT  17.424 30.605 17.622 30.839 ;
     RECT  17.424 30.839 17.442 30.875 ;
     RECT  85.464 30.271 85.482 30.992 ;
     RECT  11.376 30.839 16.254 31.145 ;
     RECT  11.376 31.145 15.39 31.379 ;
     RECT  16.128 31.145 16.254 31.379 ;
     RECT  11.376 31.379 15.282 31.415 ;
     RECT  16.128 31.379 16.146 31.415 ;
     RECT  5.544 30.317 5.562 31.495 ;
     RECT  6.372 30.611 10.53 31.495 ;
     RECT  5.544 31.495 10.53 31.531 ;
     RECT  11.376 31.415 13.986 31.531 ;
     RECT  84.924 31.495 84.942 31.613 ;
     RECT  4.86 31.531 13.986 31.649 ;
     RECT  14.832 31.415 15.282 31.649 ;
     RECT  5.004 31.649 13.986 31.919 ;
     RECT  4.248 31.801 4.266 31.955 ;
     RECT  14.832 31.649 15.102 31.955 ;
     RECT  5.544 31.919 13.986 32.189 ;
     RECT  14.868 31.955 15.102 32.189 ;
     RECT  14.868 32.189 14.886 32.225 ;
     RECT  85.464 32.197 85.482 32.237 ;
     RECT  5.544 32.189 13.878 32.459 ;
     RECT  5.544 32.459 13.698 32.495 ;
     RECT  10.836 32.495 13.698 32.729 ;
     RECT  84.924 32.875 84.942 32.915 ;
     RECT  5.544 32.495 9.99 33.151 ;
     RECT  5.076 33.151 9.99 33.269 ;
     RECT  5.076 33.269 6.21 33.305 ;
     RECT  10.836 32.729 13.626 33.305 ;
     RECT  2.415 30.173 2.697 33.385 ;
     RECT  10.836 33.305 13.59 33.385 ;
     RECT  2.304 33.385 2.697 33.421 ;
     RECT  2.304 33.421 3.402 33.437 ;
     RECT  10.296 33.385 13.59 33.449 ;
     RECT  2.415 33.437 3.402 33.575 ;
     RECT  5.076 33.305 6.102 33.595 ;
     RECT  4.536 33.595 6.102 33.781 ;
     RECT  3.996 33.781 6.102 33.809 ;
     RECT  3.996 33.809 5.994 33.845 ;
     RECT  37.908 28.409 38.07 33.889 ;
     RECT  7.056 33.269 9.198 33.917 ;
     RECT  10.296 33.449 13.497 34.079 ;
     RECT  9.54 34.075 9.558 34.115 ;
     RECT  10.296 34.079 12.474 34.115 ;
     RECT  10.296 34.115 12.258 34.123 ;
     RECT  37.8 33.889 38.07 34.219 ;
     RECT  9.9 34.123 12.258 34.385 ;
     RECT  37.8 34.219 38.502 34.429 ;
     RECT  40.215 27.905 40.497 34.465 ;
     RECT  37.8 34.429 38.718 34.501 ;
     RECT  39.672 34.465 40.662 34.501 ;
     RECT  3.996 33.845 5.562 34.529 ;
     RECT  41.58 34.501 41.598 34.591 ;
     RECT  11.304 34.385 12.258 34.619 ;
     RECT  11.304 34.619 12.15 34.655 ;
     RECT  37.692 34.501 38.718 34.691 ;
     RECT  7.056 33.917 8.442 34.699 ;
     RECT  39.672 34.501 40.806 34.735 ;
     RECT  41.58 34.591 42.21 34.735 ;
     RECT  37.8 34.691 38.718 34.763 ;
     RECT  7.02 34.699 8.442 34.771 ;
     RECT  39.672 34.735 42.21 34.771 ;
     RECT  2.415 33.575 2.697 34.795 ;
     RECT  3.996 34.529 5.022 34.795 ;
     RECT  11.304 34.655 11.502 34.889 ;
     RECT  37.836 34.763 38.718 34.889 ;
     RECT  2.415 34.795 5.022 34.925 ;
     RECT  23.796 30.653 24.297 34.925 ;
     RECT  6.876 34.771 8.442 35.005 ;
     RECT  37.836 34.889 38.646 35.033 ;
     RECT  2.415 34.925 4.59 35.035 ;
     RECT  6.624 35.005 9.054 35.041 ;
     RECT  9.9 34.385 10.53 35.041 ;
     RECT  2.304 35.035 4.59 35.069 ;
     RECT  38.016 35.033 38.646 35.159 ;
     RECT  2.304 35.069 4.122 35.195 ;
     RECT  6.624 35.041 10.53 35.195 ;
     RECT  7.815 35.195 10.53 35.311 ;
     RECT  11.304 34.889 11.466 35.311 ;
     RECT  39.564 34.771 42.462 35.311 ;
     RECT  44.352 35.131 44.37 35.311 ;
     RECT  6.624 35.195 7.074 35.323 ;
     RECT  44.352 35.311 44.658 35.419 ;
     RECT  2.415 35.195 4.122 35.429 ;
     RECT  2.415 35.429 4.05 35.465 ;
     RECT  85.464 33.499 85.482 35.465 ;
     RECT  43.776 35.419 44.658 35.545 ;
     RECT  43.776 35.545 44.874 35.581 ;
     RECT  45.615 27.869 45.897 35.581 ;
     RECT  7.815 35.311 11.466 35.699 ;
     RECT  39.492 35.311 42.714 35.851 ;
     RECT  43.488 35.581 45.897 35.851 ;
     RECT  38.016 35.159 38.502 35.933 ;
     RECT  10.188 35.699 11.43 35.969 ;
     RECT  5.904 35.323 7.074 35.977 ;
     RECT  7.815 35.699 9.342 35.977 ;
     RECT  11.016 35.969 11.43 36.005 ;
     RECT  85.5 35.815 85.518 36.029 ;
     RECT  5.904 35.977 9.342 36.077 ;
     RECT  11.016 36.005 11.394 36.077 ;
     RECT  5.112 35.947 5.13 36.121 ;
     RECT  5.904 36.077 6.282 36.121 ;
     RECT  11.016 36.077 11.034 36.239 ;
     RECT  38.016 35.933 38.322 36.239 ;
     RECT  39.456 35.851 45.897 36.239 ;
     RECT  5.112 36.121 6.282 36.275 ;
     RECT  7.056 36.077 9.342 36.275 ;
     RECT  38.016 36.239 38.178 36.275 ;
     RECT  39.456 36.239 44.478 36.275 ;
     RECT  45.216 36.239 45.897 36.275 ;
     RECT  45.252 36.275 45.897 36.331 ;
     RECT  39.456 36.275 42.858 36.391 ;
     RECT  45.252 36.331 46.314 36.391 ;
     RECT  9.144 36.275 9.342 36.472 ;
     RECT  10.188 35.969 10.278 36.472 ;
     RECT  5.112 36.275 5.418 36.509 ;
     RECT  6.156 36.275 6.282 36.509 ;
     RECT  39.384 36.391 42.858 36.545 ;
     RECT  2.415 35.465 3.402 36.625 ;
     RECT  45.252 36.391 47.574 36.625 ;
     RECT  6.192 36.509 6.282 36.653 ;
     RECT  2.304 36.625 3.402 36.661 ;
     RECT  5.112 36.509 5.13 36.661 ;
     RECT  50.148 36.625 50.166 36.661 ;
     RECT  51.015 5.369 51.297 36.661 ;
     RECT  84.888 36.619 84.906 36.689 ;
     RECT  2.304 36.661 3.654 36.701 ;
     RECT  2.415 36.701 3.654 36.779 ;
     RECT  39.492 36.545 41.418 36.779 ;
     RECT  54.144 36.661 54.486 36.779 ;
     RECT  2.415 36.779 3.258 36.815 ;
     RECT  4.428 36.661 5.13 36.815 ;
     RECT  45.252 36.625 47.934 36.815 ;
     RECT  48.888 36.661 48.906 36.815 ;
     RECT  50.148 36.661 51.297 36.823 ;
     RECT  9.144 36.472 10.278 36.931 ;
     RECT  54.468 36.779 54.486 37.003 ;
     RECT  4.788 36.815 5.13 37.049 ;
     RECT  7.056 36.275 8.19 37.051 ;
     RECT  43.632 36.275 44.478 37.051 ;
     RECT  9.144 36.931 10.35 37.057 ;
     RECT  4.788 37.049 4.806 37.085 ;
     RECT  39.816 36.779 41.418 37.085 ;
     RECT  45.504 36.815 47.934 37.085 ;
     RECT  43.632 37.051 44.55 37.091 ;
     RECT  6.948 37.051 8.19 37.201 ;
     RECT  47.592 37.085 47.934 37.201 ;
     RECT  54.468 37.003 54.558 37.201 ;
     RECT  56.415 25.997 56.697 37.201 ;
     RECT  85.464 37.201 85.482 37.277 ;
     RECT  50.148 36.823 51.39 37.291 ;
     RECT  9.144 37.057 10.494 37.319 ;
     RECT  47.592 37.201 48.006 37.319 ;
     RECT  48.996 37.201 49.014 37.355 ;
     RECT  54.468 37.201 54.666 37.355 ;
     RECT  55.764 37.201 56.697 37.355 ;
     RECT  56.016 37.355 56.697 37.391 ;
     RECT  52.524 37.291 52.614 37.435 ;
     RECT  56.415 37.391 56.697 37.435 ;
     RECT  6.192 36.653 6.21 37.471 ;
     RECT  6.948 37.201 8.334 37.471 ;
     RECT  40.215 37.085 41.418 37.471 ;
     RECT  42.156 36.545 42.858 37.471 ;
     RECT  43.632 37.091 44.334 37.471 ;
     RECT  50.148 37.291 51.678 37.471 ;
     RECT  56.415 37.435 56.97 37.471 ;
     RECT  9.144 37.319 10.422 37.499 ;
     RECT  40.215 37.471 44.334 37.589 ;
     RECT  49.752 37.471 51.678 37.589 ;
     RECT  56.415 37.471 57.114 37.589 ;
     RECT  57.96 37.471 57.978 37.597 ;
     RECT  40.215 37.589 41.418 37.625 ;
     RECT  42.228 37.589 44.334 37.625 ;
     RECT  49.752 37.589 49.77 37.625 ;
     RECT  52.488 37.435 52.614 37.627 ;
     RECT  52.488 37.627 52.938 37.741 ;
     RECT  54.72 37.471 54.918 37.757 ;
     RECT  6.192 37.471 8.334 37.819 ;
     RECT  9.144 37.499 9.738 37.819 ;
     RECT  57.96 37.597 58.194 37.831 ;
     RECT  6.192 37.819 9.738 37.859 ;
     RECT  42.264 37.625 44.334 37.895 ;
     RECT  54.9 37.757 54.918 37.895 ;
     RECT  86.292 37.597 86.31 37.901 ;
     RECT  57.888 37.831 58.194 37.967 ;
     RECT  44.1 37.895 44.334 38.011 ;
     RECT  45.504 37.085 46.854 38.011 ;
     RECT  52.452 37.741 52.938 38.011 ;
     RECT  4.752 37.579 4.77 38.101 ;
     RECT  6.192 37.859 6.246 38.129 ;
     RECT  43.02 37.895 43.182 38.129 ;
     RECT  56.415 37.589 57.042 38.129 ;
     RECT  43.02 38.129 43.038 38.165 ;
     RECT  44.1 38.011 44.442 38.165 ;
     RECT  45.216 38.011 46.854 38.165 ;
     RECT  47.628 37.319 47.646 38.165 ;
     RECT  52.452 38.011 53.082 38.165 ;
     RECT  56.415 38.129 56.862 38.165 ;
     RECT  2.415 36.815 2.697 38.173 ;
     RECT  61.815 6.179 62.097 38.173 ;
     RECT  7.02 37.859 9.738 38.189 ;
     RECT  2.415 38.173 3.006 38.237 ;
     RECT  58.14 37.967 58.194 38.245 ;
     RECT  58.932 37.975 58.95 38.245 ;
     RECT  4.284 38.101 4.77 38.281 ;
     RECT  7.056 38.189 9.738 38.281 ;
     RECT  58.14 38.245 58.95 38.281 ;
     RECT  59.904 38.011 59.922 38.281 ;
     RECT  0.108 38.203 0.126 38.333 ;
     RECT  4.284 38.281 4.914 38.399 ;
     RECT  50.724 37.589 51.498 38.407 ;
     RECT  4.284 38.399 4.302 38.435 ;
     RECT  5.796 38.137 6.066 38.435 ;
     RECT  7.056 38.281 9.846 38.435 ;
     RECT  44.208 38.165 44.442 38.435 ;
     RECT  46.908 38.281 47.322 38.435 ;
     RECT  49.32 38.101 49.338 38.435 ;
     RECT  52.704 38.165 53.082 38.435 ;
     RECT  58.14 38.281 59.922 38.443 ;
     RECT  58.14 38.443 59.994 38.477 ;
     RECT  44.352 38.435 44.442 38.551 ;
     RECT  45.216 38.165 45.897 38.551 ;
     RECT  50.724 38.407 51.93 38.551 ;
     RECT  59.184 38.477 59.994 38.551 ;
     RECT  7.056 38.435 9.558 38.579 ;
     RECT  61.2 38.173 62.097 38.641 ;
     RECT  44.352 38.551 45.897 38.669 ;
     RECT  50.328 38.551 51.93 38.669 ;
     RECT  58.14 38.477 58.41 38.669 ;
     RECT  5.94 38.435 6.066 38.705 ;
     RECT  44.352 38.669 44.37 38.705 ;
     RECT  47.304 38.435 47.322 38.705 ;
     RECT  52.704 38.435 52.722 38.705 ;
     RECT  59.184 38.551 60.21 38.705 ;
     RECT  60.984 38.641 62.097 38.731 ;
     RECT  58.14 38.669 58.23 38.749 ;
     RECT  50.328 38.669 51.822 38.765 ;
     RECT  58.032 38.749 58.23 38.777 ;
     RECT  56.415 38.165 56.697 38.779 ;
     RECT  50.328 38.765 51.297 38.849 ;
     RECT  53.604 38.551 53.802 38.975 ;
     RECT  60.984 38.731 62.73 38.975 ;
     RECT  55.296 38.821 55.314 39.055 ;
     RECT  54.684 39.055 55.314 39.067 ;
     RECT  7.056 38.579 9.306 39.083 ;
     RECT  6.048 38.705 6.066 39.091 ;
     RECT  7.056 39.083 8.694 39.091 ;
     RECT  54.252 39.067 55.314 39.091 ;
     RECT  56.304 38.779 56.697 39.091 ;
     RECT  59.292 38.705 60.21 39.209 ;
     RECT  6.048 39.091 8.694 39.245 ;
     RECT  45.216 38.669 45.897 39.245 ;
     RECT  48.312 38.911 48.33 39.245 ;
     RECT  54.252 39.091 57.258 39.245 ;
     RECT  85.464 38.479 85.482 39.245 ;
     RECT  50.184 39.181 50.202 39.281 ;
     RECT  58.032 38.777 58.194 39.361 ;
     RECT  61.056 38.975 62.73 39.361 ;
     RECT  63.828 38.713 64.134 39.361 ;
     RECT  6.048 39.245 6.318 39.479 ;
     RECT  57.42 39.361 58.194 39.479 ;
     RECT  7.056 39.245 8.694 39.515 ;
     RECT  54.252 39.245 56.697 39.515 ;
     RECT  57.42 39.479 57.978 39.515 ;
     RECT  7.056 39.515 8.478 39.587 ;
     RECT  63.756 39.361 64.134 39.589 ;
     RECT  64.98 39.181 64.998 39.595 ;
     RECT  63.756 39.589 64.206 39.631 ;
     RECT  64.98 39.595 65.502 39.631 ;
     RECT  63.756 39.631 65.502 39.632 ;
     RECT  6.048 39.479 6.21 39.721 ;
     RECT  61.056 39.361 62.91 39.721 ;
     RECT  84.924 39.595 84.942 39.773 ;
     RECT  55.224 39.515 56.697 39.785 ;
     RECT  59.292 39.209 59.922 39.785 ;
     RECT  63.756 39.632 65.358 39.785 ;
     RECT  66.42 39.631 66.438 39.785 ;
     RECT  5.688 39.721 6.21 39.865 ;
     RECT  67.215 25.997 67.497 39.865 ;
     RECT  60.66 39.721 62.91 39.883 ;
     RECT  4.536 39.865 6.21 39.917 ;
     RECT  0.108 39.865 0.126 39.965 ;
     RECT  55.296 39.785 56.697 40.019 ;
     RECT  4.536 39.917 4.554 40.055 ;
     RECT  59.76 39.785 59.922 40.055 ;
     RECT  60.66 39.883 63.234 40.055 ;
     RECT  66.708 39.865 67.497 40.055 ;
     RECT  60.876 40.055 63.234 40.061 ;
     RECT  5.292 39.917 6.174 40.127 ;
     RECT  83.415 7.223 83.697 40.135 ;
     RECT  55.368 40.019 56.697 40.171 ;
     RECT  57.42 39.515 57.618 40.171 ;
     RECT  83.34 40.135 83.697 40.171 ;
     RECT  78.015 25.997 78.297 40.261 ;
     RECT  79.38 27.643 79.398 40.261 ;
     RECT  6.084 40.127 6.174 40.289 ;
     RECT  60.876 40.061 60.894 40.289 ;
     RECT  64.008 39.785 65.358 40.289 ;
     RECT  6.084 40.289 6.102 40.325 ;
     RECT  7.056 39.587 8.097 40.325 ;
     RECT  55.368 40.171 57.618 40.325 ;
     RECT  59.94 40.171 59.958 40.361 ;
     RECT  78.015 40.261 79.398 40.397 ;
     RECT  66.888 40.055 67.497 40.405 ;
     RECT  66.888 40.405 67.662 40.441 ;
     RECT  68.724 40.369 68.742 40.441 ;
     RECT  83.34 40.171 83.898 40.441 ;
     RECT  80.892 40.411 80.91 40.469 ;
     RECT  56.415 40.325 57.618 40.559 ;
     RECT  75.06 40.369 75.078 40.559 ;
     RECT  56.415 40.559 56.79 40.595 ;
     RECT  57.6 40.559 57.618 40.595 ;
     RECT  68.616 40.441 68.814 40.595 ;
     RECT  82.368 40.441 83.898 40.595 ;
     RECT  61.815 40.061 63.234 40.675 ;
     RECT  64.008 40.289 64.098 40.675 ;
     RECT  65.7 40.441 65.718 40.675 ;
     RECT  61.815 40.675 64.098 40.703 ;
     RECT  51.015 38.849 51.297 40.711 ;
     RECT  65.7 40.675 65.934 40.711 ;
     RECT  51.015 40.711 51.498 40.781 ;
     RECT  66.888 40.441 67.806 40.801 ;
     RECT  5.292 40.127 5.31 40.829 ;
     RECT  57.996 40.711 58.158 40.829 ;
     RECT  57.996 40.829 58.014 40.835 ;
     RECT  65.7 40.711 66.078 40.843 ;
     RECT  66.888 40.801 68.238 40.843 ;
     RECT  63.072 40.703 64.098 40.865 ;
     RECT  82.584 40.595 83.898 40.945 ;
     RECT  65.7 40.843 68.238 40.973 ;
     RECT  4.14 40.945 4.158 40.981 ;
     RECT  61.815 40.703 62.097 40.981 ;
     RECT  4.14 40.981 4.482 41.021 ;
     RECT  63.648 40.865 64.098 41.035 ;
     RECT  64.908 40.289 64.926 41.035 ;
     RECT  63.648 41.035 64.926 41.069 ;
     RECT  4.356 41.021 4.482 41.099 ;
     RECT  82.584 40.945 83.934 41.099 ;
     RECT  59.004 40.981 59.202 41.135 ;
     RECT  69.048 41.071 69.066 41.171 ;
     RECT  64.08 41.069 64.926 41.251 ;
     RECT  65.7 40.973 65.718 41.251 ;
     RECT  81.612 41.215 81.63 41.261 ;
     RECT  59.112 41.135 59.202 41.369 ;
     RECT  66.456 40.973 68.238 41.369 ;
     RECT  82.584 41.099 83.697 41.369 ;
     RECT  59.112 41.369 59.13 41.405 ;
     RECT  61.56 40.981 62.097 41.405 ;
     RECT  66.456 41.369 67.986 41.405 ;
     RECT  82.584 41.369 82.602 41.405 ;
     RECT  64.08 41.251 65.718 41.411 ;
     RECT  2.415 38.237 2.697 41.485 ;
     RECT  2.304 41.485 2.697 41.521 ;
     RECT  2.304 41.521 3.15 41.597 ;
     RECT  2.415 41.597 3.15 41.611 ;
     RECT  72.615 4.379 72.897 41.611 ;
     RECT  78.015 40.397 78.297 41.611 ;
     RECT  4.356 41.099 4.374 41.639 ;
     RECT  69.156 41.251 69.174 41.675 ;
     RECT  70.2 7.079 70.218 41.707 ;
     RECT  64.98 41.411 65.718 41.741 ;
     RECT  66.456 41.405 67.554 41.747 ;
     RECT  72.036 41.611 72.897 41.789 ;
     RECT  2.415 41.611 3.294 41.791 ;
     RECT  72.615 41.789 72.897 41.791 ;
     RECT  77.904 41.611 78.297 41.791 ;
     RECT  79.38 40.397 79.398 41.791 ;
     RECT  85.464 40.36 85.482 41.791 ;
     RECT  70.2 41.707 70.506 41.881 ;
     RECT  2.415 41.791 3.438 41.909 ;
     RECT  4.248 41.755 4.266 41.909 ;
     RECT  69.264 41.719 69.426 41.909 ;
     RECT  72.615 41.791 73.026 41.909 ;
     RECT  85.464 41.791 85.518 41.909 ;
     RECT  2.415 41.909 3.294 41.945 ;
     RECT  69.408 41.909 69.426 41.945 ;
     RECT  70.2 41.881 70.722 42.017 ;
     RECT  65.268 41.741 65.718 42.025 ;
     RECT  77.904 41.791 79.398 42.029 ;
     RECT  65.268 42.025 66.042 42.077 ;
     RECT  78.015 42.029 79.398 42.089 ;
     RECT  64.08 41.411 64.098 42.151 ;
     RECT  79.38 42.089 79.398 42.151 ;
     RECT  80.28 42.061 80.514 42.151 ;
     RECT  83.415 41.369 83.697 42.151 ;
     RECT  65.268 42.077 65.394 42.179 ;
     RECT  64.08 42.151 64.17 42.215 ;
     RECT  65.268 42.179 65.286 42.215 ;
     RECT  73.836 41.989 73.854 42.215 ;
     RECT  83.016 42.151 83.697 42.251 ;
     RECT  85.5 41.909 85.518 42.269 ;
     RECT  79.38 42.151 80.586 42.287 ;
     RECT  79.38 42.287 80.118 42.449 ;
     RECT  79.38 42.449 79.65 42.485 ;
     RECT  66.996 41.747 67.554 42.691 ;
     RECT  66.996 42.691 67.986 42.799 ;
     RECT  83.415 42.251 83.697 42.835 ;
     RECT  66.528 42.799 67.986 42.871 ;
     RECT  66.456 42.871 67.986 42.961 ;
     RECT  64.152 42.215 64.17 42.989 ;
     RECT  66.456 42.961 68.454 42.989 ;
     RECT  81 42.763 81.018 42.989 ;
     RECT  70.2 42.017 70.218 42.997 ;
     RECT  70.2 42.997 70.686 43.097 ;
     RECT  65.448 42.961 65.466 43.141 ;
     RECT  66.456 42.989 67.626 43.141 ;
     RECT  68.436 42.989 68.454 43.141 ;
     RECT  78.015 42.089 78.297 43.141 ;
     RECT  79.38 42.485 79.398 43.141 ;
     RECT  2.415 41.945 2.697 43.195 ;
     RECT  43.164 43.051 43.182 43.231 ;
     RECT  81.936 43.141 82.242 43.231 ;
     RECT  64.44 43.141 65.61 43.259 ;
     RECT  68.436 43.141 69.21 43.259 ;
     RECT  78.015 43.141 79.398 43.259 ;
     RECT  81.504 43.231 82.242 43.259 ;
     RECT  55.404 43.231 55.494 43.267 ;
     RECT  49.536 43.231 49.554 43.291 ;
     RECT  2.304 43.195 2.697 43.295 ;
     RECT  66.384 43.141 67.626 43.295 ;
     RECT  68.76 43.259 69.21 43.295 ;
     RECT  75.024 42.997 75.042 43.295 ;
     RECT  45.615 39.245 45.897 43.303 ;
     RECT  47.304 43.231 47.322 43.303 ;
     RECT  63.432 43.267 63.594 43.303 ;
     RECT  43.164 43.231 43.506 43.325 ;
     RECT  2.415 43.295 2.697 43.411 ;
     RECT  45.036 43.303 45.897 43.411 ;
     RECT  49.536 43.291 49.986 43.411 ;
     RECT  51.015 40.781 51.297 43.411 ;
     RECT  52.776 43.291 52.794 43.411 ;
     RECT  55.332 43.267 55.494 43.411 ;
     RECT  61.815 41.405 62.097 43.411 ;
     RECT  2.415 43.411 3.186 43.529 ;
     RECT  44.64 43.411 45.897 43.529 ;
     RECT  47.124 43.303 47.322 43.529 ;
     RECT  49.536 43.411 50.166 43.529 ;
     RECT  50.94 43.411 51.39 43.529 ;
     RECT  52.236 43.411 52.938 43.529 ;
     RECT  55.044 43.411 55.53 43.529 ;
     RECT  75.132 43.303 75.15 43.529 ;
     RECT  85.464 43.483 85.482 43.529 ;
     RECT  47.124 43.529 47.142 43.565 ;
     RECT  49.536 43.529 49.554 43.565 ;
     RECT  52.236 43.529 52.758 43.565 ;
     RECT  54.072 43.411 54.09 43.565 ;
     RECT  55.332 43.529 55.35 43.565 ;
     RECT  59.256 43.303 59.274 43.565 ;
     RECT  62.928 43.303 63.594 43.565 ;
     RECT  69.192 43.295 69.21 43.565 ;
     RECT  81.504 43.259 82.206 43.565 ;
     RECT  38.016 36.275 38.07 43.645 ;
     RECT  42.408 43.609 42.426 43.645 ;
     RECT  66.384 43.295 67.497 43.645 ;
     RECT  40.215 37.625 40.497 43.681 ;
     RECT  41.292 43.645 41.31 43.681 ;
     RECT  42.408 43.645 42.966 43.681 ;
     RECT  66.348 43.645 67.497 43.681 ;
     RECT  83.415 42.835 83.934 43.681 ;
     RECT  3.852 43.681 4.266 43.799 ;
     RECT  42.228 43.681 42.966 43.799 ;
     RECT  52.308 43.565 52.434 43.799 ;
     RECT  3.852 43.799 3.87 43.835 ;
     RECT  5.04 43.681 5.382 43.835 ;
     RECT  40.176 43.681 40.554 43.835 ;
     RECT  50.94 43.529 51.297 43.835 ;
     RECT  52.308 43.799 52.326 43.835 ;
     RECT  64.44 43.259 65.25 43.835 ;
     RECT  66.168 43.681 67.497 43.835 ;
     RECT  39.24 43.537 39.258 43.901 ;
     RECT  41.292 43.681 41.454 43.901 ;
     RECT  83.34 43.681 83.934 43.951 ;
     RECT  61.815 43.411 62.19 44.041 ;
     RECT  65.016 43.835 65.25 44.041 ;
     RECT  61.815 44.041 62.73 44.059 ;
     RECT  63.504 43.565 63.594 44.059 ;
     RECT  72.615 41.909 72.897 44.059 ;
     RECT  73.8 43.951 73.818 44.059 ;
     RECT  40.215 43.835 40.554 44.069 ;
     RECT  71.532 43.915 71.55 44.069 ;
     RECT  82.188 43.565 82.206 44.069 ;
     RECT  83.268 43.951 83.934 44.069 ;
     RECT  72.36 44.059 73.818 44.104 ;
     RECT  5.184 43.835 5.382 44.105 ;
     RECT  71.82 44.104 73.818 44.105 ;
     RECT  80.532 43.267 80.55 44.105 ;
     RECT  71.82 44.105 72.897 44.141 ;
     RECT  86.292 42.727 86.31 44.141 ;
     RECT  5.256 44.105 5.382 44.221 ;
     RECT  61.272 44.059 62.73 44.221 ;
     RECT  38.016 43.645 38.178 44.311 ;
     RECT  43.74 43.681 43.938 44.311 ;
     RECT  5.256 44.221 5.526 44.339 ;
     RECT  60.984 44.221 62.73 44.339 ;
     RECT  63.504 44.059 64.242 44.339 ;
     RECT  65.016 44.041 65.826 44.339 ;
     RECT  72.36 44.141 72.897 44.339 ;
     RECT  80.712 44.221 80.73 44.339 ;
     RECT  45.036 43.529 45.897 44.341 ;
     RECT  38.016 44.311 38.25 44.347 ;
     RECT  45.036 44.341 46.422 44.347 ;
     RECT  47.7 44.311 47.718 44.347 ;
     RECT  19.872 28.445 19.89 44.375 ;
     RECT  61.092 44.339 62.478 44.375 ;
     RECT  63.504 44.339 63.954 44.375 ;
     RECT  65.016 44.339 65.538 44.375 ;
     RECT  66.6 43.835 67.497 44.375 ;
     RECT  73.8 44.105 73.818 44.375 ;
     RECT  58.86 44.059 58.878 44.381 ;
     RECT  45.036 44.347 46.53 44.419 ;
     RECT  60.12 44.383 60.138 44.455 ;
     RECT  5.256 44.339 5.274 44.477 ;
     RECT  37.908 44.347 38.25 44.483 ;
     RECT  6.048 44.347 6.174 44.491 ;
     RECT  7.056 40.325 7.074 44.491 ;
     RECT  41.436 43.901 41.454 44.491 ;
     RECT  42.228 43.799 42.714 44.491 ;
     RECT  44.856 44.419 46.53 44.491 ;
     RECT  47.7 44.347 47.79 44.491 ;
     RECT  37.944 44.483 38.25 44.581 ;
     RECT  6.048 44.491 7.074 44.609 ;
     RECT  41.436 44.491 42.714 44.609 ;
     RECT  43.488 44.311 43.938 44.609 ;
     RECT  44.748 44.491 46.602 44.609 ;
     RECT  47.376 44.491 47.934 44.609 ;
     RECT  48.888 44.491 49.086 44.609 ;
     RECT  59.004 44.491 59.022 44.609 ;
     RECT  60.12 44.455 60.354 44.609 ;
     RECT  61.815 44.375 62.442 44.609 ;
     RECT  63.684 44.375 63.882 44.609 ;
     RECT  65.196 44.375 65.43 44.609 ;
     RECT  41.436 44.609 42.282 44.645 ;
     RECT  43.488 44.609 43.686 44.645 ;
     RECT  44.748 44.609 46.422 44.645 ;
     RECT  47.376 44.609 47.718 44.645 ;
     RECT  48.888 44.609 48.906 44.645 ;
     RECT  54.072 44.311 54.09 44.645 ;
     RECT  60.12 44.609 60.138 44.645 ;
     RECT  61.815 44.609 62.298 44.645 ;
     RECT  63.684 44.609 63.702 44.645 ;
     RECT  65.196 44.609 65.214 44.645 ;
     RECT  77.184 44.587 77.202 44.645 ;
     RECT  78.015 43.259 78.297 44.761 ;
     RECT  79.38 43.259 79.398 44.761 ;
     RECT  83.268 44.069 83.826 44.761 ;
     RECT  2.415 43.529 2.697 44.827 ;
     RECT  37.944 44.581 38.97 44.879 ;
     RECT  41.508 44.645 41.706 44.879 ;
     RECT  43.488 44.645 43.65 44.879 ;
     RECT  44.748 44.645 44.874 44.879 ;
     RECT  45.615 44.645 46.278 44.879 ;
     RECT  47.376 44.645 47.538 44.879 ;
     RECT  68.22 44.221 68.238 44.879 ;
     RECT  77.364 44.761 79.398 44.879 ;
     RECT  2.304 44.827 2.697 44.915 ;
     RECT  38.196 44.879 38.97 44.915 ;
     RECT  41.508 44.879 41.526 44.915 ;
     RECT  43.488 44.879 43.506 44.915 ;
     RECT  44.748 44.879 44.766 44.915 ;
     RECT  45.615 44.879 46.17 44.915 ;
     RECT  47.376 44.879 47.394 44.915 ;
     RECT  83.196 44.761 83.826 44.915 ;
     RECT  4.716 44.923 4.734 44.971 ;
     RECT  4.572 44.971 4.734 44.995 ;
     RECT  4.176 44.995 4.734 45.149 ;
     RECT  4.176 45.149 4.194 45.185 ;
     RECT  7.815 40.325 8.097 45.391 ;
     RECT  6.516 44.609 7.074 45.451 ;
     RECT  7.815 45.391 8.154 45.451 ;
     RECT  6.516 45.451 8.154 45.499 ;
     RECT  6.516 45.499 8.19 45.535 ;
     RECT  6.516 45.535 8.406 45.571 ;
     RECT  16.668 45.499 16.686 45.571 ;
     RECT  18.615 30.029 18.897 45.691 ;
     RECT  16.632 45.571 16.686 45.697 ;
     RECT  18.615 45.691 19.422 45.697 ;
     RECT  16.128 45.697 16.686 45.733 ;
     RECT  15.624 45.733 16.686 45.739 ;
     RECT  6.516 45.571 8.802 45.841 ;
     RECT  11.7 45.805 11.718 45.841 ;
     RECT  13.215 34.079 13.497 45.841 ;
     RECT  15.228 45.739 16.686 45.841 ;
     RECT  18.615 45.697 20.214 45.841 ;
     RECT  24.015 34.925 24.297 45.931 ;
     RECT  6.516 45.841 8.91 45.959 ;
     RECT  6.984 45.959 8.91 45.967 ;
     RECT  23.904 45.931 24.297 45.968 ;
     RECT  10.908 45.931 10.926 46.039 ;
     RECT  10.8 46.039 10.926 46.075 ;
     RECT  11.7 45.841 11.97 46.075 ;
     RECT  13.104 45.841 13.497 46.075 ;
     RECT  18.615 45.841 20.682 46.075 ;
     RECT  6.984 45.967 9.558 46.111 ;
     RECT  10.8 46.075 13.497 46.111 ;
     RECT  14.508 45.841 16.686 46.111 ;
     RECT  17.604 46.075 20.682 46.111 ;
     RECT  25.056 46.171 25.074 46.229 ;
     RECT  38.268 44.915 38.97 46.409 ;
     RECT  2.415 44.915 2.697 46.459 ;
     RECT  6.984 46.111 20.682 46.471 ;
     RECT  6.984 46.471 21.294 46.499 ;
     RECT  2.304 46.459 2.697 46.535 ;
     RECT  6.228 45.979 6.246 46.594 ;
     RECT  7.02 46.499 21.294 46.607 ;
     RECT  7.056 46.607 21.294 46.651 ;
     RECT  7.056 46.651 21.474 46.769 ;
     RECT  7.056 46.769 19.278 46.805 ;
     RECT  20.052 46.769 21.474 46.921 ;
     RECT  16.092 46.805 19.278 47.039 ;
     RECT  7.056 46.805 15.282 47.075 ;
     RECT  16.092 47.039 19.026 47.183 ;
     RECT  7.815 47.075 10.89 47.309 ;
     RECT  11.844 47.075 15.282 47.309 ;
     RECT  16.092 47.183 17.37 47.309 ;
     RECT  20.052 46.921 21.942 47.309 ;
     RECT  9.468 47.309 10.53 47.345 ;
     RECT  12.744 47.309 14.526 47.345 ;
     RECT  16.884 47.309 16.974 47.345 ;
     RECT  85.464 44.731 85.482 47.345 ;
     RECT  16.884 47.345 16.902 47.381 ;
     RECT  18.615 47.183 18.99 47.381 ;
     RECT  21.024 47.309 21.942 47.381 ;
     RECT  15.264 47.309 15.282 47.453 ;
     RECT  9.468 47.345 10.314 47.489 ;
     RECT  12.816 47.345 14.526 47.489 ;
     RECT  9.468 47.489 10.242 47.579 ;
     RECT  13.215 47.489 14.526 47.579 ;
     RECT  21.384 47.381 21.942 47.579 ;
     RECT  21.42 47.579 21.942 47.651 ;
     RECT  7.815 47.309 8.586 47.687 ;
     RECT  9.504 47.579 10.206 47.687 ;
     RECT  9.648 47.687 10.206 47.723 ;
     RECT  11.844 47.309 11.862 47.849 ;
     RECT  10.188 47.723 10.206 47.885 ;
     RECT  2.415 46.535 2.697 48.091 ;
     RECT  2.304 48.091 2.697 48.155 ;
     RECT  4.536 48.331 4.554 48.433 ;
     RECT  4.032 48.433 4.554 48.541 ;
     RECT  4.032 48.541 4.698 48.659 ;
     RECT  4.032 48.659 4.05 48.695 ;
     RECT  61.815 44.645 62.097 48.859 ;
     RECT  61.2 48.859 62.097 49.037 ;
     RECT  86.292 47.857 86.31 49.181 ;
     RECT  59.652 48.859 59.67 49.199 ;
     RECT  2.415 48.155 2.697 49.723 ;
     RECT  2.304 49.723 2.697 49.775 ;
     RECT  4.068 49.891 4.086 50.011 ;
     RECT  5.472 48.361 5.49 50.011 ;
     RECT  4.068 50.011 5.49 50.045 ;
     RECT  4.788 50.045 5.49 50.051 ;
     RECT  85.464 49.711 85.482 50.432 ;
     RECT  84.924 50.935 84.942 51.053 ;
     RECT  29.415 27.365 29.697 51.331 ;
     RECT  27.612 49.981 27.63 51.601 ;
     RECT  3.924 51.511 3.942 51.665 ;
     RECT  85.464 51.637 85.482 51.677 ;
     RECT  29.415 51.331 29.862 51.781 ;
     RECT  4.464 51.745 4.482 51.821 ;
     RECT  84.888 52.267 84.906 52.349 ;
     RECT  2.415 49.775 2.697 52.987 ;
     RECT  2.34 52.987 3.114 53.024 ;
     RECT  27.54 51.601 27.63 53.221 ;
     RECT  7.056 47.075 7.074 53.32 ;
     RECT  2.415 53.024 3.114 53.401 ;
     RECT  6.876 53.32 7.074 53.401 ;
     RECT  5.472 50.051 5.49 53.419 ;
     RECT  2.415 53.401 3.402 53.453 ;
     RECT  6.84 53.401 7.074 53.519 ;
     RECT  44.1 53.035 44.118 53.519 ;
     RECT  5.256 53.419 5.49 53.555 ;
     RECT  85.464 52.861 85.482 53.555 ;
     RECT  38.304 46.409 38.97 53.563 ;
     RECT  38.304 53.563 39.186 53.6 ;
     RECT  44.388 53.659 44.406 53.789 ;
     RECT  86.292 54.103 86.31 54.173 ;
     RECT  40.215 44.069 40.497 54.211 ;
     RECT  5.472 53.555 5.49 54.239 ;
     RECT  27.54 53.221 27.702 54.301 ;
     RECT  14.832 54.211 14.85 54.329 ;
     RECT  2.415 53.453 2.697 54.571 ;
     RECT  40.215 54.211 40.95 54.571 ;
     RECT  42.372 54.679 42.39 54.751 ;
     RECT  85.5 54.679 85.518 54.797 ;
     RECT  40.215 54.571 41.094 54.869 ;
     RECT  2.304 54.571 2.697 54.905 ;
     RECT  40.215 54.869 40.95 54.905 ;
     RECT  41.832 54.751 42.39 54.905 ;
     RECT  41.94 54.905 42.39 54.985 ;
     RECT  41.94 54.985 42.498 55.021 ;
     RECT  4.644 55.021 4.806 55.085 ;
     RECT  38.304 53.6 38.502 55.111 ;
     RECT  4.788 55.085 4.806 55.139 ;
     RECT  41.94 55.021 42.642 55.139 ;
     RECT  3.564 55.021 3.582 55.175 ;
     RECT  41.94 55.139 42.39 55.175 ;
     RECT  43.452 55.021 43.47 55.255 ;
     RECT  43.452 55.255 43.578 55.445 ;
     RECT  43.488 55.445 43.578 55.679 ;
     RECT  38.304 55.111 38.574 55.957 ;
     RECT  43.92 55.831 43.938 55.963 ;
     RECT  38.304 55.957 38.934 55.997 ;
     RECT  38.304 55.997 38.574 56.093 ;
     RECT  40.215 54.905 40.497 56.101 ;
     RECT  2.415 54.905 2.697 56.203 ;
     RECT  2.304 56.203 2.697 56.255 ;
     RECT  39.852 56.101 40.497 56.255 ;
     RECT  43.92 55.963 44.298 56.255 ;
     RECT  2.415 56.255 2.697 56.371 ;
     RECT  45.615 44.915 45.897 56.371 ;
     RECT  60.516 56.101 60.822 56.399 ;
     RECT  44.28 56.255 44.298 56.429 ;
     RECT  60.516 56.399 60.534 56.429 ;
     RECT  2.415 56.371 2.862 56.489 ;
     RECT  40.215 56.255 40.497 56.605 ;
     RECT  41.22 56.371 41.238 56.605 ;
     RECT  40.215 56.605 41.238 56.641 ;
     RECT  4.14 56.605 4.158 56.669 ;
     RECT  40.215 56.641 41.31 56.669 ;
     RECT  41.22 56.669 41.31 56.759 ;
     RECT  41.22 56.759 41.238 56.795 ;
     RECT  42.084 56.641 42.498 56.795 ;
     RECT  45.288 56.371 45.897 56.795 ;
     RECT  45.615 56.795 45.897 56.875 ;
     RECT  43.524 56.875 43.542 56.911 ;
     RECT  45.615 56.875 45.954 56.911 ;
     RECT  47.304 56.875 47.322 56.911 ;
     RECT  45.615 56.911 46.098 57.029 ;
     RECT  42.192 56.795 42.498 57.181 ;
     RECT  43.452 56.911 43.542 57.181 ;
     RECT  4.896 57.019 4.914 57.299 ;
     RECT  42.192 57.181 42.606 57.299 ;
     RECT  42.192 57.299 42.498 57.335 ;
     RECT  43.38 57.181 43.578 57.335 ;
     RECT  7.056 53.519 7.074 57.451 ;
     RECT  46.908 56.911 47.322 57.451 ;
     RECT  46.908 57.451 47.466 57.569 ;
     RECT  43.452 57.335 43.578 57.721 ;
     RECT  2.415 56.489 2.697 57.835 ;
     RECT  43.452 57.721 43.614 57.839 ;
     RECT  53.172 57.271 53.19 57.875 ;
     RECT  4.752 57.547 4.77 58.081 ;
     RECT  11.808 56.461 11.826 58.081 ;
     RECT  44.424 57.991 44.442 58.081 ;
     RECT  58.572 57.991 58.59 58.117 ;
     RECT  44.424 58.081 44.514 58.123 ;
     RECT  45.615 57.029 45.897 58.123 ;
     RECT  2.304 57.835 2.697 58.145 ;
     RECT  43.452 57.839 43.47 58.157 ;
     RECT  60.552 58.117 60.57 58.189 ;
     RECT  4.284 58.081 4.77 58.261 ;
     RECT  58.572 58.117 58.806 58.261 ;
     RECT  59.868 58.189 60.57 58.261 ;
     RECT  4.284 58.261 4.914 58.379 ;
     RECT  58.572 58.261 58.95 58.379 ;
     RECT  4.284 58.379 4.302 58.415 ;
     RECT  58.572 58.379 58.59 58.415 ;
     RECT  59.76 58.261 60.57 58.649 ;
     RECT  60.552 58.649 60.57 58.651 ;
     RECT  61.815 49.037 62.097 58.651 ;
     RECT  60.552 58.651 62.097 58.657 ;
     RECT  44.424 58.123 45.897 58.685 ;
     RECT  59.76 58.649 59.778 58.685 ;
     RECT  60.552 58.657 62.154 58.685 ;
     RECT  61.092 58.685 62.154 58.691 ;
     RECT  44.496 58.685 45.897 58.801 ;
     RECT  46.764 58.507 46.782 58.801 ;
     RECT  38.304 56.093 38.322 58.891 ;
     RECT  44.496 58.801 47.034 58.919 ;
     RECT  33.336 58.891 33.354 58.928 ;
     RECT  44.496 58.919 44.514 58.955 ;
     RECT  45.615 58.919 46.746 58.955 ;
     RECT  47.88 58.657 47.898 58.955 ;
     RECT  38.304 58.891 38.79 59.021 ;
     RECT  33.012 58.987 33.03 59.027 ;
     RECT  45.615 58.955 46.35 59.189 ;
     RECT  45.615 59.189 46.17 59.225 ;
     RECT  47.916 59.071 48.006 59.225 ;
     RECT  47.916 59.225 47.934 59.459 ;
     RECT  53.712 59.431 53.73 59.467 ;
     RECT  53.712 59.467 53.91 59.603 ;
     RECT  53.892 59.603 53.91 59.639 ;
     RECT  59.292 59.605 59.31 59.645 ;
     RECT  6.444 57.451 7.074 59.701 ;
     RECT  18.615 47.381 18.897 59.701 ;
     RECT  3.6 59.611 3.618 59.729 ;
     RECT  6.228 59.701 7.074 59.843 ;
     RECT  60.408 59.611 60.426 59.845 ;
     RECT  60.408 59.845 60.534 59.881 ;
     RECT  3.96 59.809 3.978 59.885 ;
     RECT  6.228 59.843 6.246 59.999 ;
     RECT  5.328 59.851 5.346 60.035 ;
     RECT  60.408 59.881 60.894 60.035 ;
     RECT  59.04 60.091 59.058 60.269 ;
     RECT  60.588 60.035 60.894 60.385 ;
     RECT  61.815 58.691 62.154 60.385 ;
     RECT  85.464 55.387 85.482 60.413 ;
     RECT  60.588 60.385 62.154 60.449 ;
     RECT  60.732 60.449 62.154 60.511 ;
     RECT  60.732 60.511 62.298 60.539 ;
     RECT  60.732 60.539 60.75 60.701 ;
     RECT  61.668 60.539 62.298 60.845 ;
     RECT  86.292 60.961 86.31 61.037 ;
     RECT  2.415 58.145 2.697 61.087 ;
     RECT  61.74 60.845 62.298 61.099 ;
     RECT  61.74 61.099 62.514 61.115 ;
     RECT  2.415 61.087 2.826 61.133 ;
     RECT  61.815 61.115 62.514 61.231 ;
     RECT  61.815 61.231 62.694 61.349 ;
     RECT  61.815 61.349 62.514 61.385 ;
     RECT  4.248 61.231 4.266 61.465 ;
     RECT  4.248 61.465 4.374 61.501 ;
     RECT  63.684 61.321 63.702 61.501 ;
     RECT  4.248 61.501 4.446 61.619 ;
     RECT  4.248 61.619 4.266 61.655 ;
     RECT  21.924 47.651 21.942 61.655 ;
     RECT  63.468 61.501 63.702 61.655 ;
     RECT  64.728 61.627 64.746 61.771 ;
     RECT  63.648 61.655 63.702 62.041 ;
     RECT  64.656 61.771 64.746 62.041 ;
     RECT  64.62 62.041 65.394 62.155 ;
     RECT  63.648 62.041 63.882 62.159 ;
     RECT  63.648 62.159 63.702 62.189 ;
     RECT  63.684 62.189 63.702 62.195 ;
     RECT  64.62 62.155 65.826 62.195 ;
     RECT  67.215 44.375 67.497 62.311 ;
     RECT  66.744 62.311 67.497 62.465 ;
     RECT  64.728 62.195 65.034 62.477 ;
     RECT  65.016 62.477 65.034 62.699 ;
     RECT  66.996 62.465 67.497 62.735 ;
     RECT  3.636 62.671 3.654 63.005 ;
     RECT  4.104 63.121 4.122 63.197 ;
     RECT  5.04 63.121 5.058 63.211 ;
     RECT  5.04 63.211 5.274 63.239 ;
     RECT  5.256 63.239 5.274 63.248 ;
     RECT  2.415 61.133 2.697 64.363 ;
     RECT  5.004 64.327 5.022 64.363 ;
     RECT  5.004 64.363 5.13 64.397 ;
     RECT  2.34 64.363 2.697 64.4 ;
     RECT  5.112 64.397 5.13 64.589 ;
     RECT  3.96 64.363 3.978 64.625 ;
     RECT  61.815 61.385 62.226 64.741 ;
     RECT  61.815 64.741 62.694 65.245 ;
     RECT  61.815 65.245 62.91 65.281 ;
     RECT  64.116 65.209 64.134 65.281 ;
     RECT  61.815 65.281 63.054 65.399 ;
     RECT  61.815 65.399 62.91 65.435 ;
     RECT  63.828 65.281 64.134 65.435 ;
     RECT  62.892 65.435 62.91 65.549 ;
     RECT  63.864 65.435 64.134 65.705 ;
     RECT  64.152 65.821 64.314 65.939 ;
     RECT  2.415 64.4 2.697 65.947 ;
     RECT  2.415 65.947 2.826 66.091 ;
     RECT  64.152 65.939 64.17 66.128 ;
     RECT  24.015 45.968 24.297 66.181 ;
     RECT  2.415 66.091 3.33 66.209 ;
     RECT  85.464 61.663 85.482 66.245 ;
     RECT  7.056 59.843 7.074 66.325 ;
     RECT  65.088 66.091 65.394 66.361 ;
     RECT  6.732 66.325 7.074 66.365 ;
     RECT  6.876 66.365 7.074 66.479 ;
     RECT  3.672 66.361 3.69 66.515 ;
     RECT  65.052 66.361 65.394 66.515 ;
     RECT  40.215 56.669 40.497 66.631 ;
     RECT  65.232 66.515 65.394 66.631 ;
     RECT  67.215 62.735 67.497 66.631 ;
     RECT  40.215 66.631 40.734 66.701 ;
     RECT  84.924 66.595 84.942 66.701 ;
     RECT  65.232 66.631 65.538 66.749 ;
     RECT  65.232 66.749 65.25 66.785 ;
     RECT  66.6 66.631 67.497 66.785 ;
     RECT  66.816 66.785 67.497 67.055 ;
     RECT  67.215 67.055 67.497 67.171 ;
     RECT  24.015 66.181 24.786 67.531 ;
     RECT  25.524 64.291 25.542 67.531 ;
     RECT  2.415 66.209 2.697 67.627 ;
     RECT  2.304 67.627 2.697 67.703 ;
     RECT  4.608 67.669 4.626 67.711 ;
     RECT  4.248 67.711 4.806 67.829 ;
     RECT  4.248 67.829 4.266 67.865 ;
     RECT  27.504 54.301 27.702 69.547 ;
     RECT  29.415 51.781 29.898 69.581 ;
     RECT  4.32 68.971 4.338 69.601 ;
     RECT  3.996 69.601 4.41 69.719 ;
     RECT  3.996 69.719 4.014 69.755 ;
     RECT  5.328 69.601 5.346 69.755 ;
     RECT  29.415 69.581 29.697 69.931 ;
     RECT  27.504 69.547 28.026 69.989 ;
     RECT  29.124 69.931 29.697 69.989 ;
     RECT  38.304 59.021 38.322 70.375 ;
     RECT  30.744 70.303 30.762 70.403 ;
     RECT  37.764 70.375 38.322 70.411 ;
     RECT  27.504 69.989 27.918 70.565 ;
     RECT  27.54 70.565 27.918 70.601 ;
     RECT  27.54 70.601 27.846 70.637 ;
     RECT  37.116 70.411 38.862 70.645 ;
     RECT  37.116 70.645 39.042 70.681 ;
     RECT  40.215 66.701 40.497 70.681 ;
     RECT  27.612 70.637 27.846 70.709 ;
     RECT  37.116 70.681 40.497 70.795 ;
     RECT  31.896 70.609 31.914 70.799 ;
     RECT  37.116 70.795 40.662 70.835 ;
     RECT  67.215 67.171 67.59 70.835 ;
     RECT  36.324 70.501 36.342 70.915 ;
     RECT  37.116 70.835 38.502 70.915 ;
     RECT  36.324 70.915 38.502 70.939 ;
     RECT  34.815 27.635 35.097 70.951 ;
     RECT  35.892 70.939 38.502 70.973 ;
     RECT  24.015 67.531 25.542 71.041 ;
     RECT  34.308 70.951 35.097 71.077 ;
     RECT  36.864 70.973 38.502 71.105 ;
     RECT  34.164 71.077 35.097 71.117 ;
     RECT  37.62 71.105 38.502 71.117 ;
     RECT  34.815 71.117 35.097 71.149 ;
     RECT  35.892 70.973 36.054 71.149 ;
     RECT  7.056 66.479 7.074 71.221 ;
     RECT  39.276 70.835 40.662 71.221 ;
     RECT  43.74 71.185 43.758 71.221 ;
     RECT  6.264 71.221 7.074 71.261 ;
     RECT  56.415 40.595 56.697 71.311 ;
     RECT  6.336 71.261 7.074 71.339 ;
     RECT  34.815 71.149 36.054 71.339 ;
     RECT  56.304 71.311 56.697 71.357 ;
     RECT  5.148 71.221 5.166 71.375 ;
     RECT  34.815 71.339 35.694 71.375 ;
     RECT  41.652 71.221 41.67 71.491 ;
     RECT  43.74 71.221 43.902 71.491 ;
     RECT  49.644 71.419 49.662 71.491 ;
     RECT  34.815 71.375 35.262 71.609 ;
     RECT  38.196 71.117 38.502 71.609 ;
     RECT  34.815 71.609 35.154 71.645 ;
     RECT  38.196 71.609 38.322 71.645 ;
     RECT  39.276 71.221 40.734 71.645 ;
     RECT  41.652 71.491 42.03 71.645 ;
     RECT  39.672 71.645 40.734 71.689 ;
     RECT  41.652 71.645 41.67 71.689 ;
     RECT  49.644 71.491 49.986 71.725 ;
     RECT  43.74 71.491 43.974 71.761 ;
     RECT  36.864 71.105 36.882 71.879 ;
     RECT  39.672 71.689 41.67 71.915 ;
     RECT  63.216 71.851 63.234 71.933 ;
     RECT  42.804 71.725 42.822 72.031 ;
     RECT  49.572 71.725 49.986 72.121 ;
     RECT  51.015 43.835 51.297 72.121 ;
     RECT  39.852 71.915 41.67 72.149 ;
     RECT  40.215 72.149 41.454 72.185 ;
     RECT  42.444 72.031 42.822 72.221 ;
     RECT  42.48 72.221 42.822 72.229 ;
     RECT  43.74 71.761 44.37 72.229 ;
     RECT  49.572 72.121 51.297 72.265 ;
     RECT  40.215 72.185 41.346 72.293 ;
     RECT  49.14 72.265 51.297 72.293 ;
     RECT  49.14 72.293 49.374 72.301 ;
     RECT  50.292 72.293 51.297 72.301 ;
     RECT  42.48 72.229 44.37 72.329 ;
     RECT  64.332 72.031 64.35 72.365 ;
     RECT  40.215 72.293 41.202 72.419 ;
     RECT  49.032 72.301 49.374 72.419 ;
     RECT  40.215 72.419 41.094 72.455 ;
     RECT  2.415 67.703 2.697 72.523 ;
     RECT  45.615 59.225 45.897 72.535 ;
     RECT  43.74 72.329 44.37 72.571 ;
     RECT  45.504 72.535 45.897 72.571 ;
     RECT  47.016 71.761 47.034 72.571 ;
     RECT  50.292 72.301 51.606 72.571 ;
     RECT  49.032 72.419 49.158 72.661 ;
     RECT  42.48 72.329 42.966 72.689 ;
     RECT  43.74 72.571 47.142 72.689 ;
     RECT  2.304 72.523 2.697 72.725 ;
     RECT  42.48 72.689 42.822 72.725 ;
     RECT  50.292 72.571 52.182 72.725 ;
     RECT  43.956 72.689 47.142 72.805 ;
     RECT  43.956 72.805 47.178 72.841 ;
     RECT  48.78 72.661 49.158 72.841 ;
     RECT  23.616 71.041 25.542 72.931 ;
     RECT  43.956 72.841 47.358 72.959 ;
     RECT  85.464 67.288 85.482 72.959 ;
     RECT  7.815 47.687 8.097 72.967 ;
     RECT  5.148 72.841 5.166 72.995 ;
     RECT  43.956 72.959 43.974 72.995 ;
     RECT  44.964 72.959 47.358 72.995 ;
     RECT  50.724 72.725 52.182 72.995 ;
     RECT  7.815 72.967 8.37 73.037 ;
     RECT  53.28 72.931 53.658 73.111 ;
     RECT  48.132 72.841 49.158 73.265 ;
     RECT  48.996 73.265 49.158 73.309 ;
     RECT  53.1 73.111 53.658 73.345 ;
     RECT  44.964 72.995 46.746 73.379 ;
     RECT  53.1 73.345 53.838 73.381 ;
     RECT  54.72 73.339 54.738 73.381 ;
     RECT  54.72 73.381 54.774 73.387 ;
     RECT  52.092 72.995 52.182 73.483 ;
     RECT  52.992 73.381 53.982 73.483 ;
     RECT  45 73.379 46.746 73.499 ;
     RECT  48.996 73.309 49.302 73.499 ;
     RECT  86.292 73.381 86.31 73.507 ;
     RECT  45 73.499 46.602 73.517 ;
     RECT  48.996 73.499 49.158 73.517 ;
     RECT  52.092 73.483 53.982 73.517 ;
     RECT  45 73.517 46.566 73.535 ;
     RECT  86.256 73.507 86.31 73.565 ;
     RECT  83.415 44.915 83.697 73.615 ;
     RECT  50.724 72.995 51.297 73.651 ;
     RECT  56.415 71.357 56.697 73.651 ;
     RECT  47.592 73.345 48.042 73.769 ;
     RECT  83.415 73.615 83.934 73.769 ;
     RECT  47.592 73.769 47.826 73.805 ;
     RECT  48.996 73.517 49.014 73.805 ;
     RECT  50.076 73.651 51.297 73.805 ;
     RECT  52.452 73.517 53.982 73.805 ;
     RECT  58.824 73.507 58.842 73.805 ;
     RECT  52.992 73.805 53.982 73.813 ;
     RECT  54.72 73.387 54.81 73.813 ;
     RECT  52.992 73.813 54.81 73.849 ;
     RECT  61.815 65.435 62.097 73.885 ;
     RECT  52.992 73.849 55.314 73.921 ;
     RECT  56.415 73.651 57.186 73.921 ;
     RECT  61.38 73.885 62.586 73.921 ;
     RECT  52.992 73.921 57.186 74.039 ;
     RECT  61.38 73.921 63.234 74.039 ;
     RECT  75.132 70.951 75.15 74.039 ;
     RECT  50.22 73.805 51.297 74.075 ;
     RECT  52.992 74.039 56.697 74.075 ;
     RECT  59.688 73.885 59.814 74.075 ;
     RECT  60.624 73.885 60.642 74.075 ;
     RECT  61.38 74.039 62.334 74.075 ;
     RECT  82.116 74.047 82.134 74.093 ;
     RECT  58.032 74.011 58.05 74.107 ;
     RECT  83.415 73.769 83.79 74.119 ;
     RECT  54.792 74.075 56.697 74.141 ;
     RECT  2.415 72.725 2.697 74.155 ;
     RECT  86.256 73.565 86.274 74.189 ;
     RECT  58.032 74.107 58.626 74.191 ;
     RECT  59.688 74.075 59.778 74.191 ;
     RECT  83.196 74.119 83.79 74.191 ;
     RECT  53.46 74.075 53.622 74.309 ;
     RECT  57.456 74.191 58.626 74.309 ;
     RECT  2.412 74.155 2.697 74.345 ;
     RECT  53.46 74.309 53.478 74.345 ;
     RECT  58.032 74.309 58.626 74.345 ;
     RECT  2.415 74.345 2.697 74.443 ;
     RECT  2.415 74.443 3.258 74.461 ;
     RECT  59.652 74.191 59.778 74.461 ;
     RECT  63.072 74.039 63.234 74.461 ;
     RECT  83.088 74.191 83.79 74.551 ;
     RECT  2.415 74.461 3.402 74.579 ;
     RECT  4.176 74.461 4.194 74.579 ;
     RECT  61.38 74.075 62.298 74.579 ;
     RECT  73.944 68.953 73.962 74.579 ;
     RECT  79.38 44.879 79.398 74.587 ;
     RECT  2.415 74.579 3.042 74.615 ;
     RECT  55.296 74.141 56.697 74.615 ;
     RECT  63.072 74.461 63.414 74.615 ;
     RECT  83.052 74.551 83.79 74.615 ;
     RECT  27.828 70.709 27.846 74.623 ;
     RECT  64.332 74.191 64.35 74.623 ;
     RECT  78.015 44.879 78.297 74.635 ;
     RECT  79.38 74.587 79.974 74.635 ;
     RECT  27.756 74.623 27.846 74.651 ;
     RECT  78.015 74.635 79.974 74.669 ;
     RECT  61.38 74.579 62.154 74.683 ;
     RECT  78.015 74.669 79.398 74.687 ;
     RECT  64.332 74.623 64.458 74.695 ;
     RECT  58.608 74.345 58.626 74.717 ;
     RECT  64.332 74.695 64.53 74.731 ;
     RECT  65.376 74.683 65.394 74.731 ;
     RECT  85.5 74.011 85.518 74.813 ;
     RECT  82.152 74.623 82.17 74.849 ;
     RECT  63.108 74.615 63.414 74.885 ;
     RECT  64.332 74.731 65.394 74.885 ;
     RECT  80.964 74.551 80.982 74.885 ;
     RECT  55.98 74.615 56.697 74.921 ;
     RECT  83.415 74.615 83.79 74.965 ;
     RECT  59.58 74.461 59.778 75.001 ;
     RECT  61.164 74.683 62.154 75.001 ;
     RECT  63.144 74.885 63.414 75.119 ;
     RECT  23.616 72.931 25.578 75.127 ;
     RECT  59.58 75.001 62.154 75.155 ;
     RECT  23.076 75.127 25.578 75.199 ;
     RECT  21.96 61.771 21.978 75.271 ;
     RECT  63.468 75.199 63.486 75.271 ;
     RECT  64.44 74.885 65.394 75.271 ;
     RECT  67.215 70.835 67.497 75.271 ;
     RECT  59.76 75.155 62.154 75.389 ;
     RECT  63.468 75.271 63.702 75.389 ;
     RECT  83.415 74.965 83.934 75.389 ;
     RECT  21.96 75.271 22.194 75.397 ;
     RECT  23.04 75.199 25.578 75.397 ;
     RECT  21.96 75.397 25.578 75.403 ;
     RECT  59.76 75.389 59.778 75.425 ;
     RECT  63.468 75.389 63.486 75.425 ;
     RECT  81.072 75.163 81.09 75.425 ;
     RECT  86.292 75.001 86.31 75.437 ;
     RECT  83.415 75.389 83.898 75.505 ;
     RECT  21.636 75.403 25.578 75.541 ;
     RECT  61.815 75.389 62.154 75.541 ;
     RECT  29.415 69.989 29.697 75.631 ;
     RECT  78.015 74.687 79.326 75.631 ;
     RECT  60.624 75.389 60.75 75.659 ;
     RECT  60.624 75.659 60.642 75.695 ;
     RECT  27.756 74.651 27.774 75.775 ;
     RECT  29.415 75.631 29.754 75.775 ;
     RECT  33.984 75.703 34.002 75.775 ;
     RECT  2.415 74.615 2.697 75.787 ;
     RECT  27.648 75.775 27.774 75.787 ;
     RECT  21.636 75.541 25.65 75.803 ;
     RECT  27.108 75.787 27.774 75.811 ;
     RECT  28.548 75.775 28.566 75.811 ;
     RECT  29.376 75.775 29.754 75.811 ;
     RECT  27.108 75.811 29.754 75.901 ;
     RECT  66.384 75.271 67.497 75.901 ;
     RECT  78.015 75.631 80.334 75.901 ;
     RECT  32.508 75.775 32.67 75.937 ;
     RECT  33.948 75.775 34.002 75.937 ;
     RECT  34.815 71.645 35.097 75.937 ;
     RECT  2.304 75.787 2.697 75.965 ;
     RECT  22.932 75.803 25.65 75.965 ;
     RECT  27.108 75.901 30.222 75.973 ;
     RECT  33.84 75.937 35.097 75.973 ;
     RECT  82.62 75.541 82.638 76.009 ;
     RECT  83.376 75.505 83.898 76.009 ;
     RECT  23.004 75.965 25.65 76.045 ;
     RECT  26.784 75.973 30.222 76.045 ;
     RECT  64.44 75.271 65.61 76.045 ;
     RECT  66.384 75.901 67.698 76.045 ;
     RECT  7.056 71.339 7.074 76.081 ;
     RECT  31.248 75.937 31.266 76.081 ;
     RECT  32.148 75.937 32.67 76.081 ;
     RECT  33.48 75.973 35.097 76.081 ;
     RECT  61.815 75.541 62.262 76.081 ;
     RECT  81.468 75.883 81.558 76.081 ;
     RECT  82.62 76.009 83.898 76.081 ;
     RECT  6.444 76.081 7.074 76.199 ;
     RECT  23.004 76.045 30.222 76.199 ;
     RECT  61.815 76.081 62.586 76.199 ;
     RECT  64.44 76.045 67.698 76.207 ;
     RECT  72.615 44.339 72.897 76.207 ;
     RECT  4.68 76.081 4.698 76.235 ;
     RECT  5.472 76.171 5.49 76.235 ;
     RECT  23.004 76.199 28.602 76.235 ;
     RECT  33.48 76.081 35.118 76.235 ;
     RECT  61.815 76.199 62.226 76.235 ;
     RECT  63.36 76.081 63.378 76.235 ;
     RECT  31.248 76.081 32.67 76.315 ;
     RECT  33.48 76.235 33.966 76.315 ;
     RECT  77.544 75.901 80.334 76.315 ;
     RECT  23.004 76.235 28.53 76.343 ;
     RECT  29.415 76.199 30.222 76.351 ;
     RECT  31.248 76.315 33.966 76.351 ;
     RECT  34.776 76.235 35.118 76.351 ;
     RECT  35.856 76.279 35.874 76.351 ;
     RECT  64.44 76.207 67.878 76.351 ;
     RECT  68.94 76.279 68.958 76.351 ;
     RECT  77.544 76.315 80.586 76.351 ;
     RECT  81.468 76.081 83.898 76.351 ;
     RECT  63.756 76.351 68.022 76.397 ;
     RECT  23.616 76.343 28.53 76.469 ;
     RECT  29.415 76.351 33.966 76.469 ;
     RECT  65.196 76.397 68.022 76.469 ;
     RECT  72.324 76.207 72.897 76.469 ;
     RECT  23.616 76.469 28.386 76.505 ;
     RECT  63.756 76.397 64.422 76.505 ;
     RECT  65.196 76.469 67.698 76.505 ;
     RECT  77.436 76.351 83.898 76.505 ;
     RECT  29.415 76.469 32.67 76.577 ;
     RECT  65.196 76.505 67.497 76.613 ;
     RECT  65.196 76.613 66.438 76.649 ;
     RECT  22.176 75.803 22.194 76.739 ;
     RECT  32.544 76.577 32.67 76.739 ;
     RECT  33.84 76.469 33.966 76.739 ;
     RECT  66.24 76.649 66.438 76.739 ;
     RECT  33.84 76.739 33.858 76.775 ;
     RECT  66.24 76.739 66.258 76.775 ;
     RECT  68.832 76.351 69.03 76.775 ;
     RECT  21.24 76.711 21.258 76.855 ;
     RECT  34.776 76.351 35.874 76.855 ;
     RECT  77.544 76.505 83.898 76.855 ;
     RECT  29.415 76.577 31.41 76.883 ;
     RECT  32.652 76.739 32.67 76.883 ;
     RECT  34.776 76.855 36.414 76.891 ;
     RECT  21.24 76.855 21.546 76.925 ;
     RECT  64.152 76.505 64.422 76.925 ;
     RECT  70.2 43.097 70.218 76.981 ;
     RECT  23.616 76.505 27.774 77.009 ;
     RECT  29.415 76.883 29.97 77.009 ;
     RECT  64.296 76.925 64.422 77.009 ;
     RECT  77.544 76.855 83.934 77.009 ;
     RECT  40.215 72.455 40.497 77.017 ;
     RECT  26.676 77.009 27.774 77.045 ;
     RECT  29.415 77.009 29.898 77.045 ;
     RECT  34.776 76.891 36.594 77.045 ;
     RECT  64.296 77.009 64.314 77.045 ;
     RECT  26.676 77.045 26.802 77.081 ;
     RECT  30.78 76.883 31.41 77.081 ;
     RECT  34.815 77.045 36.594 77.089 ;
     RECT  34.815 77.089 36.63 77.125 ;
     RECT  39.06 77.089 39.078 77.161 ;
     RECT  39.816 77.017 40.497 77.161 ;
     RECT  72.615 76.469 72.897 77.161 ;
     RECT  74.664 77.089 74.682 77.189 ;
     RECT  34.815 77.125 37.242 77.251 ;
     RECT  38.304 71.645 38.322 77.251 ;
     RECT  65.196 76.649 65.322 77.279 ;
     RECT  72.615 77.161 73.098 77.279 ;
     RECT  34.815 77.251 38.322 77.315 ;
     RECT  65.196 77.279 65.214 77.315 ;
     RECT  70.2 76.981 70.722 77.315 ;
     RECT  35.856 77.315 38.322 77.387 ;
     RECT  2.415 75.965 2.697 77.395 ;
     RECT  4.536 77.227 4.554 77.431 ;
     RECT  7.056 76.199 7.074 77.431 ;
     RECT  36.324 77.387 38.322 77.431 ;
     RECT  39.06 77.161 40.497 77.431 ;
     RECT  2.412 77.395 2.697 77.453 ;
     RECT  4.068 77.431 4.698 77.549 ;
     RECT  4.068 77.549 4.086 77.585 ;
     RECT  77.544 77.009 83.697 77.593 ;
     RECT  36.324 77.431 40.497 77.621 ;
     RECT  37.62 77.621 40.497 77.629 ;
     RECT  70.2 77.315 70.686 77.729 ;
     RECT  77.004 77.593 83.697 77.791 ;
     RECT  37.62 77.629 40.554 77.819 ;
     RECT  42.768 77.701 42.786 77.819 ;
     RECT  6.84 77.431 7.074 77.855 ;
     RECT  39.816 77.819 40.554 77.855 ;
     RECT  70.668 77.729 70.686 77.891 ;
     RECT  77.004 77.791 83.898 77.891 ;
     RECT  37.62 77.819 38.574 77.927 ;
     RECT  36.324 77.621 36.594 77.963 ;
     RECT  37.62 77.927 38.538 77.963 ;
     RECT  36.324 77.963 36.342 78.077 ;
     RECT  39.852 77.855 40.554 78.089 ;
     RECT  65.16 78.043 65.178 78.089 ;
     RECT  39.996 78.089 40.554 78.097 ;
     RECT  77.004 77.891 83.697 78.097 ;
     RECT  37.656 77.963 38.322 78.125 ;
     RECT  85.464 76.072 85.482 78.125 ;
     RECT  39.996 78.097 40.662 78.241 ;
     RECT  65.448 78.235 65.466 78.275 ;
     RECT  84.924 78.475 84.942 78.605 ;
     RECT  76.104 78.097 76.122 78.665 ;
     RECT  76.932 78.097 83.697 78.781 ;
     RECT  2.415 77.453 2.697 79.051 ;
     RECT  39.996 78.241 41.13 79.051 ;
     RECT  2.304 79.051 2.697 79.205 ;
     RECT  85.464 79.195 85.482 79.241 ;
     RECT  2.415 79.205 2.697 79.321 ;
     RECT  75.708 79.015 75.726 79.519 ;
     RECT  75.708 79.519 75.762 79.555 ;
     RECT  5.796 79.447 5.814 79.591 ;
     RECT  7.056 77.855 7.074 79.591 ;
     RECT  75.204 79.555 75.978 79.591 ;
     RECT  76.716 78.781 83.697 79.591 ;
     RECT  75.204 79.591 83.79 79.681 ;
     RECT  5.796 79.591 7.074 79.709 ;
     RECT  74.88 79.681 83.79 79.757 ;
     RECT  39.996 79.051 41.454 79.771 ;
     RECT  4.248 79.411 4.266 79.789 ;
     RECT  5.004 79.591 5.022 79.789 ;
     RECT  75.204 79.757 83.79 79.805 ;
     RECT  2.415 79.321 3.402 79.861 ;
     RECT  4.248 79.789 5.022 79.861 ;
     RECT  17.028 54.841 17.046 79.987 ;
     RECT  75.348 79.805 83.79 80.131 ;
     RECT  2.415 79.861 5.022 80.257 ;
     RECT  5.796 79.709 6.174 80.257 ;
     RECT  75.348 80.131 83.826 80.257 ;
     RECT  27.756 77.045 27.774 80.365 ;
     RECT  38.304 78.125 38.322 80.365 ;
     RECT  74.448 80.365 74.466 80.401 ;
     RECT  86.292 79.717 86.31 80.477 ;
     RECT  2.415 80.257 6.174 80.491 ;
     RECT  38.304 80.365 38.502 80.491 ;
     RECT  72.615 77.279 72.897 80.491 ;
     RECT  72.615 80.491 73.35 80.587 ;
     RECT  74.232 80.401 74.466 80.587 ;
     RECT  75.348 80.257 83.934 80.587 ;
     RECT  69.876 80.491 69.894 80.599 ;
     RECT  36.684 80.443 36.702 80.635 ;
     RECT  39.996 79.771 41.49 80.635 ;
     RECT  69.876 80.599 70.146 80.635 ;
     RECT  27.756 80.365 27.846 80.671 ;
     RECT  39.924 80.635 41.49 80.671 ;
     RECT  55.008 80.527 55.026 80.671 ;
     RECT  68.724 80.635 68.742 80.671 ;
     RECT  69.516 80.635 70.434 80.671 ;
     RECT  36.684 80.635 36.81 80.683 ;
     RECT  30.78 77.081 30.798 80.761 ;
     RECT  38.124 80.491 38.502 80.761 ;
     RECT  54.504 80.671 55.35 80.761 ;
     RECT  56.415 74.921 56.697 80.761 ;
     RECT  68.616 80.671 68.742 80.761 ;
     RECT  69.516 80.671 70.83 80.761 ;
     RECT  30.78 80.761 31.086 80.779 ;
     RECT  54.504 80.761 56.697 80.797 ;
     RECT  71.676 80.797 71.694 80.827 ;
     RECT  7.056 79.709 7.074 80.861 ;
     RECT  2.34 80.491 6.174 80.905 ;
     RECT  27.756 80.671 27.882 80.905 ;
     RECT  34.815 77.315 35.097 80.905 ;
     RECT  38.124 80.761 38.79 80.905 ;
     RECT  39.924 80.671 41.598 80.905 ;
     RECT  45.615 73.535 45.897 80.905 ;
     RECT  54.072 80.797 56.697 80.905 ;
     RECT  71.676 80.827 71.73 80.905 ;
     RECT  72.615 80.587 83.934 80.905 ;
     RECT  27.648 80.905 27.882 80.923 ;
     RECT  67.215 76.613 67.497 80.923 ;
     RECT  18.18 59.701 18.897 80.941 ;
     RECT  19.656 77.791 19.674 80.941 ;
     RECT  21.24 76.925 21.258 80.941 ;
     RECT  22.788 80.635 22.806 80.941 ;
     RECT  26.676 77.081 26.694 80.941 ;
     RECT  27.468 80.923 27.882 80.941 ;
     RECT  38.124 80.905 41.598 80.941 ;
     RECT  51.015 74.075 51.297 80.941 ;
     RECT  53.784 80.905 56.697 80.941 ;
     RECT  61.815 76.235 62.097 80.941 ;
     RECT  68.616 80.761 70.83 80.941 ;
     RECT  71.676 80.905 83.934 80.941 ;
     RECT  30.744 80.779 31.086 80.957 ;
     RECT  45.504 80.905 45.897 80.957 ;
     RECT  16.776 79.987 17.046 80.971 ;
     RECT  18.18 80.941 20.178 80.971 ;
     RECT  38.088 80.941 41.598 81.019 ;
     RECT  22.716 80.941 22.806 81.031 ;
     RECT  23.616 77.009 25.578 81.031 ;
     RECT  34.74 80.905 35.097 81.031 ;
     RECT  42.588 79.483 42.606 81.031 ;
     RECT  50.904 80.941 51.297 81.031 ;
     RECT  53.712 80.941 56.697 81.031 ;
     RECT  68.616 80.941 83.934 81.031 ;
     RECT  26.676 80.941 27.882 81.067 ;
     RECT  53.604 81.031 56.697 81.067 ;
     RECT  68.328 81.031 83.934 81.095 ;
     RECT  21.24 80.941 21.618 81.103 ;
     RECT  22.716 81.031 25.578 81.103 ;
     RECT  26.64 81.067 27.882 81.103 ;
     RECT  29.415 77.045 29.697 81.103 ;
     RECT  30.744 80.957 30.834 81.103 ;
     RECT  42.516 81.031 42.606 81.103 ;
     RECT  53.604 81.067 57.222 81.103 ;
     RECT  21.24 81.103 21.726 81.139 ;
     RECT  36.648 80.683 36.81 81.175 ;
     RECT  50.724 81.031 51.858 81.175 ;
     RECT  21.24 81.139 21.942 81.211 ;
     RECT  22.716 81.103 27.882 81.211 ;
     RECT  33.876 81.139 33.894 81.211 ;
     RECT  50.724 81.175 52.038 81.211 ;
     RECT  53.1 81.103 57.222 81.211 ;
     RECT  67.104 80.923 67.497 81.211 ;
     RECT  50.724 81.211 57.222 81.239 ;
     RECT  2.304 80.905 6.174 81.301 ;
     RECT  13.215 47.579 13.497 81.301 ;
     RECT  21.24 81.211 27.882 81.301 ;
     RECT  59.22 81.067 59.238 81.307 ;
     RECT  68.328 81.095 71.082 81.329 ;
     RECT  16.776 80.971 20.178 81.337 ;
     RECT  50.724 81.239 57.15 81.337 ;
     RECT  65.952 80.905 65.97 81.337 ;
     RECT  67.104 81.211 67.59 81.337 ;
     RECT  68.328 81.329 70.974 81.337 ;
     RECT  42.444 81.103 42.606 81.355 ;
     RECT  43.992 81.103 44.01 81.355 ;
     RECT  65.952 81.337 66.042 81.355 ;
     RECT  66.924 81.337 70.974 81.355 ;
     RECT  72.072 81.095 83.934 81.365 ;
     RECT  74.664 81.365 83.934 81.401 ;
     RECT  85.464 81.067 85.482 81.401 ;
     RECT  33.336 81.211 33.894 81.409 ;
     RECT  42.444 81.355 42.786 81.409 ;
     RECT  16.776 81.337 20.214 81.445 ;
     RECT  21.24 81.301 28.026 81.445 ;
     RECT  29.415 81.103 30.834 81.445 ;
     RECT  38.088 81.019 41.634 81.445 ;
     RECT  42.444 81.409 43.074 81.445 ;
     RECT  43.884 81.355 44.01 81.445 ;
     RECT  64.296 81.259 64.314 81.445 ;
     RECT  7.815 73.037 8.097 81.451 ;
     RECT  36.468 81.175 36.81 81.481 ;
     RECT  38.088 81.445 44.01 81.481 ;
     RECT  61.056 81.211 61.074 81.481 ;
     RECT  64.152 81.445 64.314 81.481 ;
     RECT  65.952 81.355 70.974 81.481 ;
     RECT  16.776 81.445 20.25 81.499 ;
     RECT  46.764 81.103 46.782 81.499 ;
     RECT  0.108 80.869 0.126 81.571 ;
     RECT  2.304 81.301 6.246 81.571 ;
     RECT  32.76 81.409 33.894 81.571 ;
     RECT  34.74 81.031 35.694 81.571 ;
     RECT  45.576 80.957 45.897 81.571 ;
     RECT  50.688 81.337 57.15 81.571 ;
     RECT  60.984 81.481 61.074 81.571 ;
     RECT  61.815 80.941 62.73 81.571 ;
     RECT  64.116 81.481 64.422 81.571 ;
     RECT  65.232 81.481 70.974 81.571 ;
     RECT  60.3 81.571 62.73 81.595 ;
     RECT  16.776 81.499 20.466 81.607 ;
     RECT  21.24 81.445 30.834 81.607 ;
     RECT  31.788 81.481 31.806 81.607 ;
     RECT  32.76 81.571 35.694 81.607 ;
     RECT  60.3 81.595 62.874 81.607 ;
     RECT  86.256 80.905 86.274 81.607 ;
     RECT  2.304 81.571 6.318 81.643 ;
     RECT  16.704 81.607 30.834 81.643 ;
     RECT  37.872 81.481 44.01 81.643 ;
     RECT  46.764 81.499 47.07 81.643 ;
     RECT  48.78 80.941 48.798 81.643 ;
     RECT  49.536 81.301 49.554 81.643 ;
     RECT  60.3 81.607 63.018 81.643 ;
     RECT  2.232 81.643 6.318 81.679 ;
     RECT  7.308 81.451 8.097 81.679 ;
     RECT  11.664 58.081 11.826 81.679 ;
     RECT  36.468 81.481 36.918 81.679 ;
     RECT  37.872 81.643 44.226 81.679 ;
     RECT  31.788 81.607 35.694 81.691 ;
     RECT  36.468 81.679 37.026 81.691 ;
     RECT  16.632 81.643 30.834 81.715 ;
     RECT  45.576 81.571 45.918 81.715 ;
     RECT  46.764 81.643 47.106 81.715 ;
     RECT  9.108 81.163 9.126 81.751 ;
     RECT  10.08 81.643 10.098 81.751 ;
     RECT  16.416 81.715 30.978 81.751 ;
     RECT  48.78 81.643 49.554 81.751 ;
     RECT  50.292 81.571 57.15 81.751 ;
     RECT  58.104 81.481 58.122 81.751 ;
     RECT  59.112 81.307 59.238 81.751 ;
     RECT  64.116 81.571 70.974 81.751 ;
     RECT  74.736 81.401 83.934 81.751 ;
     RECT  11.664 81.679 12.33 81.779 ;
     RECT  9.108 81.751 10.098 81.835 ;
     RECT  31.788 81.691 37.026 81.841 ;
     RECT  37.8 81.679 44.226 81.841 ;
     RECT  45.576 81.715 47.106 81.841 ;
     RECT  60.156 81.643 63.018 81.841 ;
     RECT  72.072 81.365 73.566 81.841 ;
     RECT  16.38 81.751 30.978 81.877 ;
     RECT  31.788 81.841 47.466 81.877 ;
     RECT  72.036 81.841 73.566 81.913 ;
     RECT  74.736 81.751 84.114 81.977 ;
     RECT  11.664 81.779 12.258 82.013 ;
     RECT  11.664 82.013 12.186 82.021 ;
     RECT  11.16 82.021 12.186 82.075 ;
     RECT  13.215 81.301 14.022 82.111 ;
     RECT  14.832 81.643 14.85 82.111 ;
     RECT  60.156 81.841 63.09 82.111 ;
     RECT  63.936 81.751 70.974 82.111 ;
     RECT  71.964 81.913 73.566 82.111 ;
     RECT  2.232 81.679 8.097 82.147 ;
     RECT  8.892 81.835 10.098 82.147 ;
     RECT  16.164 81.877 47.466 82.147 ;
     RECT  48.78 81.751 57.15 82.147 ;
     RECT  58.104 81.751 59.382 82.147 ;
     RECT  60.156 82.111 73.566 82.147 ;
     RECT  16.164 82.147 57.15 82.171 ;
     RECT  10.872 82.075 12.186 82.183 ;
     RECT  13.215 82.111 14.958 82.183 ;
     RECT  15.768 82.171 57.15 82.183 ;
     RECT  58.104 82.147 73.566 82.183 ;
     RECT  86.256 81.607 86.31 82.183 ;
     RECT  13.215 82.183 73.566 82.291 ;
     RECT  13.215 82.291 73.926 82.381 ;
     RECT  2.232 82.147 10.098 82.561 ;
     RECT  10.836 82.183 12.186 82.561 ;
     RECT  13.215 82.381 73.998 82.561 ;
     RECT  74.736 81.977 83.898 82.561 ;
     RECT  2.232 82.561 12.186 82.589 ;
     RECT  13.215 82.561 83.898 82.687 ;
     RECT  12.996 82.687 83.898 82.723 ;
     RECT  2.304 82.589 12.186 82.921 ;
     RECT  12.996 82.723 83.97 82.921 ;
     RECT  85.536 82.183 86.31 83.029 ;
     RECT  2.304 82.921 83.97 83.299 ;
     RECT  2.304 83.299 84.402 83.759 ;
     RECT  0.072 81.571 0.126 83.851 ;
     RECT  0.072 83.851 0.162 83.885 ;
     RECT  49.428 83.759 84.402 83.939 ;
     RECT  0.108 83.885 0.162 83.981 ;
     RECT  2.304 83.759 12.258 84.029 ;
     RECT  12.996 83.759 48.474 84.029 ;
     RECT  49.428 83.939 58.518 84.029 ;
     RECT  59.328 83.939 84.402 84.029 ;
     RECT  10.044 84.029 12.258 84.101 ;
     RECT  21.708 84.029 35.622 84.101 ;
     RECT  36.612 84.029 48.438 84.101 ;
     RECT  49.428 84.029 54.99 84.101 ;
     RECT  59.328 84.029 69.894 84.101 ;
     RECT  73.476 84.029 79.506 84.101 ;
     RECT  10.044 84.101 12.186 84.137 ;
     RECT  36.612 84.101 41.202 84.173 ;
     RECT  80.424 84.029 81.954 84.173 ;
     RECT  4.68 84.029 9.27 84.209 ;
     RECT  16.056 84.029 20.934 84.209 ;
     RECT  21.924 84.101 31.374 84.209 ;
     RECT  32.292 84.101 35.622 84.209 ;
     RECT  60.12 84.101 69.894 84.209 ;
     RECT  78.015 84.101 79.506 84.209 ;
     RECT  82.692 84.029 84.402 84.209 ;
     RECT  85.5 83.029 86.31 84.221 ;
     RECT  2.304 84.029 3.906 84.257 ;
     RECT  43.236 84.101 48.438 84.257 ;
     RECT  70.704 84.029 72.705 84.257 ;
     RECT  78.015 84.209 78.354 84.257 ;
     RECT  83.415 84.209 84.402 84.257 ;
     RECT  16.056 84.209 19.062 84.365 ;
     RECT  21.924 84.209 26.694 84.365 ;
     RECT  46.368 84.257 48.438 84.365 ;
     RECT  66.96 84.209 69.894 84.365 ;
     RECT  80.784 84.173 81.954 84.365 ;
     RECT  83.664 84.257 84.402 84.365 ;
     RECT  4.68 84.209 5.13 84.413 ;
     RECT  5.868 84.209 9.27 84.413 ;
     RECT  11.268 84.137 12.186 84.413 ;
     RECT  13.104 84.029 15.21 84.413 ;
     RECT  20.088 84.209 20.934 84.413 ;
     RECT  21.924 84.365 25.506 84.413 ;
     RECT  32.292 84.209 33.75 84.413 ;
     RECT  34.776 84.209 35.622 84.413 ;
     RECT  60.264 84.209 66.222 84.413 ;
     RECT  78.156 84.257 78.354 84.413 ;
     RECT  85.5 84.221 86.274 84.845 ;
     RECT  2.304 84.257 2.394 84.911 ;
     RECT  3.132 84.257 3.906 84.922 ;
     RECT  5.868 84.413 8.874 84.941 ;
     RECT  10.044 84.137 10.53 84.941 ;
     RECT  17.136 84.365 19.062 84.941 ;
     RECT  23.256 84.413 23.742 84.941 ;
     RECT  24.912 84.413 25.506 84.941 ;
     RECT  26.676 84.365 26.694 84.941 ;
     RECT  27.468 84.209 28.53 84.941 ;
     RECT  36.612 84.173 41.094 84.941 ;
     RECT  41.976 84.101 42.21 84.941 ;
     RECT  43.236 84.257 45.486 84.941 ;
     RECT  54 84.101 54.99 84.941 ;
     RECT  55.764 84.029 58.518 84.941 ;
     RECT  60.264 84.413 65.718 84.941 ;
     RECT  73.476 84.101 77.274 84.941 ;
     RECT  79.128 84.209 79.506 84.941 ;
     RECT  80.784 84.365 81.486 85.469 ;
     RECT  85.5 84.845 86.238 85.469 ;
     RECT  2.376 84.911 2.394 85.517 ;
     RECT  3.132 84.922 3.87 85.517 ;
     RECT  5.868 84.941 7.65 85.517 ;
     RECT  11.268 84.413 11.898 85.517 ;
     RECT  17.856 84.941 18.522 85.517 ;
     RECT  23.724 84.941 23.742 85.517 ;
     RECT  28.512 84.941 28.53 85.517 ;
     RECT  29.268 84.209 31.374 85.517 ;
     RECT  40.572 84.941 41.094 85.517 ;
     RECT  42.192 84.941 42.21 85.517 ;
     RECT  45.468 84.941 45.486 85.517 ;
     RECT  54 84.941 54.018 85.517 ;
     RECT  58.5 84.941 58.518 85.517 ;
     RECT  65.268 84.941 65.286 85.517 ;
     RECT  81.036 85.469 81.486 85.517 ;
     RECT  84.024 84.365 84.402 85.517 ;
     RECT  0.108 83.981 0.126 85.613 ;
     RECT  60.264 84.941 64.17 85.997 ;
     RECT  36.612 84.941 39.366 86.045 ;
     RECT  43.704 84.941 43.722 86.045 ;
     RECT  74.196 84.941 77.274 86.045 ;
     RECT  85.5 85.469 86.202 86.093 ;
     RECT  20.088 84.413 20.322 86.237 ;
     RECT  49.428 84.101 53.262 86.237 ;
     RECT  60.264 85.997 60.498 86.237 ;
     RECT  3.132 85.517 3.834 86.285 ;
     RECT  4.68 84.413 4.698 86.285 ;
     RECT  5.868 85.517 6.318 86.285 ;
     RECT  7.632 85.517 7.65 86.285 ;
     RECT  8.856 84.941 8.874 86.285 ;
     RECT  10.044 84.941 10.062 86.285 ;
     RECT  11.268 85.517 11.286 86.285 ;
     RECT  13.104 84.413 14.922 86.285 ;
     RECT  16.056 84.365 16.074 86.285 ;
     RECT  17.856 85.517 17.874 86.285 ;
     RECT  20.088 86.237 20.106 86.285 ;
     RECT  21.924 84.413 21.942 86.285 ;
     RECT  27.468 84.941 27.486 86.285 ;
     RECT  29.268 85.517 29.286 86.285 ;
     RECT  30.492 85.517 31.086 86.285 ;
     RECT  32.292 84.413 32.886 86.285 ;
     RECT  34.776 84.413 35.262 86.285 ;
     RECT  36.612 86.045 37.17 86.285 ;
     RECT  38.268 86.045 39.366 86.285 ;
     RECT  46.368 84.365 47.358 86.285 ;
     RECT  48.42 84.365 48.438 86.285 ;
     RECT  49.428 86.237 49.446 86.285 ;
     RECT  50.184 86.237 53.262 86.285 ;
     RECT  56.808 84.941 57.51 86.285 ;
     RECT  59.328 84.101 59.346 86.285 ;
     RECT  60.48 86.237 60.498 86.285 ;
     RECT  61.56 85.997 61.578 86.285 ;
     RECT  62.82 85.997 64.17 86.285 ;
     RECT  66.96 84.365 68.238 86.285 ;
     RECT  69.3 84.365 69.894 86.285 ;
     RECT  70.704 84.257 72.522 86.285 ;
     RECT  74.196 86.045 75.546 86.285 ;
     RECT  76.68 86.045 77.274 86.285 ;
     RECT  78.156 84.413 78.174 86.285 ;
     RECT  79.128 84.941 79.146 86.285 ;
     RECT  81.468 85.517 81.486 86.285 ;
     RECT  84.024 85.517 84.042 86.285 ;
     RECT  85.5 86.093 86.13 86.285 ;
    LAYER M4 ;
     RECT  0.097 4.08 0.137 4.2 ;
     RECT  0.097 38.208 0.137 38.328 ;
     RECT  0.181 0.096 1.457 0.84 ;
     RECT  1.457 0.096 1.973 1.752 ;
     RECT  0.277 80.688 2.101 81.48 ;
     RECT  0.137 4.176 2.293 4.2 ;
     RECT  1.973 0.096 2.339 0.84 ;
     RECT  1.477 86.256 2.365 86.28 ;
     RECT  2.293 3.984 2.408 4.2 ;
     RECT  0.277 5.184 2.408 5.736 ;
     RECT  0.137 38.208 2.408 38.232 ;
     RECT  0.181 43.056 2.408 43.224 ;
     RECT  2.101 80.688 2.408 81.912 ;
     RECT  0.901 83.04 2.408 83.064 ;
     RECT  2.408 2.148 2.512 84.252 ;
     RECT  2.512 2.148 2.704 83.982 ;
     RECT  2.365 85.488 2.723 86.28 ;
     RECT  2.704 18.72 2.765 18.744 ;
     RECT  2.704 80.112 2.819 83.544 ;
     RECT  2.339 0.096 2.837 0.696 ;
     RECT  2.704 61.104 2.837 61.128 ;
     RECT  2.704 66 2.837 66.024 ;
     RECT  2.819 80.112 2.915 81.192 ;
     RECT  2.915 80.112 2.945 80.376 ;
     RECT  2.704 17.088 2.981 17.112 ;
     RECT  2.704 38.208 3.017 38.232 ;
     RECT  2.704 4.176 3.125 6.168 ;
     RECT  2.704 2.148 3.205 2.328 ;
     RECT  3.205 1.728 3.377 2.328 ;
     RECT  2.704 28.272 3.443 29.64 ;
     RECT  2.723 86.256 3.836 86.28 ;
     RECT  3.377 2.304 3.845 2.328 ;
     RECT  3.836 85.488 3.923 86.28 ;
     RECT  3.443 28.272 3.953 28.296 ;
     RECT  2.704 43.056 4.093 43.08 ;
     RECT  2.704 41.616 4.117 41.64 ;
     RECT  4.117 40.992 4.163 41.64 ;
     RECT  4.076 63.168 4.163 63.192 ;
     RECT  4.163 40.992 4.204 41.016 ;
     RECT  2.945 80.112 4.237 80.136 ;
     RECT  2.704 74.448 4.259 74.472 ;
     RECT  4.237 79.44 4.277 80.136 ;
     RECT  3.125 4.944 4.381 6.168 ;
     RECT  3.697 3.84 4.453 3.864 ;
     RECT  4.129 56.64 4.549 56.664 ;
     RECT  4.481 1.728 4.565 1.752 ;
     RECT  4.501 77.232 4.588 77.256 ;
     RECT  4.549 56.64 4.595 57.576 ;
     RECT  4.309 68.976 4.595 69 ;
     RECT  4.093 43.056 4.643 43.752 ;
     RECT  4.556 44.976 4.643 45 ;
     RECT  4.525 48.336 4.643 48.36 ;
     RECT  2.819 82.464 4.669 82.824 ;
     RECT  4.549 67.68 4.701 67.704 ;
     RECT  3.923 86.256 4.709 86.28 ;
     RECT  4.669 82.272 4.741 82.824 ;
     RECT  2.704 23.904 4.745 23.928 ;
     RECT  4.741 82.128 4.745 82.824 ;
     RECT  2.704 53.424 4.789 53.448 ;
     RECT  4.597 50.016 4.817 50.04 ;
     RECT  4.453 51.792 4.835 51.816 ;
     RECT  4.549 55.056 4.835 55.08 ;
     RECT  3.443 29.616 4.885 29.64 ;
     RECT  4.885 29.376 4.925 29.64 ;
     RECT  4.595 57.024 4.969 57.576 ;
     RECT  4.117 64.368 5.068 64.392 ;
     RECT  2.704 34.8 5.077 34.824 ;
     RECT  3.949 59.856 5.077 59.88 ;
     RECT  4.525 33.6 5.101 33.624 ;
     RECT  4.561 27.36 5.123 27.384 ;
     RECT  5.077 34.8 5.123 35.976 ;
     RECT  4.117 61.488 5.123 61.512 ;
     RECT  4.453 3.408 5.125 3.864 ;
     RECT  4.381 4.944 5.125 6.36 ;
     RECT  4.885 20.448 5.125 20.472 ;
     RECT  5.101 33.264 5.141 33.624 ;
     RECT  5.057 84.384 5.141 84.408 ;
     RECT  5.123 35.328 5.164 35.976 ;
     RECT  5.237 18.816 5.269 18.84 ;
     RECT  4.745 82.128 5.269 82.488 ;
     RECT  4.789 53.328 5.285 53.448 ;
     RECT  4.561 17.616 5.315 17.64 ;
     RECT  5.269 18.72 5.321 18.84 ;
     RECT  5.245 63.216 5.329 63.24 ;
     RECT  2.837 0.096 5.356 0.12 ;
     RECT  5.125 19.92 5.357 20.472 ;
     RECT  5.077 59.808 5.357 59.88 ;
     RECT  4.417 9.168 5.411 9.192 ;
     RECT  5.389 20.496 5.461 20.52 ;
     RECT  2.704 21.648 5.461 21.672 ;
     RECT  5.461 20.496 5.497 21.672 ;
     RECT  4.669 22.752 5.497 22.776 ;
     RECT  4.213 76.176 5.501 76.2 ;
     RECT  5.365 10.56 5.565 10.584 ;
     RECT  5.125 3.408 5.573 6.36 ;
     RECT  5.281 12.432 5.641 12.456 ;
     RECT  5.641 12 5.725 12.552 ;
     RECT  5.356 0.096 5.797 0.168 ;
     RECT  4.277 79.44 5.825 79.704 ;
     RECT  5.497 20.496 5.921 22.776 ;
     RECT  5.921 20.496 5.987 23.4 ;
     RECT  5.987 23.376 6.005 23.4 ;
     RECT  4.117 39.888 6.037 39.912 ;
     RECT  4.925 29.376 6.073 29.4 ;
     RECT  5.269 81.648 6.092 82.488 ;
     RECT  5.321 18.72 6.113 18.744 ;
     RECT  5.245 44.448 6.133 44.472 ;
     RECT  5.573 3.552 6.179 6.36 ;
     RECT  6.133 46.608 6.181 46.632 ;
     RECT  6.092 81.264 6.218 82.488 ;
     RECT  6.133 44.352 6.22 44.472 ;
     RECT  5.365 7.584 6.221 7.608 ;
     RECT  5.141 33.264 6.221 33.288 ;
     RECT  6.037 39.072 6.221 39.912 ;
     RECT  6.22 44.448 6.227 44.472 ;
     RECT  6.181 45.984 6.268 46.632 ;
     RECT  6.073 29.376 6.284 30.312 ;
     RECT  5.701 86.256 6.329 86.28 ;
     RECT  6.253 71.232 6.337 71.256 ;
     RECT  5.797 0.096 6.365 0.6 ;
     RECT  5.077 26.256 6.365 26.28 ;
     RECT  6.284 28.8 6.371 30.312 ;
     RECT  6.371 30.192 6.401 30.312 ;
     RECT  4.849 31.536 6.401 31.56 ;
     RECT  6.218 81.312 6.433 82.488 ;
     RECT  4.969 57.552 6.473 57.576 ;
     RECT  5.357 59.808 6.581 59.832 ;
     RECT  5.164 35.328 6.653 35.736 ;
     RECT  4.645 66.336 6.761 66.36 ;
     RECT  6.721 23.808 6.805 24.504 ;
     RECT  6.401 30.288 6.829 30.312 ;
     RECT  6.661 1.728 6.833 1.752 ;
     RECT  6.749 25.584 6.833 25.608 ;
     RECT  4.741 37.584 6.937 37.608 ;
     RECT  6.86 85.488 6.947 85.512 ;
     RECT  6.937 37.056 7.009 37.608 ;
     RECT  6.221 39.072 7.009 39.096 ;
     RECT  5.725 12.528 7.052 12.552 ;
     RECT  6.268 46.512 7.429 46.632 ;
     RECT  7.429 45.552 7.469 46.632 ;
     RECT  7.469 45.456 7.477 46.632 ;
     RECT  4.885 47.856 7.477 47.88 ;
     RECT  6.365 0.576 7.505 0.6 ;
     RECT  6.805 23.808 7.513 23.832 ;
     RECT  6.433 26.64 7.513 27.096 ;
     RECT  6.653 35.712 7.585 35.736 ;
     RECT  7.477 86.256 7.661 86.28 ;
     RECT  5.987 20.496 7.693 22.248 ;
     RECT  6.179 3.552 7.808 6.168 ;
     RECT  7.052 12.384 7.808 12.552 ;
     RECT  7.093 14.208 7.808 14.232 ;
     RECT  4.417 15.888 7.808 15.912 ;
     RECT  7.093 17.616 7.808 17.88 ;
     RECT  7.693 19.584 7.808 22.248 ;
     RECT  7.513 23.376 7.808 23.832 ;
     RECT  7.513 26.64 7.808 27.384 ;
     RECT  6.829 30.288 7.808 30.408 ;
     RECT  7.477 34.08 7.808 34.104 ;
     RECT  7.585 35.712 7.808 36.024 ;
     RECT  7.009 37.056 7.808 39.096 ;
     RECT  4.643 43.056 7.808 43.08 ;
     RECT  7.477 45.456 7.808 47.88 ;
     RECT  5.285 53.328 7.808 53.352 ;
     RECT  4.213 73.008 7.808 73.032 ;
     RECT  5.825 79.44 7.808 79.464 ;
     RECT  6.433 81.312 7.808 83.256 ;
     RECT  7.808 2.148 7.912 84.252 ;
     RECT  7.912 2.418 8.081 84.252 ;
     RECT  8.081 2.418 8.104 84.936 ;
     RECT  8.104 84.912 8.165 84.936 ;
     RECT  8.104 32.064 8.243 34.104 ;
     RECT  7.505 0.096 8.273 0.6 ;
     RECT  8.104 37.008 8.273 38.808 ;
     RECT  8.104 35.328 8.281 36.024 ;
     RECT  8.243 32.064 8.284 32.904 ;
     RECT  8.104 73.008 8.381 73.032 ;
     RECT  8.104 20.976 8.453 21.672 ;
     RECT  8.104 18.24 8.489 19.608 ;
     RECT  8.104 46.608 8.489 47.88 ;
     RECT  8.273 37.008 8.819 37.848 ;
     RECT  8.104 79.44 8.867 80.376 ;
     RECT  8.677 86.256 8.885 86.28 ;
     RECT  8.453 21.12 9.029 21.672 ;
     RECT  8.104 27.072 9.097 27.096 ;
     RECT  8.867 80.352 9.097 80.376 ;
     RECT  8.104 81.456 9.097 83.112 ;
     RECT  8.104 30.384 9.133 30.408 ;
     RECT  8.819 37.008 9.209 37.032 ;
     RECT  9.241 84.384 9.347 84.408 ;
     RECT  8.489 18.24 9.493 19.512 ;
     RECT  8.104 3.12 9.497 6.168 ;
     RECT  8.104 25.632 9.529 25.656 ;
     RECT  8.284 32.496 9.569 32.904 ;
     RECT  8.243 34.08 9.569 34.104 ;
     RECT  9.493 18.144 9.641 19.992 ;
     RECT  9.529 25.056 9.673 25.656 ;
     RECT  8.281 35.712 9.673 36.024 ;
     RECT  9.673 25.056 9.683 25.992 ;
     RECT  9.683 25.632 9.713 25.992 ;
     RECT  9.644 33.216 9.731 33.576 ;
     RECT  9.673 35.712 9.731 36.504 ;
     RECT  9.097 27.072 9.733 27.768 ;
     RECT  8.489 47.28 9.749 47.88 ;
     RECT  9.733 27.072 9.779 28.152 ;
     RECT  9.133 30.384 9.925 31.368 ;
     RECT  9.641 18.144 10.001 19.224 ;
     RECT  9.877 86.256 10.073 86.28 ;
     RECT  9.029 21.12 10.213 21.144 ;
     RECT  10.177 17.616 10.249 17.64 ;
     RECT  9.925 30 10.249 31.368 ;
     RECT  9.731 36.48 10.259 36.504 ;
     RECT  10.249 17.568 10.261 17.64 ;
     RECT  10.213 35.088 10.277 35.112 ;
     RECT  10.213 21.024 10.285 21.144 ;
     RECT  9.731 33.552 10.355 33.576 ;
     RECT  10.277 34.8 10.361 35.112 ;
     RECT  9.817 16.272 10.501 16.296 ;
     RECT  10.361 35.088 10.547 35.112 ;
     RECT  10.501 84.912 10.585 84.936 ;
     RECT  10.249 30 10.645 31.848 ;
     RECT  10.645 29.52 10.717 31.848 ;
     RECT  9.497 3.408 10.753 6.168 ;
     RECT  8.104 23.376 10.753 23.4 ;
     RECT  9.713 25.968 10.753 25.992 ;
     RECT  9.779 27.648 10.825 28.152 ;
     RECT  10.501 15.408 10.837 16.296 ;
     RECT  10.261 17.568 10.865 17.592 ;
     RECT  10.717 29.472 10.865 31.848 ;
     RECT  9.097 80.352 10.865 83.112 ;
     RECT  10.837 15.072 10.883 16.296 ;
     RECT  10.865 29.472 10.883 31.8 ;
     RECT  10.825 27.648 10.973 28.248 ;
     RECT  10.753 2.976 11.189 6.168 ;
     RECT  10.883 15.072 11.189 15.096 ;
     RECT  10.753 25.68 11.189 26.232 ;
     RECT  10.001 18.96 11.221 19.224 ;
     RECT  11.077 86.256 11.297 86.28 ;
     RECT  10.973 27.84 11.324 28.248 ;
     RECT  10.883 29.472 11.324 29.544 ;
     RECT  11.324 27.84 11.411 29.544 ;
     RECT  10.285 21.024 11.44 21.672 ;
     RECT  11.221 18.672 11.461 19.224 ;
     RECT  11.44 20.976 11.477 21.672 ;
     RECT  11.461 18.672 11.507 19.8 ;
     RECT  10.753 23.376 11.513 23.976 ;
     RECT  11.507 19.776 11.549 19.8 ;
     RECT  11.189 26.208 11.869 26.232 ;
     RECT  11.701 85.488 11.909 85.512 ;
     RECT  11.513 23.952 12.017 23.976 ;
     RECT  10.883 16.272 12.053 16.296 ;
     RECT  11.411 29.52 12.053 29.544 ;
     RECT  11.869 26.208 12.083 26.76 ;
     RECT  12.157 84.384 12.323 84.408 ;
     RECT  11.833 46.848 12.553 46.872 ;
     RECT  11.411 27.84 12.733 28.248 ;
     RECT  12.409 14.016 12.757 14.04 ;
     RECT  11.477 20.976 12.985 21 ;
     RECT  12.733 27.312 12.985 28.248 ;
     RECT  11.189 3.552 13.093 6.168 ;
     RECT  12.877 18.768 13.093 18.792 ;
     RECT  8.273 0.096 13.132 0.12 ;
     RECT  13.093 3.408 13.208 6.168 ;
     RECT  12.757 13.584 13.208 14.04 ;
     RECT  12.719 15.984 13.208 16.008 ;
     RECT  12.517 17.088 13.208 17.112 ;
     RECT  13.093 18.768 13.208 19.368 ;
     RECT  12.985 20.544 13.208 21 ;
     RECT  12.833 23.328 13.208 23.352 ;
     RECT  12.853 24.624 13.208 24.648 ;
     RECT  12.083 26.208 13.208 26.232 ;
     RECT  12.985 27.312 13.208 28.968 ;
     RECT  10.883 30.576 13.208 31.8 ;
     RECT  8.104 43.056 13.208 43.08 ;
     RECT  12.553 46.128 13.208 46.872 ;
     RECT  9.749 47.856 13.208 47.88 ;
     RECT  10.865 80.352 13.208 83.064 ;
     RECT  13.208 2.148 13.312 84.252 ;
     RECT  13.132 0.096 13.385 0.168 ;
     RECT  13.312 2.418 13.504 83.982 ;
     RECT  13.504 15.984 13.565 16.008 ;
     RECT  13.504 30.816 13.781 31.8 ;
     RECT  13.781 30.816 13.804 31.656 ;
     RECT  13.504 27.936 14.003 29.208 ;
     RECT  13.504 13.104 14.195 13.8 ;
     RECT  13.504 18.768 14.213 18.792 ;
     RECT  13.504 22.752 14.321 22.776 ;
     RECT  13.504 80.352 14.501 83.496 ;
     RECT  13.504 20.976 14.533 21.336 ;
     RECT  14.533 20.976 14.579 21.96 ;
     RECT  13.504 46.848 14.636 46.872 ;
     RECT  14.636 46.128 14.677 46.872 ;
     RECT  13.504 47.856 14.677 47.88 ;
     RECT  14.677 46.128 14.723 47.88 ;
     RECT  13.504 17.088 14.732 17.112 ;
     RECT  14.732 16.512 14.819 17.112 ;
     RECT  13.504 24.624 14.821 24.648 ;
     RECT  14.821 25.68 14.831 25.704 ;
     RECT  13.504 3.408 14.857 6.168 ;
     RECT  14.821 23.856 14.867 24.648 ;
     RECT  14.579 21.312 14.915 21.96 ;
     RECT  14.195 13.104 14.917 13.128 ;
     RECT  14.831 25.68 14.969 25.896 ;
     RECT  14.819 17.088 15.001 17.112 ;
     RECT  14.867 23.856 15.145 23.976 ;
     RECT  14.723 46.128 15.217 46.2 ;
     RECT  15.001 17.088 15.253 18.072 ;
     RECT  14.497 19.776 15.253 19.8 ;
     RECT  15.253 17.088 15.299 19.8 ;
     RECT  15.181 84.384 15.347 84.408 ;
     RECT  14.917 12.528 15.349 13.128 ;
     RECT  15.037 14.256 15.349 14.28 ;
     RECT  14.969 25.872 15.349 25.896 ;
     RECT  14.713 29.76 15.349 29.784 ;
     RECT  13.804 30.816 15.349 30.888 ;
     RECT  15.349 12.528 15.395 14.28 ;
     RECT  15.349 25.872 15.395 26.28 ;
     RECT  15.349 29.76 15.395 30.888 ;
     RECT  15.299 18.768 15.401 19.8 ;
     RECT  15.395 29.76 15.401 30.264 ;
     RECT  14.501 80.352 15.473 83.208 ;
     RECT  15.299 17.472 15.617 17.496 ;
     RECT  14.003 27.936 15.637 28.44 ;
     RECT  15.217 45.744 15.653 46.2 ;
     RECT  15.637 27.312 15.724 28.44 ;
     RECT  14.915 21.936 15.793 21.96 ;
     RECT  15.145 23.328 15.829 23.976 ;
     RECT  15.395 12.528 15.833 13.608 ;
     RECT  15.829 23.328 15.869 24.552 ;
     RECT  14.857 3.312 15.901 6.168 ;
     RECT  15.401 19.776 15.941 19.8 ;
     RECT  15.401 18.768 16.085 18.792 ;
     RECT  12.901 86.256 16.085 86.28 ;
     RECT  14.723 47.28 16.121 47.88 ;
     RECT  15.869 23.328 16.265 23.352 ;
     RECT  15.724 28.224 16.301 28.44 ;
     RECT  15.901 2.976 16.373 6.168 ;
     RECT  16.477 84.336 16.561 84.36 ;
     RECT  15.473 80.352 16.765 83.112 ;
     RECT  15.869 24.528 16.841 24.552 ;
     RECT  15.395 26.112 17.053 26.28 ;
     RECT  16.301 28.224 17.053 28.248 ;
     RECT  17.077 19.344 17.164 19.368 ;
     RECT  17.077 84.912 17.165 84.936 ;
     RECT  15.793 21.936 17.228 22.2 ;
     RECT  17.053 27.312 17.237 28.248 ;
     RECT  17.228 21.936 17.315 22.968 ;
     RECT  15.653 46.176 17.377 46.2 ;
     RECT  17.377 46.176 17.381 46.776 ;
     RECT  16.189 20.496 17.521 20.52 ;
     RECT  17.521 20.496 17.561 20.616 ;
     RECT  17.315 21.936 17.597 22.2 ;
     RECT  15.685 14.784 17.605 14.808 ;
     RECT  16.373 3.312 17.629 6.168 ;
     RECT  16.765 80.352 17.653 83.304 ;
     RECT  15.401 30.24 17.66 30.264 ;
     RECT  17.605 14.784 17.701 15.288 ;
     RECT  17.561 20.592 17.701 20.616 ;
     RECT  17.597 21.936 17.701 21.96 ;
     RECT  17.237 28.224 17.701 28.248 ;
     RECT  17.66 29.424 17.701 30.264 ;
     RECT  13.385 0.096 17.852 0.12 ;
     RECT  17.701 86.256 17.885 86.28 ;
     RECT  15.833 13.584 17.917 13.608 ;
     RECT  17.701 14.784 17.917 15.96 ;
     RECT  17.852 0.096 17.939 0.552 ;
     RECT  17.653 80.064 17.953 83.304 ;
     RECT  15.833 12.528 18.133 12.552 ;
     RECT  17.917 13.584 18.133 15.96 ;
     RECT  17.845 23.376 18.181 23.4 ;
     RECT  18.277 85.488 18.533 85.512 ;
     RECT  17.629 2.976 18.608 6.168 ;
     RECT  18.133 11.952 18.608 15.96 ;
     RECT  17.053 16.944 18.608 16.968 ;
     RECT  17.701 20.592 18.608 21.96 ;
     RECT  18.181 23.376 18.608 23.928 ;
     RECT  17.053 25.584 18.608 26.28 ;
     RECT  17.701 28.224 18.608 30.264 ;
     RECT  13.504 43.056 18.608 43.08 ;
     RECT  17.381 46.752 18.608 46.776 ;
     RECT  16.121 47.856 18.608 47.88 ;
     RECT  17.953 80.064 18.608 83.352 ;
     RECT  18.608 2.148 18.901 84.252 ;
     RECT  18.901 2.148 18.904 84.936 ;
     RECT  18.904 28.224 18.965 28.488 ;
     RECT  18.904 84.912 19.073 84.936 ;
     RECT  18.904 18.768 19.117 19.368 ;
     RECT  18.904 24.48 19.181 26.28 ;
     RECT  19.177 1.728 19.261 1.752 ;
     RECT  18.965 28.224 19.379 28.248 ;
     RECT  18.904 15.216 19.433 16.248 ;
     RECT  18.904 45.696 19.433 45.96 ;
     RECT  18.904 3.312 19.505 6.168 ;
     RECT  18.904 20.4 19.541 23.016 ;
     RECT  18.904 10.752 19.757 10.776 ;
     RECT  19.541 21.12 19.763 23.016 ;
     RECT  19.763 21.12 19.829 21.96 ;
     RECT  18.904 47.856 19.957 47.88 ;
     RECT  19.181 26.256 19.969 26.28 ;
     RECT  19.957 47.04 20.081 47.88 ;
     RECT  19.477 86.256 20.101 86.28 ;
     RECT  20.101 86.208 20.117 86.28 ;
     RECT  19.117 18.768 20.149 18.792 ;
     RECT  18.904 11.952 20.153 11.976 ;
     RECT  18.904 13.296 20.189 13.32 ;
     RECT  19.433 15.264 20.195 16.248 ;
     RECT  19.829 21.648 20.195 21.96 ;
     RECT  20.149 18.768 20.233 18.84 ;
     RECT  19.763 22.992 20.261 23.016 ;
     RECT  20.117 86.208 20.333 86.232 ;
     RECT  19.181 24.48 20.401 25.176 ;
     RECT  17.939 0.096 20.444 0.12 ;
     RECT  20.444 0.096 20.531 0.552 ;
     RECT  20.233 18.768 20.653 18.792 ;
     RECT  20.149 19.968 20.761 19.992 ;
     RECT  20.401 23.904 21.017 25.176 ;
     RECT  19.505 3.36 21.049 6.168 ;
     RECT  20.195 21.936 21.161 21.96 ;
     RECT  20.761 19.968 21.193 20.568 ;
     RECT  20.329 10.32 21.265 10.344 ;
     RECT  19.969 26.256 21.337 26.808 ;
     RECT  21.337 26.208 21.377 26.808 ;
     RECT  20.195 15.36 21.413 16.248 ;
     RECT  21.193 19.968 21.485 21.672 ;
     RECT  21.404 8.496 21.491 8.52 ;
     RECT  21.413 15.36 21.491 15.384 ;
     RECT  21.485 19.968 21.491 19.992 ;
     RECT  21.265 9.744 21.517 10.344 ;
     RECT  21.049 3.168 21.589 6.168 ;
     RECT  21.517 76.896 21.601 76.92 ;
     RECT  21.017 25.056 21.637 25.176 ;
     RECT  21.377 26.208 21.637 26.28 ;
     RECT  21.637 25.056 21.683 26.28 ;
     RECT  21.625 8.448 21.733 8.472 ;
     RECT  21.517 9.744 21.733 11.4 ;
     RECT  20.653 18.144 21.773 18.792 ;
     RECT  21.733 8.4 21.82 8.472 ;
     RECT  21.733 9.504 21.917 11.4 ;
     RECT  21.683 25.152 21.917 26.28 ;
     RECT  20.293 14.208 21.925 14.232 ;
     RECT  21.836 22.752 21.949 22.776 ;
     RECT  21.017 23.904 21.949 23.928 ;
     RECT  21.917 10.176 21.953 11.4 ;
     RECT  21.485 21.12 21.953 21.672 ;
     RECT  21.301 86.256 21.953 86.28 ;
     RECT  21.949 22.752 21.989 23.928 ;
     RECT  21.925 13.584 22.012 14.232 ;
     RECT  21.953 21.12 22.097 21.144 ;
     RECT  22.012 14.208 22.165 14.232 ;
     RECT  21.781 1.728 22.205 1.752 ;
     RECT  22.165 14.208 22.211 14.856 ;
     RECT  22.211 14.832 22.277 14.856 ;
     RECT  21.989 22.752 22.421 23.352 ;
     RECT  22.021 18.816 22.457 18.84 ;
     RECT  22.421 22.752 22.637 22.776 ;
     RECT  21.917 26.256 22.637 26.28 ;
     RECT  21.82 8.448 22.741 8.472 ;
     RECT  21.953 10.176 22.745 10.2 ;
     RECT  22.705 12.48 22.777 12.504 ;
     RECT  20.677 84.384 22.781 84.408 ;
     RECT  21.953 11.376 22.817 11.4 ;
     RECT  21.917 25.152 22.853 25.272 ;
     RECT  18.904 79.968 22.885 79.992 ;
     RECT  18.904 81.168 22.885 83.352 ;
     RECT  20.531 0.096 22.889 0.12 ;
     RECT  23.029 0.528 23.123 0.552 ;
     RECT  23.077 84.912 23.285 84.936 ;
     RECT  22.777 12.48 23.569 12.552 ;
     RECT  18.904 30.432 23.569 30.456 ;
     RECT  23.569 11.664 23.633 12.552 ;
     RECT  23.633 11.664 23.677 13.128 ;
     RECT  23.137 21.648 23.677 21.672 ;
     RECT  23.509 1.728 23.717 1.752 ;
     RECT  23.669 85.488 23.753 85.512 ;
     RECT  22.741 8.448 23.852 9.096 ;
     RECT  23.677 11.664 23.893 13.656 ;
     RECT  21.625 75.408 23.929 75.432 ;
     RECT  21.589 3.12 24.008 6.168 ;
     RECT  23.852 8.448 24.008 9.672 ;
     RECT  23.893 10.704 24.008 13.656 ;
     RECT  23.317 14.736 24.008 14.76 ;
     RECT  23.353 16.08 24.008 16.104 ;
     RECT  23.276 19.152 24.008 19.176 ;
     RECT  22.813 20.4 24.008 20.424 ;
     RECT  23.677 21.648 24.008 22.056 ;
     RECT  23.893 23.664 24.008 23.688 ;
     RECT  22.853 25.248 24.008 25.272 ;
     RECT  23.569 30.432 24.008 30.648 ;
     RECT  18.904 43.056 24.008 43.08 ;
     RECT  19.433 45.936 24.008 45.96 ;
     RECT  20.081 47.856 24.008 47.88 ;
     RECT  23.929 75.408 24.008 75.816 ;
     RECT  22.885 79.968 24.008 83.352 ;
     RECT  24.008 2.148 24.112 84.252 ;
     RECT  24.112 2.418 24.277 84.252 ;
     RECT  24.277 2.418 24.304 84.408 ;
     RECT  24.304 84.384 24.365 84.408 ;
     RECT  23.941 0.096 24.373 0.12 ;
     RECT  24.304 16.08 24.401 16.104 ;
     RECT  24.304 45.936 24.419 46.392 ;
     RECT  24.304 47.856 24.419 47.88 ;
     RECT  24.304 10.8 24.473 11.688 ;
     RECT  24.304 18 24.545 23.688 ;
     RECT  24.545 22.752 24.563 23.688 ;
     RECT  24.563 22.752 24.589 23.544 ;
     RECT  24.373 0.096 24.725 0.552 ;
     RECT  24.473 10.8 24.725 10.824 ;
     RECT  24.304 79.92 24.851 83.352 ;
     RECT  24.589 23.52 25.013 23.544 ;
     RECT  24.419 45.936 25.091 46.2 ;
     RECT  24.304 75.792 25.121 76.344 ;
     RECT  24.304 8.448 25.297 9.096 ;
     RECT  24.545 18 25.373 21.144 ;
     RECT  25.297 8.448 25.379 9.144 ;
     RECT  25.379 9.072 25.381 9.144 ;
     RECT  25.381 9.072 25.445 9.096 ;
     RECT  24.901 84.912 25.561 84.936 ;
     RECT  25.513 11.952 25.597 11.976 ;
     RECT  24.304 25.248 25.621 25.272 ;
     RECT  25.373 18 25.669 19.8 ;
     RECT  25.621 22.8 25.705 22.824 ;
     RECT  25.669 16.416 25.756 16.44 ;
     RECT  24.304 3.12 25.801 7.416 ;
     RECT  24.304 14.256 25.877 15.096 ;
     RECT  25.801 2.88 25.909 7.416 ;
     RECT  24.851 79.968 25.945 83.352 ;
     RECT  25.909 2.88 25.985 7.464 ;
     RECT  25.669 17.616 25.985 19.8 ;
     RECT  25.621 24.336 26.017 25.272 ;
     RECT  25.945 79.968 26.081 83.544 ;
     RECT  26.081 79.968 26.165 84.36 ;
     RECT  25.985 3.12 26.195 7.464 ;
     RECT  25.121 76.32 26.204 76.344 ;
     RECT  26.204 76.32 26.291 76.968 ;
     RECT  25.985 19.776 26.341 19.8 ;
     RECT  25.373 21.12 26.341 21.144 ;
     RECT  25.985 17.616 26.345 18.072 ;
     RECT  26.341 19.776 26.381 21.144 ;
     RECT  26.195 3.12 26.525 6.84 ;
     RECT  26.665 84.912 26.749 84.936 ;
     RECT  25.909 12.192 26.849 12.216 ;
     RECT  26.345 18.048 26.885 18.072 ;
     RECT  25.877 14.64 26.957 15.096 ;
     RECT  26.945 1.728 27.029 1.752 ;
     RECT  26.291 76.32 27.097 76.344 ;
     RECT  26.017 24.336 27.101 25.704 ;
     RECT  27.097 75.792 27.137 76.344 ;
     RECT  26.381 19.776 27.209 20.376 ;
     RECT  26.525 3.12 27.313 6.744 ;
     RECT  26.269 10.224 27.317 10.248 ;
     RECT  27.101 24.336 27.389 25.176 ;
     RECT  26.165 79.968 27.497 83.592 ;
     RECT  27.301 86.256 27.497 86.28 ;
     RECT  26.957 15.072 27.529 15.096 ;
     RECT  26.557 16.128 27.529 16.152 ;
     RECT  27.529 15.072 27.569 16.152 ;
     RECT  27.733 17.568 27.82 17.688 ;
     RECT  26.161 13.44 27.857 13.464 ;
     RECT  27.845 84.912 27.929 84.936 ;
     RECT  27.313 3.072 28.073 6.744 ;
     RECT  28.073 3.072 28.109 5.784 ;
     RECT  27.889 12 28.145 12.552 ;
     RECT  28.109 3.168 28.217 5.784 ;
     RECT  27.673 9.072 28.325 9.096 ;
     RECT  28.46 85.488 28.547 85.512 ;
     RECT  27.389 25.152 28.693 25.176 ;
     RECT  27.82 17.664 28.789 17.688 ;
     RECT  28.693 1.728 28.829 1.752 ;
     RECT  28.693 25.152 28.94 25.752 ;
     RECT  28.789 17.664 29.029 18.312 ;
     RECT  27.497 81.072 29.041 83.592 ;
     RECT  28.429 7.968 29.077 7.992 ;
     RECT  27.569 15.072 29.077 16.008 ;
     RECT  29.029 17.472 29.077 18.312 ;
     RECT  27.997 69.552 29.084 69.576 ;
     RECT  27.497 79.968 29.125 79.992 ;
     RECT  29.041 81.072 29.125 83.64 ;
     RECT  29.077 86.256 29.297 86.28 ;
     RECT  28.217 3.264 29.408 5.784 ;
     RECT  29.077 7.968 29.408 8.472 ;
     RECT  29.113 10.416 29.408 10.44 ;
     RECT  28.145 12.528 29.408 12.552 ;
     RECT  29.077 14.256 29.408 18.312 ;
     RECT  27.209 19.776 29.408 20.328 ;
     RECT  27.457 21.648 29.408 21.672 ;
     RECT  28.537 22.8 29.408 22.824 ;
     RECT  28.94 25.152 29.408 26.52 ;
     RECT  24.304 30.624 29.408 30.648 ;
     RECT  24.304 43.056 29.408 43.608 ;
     RECT  24.304 51.36 29.408 51.384 ;
     RECT  29.125 66.48 29.408 66.504 ;
     RECT  29.084 69.552 29.408 69.96 ;
     RECT  27.137 75.792 29.408 75.816 ;
     RECT  29.125 79.968 29.408 83.64 ;
     RECT  29.408 2.148 29.512 84.252 ;
     RECT  29.512 2.418 29.704 83.982 ;
     RECT  29.704 20.304 29.765 20.328 ;
     RECT  29.701 85.488 29.873 85.512 ;
     RECT  29.704 69.552 29.909 69.576 ;
     RECT  29.704 14.688 30.017 15.192 ;
     RECT  29.704 16.656 30.089 17.496 ;
     RECT  29.704 7.776 30.227 10.536 ;
     RECT  29.704 25.728 30.275 26.808 ;
     RECT  30.227 8.448 30.412 10.536 ;
     RECT  30.412 8.448 30.556 9 ;
     RECT  30.089 16.944 30.556 17.496 ;
     RECT  29.704 11.952 30.629 13.272 ;
     RECT  30.629 12.48 30.707 13.272 ;
     RECT  30.697 18.864 30.757 18.984 ;
     RECT  29.704 23.952 30.769 23.976 ;
     RECT  30.757 18.768 30.803 18.984 ;
     RECT  30.769 23.952 30.809 24.504 ;
     RECT  30.803 18.768 30.845 18.888 ;
     RECT  30.017 14.832 30.881 15.192 ;
     RECT  29.704 3.408 31.093 6.264 ;
     RECT  29.704 76.848 31.093 76.872 ;
     RECT  30.277 86.256 31.097 86.28 ;
     RECT  30.556 8.496 31.133 9 ;
     RECT  31.093 75.984 31.139 76.872 ;
     RECT  31.093 3.408 31.277 6.504 ;
     RECT  30.881 15.168 31.309 15.192 ;
     RECT  29.704 80.784 31.457 83.736 ;
     RECT  31.345 85.488 31.523 85.512 ;
     RECT  30.809 24.48 31.525 24.504 ;
     RECT  30.275 25.728 31.525 26.568 ;
     RECT  30.412 10.32 31.561 10.536 ;
     RECT  31.525 24.48 31.561 26.568 ;
     RECT  31.561 24.48 31.619 26.808 ;
     RECT  31.133 8.496 31.633 8.52 ;
     RECT  30.707 12.48 31.637 12.552 ;
     RECT  31.619 25.728 31.645 26.808 ;
     RECT  30.556 17.472 31.849 17.496 ;
     RECT  31.633 7.584 31.853 8.52 ;
     RECT  31.849 17.472 31.889 17.64 ;
     RECT  30.845 18.768 31.889 18.792 ;
     RECT  31.277 3.408 31.921 5.784 ;
     RECT  31.309 15.168 32.033 15.96 ;
     RECT  32.029 13.824 32.348 13.848 ;
     RECT  31.561 9.504 32.361 10.536 ;
     RECT  31.619 24.48 32.393 24.504 ;
     RECT  32.361 9.12 32.435 10.536 ;
     RECT  32.033 15.168 32.435 15.192 ;
     RECT  31.921 2.88 32.485 5.784 ;
     RECT  31.853 7.584 32.485 7.608 ;
     RECT  32.348 13.776 32.485 13.848 ;
     RECT  32.485 2.88 32.573 7.608 ;
     RECT  32.485 13.104 32.609 13.848 ;
     RECT  31.645 25.728 32.825 26.568 ;
     RECT  32.435 10.32 32.897 10.536 ;
     RECT  32.101 86.256 32.897 86.28 ;
     RECT  31.697 1.728 32.969 1.752 ;
     RECT  29.704 58.896 33.001 58.92 ;
     RECT  32.573 7.008 33.005 7.608 ;
     RECT  31.889 17.616 33.005 17.64 ;
     RECT  32.209 11.952 33.013 11.976 ;
     RECT  33.013 11.328 33.1 11.976 ;
     RECT  31.457 80.784 33.26 83.448 ;
     RECT  33.001 58.896 33.365 59.016 ;
     RECT  32.573 2.88 33.401 5.832 ;
     RECT  32.609 13.824 33.548 13.848 ;
     RECT  32.821 14.832 33.548 14.856 ;
     RECT  33.548 13.824 33.589 14.856 ;
     RECT  33.589 13.824 33.635 15.336 ;
     RECT  33.401 3.552 33.637 5.832 ;
     RECT  33.005 7.008 33.637 7.032 ;
     RECT  33.637 3.552 33.653 7.032 ;
     RECT  32.897 10.32 33.689 10.344 ;
     RECT  33.445 2.16 33.725 2.184 ;
     RECT  32.435 9.12 33.793 9.144 ;
     RECT  31.139 75.984 33.829 76.008 ;
     RECT  33.26 80.784 33.923 84.408 ;
     RECT  32.825 26.544 34.081 26.568 ;
     RECT  33.037 27.6 34.081 27.624 ;
     RECT  33.653 3.696 34.213 7.032 ;
     RECT  33.793 8.928 34.213 9.144 ;
     RECT  33.635 13.824 34.333 13.848 ;
     RECT  24.725 0.096 34.741 0.12 ;
     RECT  34.213 3.696 34.808 9.144 ;
     RECT  33.1 11.952 34.808 11.976 ;
     RECT  34.333 13.056 34.808 13.848 ;
     RECT  33.635 15.312 34.808 15.336 ;
     RECT  33.589 16.8 34.808 16.824 ;
     RECT  33.433 24.912 34.808 24.936 ;
     RECT  34.081 26.544 34.808 27.624 ;
     RECT  29.704 30.624 34.808 30.648 ;
     RECT  29.704 43.056 34.808 43.608 ;
     RECT  29.704 51.36 34.808 51.384 ;
     RECT  33.365 58.992 34.808 59.016 ;
     RECT  29.704 66.48 34.808 66.504 ;
     RECT  34.153 71.088 34.808 71.112 ;
     RECT  33.829 75.984 34.808 76.968 ;
     RECT  33.923 80.784 34.808 84.252 ;
     RECT  34.808 2.148 34.912 84.252 ;
     RECT  34.912 2.418 35.104 84.252 ;
     RECT  35.104 3.696 35.165 6.312 ;
     RECT  34.741 0.096 35.201 0.552 ;
     RECT  34.501 86.256 35.273 86.28 ;
     RECT  35.165 3.696 35.363 5.832 ;
     RECT  35.104 7.344 35.363 8.568 ;
     RECT  35.363 7.344 35.561 7.992 ;
     RECT  35.104 11.952 35.603 15.672 ;
     RECT  35.593 84.384 35.747 84.408 ;
     RECT  35.603 11.952 36.035 14.904 ;
     RECT  35.104 24.528 36.097 24.936 ;
     RECT  36.097 24.528 36.137 25.08 ;
     RECT  35.561 7.968 36.373 7.992 ;
     RECT  35.104 9.696 36.373 9.72 ;
     RECT  35.363 3.696 36.421 5.784 ;
     RECT  36.373 7.968 36.425 9.72 ;
     RECT  36.425 7.968 36.46 9.192 ;
     RECT  36.035 11.952 36.497 11.976 ;
     RECT  36.313 78.048 36.565 78.072 ;
     RECT  36.421 3.408 36.601 5.784 ;
     RECT  36.035 13.68 36.605 14.904 ;
     RECT  35.104 70.944 36.611 71.112 ;
     RECT  35.104 80.784 36.62 83.352 ;
     RECT  35.104 26.832 36.637 27.336 ;
     RECT  36.62 80.688 36.668 83.352 ;
     RECT  36.565 77.904 36.707 78.072 ;
     RECT  36.668 80.448 36.709 83.352 ;
     RECT  36.889 1.728 36.973 1.752 ;
     RECT  36.46 7.968 37.001 8.856 ;
     RECT  36.137 25.056 37.033 25.08 ;
     RECT  36.637 26.208 37.033 27.336 ;
     RECT  37.033 25.056 37.091 27.336 ;
     RECT  37.091 25.056 37.117 25.992 ;
     RECT  37.091 27.312 37.217 27.336 ;
     RECT  36.277 86.256 37.477 86.28 ;
     RECT  36.707 77.904 37.609 77.928 ;
     RECT  36.605 13.68 37.649 14.376 ;
     RECT  37.609 77.52 37.649 77.928 ;
     RECT  37.477 86.016 37.685 86.28 ;
     RECT  37.001 7.968 37.793 7.992 ;
     RECT  36.601 3.312 37.865 5.784 ;
     RECT  37.117 25.056 37.973 25.896 ;
     RECT  36.611 71.088 38.329 71.112 ;
     RECT  38.3 27.216 38.341 27.24 ;
     RECT  36.661 34.896 38.341 34.92 ;
     RECT  38.341 27.072 38.387 27.24 ;
     RECT  38.341 34.224 38.473 34.92 ;
     RECT  38.149 35.904 38.473 35.928 ;
     RECT  38.473 34.224 38.513 35.928 ;
     RECT  38.329 71.088 38.645 71.352 ;
     RECT  37.973 25.872 38.684 25.896 ;
     RECT  38.387 27.072 38.684 27.096 ;
     RECT  38.609 1.728 38.693 1.752 ;
     RECT  38.513 34.752 38.693 35.208 ;
     RECT  37.865 3.504 38.725 5.784 ;
     RECT  38.617 7.008 38.725 7.032 ;
     RECT  38.645 70.656 38.729 71.352 ;
     RECT  35.104 58.896 38.761 58.92 ;
     RECT  38.725 3.504 38.771 7.032 ;
     RECT  38.761 58.896 38.801 59.016 ;
     RECT  36.709 79.968 38.801 83.352 ;
     RECT  38.771 3.504 38.833 6.264 ;
     RECT  38.684 25.872 38.857 27.096 ;
     RECT  35.104 43.056 39.229 43.608 ;
     RECT  38.833 3.408 39.301 6.264 ;
     RECT  37.685 86.256 39.377 86.28 ;
     RECT  35.104 30.624 39.589 30.648 ;
     RECT  37.649 77.52 39.841 77.544 ;
     RECT  38.761 12.528 39.877 12.552 ;
     RECT  36.925 10.608 39.913 10.632 ;
     RECT  39.877 11.808 39.913 12.552 ;
     RECT  39.841 77.52 39.925 78.072 ;
     RECT  39.869 84.912 39.953 84.936 ;
     RECT  38.801 79.968 39.985 83.304 ;
     RECT  35.201 0.096 40.133 0.12 ;
     RECT  39.301 3.12 40.208 6.264 ;
     RECT  39.913 10.608 40.208 12.552 ;
     RECT  37.649 13.68 40.208 13.848 ;
     RECT  39.661 22.176 40.208 22.2 ;
     RECT  38.857 26.832 40.208 27.096 ;
     RECT  38.725 28.944 40.208 28.968 ;
     RECT  39.589 30.24 40.208 30.648 ;
     RECT  38.693 34.896 40.208 35.208 ;
     RECT  39.949 36.528 40.208 36.552 ;
     RECT  39.229 43.056 40.208 43.896 ;
     RECT  35.104 51.36 40.208 51.384 ;
     RECT  39.157 53.568 40.208 53.592 ;
     RECT  38.905 55.968 40.208 55.992 ;
     RECT  38.801 58.992 40.208 59.016 ;
     RECT  35.104 66.48 40.208 66.504 ;
     RECT  38.729 71.328 40.208 71.352 ;
     RECT  39.925 77.52 40.208 78.696 ;
     RECT  39.985 79.776 40.208 83.304 ;
     RECT  40.208 2.148 40.312 84.252 ;
     RECT  40.312 2.148 40.337 83.982 ;
     RECT  40.337 1.728 40.421 83.982 ;
     RECT  40.421 2.418 40.504 83.982 ;
     RECT  40.504 79.776 40.601 83.352 ;
     RECT  40.504 70.8 40.739 70.824 ;
     RECT  40.504 66.672 40.745 66.696 ;
     RECT  40.504 53.568 40.787 53.592 ;
     RECT  40.741 0.528 40.835 0.552 ;
     RECT  40.504 34.752 41.027 35.448 ;
     RECT  40.504 54.576 41.027 57.144 ;
     RECT  40.504 36.528 41.069 37.032 ;
     RECT  41.027 55.008 41.141 57.144 ;
     RECT  40.501 85.488 41.149 85.512 ;
     RECT  40.504 12.768 41.267 13.848 ;
     RECT  40.504 21.648 41.293 21.672 ;
     RECT  40.504 43.056 41.321 43.896 ;
     RECT  40.504 10.704 41.357 10.728 ;
     RECT  40.601 79.776 41.501 83.304 ;
     RECT  41.501 80.16 41.507 83.304 ;
     RECT  40.504 25.968 41.645 26.856 ;
     RECT  40.504 3.408 41.891 6.168 ;
     RECT  41.507 80.928 41.929 83.304 ;
     RECT  41.701 84.912 42.181 84.936 ;
     RECT  42.085 1.728 42.185 1.752 ;
     RECT  42.181 84.912 42.323 85.512 ;
     RECT  41.141 57.12 42.437 57.144 ;
     RECT  41.141 55.008 42.509 55.992 ;
     RECT  41.069 37.008 42.577 37.032 ;
     RECT  42.577 37.008 42.617 37.656 ;
     RECT  41.845 9.12 42.653 9.144 ;
     RECT  41.321 43.056 42.764 43.32 ;
     RECT  42.541 44.352 42.764 44.376 ;
     RECT  40.504 72 42.833 72.024 ;
     RECT  42.764 43.056 42.851 44.376 ;
     RECT  42.617 37.632 43.049 37.656 ;
     RECT  42.851 43.056 43.193 43.32 ;
     RECT  40.504 58.992 43.441 59.016 ;
     RECT  43.193 43.296 43.523 43.32 ;
     RECT  43.441 58.128 43.523 59.016 ;
     RECT  43.477 86.016 43.733 86.04 ;
     RECT  41.027 34.896 43.805 35.448 ;
     RECT  41.891 3.408 43.837 5.784 ;
     RECT  43.805 34.896 43.955 35.352 ;
     RECT  40.504 51.36 43.955 51.384 ;
     RECT  43.837 2.976 44.057 5.784 ;
     RECT  43.909 53.04 44.129 53.064 ;
     RECT  42.509 55.968 44.245 55.992 ;
     RECT  44.245 55.968 44.332 56.424 ;
     RECT  44.245 71.808 44.332 71.832 ;
     RECT  44.348 53.664 44.435 53.688 ;
     RECT  44.332 55.968 44.435 55.992 ;
     RECT  44.305 37.056 44.561 37.896 ;
     RECT  43.693 8.256 44.773 8.28 ;
     RECT  42.323 84.912 44.849 84.936 ;
     RECT  44.161 72.912 44.953 72.936 ;
     RECT  44.561 37.872 45.385 37.896 ;
     RECT  45.301 85.488 45.497 85.512 ;
     RECT  44.057 3.12 45.608 5.784 ;
     RECT  44.773 7.968 45.608 8.28 ;
     RECT  41.267 12.768 45.608 13.704 ;
     RECT  41.645 25.968 45.608 25.992 ;
     RECT  43.621 27.6 45.608 27.624 ;
     RECT  40.504 28.944 45.608 28.968 ;
     RECT  43.955 35.328 45.608 35.352 ;
     RECT  45.565 36.336 45.608 36.36 ;
     RECT  45.385 37.872 45.608 38.808 ;
     RECT  42.851 44.352 45.608 44.376 ;
     RECT  43.523 58.128 45.608 58.152 ;
     RECT  43.477 60.096 45.608 60.12 ;
     RECT  44.953 72.912 45.608 73.368 ;
     RECT  41.929 80.928 45.608 83.352 ;
     RECT  45.608 2.148 45.712 84.252 ;
     RECT  45.712 2.418 45.904 83.982 ;
     RECT  41.221 0.096 45.964 0.12 ;
     RECT  45.904 3.12 46.189 6.312 ;
     RECT  45.904 12.768 46.217 13.08 ;
     RECT  45.964 0.096 46.364 0.168 ;
     RECT  45.904 27.312 46.403 27.336 ;
     RECT  45.904 36.336 46.403 36.792 ;
     RECT  45.904 44.352 46.433 44.424 ;
     RECT  46.364 0.096 46.451 0.552 ;
     RECT  45.904 37.872 46.721 37.896 ;
     RECT  45.904 58.512 46.828 58.536 ;
     RECT  45.904 73.344 47.125 73.512 ;
     RECT  47.125 72.816 47.212 73.512 ;
     RECT  45.904 56.88 47.333 56.904 ;
     RECT  47.681 84.336 47.765 84.36 ;
     RECT  46.433 44.4 47.891 44.424 ;
     RECT  46.403 36.768 47.945 36.792 ;
     RECT  46.189 3.12 48.157 6.264 ;
     RECT  46.451 0.096 48.565 0.168 ;
     RECT  48.157 3.072 48.629 6.264 ;
     RECT  48.629 3.072 48.665 5.256 ;
     RECT  48.629 6.24 48.803 6.264 ;
     RECT  48.565 0.096 48.809 0.216 ;
     RECT  48.665 3.072 48.881 5.208 ;
     RECT  48.881 3.072 49.069 5.16 ;
     RECT  49.069 3.072 49.133 5.064 ;
     RECT  49.133 3.12 49.385 5.064 ;
     RECT  49.385 3.12 49.421 4.776 ;
     RECT  45.877 86.256 49.456 86.28 ;
     RECT  45.904 80.928 49.601 83.352 ;
     RECT  49.561 72.24 49.633 72.264 ;
     RECT  49.456 86.208 49.709 86.28 ;
     RECT  48.809 0.096 50.293 0.168 ;
     RECT  50.293 0.096 50.789 0.264 ;
     RECT  47.212 73.488 50.869 73.512 ;
     RECT  49.421 3.648 51.008 4.776 ;
     RECT  45.904 25.968 51.008 25.992 ;
     RECT  45.904 28.944 51.008 28.968 ;
     RECT  50.245 37.392 51.008 37.416 ;
     RECT  47.845 43.296 51.008 43.32 ;
     RECT  45.904 60.096 51.008 60.12 ;
     RECT  49.633 71.424 51.008 72.264 ;
     RECT  50.869 73.344 51.008 73.512 ;
     RECT  49.601 80.928 51.008 83.304 ;
     RECT  51.008 2.148 51.112 84.252 ;
     RECT  51.112 2.418 51.304 83.982 ;
     RECT  50.789 0.096 51.401 0.168 ;
     RECT  51.304 43.248 51.491 43.272 ;
     RECT  51.304 37.392 51.509 37.416 ;
     RECT  51.304 40.56 51.827 40.776 ;
     RECT  51.304 38.736 51.833 38.76 ;
     RECT  51.304 73.344 52.121 73.512 ;
     RECT  51.401 0.096 52.453 0.12 ;
     RECT  52.453 0.096 52.553 0.552 ;
     RECT  51.304 3.648 52.981 4.776 ;
     RECT  49.709 86.256 53.273 86.28 ;
     RECT  52.981 3.408 53.669 4.776 ;
     RECT  52.121 73.488 53.809 73.512 ;
     RECT  53.701 85.488 54.029 85.512 ;
     RECT  52.909 37.632 54.529 37.656 ;
     RECT  52.553 0.096 54.604 0.12 ;
     RECT  54.529 37.008 54.613 37.656 ;
     RECT  54.241 39.072 54.661 39.096 ;
     RECT  51.827 40.56 54.661 40.584 ;
     RECT  51.304 80.928 54.677 83.304 ;
     RECT  53.669 3.552 54.709 4.776 ;
     RECT  54.613 37.632 54.709 37.656 ;
     RECT  53.809 73.392 54.709 73.512 ;
     RECT  54.661 39.072 54.713 40.584 ;
     RECT  54.604 0.096 54.749 0.168 ;
     RECT  54.709 37.632 54.749 37.752 ;
     RECT  54.709 73.344 54.781 73.512 ;
     RECT  52.765 43.296 55.388 43.32 ;
     RECT  54.749 0.096 55.685 0.12 ;
     RECT  55.889 1.728 55.973 1.752 ;
     RECT  54.277 84.912 56.153 84.936 ;
     RECT  54.749 37.728 56.293 37.752 ;
     RECT  54.709 3.408 56.408 4.776 ;
     RECT  51.304 25.968 56.408 25.992 ;
     RECT  51.304 28.944 56.408 28.968 ;
     RECT  56.293 37.584 56.408 37.752 ;
     RECT  56.293 38.784 56.408 38.808 ;
     RECT  54.713 40.032 56.408 40.584 ;
     RECT  55.388 43.248 56.408 43.32 ;
     RECT  55.429 44.352 56.408 44.376 ;
     RECT  51.304 60.096 56.408 60.12 ;
     RECT  51.304 71.328 56.408 71.352 ;
     RECT  54.781 73.344 56.408 74.136 ;
     RECT  54.677 80.928 56.408 83.064 ;
     RECT  56.408 2.148 56.512 84.252 ;
     RECT  56.341 0.528 56.585 0.552 ;
     RECT  56.512 2.418 56.704 83.982 ;
     RECT  56.704 37.584 56.981 37.608 ;
     RECT  56.677 86.256 57.521 86.28 ;
     RECT  57.841 84.912 57.925 84.936 ;
     RECT  56.704 40.032 57.973 40.584 ;
     RECT  57.973 39.264 58.019 40.824 ;
     RECT  58.019 40.56 58.06 40.824 ;
     RECT  58.019 39.264 58.061 39.288 ;
     RECT  56.773 0.096 58.069 0.12 ;
     RECT  56.704 4.128 58.201 4.776 ;
     RECT  58.069 0.096 58.385 0.552 ;
     RECT  58.489 85.488 58.573 85.512 ;
     RECT  56.704 73.344 58.597 74.136 ;
     RECT  58.597 73.344 58.637 74.712 ;
     RECT  58.201 3.984 58.693 4.776 ;
     RECT  56.704 80.928 58.777 83.064 ;
     RECT  58.693 3.36 58.78 4.776 ;
     RECT  56.704 44.352 58.849 44.376 ;
     RECT  58.849 44.064 58.889 44.376 ;
     RECT  56.704 60.096 59.069 60.12 ;
     RECT  58.78 3.792 59.321 4.776 ;
     RECT  58.777 80.928 59.461 83.112 ;
     RECT  59.281 59.616 59.555 59.64 ;
     RECT  58.637 73.344 59.555 73.368 ;
     RECT  59.077 86.256 59.701 86.28 ;
     RECT  59.321 4.368 59.717 4.776 ;
     RECT  58.06 40.56 59.893 40.584 ;
     RECT  58.669 38.448 59.965 38.472 ;
     RECT  59.893 39.648 59.965 40.584 ;
     RECT  59.965 38.448 59.987 40.584 ;
     RECT  59.987 38.448 60.005 38.76 ;
     RECT  59.717 4.368 60.397 4.392 ;
     RECT  59.509 60.672 60.421 60.696 ;
     RECT  60.421 56.112 60.476 56.136 ;
     RECT  58.637 74.688 60.505 74.712 ;
     RECT  59.701 86.208 60.509 86.28 ;
     RECT  60.476 56.112 60.545 56.424 ;
     RECT  60.545 56.4 60.563 56.424 ;
     RECT  60.505 74.688 60.589 75.288 ;
     RECT  60.397 3.408 60.653 4.392 ;
     RECT  56.704 71.328 60.661 71.352 ;
     RECT  60.421 60.384 60.707 60.696 ;
     RECT  60.517 62.16 60.709 62.184 ;
     RECT  60.709 62.16 60.755 62.472 ;
     RECT  60.661 71.328 60.755 71.928 ;
     RECT  60.707 60.672 60.761 60.696 ;
     RECT  58.777 58.128 60.997 58.152 ;
     RECT  60.901 85.968 61.049 85.992 ;
     RECT  61.093 1.728 61.373 1.752 ;
     RECT  61.477 86.256 61.589 86.28 ;
     RECT  60.653 4.128 61.808 4.392 ;
     RECT  56.704 25.968 61.808 25.992 ;
     RECT  56.704 28.944 61.808 28.968 ;
     RECT  60.005 38.736 61.808 38.76 ;
     RECT  61.549 40.032 61.808 40.056 ;
     RECT  59.941 41.712 61.808 41.736 ;
     RECT  58.889 44.064 61.808 44.088 ;
     RECT  59.641 48.864 61.808 49.032 ;
     RECT  60.997 58.128 61.808 58.68 ;
     RECT  61.141 61.104 61.808 61.128 ;
     RECT  60.755 62.448 61.808 62.472 ;
     RECT  60.755 71.904 61.808 71.928 ;
     RECT  60.589 74.688 61.808 74.712 ;
     RECT  59.461 80.928 61.808 83.304 ;
     RECT  61.808 2.148 61.912 84.252 ;
     RECT  61.912 2.148 62.104 83.982 ;
     RECT  62.104 74.544 62.165 74.712 ;
     RECT  62.101 85.968 62.201 85.992 ;
     RECT  62.104 76.128 62.483 76.152 ;
     RECT  62.104 61.104 62.525 61.128 ;
     RECT  62.104 43.296 62.627 44.088 ;
     RECT  62.104 38.736 62.741 40.056 ;
     RECT  62.741 39.312 62.785 40.056 ;
     RECT  62.104 80.928 62.813 83.784 ;
     RECT  62.813 80.928 62.849 83.352 ;
     RECT  62.104 65.52 62.965 65.544 ;
     RECT  62.821 1.728 63.029 1.752 ;
     RECT  62.785 39.888 63.101 40.056 ;
     RECT  62.104 71.904 63.245 71.928 ;
     RECT  62.104 3.696 63.353 4.488 ;
     RECT  62.165 74.544 63.353 74.568 ;
     RECT  62.627 43.296 63.461 43.32 ;
     RECT  62.104 41.616 63.637 41.64 ;
     RECT  62.104 62.448 63.637 62.472 ;
     RECT  64.124 76.896 64.165 76.92 ;
     RECT  63.101 39.888 64.177 39.912 ;
     RECT  62.677 86.256 64.181 86.28 ;
     RECT  64.165 76.368 64.211 76.92 ;
     RECT  64.177 39.6 64.217 39.912 ;
     RECT  63.637 41.04 64.325 41.64 ;
     RECT  64.211 76.368 64.46 76.392 ;
     RECT  64.493 84.912 64.577 84.936 ;
     RECT  63.637 62.16 64.757 62.472 ;
     RECT  64.325 41.376 64.969 41.64 ;
     RECT  64.46 75.792 64.973 76.392 ;
     RECT  62.849 80.928 64.981 83.304 ;
     RECT  64.165 78.24 65.132 78.264 ;
     RECT  63.353 4.368 65.149 4.488 ;
     RECT  64.321 72.336 65.219 72.36 ;
     RECT  65.132 78.048 65.219 78.264 ;
     RECT  65.077 85.488 65.297 85.512 ;
     RECT  64.141 66.096 65.365 66.12 ;
     RECT  65.365 66.096 65.405 66.696 ;
     RECT  65.405 66.672 65.449 66.696 ;
     RECT  65.365 74.688 65.449 74.712 ;
     RECT  65.219 78.24 65.477 78.264 ;
     RECT  64.217 39.6 65.513 39.624 ;
     RECT  64.069 44.064 65.585 44.088 ;
     RECT  65.689 84.912 65.773 84.936 ;
     RECT  64.757 62.16 65.837 62.184 ;
     RECT  64.969 41.376 65.893 41.736 ;
     RECT  65.893 40.704 65.98 41.736 ;
     RECT  65.98 40.848 65.989 41.736 ;
     RECT  65.437 43.008 65.989 43.032 ;
     RECT  64.981 80.784 66.049 83.304 ;
     RECT  65.989 40.848 66.076 43.032 ;
     RECT  66.049 80.784 66.193 83.64 ;
     RECT  66.193 80.784 66.197 84.408 ;
     RECT  64.973 76.368 66.229 76.392 ;
     RECT  65.149 4.224 66.233 4.488 ;
     RECT  66.157 1.728 66.323 1.752 ;
     RECT  66.197 84.384 66.323 84.408 ;
     RECT  66.233 4.416 67.208 4.488 ;
     RECT  62.104 25.968 67.208 25.992 ;
     RECT  62.104 28.944 67.208 28.968 ;
     RECT  66.076 40.848 67.208 41.736 ;
     RECT  66.076 43.008 67.208 43.032 ;
     RECT  65.653 44.112 67.208 44.136 ;
     RECT  66.229 76.224 67.208 76.392 ;
     RECT  66.197 80.784 67.208 83.112 ;
     RECT  67.208 2.148 67.312 84.252 ;
     RECT  67.312 2.148 67.504 83.982 ;
     RECT  67.504 40.416 67.715 41.784 ;
     RECT  67.504 76.224 67.889 76.248 ;
     RECT  67.504 42.768 68.099 42.792 ;
     RECT  67.715 40.992 68.105 41.784 ;
     RECT  68.105 41.232 68.14 41.784 ;
     RECT  66.901 86.256 68.249 86.28 ;
     RECT  68.005 1.728 68.321 1.752 ;
     RECT  67.504 3.408 68.573 3.432 ;
     RECT  67.504 4.464 68.749 4.488 ;
     RECT  68.749 4.128 68.789 4.488 ;
     RECT  68.677 84.336 68.933 84.36 ;
     RECT  67.504 80.784 69.441 83.112 ;
     RECT  58.385 0.096 69.733 0.12 ;
     RECT  68.789 4.128 70.333 4.152 ;
     RECT  67.504 44.112 70.501 44.136 ;
     RECT  68.14 41.712 70.581 41.784 ;
     RECT  69.733 0.096 70.597 0.168 ;
     RECT  70.333 3.408 70.693 4.152 ;
     RECT  70.693 3.408 70.733 4.248 ;
     RECT  69.441 80.736 70.805 83.112 ;
     RECT  70.597 0.096 70.841 0.552 ;
     RECT  70.805 80.784 70.913 83.112 ;
     RECT  71.449 1.728 71.533 1.752 ;
     RECT  70.501 43.92 71.561 44.136 ;
     RECT  69.289 86.256 72.421 86.28 ;
     RECT  72.421 85.488 72.533 86.28 ;
     RECT  70.733 4.128 72.608 4.248 ;
     RECT  67.504 25.968 72.608 25.992 ;
     RECT  67.504 28.944 72.608 28.968 ;
     RECT  70.581 41.76 72.608 41.784 ;
     RECT  71.561 44.064 72.608 44.136 ;
     RECT  70.913 80.784 72.608 82.824 ;
     RECT  72.608 2.148 72.712 84.252 ;
     RECT  70.841 0.096 72.716 0.12 ;
     RECT  72.716 0.096 72.803 0.552 ;
     RECT  72.712 2.418 72.904 84.252 ;
     RECT  72.533 85.488 72.947 85.512 ;
     RECT  73.465 84.912 73.549 84.936 ;
     RECT  72.904 3.6 73.933 4.152 ;
     RECT  72.803 0.096 74.153 0.12 ;
     RECT  72.904 28.944 74.153 28.968 ;
     RECT  74.485 0.528 74.729 0.552 ;
     RECT  73.933 3.552 74.761 4.152 ;
     RECT  72.904 80.592 74.828 82.824 ;
     RECT  74.828 79.728 74.917 82.824 ;
     RECT  74.905 29.04 74.989 29.064 ;
     RECT  74.917 1.728 75.125 1.752 ;
     RECT  74.761 3.408 75.692 4.152 ;
     RECT  74.917 79.728 75.692 83.352 ;
     RECT  75.692 3.408 75.779 4.872 ;
     RECT  75.692 79.536 75.779 83.352 ;
     RECT  74.101 86.256 75.877 86.28 ;
     RECT  75.877 86.016 76.133 86.28 ;
     RECT  76.069 78.624 76.156 78.648 ;
     RECT  75.779 79.776 76.565 83.352 ;
     RECT  72.904 44.064 77.125 44.088 ;
     RECT  75.349 0.096 77.249 0.12 ;
     RECT  76.645 1.728 77.717 1.752 ;
     RECT  72.904 41.616 77.893 41.64 ;
     RECT  75.779 3.408 78.008 3.432 ;
     RECT  75.733 6.048 78.008 6.072 ;
     RECT  72.904 25.968 78.008 25.992 ;
     RECT  77.893 41.616 78.008 42.024 ;
     RECT  77.125 44.064 78.008 44.616 ;
     RECT  77.749 76.848 78.008 76.872 ;
     RECT  76.988 78.72 78.008 78.744 ;
     RECT  76.565 80.064 78.008 83.352 ;
     RECT  78.008 2.148 78.112 84.252 ;
     RECT  78.112 2.418 78.277 84.252 ;
     RECT  78.277 2.418 78.304 84.408 ;
     RECT  77.941 0.528 78.365 0.552 ;
     RECT  78.304 79.776 78.365 84.408 ;
     RECT  78.304 6.048 78.401 6.168 ;
     RECT  78.304 75.888 78.761 77.544 ;
     RECT  78.304 42 78.797 42.072 ;
     RECT  78.761 76.368 78.947 77.544 ;
     RECT  76.133 86.256 79.157 86.28 ;
     RECT  78.947 76.368 79.229 76.872 ;
     RECT  79.477 84.912 79.561 84.936 ;
     RECT  78.365 79.776 79.58 83.496 ;
     RECT  79.229 76.368 79.981 76.392 ;
     RECT  78.304 74.64 79.985 74.664 ;
     RECT  78.304 25.968 80.129 25.992 ;
     RECT  79.58 79.728 80.197 83.496 ;
     RECT  79.585 78.048 80.233 78.072 ;
     RECT  80.197 79.152 80.233 83.496 ;
     RECT  79.981 76.128 80.243 76.392 ;
     RECT  80.261 26.208 80.345 26.232 ;
     RECT  80.233 78.048 80.353 83.496 ;
     RECT  80.353 78.048 80.435 81.48 ;
     RECT  80.435 78.048 80.476 78.072 ;
     RECT  78.304 44.064 80.561 44.088 ;
     RECT  80.101 85.488 80.677 85.512 ;
     RECT  80.353 82.656 80.777 83.496 ;
     RECT  80.677 85.44 80.813 85.512 ;
     RECT  78.797 42.048 80.989 42.072 ;
     RECT  80.813 85.488 81.065 85.512 ;
     RECT  78.401 6.144 81.173 6.168 ;
     RECT  80.881 40.416 81.445 40.44 ;
     RECT  80.989 42.048 81.445 42.792 ;
     RECT  81.377 1.728 81.461 1.752 ;
     RECT  80.557 4.608 81.461 4.632 ;
     RECT  81.445 40.416 81.491 42.792 ;
     RECT  80.777 82.656 81.497 83.208 ;
     RECT  80.243 76.368 81.529 76.392 ;
     RECT  80.435 79.152 81.565 81.48 ;
     RECT  81.491 41.232 81.641 41.256 ;
     RECT  81.565 78.624 81.649 81.48 ;
     RECT  81.709 82.512 81.857 82.536 ;
     RECT  81.877 84.336 81.965 84.36 ;
     RECT  81.649 79.056 82.067 81.48 ;
     RECT  82.067 79.152 82.073 81.48 ;
     RECT  81.529 75.888 82.117 76.392 ;
     RECT  81.889 77.904 82.117 77.928 ;
     RECT  82.117 75.888 82.163 76.488 ;
     RECT  82.105 74.064 82.189 74.088 ;
     RECT  82.117 77.52 82.204 77.928 ;
     RECT  82.073 79.92 82.213 81.48 ;
     RECT  78.373 0.096 82.22 0.12 ;
     RECT  82.213 79.92 82.297 82.056 ;
     RECT  82.22 0.096 82.307 0.552 ;
     RECT  82.163 76.464 82.361 76.488 ;
     RECT  81.565 6.24 82.397 6.264 ;
     RECT  81.301 86.256 82.547 86.28 ;
     RECT  82.307 0.096 83.333 0.12 ;
     RECT  83.185 2.832 83.408 2.856 ;
     RECT  83.269 5.712 83.408 5.736 ;
     RECT  82.204 77.904 83.408 77.928 ;
     RECT  82.297 79.92 83.408 81.48 ;
     RECT  82.645 83.808 83.408 83.832 ;
     RECT  83.408 2.148 83.512 84.252 ;
     RECT  83.512 2.304 83.653 84.252 ;
     RECT  83.653 2.304 83.704 84.36 ;
     RECT  83.704 84.336 83.747 84.36 ;
     RECT  83.704 2.304 84.035 2.328 ;
     RECT  84.013 86.256 84.323 86.28 ;
     RECT  83.516 0.528 84.467 0.552 ;
     RECT  84.373 85.488 84.947 85.512 ;
     RECT  84.913 14.064 85.129 14.088 ;
     RECT  84.841 0.096 85.357 0.12 ;
     RECT  85.129 14.064 85.453 14.712 ;
     RECT  84.877 24.72 85.453 24.744 ;
     RECT  84.913 27.216 85.453 27.24 ;
     RECT  84.913 31.584 85.453 31.608 ;
     RECT  84.913 32.88 85.453 32.904 ;
     RECT  84.877 36.624 85.453 36.648 ;
     RECT  84.913 39.744 85.453 39.768 ;
     RECT  84.913 51.024 85.453 51.048 ;
     RECT  84.877 52.272 85.453 52.296 ;
     RECT  84.913 66.672 85.453 66.696 ;
     RECT  84.913 78.576 85.453 78.6 ;
     RECT  84.913 2.784 85.489 2.808 ;
     RECT  85.453 5.328 85.489 10.968 ;
     RECT  85.453 12.192 85.489 16.584 ;
     RECT  85.453 24.72 85.489 29.112 ;
     RECT  85.453 30.336 85.489 35.4 ;
     RECT  85.453 36.624 85.489 37.272 ;
     RECT  85.453 38.496 85.489 41.64 ;
     RECT  85.453 55.392 85.489 60.408 ;
     RECT  85.489 2.16 86.173 2.808 ;
     RECT  85.445 86.256 86.173 86.28 ;
     RECT  86.173 86.064 86.185 86.28 ;
     RECT  86.173 2.16 86.209 3.432 ;
     RECT  86.185 86.064 86.209 86.088 ;
     RECT  85.676 0.288 86.245 0.552 ;
     RECT  86.209 1.536 86.245 3.432 ;
     RECT  85.489 5.328 86.245 16.584 ;
     RECT  85.489 74.784 86.245 74.808 ;
     RECT  85.525 83.568 86.245 83.592 ;
     RECT  86.209 85.44 86.245 86.088 ;
     RECT  86.245 0.288 86.281 3.432 ;
     RECT  86.245 4.704 86.281 16.584 ;
     RECT  85.453 18.48 86.281 21.624 ;
     RECT  85.489 23.472 86.281 29.112 ;
     RECT  85.489 30.336 86.281 37.272 ;
     RECT  85.489 38.496 86.281 42.264 ;
     RECT  85.453 43.488 86.281 43.512 ;
     RECT  85.453 44.736 86.281 47.304 ;
     RECT  85.453 49.776 86.281 53.544 ;
     RECT  85.489 54.768 86.281 60.408 ;
     RECT  85.453 61.68 86.281 72.936 ;
     RECT  86.245 74.16 86.281 74.808 ;
     RECT  85.453 76.08 86.281 79.224 ;
     RECT  85.453 81.072 86.281 81.096 ;
     RECT  86.245 82.944 86.281 83.592 ;
     RECT  86.245 84.816 86.281 86.088 ;
     RECT  86.281 0.288 86.316 0.312 ;
     RECT  86.281 0.312 86.364 0.912 ;
     RECT  86.281 0.912 86.316 0.936 ;
     RECT  86.281 0.936 86.364 1.536 ;
     RECT  86.281 1.536 86.316 1.56 ;
     RECT  86.281 1.56 86.364 2.16 ;
     RECT  86.281 2.16 86.316 2.184 ;
     RECT  86.281 2.184 86.364 2.784 ;
     RECT  86.281 2.784 86.316 2.808 ;
     RECT  86.281 2.808 86.364 3.408 ;
     RECT  86.281 3.408 86.316 3.432 ;
     RECT  86.281 3.432 86.364 4.08 ;
     RECT  86.281 4.08 86.316 4.104 ;
     RECT  86.281 4.104 86.364 4.704 ;
     RECT  86.281 4.704 86.316 4.728 ;
     RECT  86.281 4.728 86.364 5.328 ;
     RECT  86.281 5.328 86.316 5.352 ;
     RECT  86.281 5.352 86.364 5.952 ;
     RECT  86.281 5.952 86.316 5.976 ;
     RECT  86.281 5.976 86.364 6.576 ;
     RECT  86.281 6.576 86.316 6.6 ;
     RECT  86.281 6.6 86.364 7.2 ;
     RECT  86.281 7.2 86.316 7.224 ;
     RECT  86.281 7.224 86.364 7.824 ;
     RECT  86.281 7.824 86.316 7.848 ;
     RECT  86.281 7.848 86.364 8.448 ;
     RECT  86.281 8.448 86.316 8.472 ;
     RECT  86.281 8.472 86.364 9.072 ;
     RECT  86.281 9.072 86.316 9.096 ;
     RECT  86.281 9.096 86.364 9.696 ;
     RECT  86.281 9.696 86.316 9.72 ;
     RECT  86.281 9.72 86.364 10.32 ;
     RECT  86.281 10.32 86.316 10.344 ;
     RECT  86.281 10.344 86.364 10.944 ;
     RECT  86.281 10.944 86.316 10.968 ;
     RECT  86.281 10.968 86.364 11.568 ;
     RECT  86.281 11.568 86.316 11.592 ;
     RECT  86.281 11.592 86.364 12.192 ;
     RECT  86.281 12.192 86.316 12.216 ;
     RECT  86.281 12.216 86.364 12.816 ;
     RECT  86.281 12.816 86.316 12.84 ;
     RECT  86.281 12.84 86.364 13.44 ;
     RECT  86.281 13.44 86.316 13.464 ;
     RECT  86.281 13.464 86.364 14.064 ;
     RECT  86.281 14.064 86.316 14.088 ;
     RECT  86.281 14.088 86.364 14.688 ;
     RECT  86.281 14.688 86.316 14.712 ;
     RECT  86.281 14.712 86.364 15.312 ;
     RECT  86.281 15.312 86.316 15.336 ;
     RECT  86.281 15.336 86.364 15.936 ;
     RECT  86.281 15.936 86.316 15.96 ;
     RECT  86.281 15.96 86.364 16.56 ;
     RECT  86.281 16.56 86.316 16.584 ;
     RECT  86.281 16.584 86.364 17.184 ;
     RECT  86.281 17.184 86.316 17.208 ;
     RECT  86.281 17.208 86.364 17.808 ;
     RECT  86.281 17.808 86.316 17.832 ;
     RECT  86.281 17.832 86.364 18.48 ;
     RECT  86.281 18.48 86.316 18.504 ;
     RECT  86.281 18.504 86.364 19.104 ;
     RECT  86.281 19.104 86.316 19.128 ;
     RECT  86.281 19.128 86.364 19.728 ;
     RECT  86.281 19.728 86.316 19.752 ;
     RECT  86.281 19.752 86.364 20.352 ;
     RECT  86.281 20.352 86.316 20.376 ;
     RECT  86.281 20.376 86.364 20.976 ;
     RECT  86.281 20.976 86.316 21 ;
     RECT  86.281 21 86.364 21.6 ;
     RECT  86.281 21.6 86.316 21.624 ;
     RECT  86.281 21.624 86.364 22.224 ;
     RECT  86.281 22.224 86.316 22.248 ;
     RECT  86.281 22.248 86.364 22.848 ;
     RECT  86.281 22.848 86.316 22.872 ;
     RECT  86.281 22.872 86.364 23.472 ;
     RECT  86.281 23.472 86.316 23.496 ;
     RECT  86.281 23.496 86.364 24.096 ;
     RECT  86.281 24.096 86.316 24.12 ;
     RECT  86.281 24.12 86.364 24.72 ;
     RECT  86.281 24.72 86.316 24.744 ;
     RECT  86.281 24.744 86.364 25.344 ;
     RECT  86.281 25.344 86.316 25.368 ;
     RECT  86.281 25.368 86.364 25.968 ;
     RECT  86.281 25.968 86.316 25.992 ;
     RECT  86.281 25.992 86.364 26.592 ;
     RECT  86.281 26.592 86.316 26.616 ;
     RECT  86.281 26.616 86.364 27.216 ;
     RECT  86.281 27.216 86.316 27.24 ;
     RECT  86.281 27.24 86.364 27.84 ;
     RECT  86.281 27.84 86.316 27.864 ;
     RECT  86.281 27.864 86.364 28.464 ;
     RECT  86.281 28.464 86.316 28.488 ;
     RECT  86.281 28.488 86.364 29.088 ;
     RECT  86.281 29.088 86.316 29.112 ;
     RECT  86.281 29.112 86.364 29.712 ;
     RECT  86.281 29.712 86.316 29.736 ;
     RECT  86.281 29.736 86.364 30.336 ;
     RECT  86.281 30.336 86.316 30.36 ;
     RECT  86.281 30.36 86.364 30.96 ;
     RECT  86.281 30.96 86.316 30.984 ;
     RECT  86.281 30.984 86.364 31.584 ;
     RECT  86.281 31.584 86.316 31.608 ;
     RECT  86.281 31.608 86.364 32.208 ;
     RECT  86.281 32.208 86.316 32.232 ;
     RECT  86.281 32.232 86.364 32.88 ;
     RECT  86.281 32.88 86.316 32.904 ;
     RECT  86.281 32.904 86.364 33.504 ;
     RECT  86.281 33.504 86.316 33.528 ;
     RECT  86.281 33.528 86.364 34.128 ;
     RECT  86.281 34.128 86.316 34.152 ;
     RECT  86.281 34.152 86.364 34.752 ;
     RECT  86.281 34.752 86.316 34.776 ;
     RECT  86.281 34.776 86.364 35.376 ;
     RECT  86.281 35.376 86.316 35.4 ;
     RECT  86.281 35.4 86.364 36 ;
     RECT  86.281 36 86.316 36.024 ;
     RECT  86.281 36.024 86.364 36.624 ;
     RECT  86.281 36.624 86.316 36.648 ;
     RECT  86.281 36.648 86.364 37.248 ;
     RECT  86.281 37.248 86.316 37.272 ;
     RECT  86.281 37.272 86.364 37.872 ;
     RECT  86.281 37.872 86.316 37.896 ;
     RECT  86.281 37.896 86.364 38.496 ;
     RECT  86.281 38.496 86.316 38.52 ;
     RECT  86.281 38.52 86.364 39.12 ;
     RECT  86.281 39.12 86.316 39.144 ;
     RECT  86.281 39.144 86.364 39.744 ;
     RECT  86.281 39.744 86.316 39.768 ;
     RECT  86.281 39.768 86.364 40.368 ;
     RECT  86.281 40.368 86.316 40.392 ;
     RECT  86.281 40.392 86.364 40.992 ;
     RECT  86.281 40.992 86.316 41.016 ;
     RECT  86.281 41.016 86.364 41.616 ;
     RECT  86.281 41.616 86.316 41.64 ;
     RECT  86.281 41.64 86.364 42.24 ;
     RECT  86.281 42.24 86.316 42.264 ;
     RECT  86.281 42.264 86.364 42.864 ;
     RECT  86.281 42.864 86.316 42.888 ;
     RECT  86.281 42.888 86.364 43.488 ;
     RECT  86.281 43.488 86.316 43.512 ;
     RECT  86.281 43.512 86.364 44.112 ;
     RECT  86.281 44.112 86.316 44.136 ;
     RECT  86.281 44.136 86.364 44.736 ;
     RECT  86.281 44.736 86.316 44.76 ;
     RECT  86.281 44.76 86.364 45.36 ;
     RECT  86.281 45.36 86.316 45.384 ;
     RECT  86.281 45.384 86.364 45.984 ;
     RECT  86.281 45.984 86.316 46.008 ;
     RECT  86.281 46.008 86.364 46.608 ;
     RECT  86.281 46.608 86.316 46.632 ;
     RECT  86.281 46.632 86.364 47.28 ;
     RECT  86.281 47.28 86.316 47.304 ;
     RECT  86.281 47.304 86.364 47.904 ;
     RECT  86.281 47.904 86.316 47.928 ;
     RECT  86.281 47.928 86.364 48.528 ;
     RECT  86.281 48.528 86.316 48.552 ;
     RECT  86.281 48.552 86.364 49.152 ;
     RECT  86.281 49.152 86.316 49.176 ;
     RECT  86.281 49.176 86.364 49.776 ;
     RECT  86.281 49.776 86.316 49.8 ;
     RECT  86.281 49.8 86.364 50.4 ;
     RECT  86.281 50.4 86.316 50.424 ;
     RECT  86.281 50.424 86.364 51.024 ;
     RECT  86.281 51.024 86.316 51.048 ;
     RECT  86.281 51.048 86.364 51.648 ;
     RECT  86.281 51.648 86.316 51.672 ;
     RECT  86.281 51.672 86.364 52.272 ;
     RECT  86.281 52.272 86.316 52.296 ;
     RECT  86.281 52.296 86.364 52.896 ;
     RECT  86.281 52.896 86.316 52.92 ;
     RECT  86.281 52.92 86.364 53.52 ;
     RECT  86.281 53.52 86.316 53.544 ;
     RECT  86.281 53.544 86.364 54.144 ;
     RECT  86.281 54.144 86.316 54.168 ;
     RECT  86.281 54.168 86.364 54.768 ;
     RECT  86.281 54.768 86.316 54.792 ;
     RECT  86.281 54.792 86.364 55.392 ;
     RECT  86.281 55.392 86.316 55.416 ;
     RECT  86.281 55.416 86.364 56.016 ;
     RECT  86.281 56.016 86.316 56.04 ;
     RECT  86.281 56.04 86.364 56.64 ;
     RECT  86.281 56.64 86.316 56.664 ;
     RECT  86.281 56.664 86.364 57.264 ;
     RECT  86.281 57.264 86.316 57.288 ;
     RECT  86.281 57.288 86.364 57.888 ;
     RECT  86.281 57.888 86.316 57.912 ;
     RECT  86.281 57.912 86.364 58.512 ;
     RECT  86.281 58.512 86.316 58.536 ;
     RECT  86.281 58.536 86.364 59.136 ;
     RECT  86.281 59.136 86.316 59.16 ;
     RECT  86.281 59.16 86.364 59.76 ;
     RECT  86.281 59.76 86.316 59.784 ;
     RECT  86.281 59.784 86.364 60.384 ;
     RECT  86.281 60.384 86.316 60.408 ;
     RECT  86.281 60.408 86.364 61.008 ;
     RECT  86.281 61.008 86.316 61.032 ;
     RECT  86.281 61.032 86.364 61.68 ;
     RECT  86.281 61.68 86.316 61.704 ;
     RECT  86.281 61.704 86.364 62.304 ;
     RECT  86.281 62.304 86.316 62.328 ;
     RECT  86.281 62.328 86.364 62.928 ;
     RECT  86.281 62.928 86.316 62.952 ;
     RECT  86.281 62.952 86.364 63.552 ;
     RECT  86.281 63.552 86.316 63.576 ;
     RECT  86.281 63.576 86.364 64.176 ;
     RECT  86.281 64.176 86.316 64.2 ;
     RECT  86.281 64.2 86.364 64.8 ;
     RECT  86.281 64.8 86.316 64.824 ;
     RECT  86.281 64.824 86.364 65.424 ;
     RECT  86.281 65.424 86.316 65.448 ;
     RECT  86.281 65.448 86.364 66.048 ;
     RECT  86.281 66.048 86.316 66.072 ;
     RECT  86.281 66.072 86.364 66.672 ;
     RECT  86.281 66.672 86.316 66.696 ;
     RECT  86.281 66.696 86.364 67.296 ;
     RECT  86.281 67.296 86.316 67.32 ;
     RECT  86.281 67.32 86.364 67.92 ;
     RECT  86.281 67.92 86.316 67.944 ;
     RECT  86.281 67.944 86.364 68.544 ;
     RECT  86.281 68.544 86.316 68.568 ;
     RECT  86.281 68.568 86.364 69.168 ;
     RECT  86.281 69.168 86.316 69.192 ;
     RECT  86.281 69.192 86.364 69.792 ;
     RECT  86.281 69.792 86.316 69.816 ;
     RECT  86.281 69.816 86.364 70.416 ;
     RECT  86.281 70.416 86.316 70.44 ;
     RECT  86.281 70.44 86.364 71.04 ;
     RECT  86.281 71.04 86.316 71.064 ;
     RECT  86.281 71.064 86.364 71.664 ;
     RECT  86.281 71.664 86.316 71.688 ;
     RECT  86.281 71.688 86.364 72.288 ;
     RECT  86.281 72.288 86.316 72.312 ;
     RECT  86.281 72.312 86.364 72.912 ;
     RECT  86.281 72.912 86.316 72.936 ;
     RECT  86.281 72.936 86.364 73.536 ;
     RECT  86.281 73.536 86.316 73.56 ;
     RECT  86.281 73.56 86.364 74.16 ;
     RECT  86.281 74.16 86.316 74.184 ;
     RECT  86.281 74.184 86.364 74.784 ;
     RECT  86.281 74.784 86.316 74.808 ;
     RECT  86.281 74.808 86.364 75.408 ;
     RECT  86.281 75.408 86.316 75.432 ;
     RECT  86.281 75.432 86.364 76.08 ;
     RECT  86.281 76.08 86.316 76.104 ;
     RECT  86.281 76.104 86.364 76.704 ;
     RECT  86.281 76.704 86.316 76.728 ;
     RECT  86.281 76.728 86.364 77.328 ;
     RECT  86.281 77.328 86.316 77.352 ;
     RECT  86.281 77.352 86.364 77.952 ;
     RECT  86.281 77.952 86.316 77.976 ;
     RECT  86.281 77.976 86.364 78.576 ;
     RECT  86.281 78.576 86.316 78.6 ;
     RECT  86.281 78.6 86.364 79.2 ;
     RECT  86.281 79.2 86.316 79.224 ;
     RECT  86.281 79.224 86.364 79.824 ;
     RECT  86.281 79.824 86.316 79.848 ;
     RECT  86.281 79.848 86.364 80.448 ;
     RECT  86.281 80.448 86.316 80.472 ;
     RECT  86.281 80.472 86.364 81.072 ;
     RECT  86.281 81.072 86.316 81.096 ;
     RECT  86.281 81.096 86.364 81.696 ;
     RECT  86.281 81.696 86.316 81.72 ;
     RECT  86.281 81.72 86.364 82.32 ;
     RECT  86.281 82.32 86.316 82.344 ;
     RECT  86.281 82.344 86.364 82.944 ;
     RECT  86.281 82.944 86.316 82.968 ;
     RECT  86.281 82.968 86.364 83.568 ;
     RECT  86.281 83.568 86.316 83.592 ;
     RECT  86.281 83.592 86.364 84.192 ;
     RECT  86.281 84.192 86.316 84.216 ;
     RECT  86.281 84.216 86.364 84.816 ;
     RECT  86.281 84.816 86.316 84.84 ;
     RECT  86.281 84.84 86.364 85.44 ;
     RECT  86.281 85.44 86.316 85.464 ;
     RECT  86.281 85.464 86.364 86.064 ;
     RECT  86.281 86.064 86.316 86.088 ;
    LAYER M5 ;
     RECT  0.216 0.016 0.624 0.084 ;
     RECT  0.648 0.016 1.056 0.084 ;
     RECT  1.08 0.016 1.488 0.084 ;
     RECT  1.512 0.016 1.92 0.084 ;
     RECT  1.944 0.016 2.352 0.084 ;
     RECT  2.376 0.016 2.784 0.084 ;
     RECT  2.808 0.016 3.216 0.084 ;
     RECT  3.24 0.016 3.648 0.084 ;
     RECT  3.672 0.016 4.08 0.084 ;
     RECT  4.104 0.016 4.512 0.084 ;
     RECT  4.536 0.016 4.944 0.084 ;
     RECT  4.968 0.016 5.376 0.084 ;
     RECT  5.4 0.016 5.808 0.084 ;
     RECT  5.832 0.016 6.24 0.084 ;
     RECT  6.264 0.016 6.672 0.084 ;
     RECT  6.696 0.016 7.104 0.084 ;
     RECT  7.128 0.016 7.536 0.084 ;
     RECT  7.56 0.016 7.968 0.084 ;
     RECT  7.992 0.016 8.4 0.084 ;
     RECT  8.424 0.016 8.832 0.084 ;
     RECT  8.856 0.016 9.264 0.084 ;
     RECT  9.288 0.016 9.696 0.084 ;
     RECT  9.72 0.016 10.128 0.084 ;
     RECT  10.152 0.016 10.56 0.084 ;
     RECT  10.584 0.016 10.992 0.084 ;
     RECT  11.016 0.016 11.424 0.084 ;
     RECT  11.448 0.016 11.856 0.084 ;
     RECT  11.88 0.016 12.288 0.084 ;
     RECT  12.312 0.016 12.72 0.084 ;
     RECT  12.744 0.016 13.152 0.084 ;
     RECT  13.176 0.016 13.584 0.084 ;
     RECT  13.608 0.016 14.016 0.084 ;
     RECT  14.04 0.016 14.448 0.084 ;
     RECT  14.472 0.016 14.88 0.084 ;
     RECT  14.904 0.016 15.312 0.084 ;
     RECT  15.336 0.016 15.744 0.084 ;
     RECT  15.768 0.016 16.176 0.084 ;
     RECT  16.2 0.016 16.608 0.084 ;
     RECT  16.632 0.016 17.04 0.084 ;
     RECT  17.064 0.016 17.472 0.084 ;
     RECT  17.496 0.016 17.904 0.084 ;
     RECT  17.928 0.016 18.336 0.084 ;
     RECT  18.36 0.016 18.768 0.084 ;
     RECT  18.792 0.016 19.2 0.084 ;
     RECT  19.224 0.016 19.632 0.084 ;
     RECT  19.656 0.016 20.064 0.084 ;
     RECT  20.088 0.016 20.496 0.084 ;
     RECT  20.52 0.016 20.928 0.084 ;
     RECT  20.952 0.016 21.36 0.084 ;
     RECT  21.384 0.016 21.792 0.084 ;
     RECT  21.816 0.016 22.224 0.084 ;
     RECT  22.248 0.016 22.656 0.084 ;
     RECT  22.68 0.016 23.088 0.084 ;
     RECT  23.112 0.016 23.52 0.084 ;
     RECT  23.544 0.016 23.952 0.084 ;
     RECT  23.976 0.016 24.384 0.084 ;
     RECT  24.408 0.016 24.816 0.084 ;
     RECT  24.84 0.016 25.248 0.084 ;
     RECT  25.272 0.016 25.68 0.084 ;
     RECT  25.704 0.016 26.112 0.084 ;
     RECT  26.136 0.016 26.544 0.084 ;
     RECT  26.568 0.016 26.976 0.084 ;
     RECT  27 0.016 27.408 0.084 ;
     RECT  27.432 0.016 27.84 0.084 ;
     RECT  27.864 0.016 28.272 0.084 ;
     RECT  28.296 0.016 28.704 0.084 ;
     RECT  28.728 0.016 29.136 0.084 ;
     RECT  29.16 0.016 29.568 0.084 ;
     RECT  29.592 0.016 30 0.084 ;
     RECT  30.024 0.016 30.432 0.084 ;
     RECT  30.456 0.016 30.864 0.084 ;
     RECT  30.888 0.016 31.296 0.084 ;
     RECT  31.32 0.016 31.728 0.084 ;
     RECT  31.752 0.016 32.16 0.084 ;
     RECT  32.184 0.016 32.592 0.084 ;
     RECT  32.616 0.016 33.024 0.084 ;
     RECT  33.048 0.016 33.456 0.084 ;
     RECT  33.48 0.016 33.888 0.084 ;
     RECT  33.912 0.016 34.32 0.084 ;
     RECT  34.344 0.016 34.752 0.084 ;
     RECT  34.776 0.016 35.184 0.084 ;
     RECT  35.208 0.016 35.616 0.084 ;
     RECT  35.64 0.016 36.048 0.084 ;
     RECT  36.072 0.016 36.48 0.084 ;
     RECT  36.504 0.016 36.912 0.084 ;
     RECT  36.936 0.016 37.344 0.084 ;
     RECT  37.368 0.016 37.776 0.084 ;
     RECT  37.8 0.016 38.208 0.084 ;
     RECT  38.232 0.016 38.64 0.084 ;
     RECT  38.664 0.016 39.072 0.084 ;
     RECT  39.096 0.016 39.504 0.084 ;
     RECT  39.528 0.016 39.936 0.084 ;
     RECT  39.96 0.016 40.368 0.084 ;
     RECT  40.392 0.016 40.8 0.084 ;
     RECT  40.824 0.016 41.232 0.084 ;
     RECT  41.256 0.016 41.664 0.084 ;
     RECT  41.688 0.016 42.096 0.084 ;
     RECT  42.12 0.016 42.528 0.084 ;
     RECT  42.552 0.016 42.96 0.084 ;
     RECT  42.984 0.016 43.392 0.084 ;
     RECT  43.416 0.016 43.824 0.084 ;
     RECT  43.848 0.016 44.256 0.084 ;
     RECT  44.28 0.016 44.688 0.084 ;
     RECT  44.712 0.016 45.12 0.084 ;
     RECT  45.144 0.016 45.552 0.084 ;
     RECT  45.576 0.016 45.984 0.084 ;
     RECT  46.008 0.016 46.416 0.084 ;
     RECT  46.44 0.016 46.848 0.084 ;
     RECT  46.872 0.016 47.28 0.084 ;
     RECT  47.304 0.016 47.712 0.084 ;
     RECT  47.736 0.016 48.144 0.084 ;
     RECT  48.168 0.016 48.576 0.084 ;
     RECT  48.6 0.016 49.008 0.084 ;
     RECT  49.032 0.016 49.44 0.084 ;
     RECT  49.464 0.016 49.872 0.084 ;
     RECT  49.896 0.016 50.304 0.084 ;
     RECT  50.328 0.016 50.736 0.084 ;
     RECT  50.76 0.016 51.168 0.084 ;
     RECT  51.192 0.016 51.6 0.084 ;
     RECT  51.624 0.016 52.032 0.084 ;
     RECT  52.056 0.016 52.464 0.084 ;
     RECT  52.488 0.016 52.896 0.084 ;
     RECT  52.92 0.016 53.328 0.084 ;
     RECT  53.352 0.016 53.76 0.084 ;
     RECT  53.784 0.016 54.192 0.084 ;
     RECT  54.216 0.016 54.624 0.084 ;
     RECT  54.648 0.016 55.056 0.084 ;
     RECT  55.08 0.016 55.488 0.084 ;
     RECT  55.512 0.016 55.92 0.084 ;
     RECT  55.944 0.016 56.352 0.084 ;
     RECT  56.376 0.016 56.784 0.084 ;
     RECT  56.808 0.016 57.216 0.084 ;
     RECT  57.24 0.016 57.648 0.084 ;
     RECT  57.672 0.016 58.08 0.084 ;
     RECT  58.104 0.016 58.512 0.084 ;
     RECT  58.536 0.016 58.944 0.084 ;
     RECT  58.968 0.016 59.376 0.084 ;
     RECT  59.4 0.016 59.808 0.084 ;
     RECT  59.832 0.016 60.24 0.084 ;
     RECT  60.264 0.016 60.672 0.084 ;
     RECT  60.696 0.016 61.104 0.084 ;
     RECT  61.128 0.016 61.536 0.084 ;
     RECT  61.56 0.016 61.968 0.084 ;
     RECT  61.992 0.016 62.4 0.084 ;
     RECT  62.424 0.016 62.832 0.084 ;
     RECT  62.856 0.016 63.264 0.084 ;
     RECT  63.288 0.016 63.696 0.084 ;
     RECT  63.72 0.016 64.128 0.084 ;
     RECT  64.152 0.016 64.56 0.084 ;
     RECT  64.584 0.016 64.992 0.084 ;
     RECT  65.016 0.016 65.424 0.084 ;
     RECT  65.448 0.016 65.856 0.084 ;
     RECT  65.88 0.016 66.288 0.084 ;
     RECT  66.312 0.016 66.72 0.084 ;
     RECT  66.744 0.016 67.152 0.084 ;
     RECT  67.176 0.016 67.584 0.084 ;
     RECT  67.608 0.016 68.016 0.084 ;
     RECT  68.04 0.016 68.448 0.084 ;
     RECT  68.472 0.016 68.88 0.084 ;
     RECT  68.904 0.016 69.312 0.084 ;
     RECT  69.336 0.016 69.744 0.084 ;
     RECT  69.768 0.016 70.176 0.084 ;
     RECT  70.2 0.016 70.608 0.084 ;
     RECT  70.632 0.016 71.04 0.084 ;
     RECT  71.064 0.016 71.472 0.084 ;
     RECT  71.496 0.016 71.904 0.084 ;
     RECT  71.928 0.016 72.336 0.084 ;
     RECT  72.36 0.016 72.768 0.084 ;
     RECT  72.792 0.016 73.2 0.084 ;
     RECT  73.224 0.016 73.632 0.084 ;
     RECT  73.656 0.016 74.064 0.084 ;
     RECT  74.088 0.016 74.496 0.084 ;
     RECT  74.52 0.016 74.928 0.084 ;
     RECT  74.952 0.016 75.36 0.084 ;
     RECT  75.384 0.016 75.792 0.084 ;
     RECT  75.816 0.016 76.224 0.084 ;
     RECT  76.248 0.016 76.656 0.084 ;
     RECT  76.68 0.016 77.088 0.084 ;
     RECT  77.112 0.016 77.52 0.084 ;
     RECT  77.544 0.016 77.952 0.084 ;
     RECT  77.976 0.016 78.384 0.084 ;
     RECT  78.408 0.016 78.816 0.084 ;
     RECT  78.84 0.016 79.248 0.084 ;
     RECT  79.272 0.016 79.68 0.084 ;
     RECT  79.704 0.016 80.112 0.084 ;
     RECT  80.136 0.016 80.544 0.084 ;
     RECT  80.568 0.016 80.976 0.084 ;
     RECT  81 0.016 81.408 0.084 ;
     RECT  81.432 0.016 81.84 0.084 ;
     RECT  81.864 0.016 82.272 0.084 ;
     RECT  82.296 0.016 82.704 0.084 ;
     RECT  82.728 0.016 83.136 0.084 ;
     RECT  83.16 0.016 83.568 0.084 ;
     RECT  83.592 0.016 84 0.084 ;
     RECT  84.024 0.016 84.432 0.084 ;
     RECT  84.456 0.016 84.864 0.084 ;
     RECT  84.888 0.016 85.296 0.084 ;
     RECT  85.32 0.016 85.728 0.084 ;
     RECT  85.752 0.016 86.16 0.084 ;
     RECT  0.192 0.084 86.184 0.131 ;
     RECT  0.288 0.131 7.992 0.179 ;
     RECT  13.152 0.131 13.176 0.179 ;
     RECT  45.984 0.131 47.304 0.179 ;
     RECT  48.576 0.131 51.192 0.179 ;
     RECT  54.624 0.131 54.648 0.179 ;
     RECT  69.744 0.131 71.496 0.179 ;
     RECT  48.576 0.179 48.6 0.227 ;
     RECT  50.304 0.179 50.328 0.275 ;
     RECT  17.904 0.131 17.928 0.563 ;
     RECT  20.496 0.131 20.52 0.563 ;
     RECT  23.088 0.131 24.408 0.563 ;
     RECT  34.752 0.131 34.776 0.563 ;
     RECT  40.368 0.131 40.824 0.563 ;
     RECT  46.416 0.179 46.44 0.563 ;
     RECT  52.464 0.131 52.488 0.563 ;
     RECT  55.92 0.131 56.376 0.563 ;
     RECT  58.08 0.131 58.104 0.563 ;
     RECT  70.608 0.179 71.496 0.563 ;
     RECT  72.768 0.131 72.792 0.563 ;
     RECT  74.496 0.131 74.952 0.563 ;
     RECT  76.656 0.131 77.976 0.563 ;
     RECT  81.408 0.131 82.296 0.563 ;
     RECT  83.568 0.131 84.456 0.563 ;
     RECT  85.728 0.131 86.184 0.563 ;
     RECT  5.808 0.179 7.992 0.611 ;
     RECT  1.488 0.179 4.536 1.763 ;
     RECT  6.672 0.611 6.696 1.763 ;
     RECT  19.2 0.131 19.224 1.763 ;
     RECT  21.792 0.131 21.816 1.763 ;
     RECT  23.52 0.563 23.544 1.763 ;
     RECT  26.976 0.131 27 1.763 ;
     RECT  28.704 0.131 28.728 1.763 ;
     RECT  31.728 0.131 33.48 1.763 ;
     RECT  36.912 0.131 36.936 1.763 ;
     RECT  38.64 0.131 38.664 1.763 ;
     RECT  42.096 0.131 42.12 1.763 ;
     RECT  55.92 0.563 55.944 1.763 ;
     RECT  61.104 0.131 61.128 1.763 ;
     RECT  62.832 0.131 62.856 1.763 ;
     RECT  66.288 0.131 66.312 1.763 ;
     RECT  68.016 0.131 68.04 1.763 ;
     RECT  71.472 0.563 71.496 1.763 ;
     RECT  74.928 0.563 74.952 1.763 ;
     RECT  76.656 0.563 77.544 1.763 ;
     RECT  81.408 0.563 81.432 1.763 ;
     RECT  40.368 0.563 40.392 2.137 ;
     RECT  84 0.563 84.024 2.137 ;
     RECT  7.8 2.137 7.92 2.151 ;
     RECT  13.2 2.137 13.32 2.151 ;
     RECT  24 2.137 24.12 2.151 ;
     RECT  29.4 2.137 29.52 2.151 ;
     RECT  34.8 2.137 34.92 2.151 ;
     RECT  40.2 2.137 40.392 2.151 ;
     RECT  45.6 2.137 45.72 2.151 ;
     RECT  51 2.137 51.12 2.151 ;
     RECT  56.4 2.137 56.52 2.151 ;
     RECT  72.6 2.137 72.72 2.151 ;
     RECT  78 2.137 78.12 2.151 ;
     RECT  33.456 1.763 33.48 2.195 ;
     RECT  2.304 1.763 3.672 2.339 ;
     RECT  83.4 2.137 84.024 2.339 ;
     RECT  0.288 0.179 0.312 2.437 ;
     RECT  83.4 2.339 83.712 2.821 ;
     RECT  18.6 2.137 18.912 3.397 ;
     RECT  48.24 3.301 48.264 3.397 ;
     RECT  18.096 3.397 19.272 3.539 ;
     RECT  18.6 3.539 19.272 3.923 ;
     RECT  13.2 2.151 13.512 3.925 ;
     RECT  14.496 3.829 14.52 3.925 ;
     RECT  13.2 3.925 14.52 3.971 ;
     RECT  2.304 2.339 2.712 4.019 ;
     RECT  58.704 3.349 58.728 4.019 ;
     RECT  34.8 2.151 35.112 4.021 ;
     RECT  45.6 2.151 45.912 4.021 ;
     RECT  36.768 3.301 36.792 4.067 ;
     RECT  26.16 3.349 26.184 4.069 ;
     RECT  24 2.151 24.312 4.117 ;
     RECT  29.4 2.151 29.712 4.117 ;
     RECT  44.544 3.349 44.568 4.117 ;
     RECT  45.6 4.021 46.008 4.165 ;
     RECT  26.16 4.069 26.856 4.259 ;
     RECT  7.8 2.151 8.112 4.261 ;
     RECT  38.736 4.021 38.76 4.307 ;
     RECT  48.24 3.397 48.456 4.501 ;
     RECT  41.856 4.213 42.792 4.547 ;
     RECT  13.2 3.971 14.328 4.595 ;
     RECT  38.688 4.357 38.712 4.595 ;
     RECT  44.4 4.117 44.568 4.643 ;
     RECT  45.6 4.165 46.104 4.693 ;
     RECT  5.136 4.645 5.688 4.741 ;
     RECT  26.16 4.259 26.808 4.741 ;
     RECT  25.872 4.741 26.808 4.837 ;
     RECT  21.744 4.261 21.768 4.885 ;
     RECT  45.6 4.693 46.152 4.885 ;
     RECT  48.192 4.501 48.456 4.885 ;
     RECT  48.192 4.885 48.792 5.029 ;
     RECT  5.136 4.741 6.168 5.171 ;
     RECT  23.76 4.117 24.312 5.171 ;
     RECT  48.192 5.029 49.032 5.171 ;
     RECT  0.192 2.437 0.312 5.219 ;
     RECT  36.768 5.077 36.792 5.219 ;
     RECT  34.8 4.021 35.208 5.269 ;
     RECT  25.632 4.837 26.808 5.315 ;
     RECT  29.136 4.117 29.712 5.315 ;
     RECT  29.4 5.315 29.712 5.701 ;
     RECT  7.392 4.261 8.112 5.747 ;
     RECT  48.192 5.171 48.792 5.747 ;
     RECT  83.28 2.821 83.712 5.747 ;
     RECT  25.632 5.315 26.664 5.845 ;
     RECT  48.432 5.747 48.792 5.987 ;
     RECT  24 5.171 24.312 5.989 ;
     RECT  25.344 5.845 26.664 5.989 ;
     RECT  24 5.989 26.664 6.035 ;
     RECT  75.744 4.117 75.768 6.083 ;
     RECT  48.768 5.987 48.792 6.275 ;
     RECT  44.832 4.885 46.152 6.323 ;
     RECT  33.648 4.453 33.672 7.043 ;
     RECT  38.736 6.229 38.76 7.043 ;
     RECT  24 6.035 26.184 7.475 ;
     RECT  32.496 4.453 32.52 7.619 ;
     RECT  29.4 5.701 30.12 7.765 ;
     RECT  34.8 5.269 35.352 7.957 ;
     RECT  44.832 6.323 45.912 8.245 ;
     RECT  29.4 7.765 30.216 8.437 ;
     RECT  34.224 7.957 35.352 8.579 ;
     RECT  34.224 8.579 35.112 8.963 ;
     RECT  29.4 8.437 30.504 9.011 ;
     RECT  24 7.475 25.368 9.107 ;
     RECT  25.344 9.107 25.368 9.155 ;
     RECT  41.856 4.547 41.88 9.155 ;
     RECT  36.384 7.957 36.408 9.203 ;
     RECT  24 9.107 24.312 9.637 ;
     RECT  29.4 9.011 30.36 10.307 ;
     RECT  21.456 4.885 21.768 10.355 ;
     RECT  29.4 10.307 30.216 10.547 ;
     RECT  5.376 5.171 6.168 10.595 ;
     RECT  40.2 2.151 40.512 10.597 ;
     RECT  23.904 9.637 24.312 10.739 ;
     RECT  18.6 3.923 18.912 10.741 ;
     RECT  32.4 9.109 32.424 11.317 ;
     RECT  39.936 10.597 40.512 11.797 ;
     RECT  29.4 10.547 29.712 11.941 ;
     RECT  34.8 8.963 35.112 11.941 ;
     RECT  18.6 10.741 19.704 11.987 ;
     RECT  32.4 11.317 33.048 11.987 ;
     RECT  5.52 10.595 6.168 12.373 ;
     RECT  7.8 5.747 8.112 12.373 ;
     RECT  5.52 12.373 8.112 12.467 ;
     RECT  24 10.739 24.312 12.469 ;
     RECT  29.4 11.941 30.264 12.469 ;
     RECT  18.6 11.987 18.912 12.517 ;
     RECT  39.888 11.797 40.512 12.563 ;
     RECT  40.2 12.563 40.512 12.757 ;
     RECT  13.2 4.595 13.512 13.093 ;
     RECT  14.928 12.517 14.952 13.093 ;
     RECT  13.2 13.093 15.384 13.139 ;
     RECT  23.664 12.469 24.312 13.139 ;
     RECT  32.4 11.987 32.52 13.139 ;
     RECT  29.4 12.469 30.696 13.283 ;
     RECT  13.2 13.139 14.184 13.573 ;
     RECT  21.456 10.355 21.48 13.573 ;
     RECT  12.768 13.573 14.184 13.811 ;
     RECT  21.456 13.573 21.96 14.197 ;
     RECT  29.4 13.283 29.712 14.245 ;
     RECT  15.36 13.139 15.384 14.291 ;
     RECT  21.456 14.197 22.2 14.867 ;
     RECT  34.8 11.941 36.024 14.915 ;
     RECT  25.536 11.941 25.56 15.059 ;
     RECT  29.28 14.245 29.712 15.061 ;
     RECT  32.4 13.139 32.424 15.203 ;
     RECT  17.616 12.517 18.912 15.299 ;
     RECT  21.456 14.867 21.48 15.395 ;
     RECT  34.8 14.915 35.592 15.683 ;
     RECT  28.512 15.061 29.712 15.973 ;
     RECT  12.768 13.811 13.512 16.019 ;
     RECT  23.904 13.139 24.312 16.115 ;
     RECT  10.848 15.061 10.872 16.307 ;
     RECT  33.6 14.533 33.624 16.835 ;
     RECT  27.744 15.973 29.712 16.933 ;
     RECT  14.784 16.501 14.808 17.077 ;
     RECT  27.744 16.933 30.504 17.507 ;
     RECT  27.744 17.507 29.712 17.603 ;
     RECT  6.144 12.467 8.112 17.605 ;
     RECT  25.68 16.405 25.704 17.605 ;
     RECT  5.28 17.605 8.112 17.891 ;
     RECT  25.68 17.605 26.232 18.083 ;
     RECT  10.224 17.605 10.248 18.133 ;
     RECT  7.8 17.891 8.112 18.565 ;
     RECT  9.504 18.133 10.248 18.565 ;
     RECT  5.28 17.891 6.168 18.851 ;
     RECT  25.68 18.083 25.704 18.851 ;
     RECT  30.768 18.757 30.792 18.995 ;
     RECT  24 16.115 24.312 19.141 ;
     RECT  13.2 16.019 13.512 19.333 ;
     RECT  18.6 15.299 18.912 19.333 ;
     RECT  14.544 17.077 15.288 19.379 ;
     RECT  7.8 18.565 10.248 19.523 ;
     RECT  11.472 18.661 11.496 19.811 ;
     RECT  9.504 19.523 10.248 20.003 ;
     RECT  21.456 18.757 21.48 20.003 ;
     RECT  28.512 17.603 29.712 20.243 ;
     RECT  17.088 19.333 17.112 20.531 ;
     RECT  13.104 19.333 13.512 20.579 ;
     RECT  10.224 20.003 10.248 21.155 ;
     RECT  14.544 19.379 14.568 21.301 ;
     RECT  18.6 19.333 19.08 21.637 ;
     RECT  20.16 15.253 20.184 21.637 ;
     RECT  28.704 20.243 29.712 21.637 ;
     RECT  5.136 19.909 5.16 21.683 ;
     RECT  18.6 21.637 20.184 21.683 ;
     RECT  23.328 19.141 24.312 21.683 ;
     RECT  40.2 12.757 41.256 21.683 ;
     RECT  14.544 21.301 14.904 21.971 ;
     RECT  40.2 21.683 40.512 22.165 ;
     RECT  6.144 18.851 6.168 22.741 ;
     RECT  24 21.683 24.312 22.741 ;
     RECT  21.888 21.637 21.912 22.787 ;
     RECT  25.632 21.109 25.656 22.835 ;
     RECT  28.608 21.637 29.712 22.835 ;
     RECT  17.28 22.165 17.304 22.979 ;
     RECT  13.2 20.579 13.512 23.317 ;
     RECT  5.952 22.741 6.168 23.411 ;
     RECT  24 22.741 24.552 23.699 ;
     RECT  14.88 21.971 14.904 23.845 ;
     RECT  18.6 21.683 19.752 23.893 ;
     RECT  6.144 23.411 6.168 24.469 ;
     RECT  34.8 15.683 35.112 24.517 ;
     RECT  12.864 23.317 13.512 24.659 ;
     RECT  34.8 24.517 35.256 24.947 ;
     RECT  26.736 24.325 26.76 25.139 ;
     RECT  18.192 23.893 19.752 25.187 ;
     RECT  6.144 24.469 6.792 25.619 ;
     RECT  18.192 25.187 19.08 25.619 ;
     RECT  14.832 23.845 14.904 25.715 ;
     RECT  28.704 22.835 29.712 25.763 ;
     RECT  14.88 25.715 14.904 25.861 ;
     RECT  39.696 22.165 40.512 25.861 ;
     RECT  14.88 25.861 15.384 25.907 ;
     RECT  28.992 25.763 29.712 26.197 ;
     RECT  37.056 25.957 37.08 26.197 ;
     RECT  21.648 25.045 21.672 26.243 ;
     RECT  28.992 26.197 30.264 26.531 ;
     RECT  38.784 25.861 40.512 26.629 ;
     RECT  7.8 19.523 8.112 26.725 ;
     RECT  29.4 26.531 30.264 26.819 ;
     RECT  31.584 25.333 31.608 26.819 ;
     RECT  36.672 26.197 37.08 26.867 ;
     RECT  9.648 25.045 9.672 27.061 ;
     RECT  38.736 26.629 40.512 27.061 ;
     RECT  9.648 27.061 9.768 27.107 ;
     RECT  13.2 24.659 13.512 27.301 ;
     RECT  15.36 25.907 15.384 27.301 ;
     RECT  44.784 8.245 45.912 27.301 ;
     RECT  5.088 26.245 5.112 27.395 ;
     RECT  7.536 26.725 8.112 27.395 ;
     RECT  44.784 27.301 46.392 27.635 ;
     RECT  12.048 26.725 12.072 27.829 ;
     RECT  11.376 27.829 12.072 27.875 ;
     RECT  13.056 27.301 13.512 27.925 ;
     RECT  15.36 27.301 15.672 27.971 ;
     RECT  9.744 27.107 9.768 28.163 ;
     RECT  18.6 25.619 19.08 28.213 ;
     RECT  2.4 4.019 2.712 28.261 ;
     RECT  15.648 27.971 15.672 28.451 ;
     RECT  18.6 28.213 19.368 28.453 ;
     RECT  6.144 25.619 6.168 28.789 ;
     RECT  13.056 27.925 13.992 28.979 ;
     RECT  38.352 27.061 40.512 28.979 ;
     RECT  13.2 28.979 13.992 29.219 ;
     RECT  11.376 27.875 11.4 29.461 ;
     RECT  10.848 29.461 11.4 29.507 ;
     RECT  2.4 28.261 3.432 29.651 ;
     RECT  6.144 28.789 6.36 30.227 ;
     RECT  39.696 28.979 40.512 30.229 ;
     RECT  17.712 28.453 19.368 30.275 ;
     RECT  18.6 30.275 19.368 30.467 ;
     RECT  10.848 29.507 10.872 30.611 ;
     RECT  13.2 29.219 13.512 30.805 ;
     RECT  9.696 30.373 9.72 30.853 ;
     RECT  15.36 30.229 15.384 30.899 ;
     RECT  13.2 30.805 13.752 31.667 ;
     RECT  7.8 27.395 8.112 32.053 ;
     RECT  38.352 28.979 38.376 34.259 ;
     RECT  39.6 30.229 40.512 34.741 ;
     RECT  36.672 26.867 36.696 34.931 ;
     RECT  9.696 30.853 10.536 35.123 ;
     RECT  7.8 32.053 8.232 35.363 ;
     RECT  5.088 34.789 5.112 35.987 ;
     RECT  7.8 35.363 8.112 35.989 ;
     RECT  45.6 27.635 46.392 36.371 ;
     RECT  9.696 35.123 10.248 36.515 ;
     RECT  39.6 34.741 41.016 36.563 ;
     RECT  7.68 35.989 8.112 36.997 ;
     RECT  7.68 36.997 8.808 37.091 ;
     RECT  56.4 2.151 56.712 37.573 ;
     RECT  54.576 36.997 54.6 37.667 ;
     RECT  7.8 37.091 8.808 37.859 ;
     RECT  45.6 36.371 45.912 37.861 ;
     RECT  51 2.151 51.312 38.725 ;
     RECT  45.408 37.861 45.912 38.819 ;
     RECT  56.304 37.573 56.712 38.819 ;
     RECT  61.8 2.137 62.112 39.301 ;
     RECT  54.672 39.061 54.696 40.067 ;
     RECT  61.8 39.301 62.76 40.067 ;
     RECT  67.2 2.137 67.512 40.405 ;
     RECT  51 38.725 51.816 40.787 ;
     RECT  57.984 39.253 58.008 40.835 ;
     RECT  67.2 40.405 67.704 41.221 ;
     RECT  65.904 40.693 65.928 41.509 ;
     RECT  65.904 41.509 66.024 41.555 ;
     RECT  4.128 39.877 4.152 41.651 ;
     RECT  59.952 39.637 59.976 41.701 ;
     RECT  59.952 41.701 60.456 41.747 ;
     RECT  67.2 41.221 68.088 42.803 ;
     RECT  81.456 40.405 81.48 42.803 ;
     RECT  66 41.555 66.024 43.043 ;
     RECT  0.192 5.219 0.216 43.091 ;
     RECT  56.4 38.819 56.712 43.237 ;
     RECT  51 40.787 51.48 43.283 ;
     RECT  43.92 34.885 43.944 43.285 ;
     RECT  61.8 40.067 62.112 43.285 ;
     RECT  39.6 36.563 40.512 43.331 ;
     RECT  24 23.699 24.312 43.573 ;
     RECT  43.488 43.285 43.944 43.669 ;
     RECT  70.512 41.701 70.536 43.955 ;
     RECT  60.432 41.747 60.456 44.053 ;
     RECT  61.8 43.285 62.616 44.053 ;
     RECT  78 2.151 78.312 44.053 ;
     RECT  60.432 44.053 62.616 44.099 ;
     RECT  42.816 43.669 43.944 44.341 ;
     RECT  42.816 44.341 44.424 44.387 ;
     RECT  55.44 43.237 56.712 44.387 ;
     RECT  47.856 43.285 47.88 44.435 ;
     RECT  6.144 30.227 6.168 44.437 ;
     RECT  77.136 44.053 78.312 44.627 ;
     RECT  7.8 37.859 8.112 45.445 ;
     RECT  7.488 45.445 8.112 45.541 ;
     RECT  6.144 44.437 6.216 46.019 ;
     RECT  13.2 31.667 13.512 46.117 ;
     RECT  24 43.573 25.08 46.211 ;
     RECT  7.44 45.541 8.112 46.547 ;
     RECT  12.576 46.117 13.512 46.883 ;
     RECT  19.968 45.925 19.992 47.075 ;
     RECT  7.488 46.547 8.112 47.171 ;
     RECT  14.688 46.117 14.712 47.315 ;
     RECT  4.608 43.717 4.632 47.845 ;
     RECT  60.432 44.099 62.112 48.899 ;
     RECT  24 46.211 24.408 51.395 ;
     RECT  4.608 47.845 4.92 51.827 ;
     RECT  40.2 43.331 40.512 53.557 ;
     RECT  40.2 53.557 40.776 54.565 ;
     RECT  4.8 51.827 4.92 55.045 ;
     RECT  43.488 44.387 44.424 56.003 ;
     RECT  60.528 48.899 62.112 56.101 ;
     RECT  40.2 54.565 41.016 56.675 ;
     RECT  45.6 38.819 45.912 56.869 ;
     RECT  4.56 55.045 4.92 57.059 ;
     RECT  4.56 57.059 4.584 57.587 ;
     RECT  43.488 56.003 44.28 58.163 ;
     RECT  45.6 56.869 46.776 58.547 ;
     RECT  60.432 56.101 62.112 59.605 ;
     RECT  43.488 58.163 43.512 60.131 ;
     RECT  59.52 59.605 62.112 60.419 ;
     RECT  60.528 60.419 62.112 61.139 ;
     RECT  5.088 59.797 5.112 61.477 ;
     RECT  4.128 61.477 5.112 61.523 ;
     RECT  60.528 61.139 60.696 62.149 ;
     RECT  60.528 62.149 60.744 62.195 ;
     RECT  6.144 46.019 6.168 63.205 ;
     RECT  4.128 61.523 4.152 64.357 ;
     RECT  5.28 63.205 6.168 64.357 ;
     RECT  4.128 64.357 6.168 64.403 ;
     RECT  61.8 61.139 62.112 65.509 ;
     RECT  4.992 64.403 6.168 66.325 ;
     RECT  29.4 26.819 29.712 66.469 ;
     RECT  4.656 66.325 6.168 67.669 ;
     RECT  4.56 67.669 6.168 69.011 ;
     RECT  40.2 56.675 40.728 70.835 ;
     RECT  5.28 69.011 6.168 71.221 ;
     RECT  60.672 62.195 60.744 71.317 ;
     RECT  38.688 70.645 38.712 71.363 ;
     RECT  60.528 71.317 60.744 71.363 ;
     RECT  60.528 71.363 60.696 71.939 ;
     RECT  65.376 66.661 65.4 72.325 ;
     RECT  44.256 71.797 44.28 72.947 ;
     RECT  5.28 71.221 6.312 73.043 ;
     RECT  51 43.283 51.312 73.333 ;
     RECT  59.52 60.419 59.544 73.379 ;
     RECT  47.136 72.805 47.16 73.523 ;
     RECT  50.88 73.333 51.312 73.523 ;
     RECT  61.8 65.509 62.952 74.579 ;
     RECT  65.184 72.325 65.4 74.723 ;
     RECT  60.528 71.939 60.552 75.299 ;
     RECT  65.184 74.723 65.208 75.781 ;
     RECT  34.8 24.947 35.112 75.973 ;
     RECT  80.304 26.197 80.328 76.117 ;
     RECT  4.224 72.997 4.248 76.165 ;
     RECT  5.28 73.043 6.168 76.165 ;
     RECT  4.224 76.165 6.168 76.211 ;
     RECT  24 51.395 24.312 76.309 ;
     RECT  64.512 75.781 65.208 76.357 ;
     RECT  78 44.627 78.312 76.357 ;
     RECT  64.176 76.357 65.208 76.403 ;
     RECT  26.256 76.309 26.28 76.979 ;
     RECT  33.84 75.973 35.112 76.979 ;
     RECT  78 76.357 78.936 77.555 ;
     RECT  82.128 74.053 82.152 77.555 ;
     RECT  36.576 70.933 36.6 77.939 ;
     RECT  40.2 70.835 40.512 78.037 ;
     RECT  80.208 76.117 80.328 78.037 ;
     RECT  39.936 78.037 40.512 78.707 ;
     RECT  76.08 78.613 76.104 78.709 ;
     RECT  78 77.555 78.312 78.709 ;
     RECT  81.6 78.613 81.624 79.045 ;
     RECT  7.8 47.171 8.112 79.429 ;
     RECT  74.928 29.029 74.952 79.525 ;
     RECT  76.08 78.709 78.312 79.525 ;
     RECT  4.512 76.211 6.168 79.715 ;
     RECT  74.928 79.525 78.312 79.717 ;
     RECT  80.208 78.037 80.424 79.717 ;
     RECT  74.88 79.717 78.312 79.811 ;
     RECT  24 76.309 24.84 79.955 ;
     RECT  36.672 78.037 36.696 79.957 ;
     RECT  18.6 30.467 18.912 80.053 ;
     RECT  74.88 79.811 75.768 80.099 ;
     RECT  77.04 79.811 78.312 80.099 ;
     RECT  79.632 79.717 80.424 80.099 ;
     RECT  40.2 78.707 40.512 80.149 ;
     RECT  2.4 29.651 2.712 80.341 ;
     RECT  79.632 80.099 80.328 80.435 ;
     RECT  36.672 79.957 36.744 80.483 ;
     RECT  72.6 2.151 72.912 80.581 ;
     RECT  64.176 76.403 64.2 80.773 ;
     RECT  65.184 76.403 65.208 80.773 ;
     RECT  29.136 66.469 29.712 80.819 ;
     RECT  64.176 80.773 65.208 80.819 ;
     RECT  74.88 80.099 75.288 80.819 ;
     RECT  31.104 75.973 31.128 80.963 ;
     RECT  17.664 80.053 18.912 81.011 ;
     RECT  51 73.523 51.312 81.157 ;
     RECT  61.8 74.579 62.472 81.157 ;
     RECT  2.4 80.341 2.904 81.203 ;
     RECT  21.552 76.885 21.576 81.203 ;
     RECT  81.6 79.045 82.056 81.203 ;
     RECT  5.28 79.715 6.168 81.299 ;
     RECT  64.176 80.819 65.016 81.347 ;
     RECT  56.4 44.387 56.712 81.349 ;
     RECT  26.016 81.301 26.04 81.397 ;
     RECT  22.896 80.341 22.92 81.539 ;
     RECT  47.28 81.061 47.304 81.539 ;
     RECT  74.928 80.819 75.288 81.587 ;
     RECT  61.152 81.157 62.472 81.637 ;
     RECT  5.28 81.299 5.304 81.683 ;
     RECT  7.8 79.429 8.856 81.875 ;
     RECT  36.672 80.483 36.696 81.875 ;
     RECT  72.6 80.581 73.128 81.875 ;
     RECT  2.4 81.203 2.808 81.877 ;
     RECT  26.016 81.397 26.232 81.877 ;
     RECT  74.928 81.587 75.24 81.923 ;
     RECT  80.208 80.435 80.328 81.923 ;
     RECT  65.904 81.877 65.928 82.019 ;
     RECT  26.016 81.877 26.808 82.021 ;
     RECT  69.504 80.725 69.528 82.115 ;
     RECT  72.6 81.875 73.032 82.115 ;
     RECT  80.304 81.923 80.328 82.115 ;
     RECT  61.152 81.637 62.76 82.163 ;
     RECT  64.176 81.347 64.2 82.163 ;
     RECT  26.016 82.021 26.856 82.259 ;
     RECT  29.4 80.819 29.712 82.309 ;
     RECT  24 79.955 24.312 82.357 ;
     RECT  26.832 82.259 26.856 82.403 ;
     RECT  71.136 80.917 71.16 82.403 ;
     RECT  29.4 82.309 30.12 82.451 ;
     RECT  40.2 80.149 41.496 82.451 ;
     RECT  33.312 82.405 33.336 82.501 ;
     RECT  67.2 42.803 67.512 82.501 ;
     RECT  23.376 82.357 24.312 82.547 ;
     RECT  25.344 82.357 25.368 82.547 ;
     RECT  54.72 81.349 56.712 82.547 ;
     RECT  28.272 82.453 28.296 82.595 ;
     RECT  18.6 81.011 18.912 82.597 ;
     RECT  33.312 82.501 33.624 82.643 ;
     RECT  66.912 82.501 67.512 82.643 ;
     RECT  11.232 81.157 11.256 82.691 ;
     RECT  50.736 81.157 51.312 82.691 ;
     RECT  55.632 82.547 56.712 82.691 ;
     RECT  20.304 81.973 20.328 82.693 ;
     RECT  24 82.547 24.312 82.693 ;
     RECT  45.6 58.547 45.912 82.693 ;
     RECT  30.768 82.597 30.792 82.739 ;
     RECT  29.4 82.451 29.712 82.789 ;
     RECT  24 82.693 25.176 82.835 ;
     RECT  43.632 81.445 43.656 82.835 ;
     RECT  44.88 82.693 45.912 82.835 ;
     RECT  45.6 82.835 45.912 82.837 ;
     RECT  61.8 82.163 62.76 82.883 ;
     RECT  20.304 82.693 21.144 82.931 ;
     RECT  29.184 82.789 29.712 82.931 ;
     RECT  45.6 82.837 46.776 83.027 ;
     RECT  0.288 81.445 0.312 83.029 ;
     RECT  18.48 82.597 18.912 83.075 ;
     RECT  20.304 82.931 20.328 83.171 ;
     RECT  78 80.099 78.312 83.317 ;
     RECT  74.928 81.923 74.952 83.363 ;
     RECT  78 83.317 78.408 83.507 ;
     RECT  2.112 81.877 2.808 83.555 ;
     RECT  82.224 82.021 82.248 83.797 ;
     RECT  83.4 5.747 83.712 83.797 ;
     RECT  2.112 83.555 2.712 84.249 ;
     RECT  13.2 46.883 13.512 84.249 ;
     RECT  29.4 82.931 29.712 84.249 ;
     RECT  40.2 82.451 40.512 84.249 ;
     RECT  45.6 83.027 45.912 84.249 ;
     RECT  51 82.691 51.312 84.249 ;
     RECT  56.4 82.691 56.712 84.249 ;
     RECT  61.8 82.883 62.112 84.249 ;
     RECT  67.2 82.643 67.512 84.249 ;
     RECT  2.112 84.249 2.52 84.263 ;
     RECT  7.8 81.875 8.112 84.263 ;
     RECT  13.2 84.249 13.32 84.263 ;
     RECT  18.6 83.075 18.912 84.263 ;
     RECT  24 82.835 24.312 84.263 ;
     RECT  29.4 84.249 29.52 84.263 ;
     RECT  34.8 76.979 35.112 84.263 ;
     RECT  40.2 84.249 40.32 84.263 ;
     RECT  45.6 84.249 45.72 84.263 ;
     RECT  51 84.249 51.12 84.263 ;
     RECT  56.4 84.249 56.52 84.263 ;
     RECT  61.8 84.249 61.92 84.263 ;
     RECT  67.2 84.249 67.32 84.263 ;
     RECT  72.6 82.115 72.912 84.263 ;
     RECT  78 83.507 78.312 84.263 ;
     RECT  82.224 83.797 83.712 84.325 ;
     RECT  16.512 84.325 16.536 84.901 ;
     RECT  21.888 84.373 22.536 84.901 ;
     RECT  24.288 84.263 24.312 84.901 ;
     RECT  26.112 84.325 26.136 84.901 ;
     RECT  66.288 84.373 66.312 84.901 ;
     RECT  2.112 84.263 2.136 85.477 ;
     RECT  12.288 84.373 12.312 85.477 ;
     RECT  18.912 84.901 18.936 85.477 ;
     RECT  21.888 84.901 23.112 85.477 ;
     RECT  24.288 84.901 26.712 85.477 ;
     RECT  27.888 84.901 27.912 85.477 ;
     RECT  39.888 84.901 39.912 85.477 ;
     RECT  41.712 84.901 41.736 85.477 ;
     RECT  42.912 84.901 42.936 85.477 ;
     RECT  44.112 84.901 44.712 85.477 ;
     RECT  54.288 84.901 56.136 85.477 ;
     RECT  57.888 84.901 57.912 85.477 ;
     RECT  64.512 84.901 64.536 85.477 ;
     RECT  65.712 84.901 66.312 85.477 ;
     RECT  73.488 84.901 73.512 85.477 ;
     RECT  79.488 84.901 79.512 85.477 ;
     RECT  80.688 85.429 80.712 85.477 ;
     RECT  39.888 85.477 42.936 86.005 ;
     RECT  44.112 85.477 45.336 86.005 ;
     RECT  20.688 84.373 20.712 86.197 ;
     RECT  0.288 83.029 0.936 86.245 ;
     RECT  2.112 85.477 2.712 86.245 ;
     RECT  3.888 85.477 3.912 86.245 ;
     RECT  5.088 84.373 5.112 86.245 ;
     RECT  6.912 85.477 6.936 86.245 ;
     RECT  8.112 84.901 8.136 86.245 ;
     RECT  9.312 84.373 9.336 86.245 ;
     RECT  10.512 84.901 10.536 86.245 ;
     RECT  11.712 85.477 12.312 86.245 ;
     RECT  15.312 84.373 15.336 86.245 ;
     RECT  16.512 84.901 17.112 86.245 ;
     RECT  18.288 85.477 18.936 86.245 ;
     RECT  20.112 86.197 20.712 86.245 ;
     RECT  21.888 85.477 26.712 86.245 ;
     RECT  27.888 85.477 28.536 86.245 ;
     RECT  29.712 85.477 29.736 86.245 ;
     RECT  31.488 85.477 31.512 86.245 ;
     RECT  33.312 84.373 33.912 86.245 ;
     RECT  35.712 84.373 35.736 86.245 ;
     RECT  37.488 86.005 37.512 86.245 ;
     RECT  39.888 86.005 45.336 86.245 ;
     RECT  47.712 84.325 47.736 86.245 ;
     RECT  49.488 86.197 49.512 86.245 ;
     RECT  53.712 85.477 56.136 86.245 ;
     RECT  57.888 85.477 58.536 86.245 ;
     RECT  59.712 86.197 59.736 86.245 ;
     RECT  60.912 85.957 60.936 86.245 ;
     RECT  62.112 85.957 62.136 86.245 ;
     RECT  64.512 85.477 66.312 86.245 ;
     RECT  68.688 84.325 68.712 86.245 ;
     RECT  72.912 85.477 73.512 86.245 ;
     RECT  75.888 86.005 75.912 86.245 ;
     RECT  78.288 84.263 78.312 86.245 ;
     RECT  79.488 85.477 80.712 86.245 ;
     RECT  81.888 84.325 83.736 86.245 ;
     RECT  84.912 85.477 84.936 86.245 ;
     RECT  0.288 86.245 86.136 86.316 ;
     RECT  0.312 86.316 0.912 86.352 ;
     RECT  0.936 86.316 1.488 86.352 ;
     RECT  1.512 86.316 2.112 86.352 ;
     RECT  2.136 86.316 2.688 86.352 ;
     RECT  2.712 86.316 3.312 86.352 ;
     RECT  3.336 86.316 3.888 86.352 ;
     RECT  3.912 86.316 4.512 86.352 ;
     RECT  4.536 86.316 5.088 86.352 ;
     RECT  5.112 86.316 5.712 86.352 ;
     RECT  5.736 86.316 6.288 86.352 ;
     RECT  6.312 86.316 6.912 86.352 ;
     RECT  6.936 86.316 7.488 86.352 ;
     RECT  7.512 86.316 8.112 86.352 ;
     RECT  8.136 86.316 8.688 86.352 ;
     RECT  8.712 86.316 9.312 86.352 ;
     RECT  9.336 86.316 9.888 86.352 ;
     RECT  9.912 86.316 10.512 86.352 ;
     RECT  10.536 86.316 11.088 86.352 ;
     RECT  11.112 86.316 11.712 86.352 ;
     RECT  11.736 86.316 12.288 86.352 ;
     RECT  12.312 86.316 12.912 86.352 ;
     RECT  12.936 86.316 13.488 86.352 ;
     RECT  13.512 86.316 14.112 86.352 ;
     RECT  14.136 86.316 14.688 86.352 ;
     RECT  14.712 86.316 15.312 86.352 ;
     RECT  15.336 86.316 15.888 86.352 ;
     RECT  15.912 86.316 16.512 86.352 ;
     RECT  16.536 86.316 17.088 86.352 ;
     RECT  17.112 86.316 17.712 86.352 ;
     RECT  17.736 86.316 18.288 86.352 ;
     RECT  18.312 86.316 18.912 86.352 ;
     RECT  18.936 86.316 19.488 86.352 ;
     RECT  19.512 86.316 20.112 86.352 ;
     RECT  20.136 86.316 20.688 86.352 ;
     RECT  20.712 86.316 21.312 86.352 ;
     RECT  21.336 86.316 21.888 86.352 ;
     RECT  21.912 86.316 22.512 86.352 ;
     RECT  22.536 86.316 23.088 86.352 ;
     RECT  23.112 86.316 23.712 86.352 ;
     RECT  23.736 86.316 24.288 86.352 ;
     RECT  24.312 86.316 24.912 86.352 ;
     RECT  24.936 86.316 25.488 86.352 ;
     RECT  25.512 86.316 26.112 86.352 ;
     RECT  26.136 86.316 26.688 86.352 ;
     RECT  26.712 86.316 27.312 86.352 ;
     RECT  27.336 86.316 27.888 86.352 ;
     RECT  27.912 86.316 28.512 86.352 ;
     RECT  28.536 86.316 29.088 86.352 ;
     RECT  29.112 86.316 29.712 86.352 ;
     RECT  29.736 86.316 30.288 86.352 ;
     RECT  30.312 86.316 30.912 86.352 ;
     RECT  30.936 86.316 31.488 86.352 ;
     RECT  31.512 86.316 32.112 86.352 ;
     RECT  32.136 86.316 32.688 86.352 ;
     RECT  32.712 86.316 33.312 86.352 ;
     RECT  33.336 86.316 33.888 86.352 ;
     RECT  33.912 86.316 34.512 86.352 ;
     RECT  34.536 86.316 35.088 86.352 ;
     RECT  35.112 86.316 35.712 86.352 ;
     RECT  35.736 86.316 36.288 86.352 ;
     RECT  36.312 86.316 36.912 86.352 ;
     RECT  36.936 86.316 37.488 86.352 ;
     RECT  37.512 86.316 38.112 86.352 ;
     RECT  38.136 86.316 38.688 86.352 ;
     RECT  38.712 86.316 39.312 86.352 ;
     RECT  39.336 86.316 39.888 86.352 ;
     RECT  39.912 86.316 40.512 86.352 ;
     RECT  40.536 86.316 41.088 86.352 ;
     RECT  41.112 86.316 41.712 86.352 ;
     RECT  41.736 86.316 42.288 86.352 ;
     RECT  42.312 86.316 42.912 86.352 ;
     RECT  42.936 86.316 43.488 86.352 ;
     RECT  43.512 86.316 44.112 86.352 ;
     RECT  44.136 86.316 44.688 86.352 ;
     RECT  44.712 86.316 45.312 86.352 ;
     RECT  45.336 86.316 45.888 86.352 ;
     RECT  45.912 86.316 46.512 86.352 ;
     RECT  46.536 86.316 47.088 86.352 ;
     RECT  47.112 86.316 47.712 86.352 ;
     RECT  47.736 86.316 48.288 86.352 ;
     RECT  48.312 86.316 48.912 86.352 ;
     RECT  48.936 86.316 49.488 86.352 ;
     RECT  49.512 86.316 50.112 86.352 ;
     RECT  50.136 86.316 50.688 86.352 ;
     RECT  50.712 86.316 51.312 86.352 ;
     RECT  51.336 86.316 51.888 86.352 ;
     RECT  51.912 86.316 52.512 86.352 ;
     RECT  52.536 86.316 53.088 86.352 ;
     RECT  53.112 86.316 53.712 86.352 ;
     RECT  53.736 86.316 54.288 86.352 ;
     RECT  54.312 86.316 54.912 86.352 ;
     RECT  54.936 86.316 55.488 86.352 ;
     RECT  55.512 86.316 56.112 86.352 ;
     RECT  56.136 86.316 56.688 86.352 ;
     RECT  56.712 86.316 57.312 86.352 ;
     RECT  57.336 86.316 57.888 86.352 ;
     RECT  57.912 86.316 58.512 86.352 ;
     RECT  58.536 86.316 59.088 86.352 ;
     RECT  59.112 86.316 59.712 86.352 ;
     RECT  59.736 86.316 60.288 86.352 ;
     RECT  60.312 86.316 60.912 86.352 ;
     RECT  60.936 86.316 61.488 86.352 ;
     RECT  61.512 86.316 62.112 86.352 ;
     RECT  62.136 86.316 62.688 86.352 ;
     RECT  62.712 86.316 63.312 86.352 ;
     RECT  63.336 86.316 63.888 86.352 ;
     RECT  63.912 86.316 64.512 86.352 ;
     RECT  64.536 86.316 65.088 86.352 ;
     RECT  65.112 86.316 65.712 86.352 ;
     RECT  65.736 86.316 66.288 86.352 ;
     RECT  66.312 86.316 66.912 86.352 ;
     RECT  66.936 86.316 67.488 86.352 ;
     RECT  67.512 86.316 68.112 86.352 ;
     RECT  68.136 86.316 68.688 86.352 ;
     RECT  68.712 86.316 69.312 86.352 ;
     RECT  69.336 86.316 69.888 86.352 ;
     RECT  69.912 86.316 70.512 86.352 ;
     RECT  70.536 86.316 71.088 86.352 ;
     RECT  71.112 86.316 71.712 86.352 ;
     RECT  71.736 86.316 72.288 86.352 ;
     RECT  72.312 86.316 72.912 86.352 ;
     RECT  72.936 86.316 73.488 86.352 ;
     RECT  73.512 86.316 74.112 86.352 ;
     RECT  74.136 86.316 74.688 86.352 ;
     RECT  74.712 86.316 75.312 86.352 ;
     RECT  75.336 86.316 75.888 86.352 ;
     RECT  75.912 86.316 76.512 86.352 ;
     RECT  76.536 86.316 77.088 86.352 ;
     RECT  77.112 86.316 77.712 86.352 ;
     RECT  77.736 86.316 78.288 86.352 ;
     RECT  78.312 86.316 78.912 86.352 ;
     RECT  78.936 86.316 79.488 86.352 ;
     RECT  79.512 86.316 80.112 86.352 ;
     RECT  80.136 86.316 80.688 86.352 ;
     RECT  80.712 86.316 81.312 86.352 ;
     RECT  81.336 86.316 81.888 86.352 ;
     RECT  81.912 86.316 82.512 86.352 ;
     RECT  82.536 86.316 83.088 86.352 ;
     RECT  83.112 86.316 83.712 86.352 ;
     RECT  83.736 86.316 84.288 86.352 ;
     RECT  84.312 86.316 84.912 86.352 ;
     RECT  84.936 86.316 85.488 86.352 ;
     RECT  85.512 86.316 86.112 86.352 ;
     RECT  17.976 0.131 18.288 0.132 ;
     RECT  18.408 0.131 18.72 0.132 ;
     RECT  18.84 0.131 19.152 0.132 ;
     RECT  19.272 0.131 19.584 0.132 ;
     RECT  19.704 0.131 20.016 0.132 ;
     RECT  20.136 0.131 20.448 0.132 ;
     RECT  20.568 0.131 20.88 0.132 ;
     RECT  21 0.131 21.312 0.132 ;
     RECT  21.432 0.131 21.744 0.132 ;
     RECT  21.864 0.131 22.176 0.132 ;
     RECT  22.296 0.131 22.608 0.132 ;
     RECT  22.728 0.131 23.04 0.132 ;
     RECT  33.528 0.131 33.84 0.132 ;
     RECT  33.96 0.131 34.272 0.132 ;
     RECT  34.392 0.131 34.704 0.132 ;
     RECT  40.872 0.131 41.184 0.132 ;
     RECT  41.304 0.131 41.616 0.132 ;
     RECT  41.736 0.131 42.048 0.132 ;
     RECT  47.352 0.131 47.664 0.132 ;
     RECT  47.784 0.131 48.096 0.132 ;
     RECT  48.216 0.131 48.528 0.132 ;
     RECT  51.24 0.131 51.552 0.132 ;
     RECT  51.672 0.131 51.984 0.132 ;
     RECT  52.104 0.131 52.416 0.132 ;
     RECT  54.696 0.131 55.008 0.132 ;
     RECT  55.128 0.131 55.44 0.132 ;
     RECT  55.56 0.131 55.872 0.132 ;
     RECT  71.544 0.131 71.856 0.132 ;
     RECT  71.976 0.131 72.288 0.132 ;
     RECT  72.408 0.131 72.72 0.132 ;
     RECT  82.344 0.131 82.656 0.132 ;
     RECT  82.776 0.131 83.088 0.132 ;
     RECT  83.208 0.131 83.52 0.132 ;
     RECT  84.504 0.131 84.816 0.132 ;
     RECT  84.936 0.131 85.248 0.132 ;
     RECT  85.368 0.131 85.68 0.132 ;
     RECT  17.928 0.132 19.2 0.563 ;
     RECT  19.224 0.132 20.496 0.563 ;
     RECT  20.52 0.132 21.792 0.563 ;
     RECT  21.816 0.132 23.088 0.563 ;
     RECT  33.48 0.132 34.752 0.563 ;
     RECT  40.824 0.132 42.096 0.563 ;
     RECT  47.304 0.132 48.576 0.179 ;
     RECT  51.192 0.132 52.464 0.179 ;
     RECT  54.648 0.132 55.92 0.179 ;
     RECT  71.496 0.132 72.768 0.563 ;
     RECT  82.296 0.132 83.568 0.563 ;
     RECT  84.456 0.132 85.728 0.563 ;
     RECT  0.312 0.179 1.488 1.763 ;
     RECT  4.536 0.179 5.808 0.611 ;
     RECT  6.696 0.611 7.92 1.763 ;
     RECT  7.8 1.763 7.92 2.137 ;
     RECT  33.48 2.137 34.8 2.195 ;
     RECT  44.568 3.349 45.6 4.643 ;
     RECT  13.512 3.829 14.496 3.925 ;
     RECT  38.76 4.021 40.2 4.307 ;
     RECT  36.768 4.067 36.792 5.077 ;
     RECT  40.512 4.213 41.856 9.155 ;
     RECT  38.736 4.307 40.2 4.357 ;
     RECT  38.712 4.357 40.2 4.595 ;
     RECT  32.52 4.453 33.648 7.043 ;
     RECT  33.672 4.453 34.8 7.043 ;
     RECT  44.832 4.643 45.6 4.885 ;
     RECT  6.168 4.741 7.392 5.747 ;
     RECT  24.312 4.837 25.632 5.845 ;
     RECT  24.312 5.845 25.344 5.989 ;
     RECT  38.76 6.229 40.2 7.043 ;
     RECT  34.224 7.043 34.8 7.957 ;
     RECT  35.352 7.957 36.384 8.579 ;
     RECT  35.112 8.579 36.384 9.203 ;
     RECT  24.312 9.107 25.344 9.155 ;
     RECT  29.712 10.547 30.216 11.941 ;
     RECT  24.312 11.941 25.536 15.059 ;
     RECT  13.512 12.517 14.928 13.093 ;
     RECT  14.184 13.139 15.36 13.811 ;
     RECT  32.424 13.139 32.52 14.533 ;
     RECT  32.424 14.533 33.6 15.203 ;
     RECT  33.624 14.533 34.8 16.835 ;
     RECT  24.312 15.059 25.56 16.405 ;
     RECT  18.912 15.253 20.16 19.333 ;
     RECT  20.184 15.253 21.456 15.395 ;
     RECT  24.312 16.405 25.68 18.851 ;
     RECT  13.512 16.501 14.784 17.077 ;
     RECT  13.512 17.077 14.544 21.971 ;
     RECT  29.712 17.507 30.504 18.757 ;
     RECT  8.112 18.133 9.504 18.565 ;
     RECT  10.248 18.661 11.472 19.811 ;
     RECT  20.184 18.757 21.456 20.003 ;
     RECT  29.712 18.757 30.768 18.995 ;
     RECT  5.28 18.851 6.144 19.909 ;
     RECT  17.112 19.333 18.6 20.531 ;
     RECT  19.08 19.333 20.16 21.637 ;
     RECT  8.112 19.523 9.504 20.003 ;
     RECT  5.16 19.909 6.144 21.683 ;
     RECT  28.608 20.243 28.704 21.637 ;
     RECT  24.312 21.109 25.632 22.741 ;
     RECT  21.912 21.637 23.328 21.683 ;
     RECT  5.952 21.683 6.144 22.741 ;
     RECT  13.512 21.971 14.88 23.845 ;
     RECT  17.304 22.165 18.6 22.979 ;
     RECT  24.552 22.741 25.632 22.835 ;
     RECT  18.192 22.979 18.6 23.893 ;
     RECT  13.512 23.845 14.832 25.715 ;
     RECT  6.792 24.469 7.8 25.619 ;
     RECT  6.168 25.619 7.8 26.725 ;
     RECT  13.512 25.715 14.88 25.907 ;
     RECT  30.264 26.197 31.584 26.819 ;
     RECT  5.112 26.245 6.144 27.395 ;
     RECT  6.168 26.725 7.536 27.395 ;
     RECT  12.072 26.725 13.2 27.301 ;
     RECT  12.072 27.301 13.056 27.875 ;
     RECT  6.168 27.395 7.8 28.789 ;
     RECT  13.992 27.925 15.36 27.971 ;
     RECT  6.36 28.789 7.8 30.227 ;
     RECT  38.376 28.979 39.696 30.229 ;
     RECT  38.376 30.229 39.6 34.259 ;
     RECT  9.72 30.373 10.848 30.611 ;
     RECT  9.72 30.611 10.536 30.853 ;
     RECT  8.232 32.053 9.696 35.363 ;
     RECT  5.112 34.789 6.144 35.987 ;
     RECT  6.168 35.989 7.68 37.091 ;
     RECT  43.944 37.861 45.408 38.819 ;
     RECT  56.712 39.253 57.984 40.835 ;
     RECT  2.712 39.877 4.128 41.651 ;
     RECT  80.328 40.405 81.456 42.803 ;
     RECT  65.928 40.693 67.2 41.509 ;
     RECT  66.024 41.509 67.2 43.043 ;
     RECT  60.456 41.701 61.8 44.053 ;
     RECT  4.632 43.717 6.144 47.845 ;
     RECT  44.424 44.341 45.6 56.003 ;
     RECT  6.216 45.445 7.488 45.541 ;
     RECT  6.216 45.541 7.44 46.019 ;
     RECT  18.912 45.925 19.968 47.075 ;
     RECT  6.168 46.019 7.44 46.547 ;
     RECT  13.512 46.117 14.688 47.315 ;
     RECT  6.168 46.547 7.488 47.171 ;
     RECT  4.92 47.845 6.144 57.059 ;
     RECT  44.28 56.003 45.6 58.163 ;
     RECT  5.112 59.797 6.144 61.523 ;
     RECT  59.544 60.419 60.528 62.195 ;
     RECT  60.696 61.139 61.8 62.149 ;
     RECT  2.712 61.477 4.128 64.403 ;
     RECT  60.744 62.149 61.8 71.363 ;
     RECT  59.544 62.195 60.672 71.317 ;
     RECT  4.152 63.205 5.28 64.357 ;
     RECT  38.712 70.645 40.2 71.363 ;
     RECT  35.112 70.933 36.576 77.939 ;
     RECT  6.312 71.221 7.8 73.043 ;
     RECT  59.544 71.317 60.528 73.379 ;
     RECT  60.696 71.363 61.8 71.939 ;
     RECT  44.28 71.797 45.6 72.947 ;
     RECT  60.552 71.939 61.8 75.299 ;
     RECT  45.912 72.805 47.136 73.523 ;
     RECT  2.712 72.997 4.224 76.211 ;
     RECT  4.248 72.997 5.28 76.165 ;
     RECT  82.152 74.053 83.4 77.555 ;
     RECT  29.712 75.973 31.104 80.963 ;
     RECT  24.84 76.309 26.256 76.979 ;
     RECT  78.936 76.357 80.208 77.555 ;
     RECT  64.2 76.403 65.184 80.773 ;
     RECT  82.128 77.555 83.4 78.613 ;
     RECT  74.952 78.613 76.08 79.525 ;
     RECT  80.424 78.613 81.6 80.099 ;
     RECT  81.624 78.613 83.4 79.045 ;
     RECT  82.056 79.045 83.4 81.203 ;
     RECT  78.312 79.717 79.632 80.435 ;
     RECT  75.768 79.811 77.04 80.099 ;
     RECT  80.328 80.099 81.6 81.203 ;
     RECT  21.576 80.341 22.896 81.203 ;
     RECT  22.92 80.341 24 81.539 ;
     RECT  71.16 80.917 72.6 82.403 ;
     RECT  29.712 80.963 30.12 82.309 ;
     RECT  45.912 81.061 47.28 81.539 ;
     RECT  82.224 81.203 83.4 82.021 ;
     RECT  23.376 81.539 24 82.357 ;
     RECT  45.912 81.539 46.776 82.837 ;
     RECT  62.76 81.637 64.176 82.163 ;
     RECT  65.928 81.877 67.2 82.019 ;
     RECT  18.912 81.973 20.304 83.171 ;
     RECT  66.912 82.019 67.2 82.501 ;
     RECT  82.248 82.021 83.4 83.797 ;
     RECT  26.016 82.259 26.832 82.357 ;
     RECT  24.312 82.357 25.344 82.547 ;
     RECT  25.368 82.357 26.832 82.403 ;
     RECT  33.336 82.405 34.8 82.501 ;
     RECT  29.712 82.451 30.12 82.597 ;
     RECT  28.296 82.453 29.4 82.595 ;
     RECT  33.624 82.501 34.8 82.643 ;
     RECT  24.312 82.547 25.176 82.693 ;
     RECT  29.184 82.595 29.4 82.789 ;
     RECT  29.712 82.597 30.768 82.739 ;
     RECT  43.656 82.693 44.88 82.835 ;
     RECT  20.328 82.931 21.144 83.171 ;
     RECT  0.936 83.029 2.112 86.245 ;
     RECT  20.688 83.171 21.144 84.373 ;
     RECT  78.312 83.507 78.408 84.901 ;
     RECT  2.52 84.249 2.712 84.263 ;
     RECT  29.52 84.249 29.712 84.263 ;
     RECT  40.32 84.249 40.512 84.263 ;
     RECT  2.136 84.263 2.712 85.477 ;
     RECT  7.8 84.263 8.112 84.373 ;
     RECT  18.6 84.263 18.912 84.901 ;
     RECT  24 84.263 24.288 84.373 ;
     RECT  29.4 84.263 29.712 84.901 ;
     RECT  40.2 84.263 40.512 84.901 ;
     RECT  7.8 84.373 9.312 84.901 ;
     RECT  15.336 84.373 16.512 86.245 ;
     RECT  20.712 84.373 21.888 86.245 ;
     RECT  22.536 84.373 24.288 84.901 ;
     RECT  7.8 84.901 8.112 85.477 ;
     RECT  8.136 84.901 9.312 86.245 ;
     RECT  9.336 84.901 10.512 86.245 ;
     RECT  17.112 84.901 18.912 85.477 ;
     RECT  23.112 84.901 24.288 85.477 ;
     RECT  26.712 84.901 27.888 86.245 ;
     RECT  27.912 84.901 29.712 85.477 ;
     RECT  39.912 84.901 41.712 85.477 ;
     RECT  41.736 84.901 42.912 85.477 ;
     RECT  42.936 84.901 44.112 86.005 ;
     RECT  64.536 84.901 65.712 85.477 ;
     RECT  78.312 84.901 79.488 86.245 ;
     RECT  79.512 85.429 80.688 85.477 ;
     RECT  80.712 85.429 81.888 86.245 ;
     RECT  2.712 85.477 3.888 86.245 ;
     RECT  3.912 85.477 5.088 86.245 ;
     RECT  6.936 85.477 8.112 86.245 ;
     RECT  10.536 85.477 11.712 86.245 ;
     RECT  17.112 85.477 18.288 86.245 ;
     RECT  28.536 85.477 29.712 86.245 ;
     RECT  83.736 85.477 84.912 86.245 ;
     RECT  60.936 85.957 62.112 86.245 ;
     RECT  18.936 86.197 20.112 86.245 ;
     RECT  58.536 86.197 59.712 86.245 ;
     RECT  59.736 86.197 60.912 86.245 ;
  END
END ot_hgi_qdq_transport_ctl_r2
END LIBRARY
